VERSION 5.8 ;
BUSBITCHARS "[]" ;
DIVIDERCHAR "/" ;
UNITS
    DATABASE MICRONS 1000 ;
END UNITS

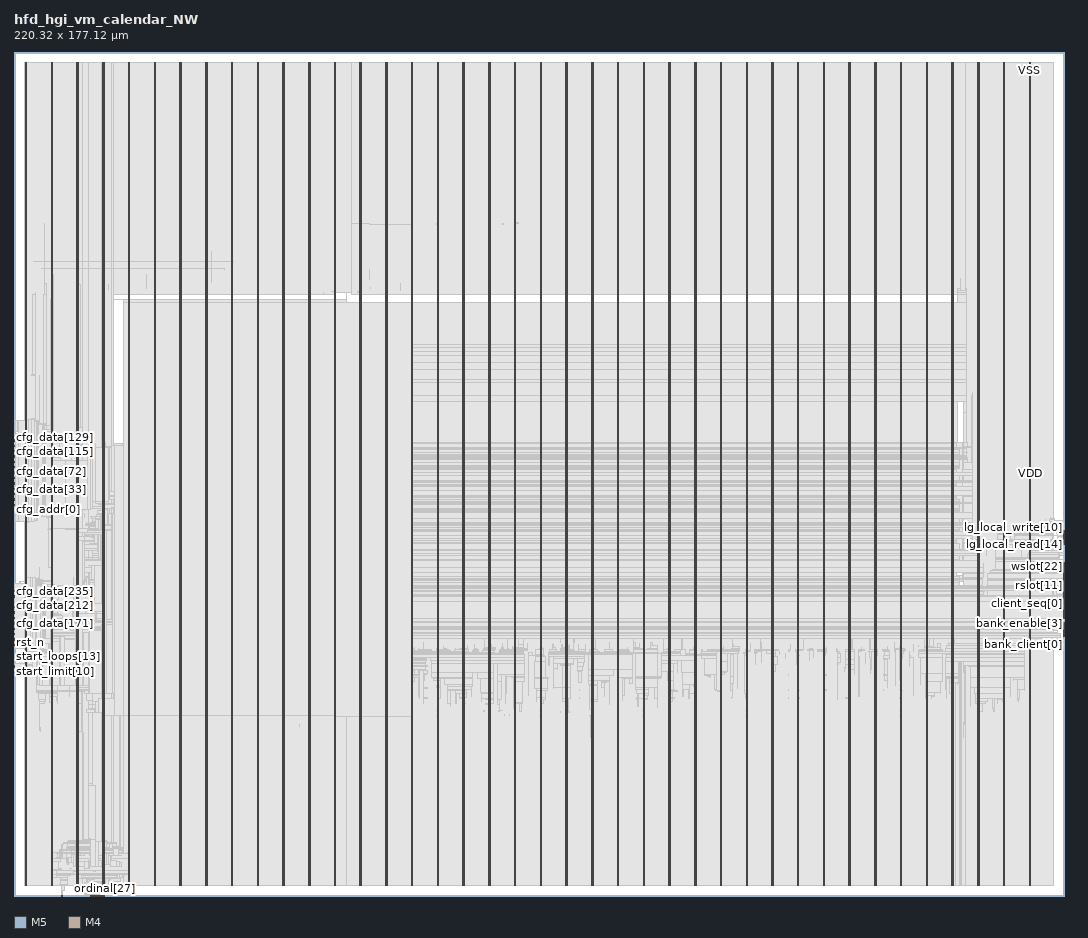
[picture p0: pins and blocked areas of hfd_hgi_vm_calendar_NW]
MACRO hfd_hgi_vm_calendar_NW
  FOREIGN hfd_hgi_vm_calendar_NW 0 0 ;
  CLASS BLOCK ;
  SIZE 220.32 BY 177.12 ;
  PIN active
    DIRECTION OUTPUT ;
    USE SIGNAL ;
    PORT
      LAYER M5 ;
        RECT  16.08 0 16.104 0.084 ;
    END
  END active
  PIN bank_client[0]
    DIRECTION OUTPUT ;
    USE SIGNAL ;
    PORT
      LAYER M4 ;
        RECT  220.236 54.48 220.32 54.504 ;
    END
  END bank_client[0]
  PIN bank_client[10]
    DIRECTION OUTPUT ;
    USE SIGNAL ;
    PORT
      LAYER M4 ;
        RECT  220.236 55.44 220.32 55.464 ;
    END
  END bank_client[10]
  PIN bank_client[11]
    DIRECTION OUTPUT ;
    USE SIGNAL ;
    PORT
      LAYER M4 ;
        RECT  220.236 55.536 220.32 55.56 ;
    END
  END bank_client[11]
  PIN bank_client[12]
    DIRECTION OUTPUT ;
    USE SIGNAL ;
    PORT
      LAYER M4 ;
        RECT  220.236 55.632 220.32 55.656 ;
    END
  END bank_client[12]
  PIN bank_client[13]
    DIRECTION OUTPUT ;
    USE SIGNAL ;
    PORT
      LAYER M4 ;
        RECT  220.236 55.728 220.32 55.752 ;
    END
  END bank_client[13]
  PIN bank_client[14]
    DIRECTION OUTPUT ;
    USE SIGNAL ;
    PORT
      LAYER M4 ;
        RECT  220.236 55.824 220.32 55.848 ;
    END
  END bank_client[14]
  PIN bank_client[15]
    DIRECTION OUTPUT ;
    USE SIGNAL ;
    PORT
      LAYER M4 ;
        RECT  220.236 55.92 220.32 55.944 ;
    END
  END bank_client[15]
  PIN bank_client[16]
    DIRECTION OUTPUT ;
    USE SIGNAL ;
    PORT
      LAYER M4 ;
        RECT  220.236 56.016 220.32 56.04 ;
    END
  END bank_client[16]
  PIN bank_client[17]
    DIRECTION OUTPUT ;
    USE SIGNAL ;
    PORT
      LAYER M4 ;
        RECT  220.236 56.112 220.32 56.136 ;
    END
  END bank_client[17]
  PIN bank_client[18]
    DIRECTION OUTPUT ;
    USE SIGNAL ;
    PORT
      LAYER M4 ;
        RECT  220.236 56.208 220.32 56.232 ;
    END
  END bank_client[18]
  PIN bank_client[19]
    DIRECTION OUTPUT ;
    USE SIGNAL ;
    PORT
      LAYER M4 ;
        RECT  220.236 56.304 220.32 56.328 ;
    END
  END bank_client[19]
  PIN bank_client[1]
    DIRECTION OUTPUT ;
    USE SIGNAL ;
    PORT
      LAYER M4 ;
        RECT  220.236 54.576 220.32 54.6 ;
    END
  END bank_client[1]
  PIN bank_client[20]
    DIRECTION OUTPUT ;
    USE SIGNAL ;
    PORT
      LAYER M4 ;
        RECT  220.236 56.4 220.32 56.424 ;
    END
  END bank_client[20]
  PIN bank_client[21]
    DIRECTION OUTPUT ;
    USE SIGNAL ;
    PORT
      LAYER M4 ;
        RECT  220.236 56.496 220.32 56.52 ;
    END
  END bank_client[21]
  PIN bank_client[22]
    DIRECTION OUTPUT ;
    USE SIGNAL ;
    PORT
      LAYER M4 ;
        RECT  220.236 56.592 220.32 56.616 ;
    END
  END bank_client[22]
  PIN bank_client[23]
    DIRECTION OUTPUT ;
    USE SIGNAL ;
    PORT
      LAYER M4 ;
        RECT  220.236 56.688 220.32 56.712 ;
    END
  END bank_client[23]
  PIN bank_client[2]
    DIRECTION OUTPUT ;
    USE SIGNAL ;
    PORT
      LAYER M4 ;
        RECT  220.236 54.672 220.32 54.696 ;
    END
  END bank_client[2]
  PIN bank_client[3]
    DIRECTION OUTPUT ;
    USE SIGNAL ;
    PORT
      LAYER M4 ;
        RECT  220.236 54.768 220.32 54.792 ;
    END
  END bank_client[3]
  PIN bank_client[4]
    DIRECTION OUTPUT ;
    USE SIGNAL ;
    PORT
      LAYER M4 ;
        RECT  220.236 54.864 220.32 54.888 ;
    END
  END bank_client[4]
  PIN bank_client[5]
    DIRECTION OUTPUT ;
    USE SIGNAL ;
    PORT
      LAYER M4 ;
        RECT  220.236 54.96 220.32 54.984 ;
    END
  END bank_client[5]
  PIN bank_client[6]
    DIRECTION OUTPUT ;
    USE SIGNAL ;
    PORT
      LAYER M4 ;
        RECT  220.236 55.056 220.32 55.08 ;
    END
  END bank_client[6]
  PIN bank_client[7]
    DIRECTION OUTPUT ;
    USE SIGNAL ;
    PORT
      LAYER M4 ;
        RECT  220.236 55.152 220.32 55.176 ;
    END
  END bank_client[7]
  PIN bank_client[8]
    DIRECTION OUTPUT ;
    USE SIGNAL ;
    PORT
      LAYER M4 ;
        RECT  220.236 55.248 220.32 55.272 ;
    END
  END bank_client[8]
  PIN bank_client[9]
    DIRECTION OUTPUT ;
    USE SIGNAL ;
    PORT
      LAYER M4 ;
        RECT  220.236 55.344 220.32 55.368 ;
    END
  END bank_client[9]
  PIN bank_enable[0]
    DIRECTION OUTPUT ;
    USE SIGNAL ;
    PORT
      LAYER M4 ;
        RECT  220.236 56.784 220.32 56.808 ;
    END
  END bank_enable[0]
  PIN bank_enable[1]
    DIRECTION OUTPUT ;
    USE SIGNAL ;
    PORT
      LAYER M4 ;
        RECT  220.236 56.88 220.32 56.904 ;
    END
  END bank_enable[1]
  PIN bank_enable[2]
    DIRECTION OUTPUT ;
    USE SIGNAL ;
    PORT
      LAYER M4 ;
        RECT  220.236 56.976 220.32 57 ;
    END
  END bank_enable[2]
  PIN bank_enable[3]
    DIRECTION OUTPUT ;
    USE SIGNAL ;
    PORT
      LAYER M4 ;
        RECT  220.236 57.072 220.32 57.096 ;
    END
  END bank_enable[3]
  PIN bank_enable[4]
    DIRECTION OUTPUT ;
    USE SIGNAL ;
    PORT
      LAYER M4 ;
        RECT  220.236 57.168 220.32 57.192 ;
    END
  END bank_enable[4]
  PIN bank_enable[5]
    DIRECTION OUTPUT ;
    USE SIGNAL ;
    PORT
      LAYER M4 ;
        RECT  220.236 57.264 220.32 57.288 ;
    END
  END bank_enable[5]
  PIN bank_enable[6]
    DIRECTION OUTPUT ;
    USE SIGNAL ;
    PORT
      LAYER M4 ;
        RECT  220.236 57.36 220.32 57.384 ;
    END
  END bank_enable[6]
  PIN bank_enable[7]
    DIRECTION OUTPUT ;
    USE SIGNAL ;
    PORT
      LAYER M4 ;
        RECT  220.236 57.456 220.32 57.48 ;
    END
  END bank_enable[7]
  PIN calendar_v
    DIRECTION OUTPUT ;
    USE SIGNAL ;
    PORT
      LAYER M5 ;
        RECT  16.176 0 16.2 0.084 ;
    END
  END calendar_v
  PIN cfg_addr[0]
    DIRECTION INPUT ;
    USE SIGNAL ;
    PORT
      LAYER M4 ;
        RECT  0 81.168 0.084 81.192 ;
    END
  END cfg_addr[0]
  PIN cfg_addr[1]
    DIRECTION INPUT ;
    USE SIGNAL ;
    PORT
      LAYER M4 ;
        RECT  0 81.264 0.084 81.288 ;
    END
  END cfg_addr[1]
  PIN cfg_addr[2]
    DIRECTION INPUT ;
    USE SIGNAL ;
    PORT
      LAYER M4 ;
        RECT  0 81.36 0.084 81.384 ;
    END
  END cfg_addr[2]
  PIN cfg_addr[3]
    DIRECTION INPUT ;
    USE SIGNAL ;
    PORT
      LAYER M4 ;
        RECT  0 81.456 0.084 81.48 ;
    END
  END cfg_addr[3]
  PIN cfg_addr[4]
    DIRECTION INPUT ;
    USE SIGNAL ;
    PORT
      LAYER M4 ;
        RECT  0 81.552 0.084 81.576 ;
    END
  END cfg_addr[4]
  PIN cfg_addr[5]
    DIRECTION INPUT ;
    USE SIGNAL ;
    PORT
      LAYER M4 ;
        RECT  0 81.648 0.084 81.672 ;
    END
  END cfg_addr[5]
  PIN cfg_addr[6]
    DIRECTION INPUT ;
    USE SIGNAL ;
    PORT
      LAYER M4 ;
        RECT  0 81.744 0.084 81.768 ;
    END
  END cfg_addr[6]
  PIN cfg_addr[7]
    DIRECTION INPUT ;
    USE SIGNAL ;
    PORT
      LAYER M4 ;
        RECT  0 81.84 0.084 81.864 ;
    END
  END cfg_addr[7]
  PIN cfg_addr[8]
    DIRECTION INPUT ;
    USE SIGNAL ;
    PORT
      LAYER M4 ;
        RECT  0 81.936 0.084 81.96 ;
    END
  END cfg_addr[8]
  PIN cfg_addr[9]
    DIRECTION INPUT ;
    USE SIGNAL ;
    PORT
      LAYER M4 ;
        RECT  0 82.032 0.084 82.056 ;
    END
  END cfg_addr[9]
  PIN cfg_data[0]
    DIRECTION INPUT ;
    USE SIGNAL ;
    PORT
      LAYER M4 ;
        RECT  0 82.128 0.084 82.152 ;
    END
  END cfg_data[0]
  PIN cfg_data[100]
    DIRECTION INPUT ;
    USE SIGNAL ;
    PORT
      LAYER M4 ;
        RECT  0 91.728 0.084 91.752 ;
    END
  END cfg_data[100]
  PIN cfg_data[101]
    DIRECTION INPUT ;
    USE SIGNAL ;
    PORT
      LAYER M4 ;
        RECT  0 91.824 0.084 91.848 ;
    END
  END cfg_data[101]
  PIN cfg_data[102]
    DIRECTION INPUT ;
    USE SIGNAL ;
    PORT
      LAYER M4 ;
        RECT  0 91.92 0.084 91.944 ;
    END
  END cfg_data[102]
  PIN cfg_data[103]
    DIRECTION INPUT ;
    USE SIGNAL ;
    PORT
      LAYER M4 ;
        RECT  0 92.016 0.084 92.04 ;
    END
  END cfg_data[103]
  PIN cfg_data[104]
    DIRECTION INPUT ;
    USE SIGNAL ;
    PORT
      LAYER M4 ;
        RECT  0 92.112 0.084 92.136 ;
    END
  END cfg_data[104]
  PIN cfg_data[105]
    DIRECTION INPUT ;
    USE SIGNAL ;
    PORT
      LAYER M4 ;
        RECT  0 92.208 0.084 92.232 ;
    END
  END cfg_data[105]
  PIN cfg_data[106]
    DIRECTION INPUT ;
    USE SIGNAL ;
    PORT
      LAYER M4 ;
        RECT  0 92.304 0.084 92.328 ;
    END
  END cfg_data[106]
  PIN cfg_data[107]
    DIRECTION INPUT ;
    USE SIGNAL ;
    PORT
      LAYER M4 ;
        RECT  0 92.4 0.084 92.424 ;
    END
  END cfg_data[107]
  PIN cfg_data[108]
    DIRECTION INPUT ;
    USE SIGNAL ;
    PORT
      LAYER M4 ;
        RECT  0 92.496 0.084 92.52 ;
    END
  END cfg_data[108]
  PIN cfg_data[109]
    DIRECTION INPUT ;
    USE SIGNAL ;
    PORT
      LAYER M4 ;
        RECT  0 92.592 0.084 92.616 ;
    END
  END cfg_data[109]
  PIN cfg_data[10]
    DIRECTION INPUT ;
    USE SIGNAL ;
    PORT
      LAYER M4 ;
        RECT  0 83.088 0.084 83.112 ;
    END
  END cfg_data[10]
  PIN cfg_data[110]
    DIRECTION INPUT ;
    USE SIGNAL ;
    PORT
      LAYER M4 ;
        RECT  0 92.688 0.084 92.712 ;
    END
  END cfg_data[110]
  PIN cfg_data[111]
    DIRECTION INPUT ;
    USE SIGNAL ;
    PORT
      LAYER M4 ;
        RECT  0 92.784 0.084 92.808 ;
    END
  END cfg_data[111]
  PIN cfg_data[112]
    DIRECTION INPUT ;
    USE SIGNAL ;
    PORT
      LAYER M4 ;
        RECT  0 92.88 0.084 92.904 ;
    END
  END cfg_data[112]
  PIN cfg_data[113]
    DIRECTION INPUT ;
    USE SIGNAL ;
    PORT
      LAYER M4 ;
        RECT  0 92.976 0.084 93 ;
    END
  END cfg_data[113]
  PIN cfg_data[114]
    DIRECTION INPUT ;
    USE SIGNAL ;
    PORT
      LAYER M4 ;
        RECT  0 93.072 0.084 93.096 ;
    END
  END cfg_data[114]
  PIN cfg_data[115]
    DIRECTION INPUT ;
    USE SIGNAL ;
    PORT
      LAYER M4 ;
        RECT  0 93.168 0.084 93.192 ;
    END
  END cfg_data[115]
  PIN cfg_data[116]
    DIRECTION INPUT ;
    USE SIGNAL ;
    PORT
      LAYER M4 ;
        RECT  0 93.264 0.084 93.288 ;
    END
  END cfg_data[116]
  PIN cfg_data[117]
    DIRECTION INPUT ;
    USE SIGNAL ;
    PORT
      LAYER M4 ;
        RECT  0 93.36 0.084 93.384 ;
    END
  END cfg_data[117]
  PIN cfg_data[118]
    DIRECTION INPUT ;
    USE SIGNAL ;
    PORT
      LAYER M4 ;
        RECT  0 93.456 0.084 93.48 ;
    END
  END cfg_data[118]
  PIN cfg_data[119]
    DIRECTION INPUT ;
    USE SIGNAL ;
    PORT
      LAYER M4 ;
        RECT  0 93.552 0.084 93.576 ;
    END
  END cfg_data[119]
  PIN cfg_data[11]
    DIRECTION INPUT ;
    USE SIGNAL ;
    PORT
      LAYER M4 ;
        RECT  0 83.184 0.084 83.208 ;
    END
  END cfg_data[11]
  PIN cfg_data[120]
    DIRECTION INPUT ;
    USE SIGNAL ;
    PORT
      LAYER M4 ;
        RECT  0 93.648 0.084 93.672 ;
    END
  END cfg_data[120]
  PIN cfg_data[121]
    DIRECTION INPUT ;
    USE SIGNAL ;
    PORT
      LAYER M4 ;
        RECT  0 93.744 0.084 93.768 ;
    END
  END cfg_data[121]
  PIN cfg_data[122]
    DIRECTION INPUT ;
    USE SIGNAL ;
    PORT
      LAYER M4 ;
        RECT  0 93.84 0.084 93.864 ;
    END
  END cfg_data[122]
  PIN cfg_data[123]
    DIRECTION INPUT ;
    USE SIGNAL ;
    PORT
      LAYER M4 ;
        RECT  0 93.936 0.084 93.96 ;
    END
  END cfg_data[123]
  PIN cfg_data[124]
    DIRECTION INPUT ;
    USE SIGNAL ;
    PORT
      LAYER M4 ;
        RECT  0 94.032 0.084 94.056 ;
    END
  END cfg_data[124]
  PIN cfg_data[125]
    DIRECTION INPUT ;
    USE SIGNAL ;
    PORT
      LAYER M4 ;
        RECT  0 94.128 0.084 94.152 ;
    END
  END cfg_data[125]
  PIN cfg_data[126]
    DIRECTION INPUT ;
    USE SIGNAL ;
    PORT
      LAYER M4 ;
        RECT  0 94.224 0.084 94.248 ;
    END
  END cfg_data[126]
  PIN cfg_data[127]
    DIRECTION INPUT ;
    USE SIGNAL ;
    PORT
      LAYER M4 ;
        RECT  0 94.32 0.084 94.344 ;
    END
  END cfg_data[127]
  PIN cfg_data[128]
    DIRECTION INPUT ;
    USE SIGNAL ;
    PORT
      LAYER M4 ;
        RECT  0 94.416 0.084 94.44 ;
    END
  END cfg_data[128]
  PIN cfg_data[129]
    DIRECTION INPUT ;
    USE SIGNAL ;
    PORT
      LAYER M4 ;
        RECT  0 94.512 0.084 94.536 ;
    END
  END cfg_data[129]
  PIN cfg_data[12]
    DIRECTION INPUT ;
    USE SIGNAL ;
    PORT
      LAYER M4 ;
        RECT  0 83.28 0.084 83.304 ;
    END
  END cfg_data[12]
  PIN cfg_data[130]
    DIRECTION INPUT ;
    USE SIGNAL ;
    PORT
      LAYER M4 ;
        RECT  0 94.608 0.084 94.632 ;
    END
  END cfg_data[130]
  PIN cfg_data[131]
    DIRECTION INPUT ;
    USE SIGNAL ;
    PORT
      LAYER M4 ;
        RECT  0 94.704 0.084 94.728 ;
    END
  END cfg_data[131]
  PIN cfg_data[132]
    DIRECTION INPUT ;
    USE SIGNAL ;
    PORT
      LAYER M4 ;
        RECT  0 94.8 0.084 94.824 ;
    END
  END cfg_data[132]
  PIN cfg_data[133]
    DIRECTION INPUT ;
    USE SIGNAL ;
    PORT
      LAYER M4 ;
        RECT  0 94.896 0.084 94.92 ;
    END
  END cfg_data[133]
  PIN cfg_data[134]
    DIRECTION INPUT ;
    USE SIGNAL ;
    PORT
      LAYER M4 ;
        RECT  0 94.992 0.084 95.016 ;
    END
  END cfg_data[134]
  PIN cfg_data[135]
    DIRECTION INPUT ;
    USE SIGNAL ;
    PORT
      LAYER M4 ;
        RECT  0 95.088 0.084 95.112 ;
    END
  END cfg_data[135]
  PIN cfg_data[136]
    DIRECTION INPUT ;
    USE SIGNAL ;
    PORT
      LAYER M4 ;
        RECT  0 95.184 0.084 95.208 ;
    END
  END cfg_data[136]
  PIN cfg_data[137]
    DIRECTION INPUT ;
    USE SIGNAL ;
    PORT
      LAYER M4 ;
        RECT  0 95.28 0.084 95.304 ;
    END
  END cfg_data[137]
  PIN cfg_data[138]
    DIRECTION INPUT ;
    USE SIGNAL ;
    PORT
      LAYER M4 ;
        RECT  0 95.376 0.084 95.4 ;
    END
  END cfg_data[138]
  PIN cfg_data[139]
    DIRECTION INPUT ;
    USE SIGNAL ;
    PORT
      LAYER M4 ;
        RECT  0 95.472 0.084 95.496 ;
    END
  END cfg_data[139]
  PIN cfg_data[13]
    DIRECTION INPUT ;
    USE SIGNAL ;
    PORT
      LAYER M4 ;
        RECT  0 83.376 0.084 83.4 ;
    END
  END cfg_data[13]
  PIN cfg_data[140]
    DIRECTION INPUT ;
    USE SIGNAL ;
    PORT
      LAYER M4 ;
        RECT  0 95.568 0.084 95.592 ;
    END
  END cfg_data[140]
  PIN cfg_data[141]
    DIRECTION INPUT ;
    USE SIGNAL ;
    PORT
      LAYER M4 ;
        RECT  0 95.664 0.084 95.688 ;
    END
  END cfg_data[141]
  PIN cfg_data[142]
    DIRECTION INPUT ;
    USE SIGNAL ;
    PORT
      LAYER M4 ;
        RECT  0 95.76 0.084 95.784 ;
    END
  END cfg_data[142]
  PIN cfg_data[143]
    DIRECTION INPUT ;
    USE SIGNAL ;
    PORT
      LAYER M4 ;
        RECT  0 95.856 0.084 95.88 ;
    END
  END cfg_data[143]
  PIN cfg_data[144]
    DIRECTION INPUT ;
    USE SIGNAL ;
    PORT
      LAYER M4 ;
        RECT  0 95.952 0.084 95.976 ;
    END
  END cfg_data[144]
  PIN cfg_data[145]
    DIRECTION INPUT ;
    USE SIGNAL ;
    PORT
      LAYER M4 ;
        RECT  0 96.048 0.084 96.072 ;
    END
  END cfg_data[145]
  PIN cfg_data[146]
    DIRECTION INPUT ;
    USE SIGNAL ;
    PORT
      LAYER M4 ;
        RECT  0 96.144 0.084 96.168 ;
    END
  END cfg_data[146]
  PIN cfg_data[147]
    DIRECTION INPUT ;
    USE SIGNAL ;
    PORT
      LAYER M4 ;
        RECT  0 96.24 0.084 96.264 ;
    END
  END cfg_data[147]
  PIN cfg_data[148]
    DIRECTION INPUT ;
    USE SIGNAL ;
    PORT
      LAYER M4 ;
        RECT  0 96.336 0.084 96.36 ;
    END
  END cfg_data[148]
  PIN cfg_data[149]
    DIRECTION INPUT ;
    USE SIGNAL ;
    PORT
      LAYER M4 ;
        RECT  0 96.432 0.084 96.456 ;
    END
  END cfg_data[149]
  PIN cfg_data[14]
    DIRECTION INPUT ;
    USE SIGNAL ;
    PORT
      LAYER M4 ;
        RECT  0 83.472 0.084 83.496 ;
    END
  END cfg_data[14]
  PIN cfg_data[150]
    DIRECTION INPUT ;
    USE SIGNAL ;
    PORT
      LAYER M4 ;
        RECT  0 55.056 0.084 55.08 ;
    END
  END cfg_data[150]
  PIN cfg_data[151]
    DIRECTION INPUT ;
    USE SIGNAL ;
    PORT
      LAYER M4 ;
        RECT  0 55.152 0.084 55.176 ;
    END
  END cfg_data[151]
  PIN cfg_data[152]
    DIRECTION INPUT ;
    USE SIGNAL ;
    PORT
      LAYER M4 ;
        RECT  0 55.248 0.084 55.272 ;
    END
  END cfg_data[152]
  PIN cfg_data[153]
    DIRECTION INPUT ;
    USE SIGNAL ;
    PORT
      LAYER M4 ;
        RECT  0 55.344 0.084 55.368 ;
    END
  END cfg_data[153]
  PIN cfg_data[154]
    DIRECTION INPUT ;
    USE SIGNAL ;
    PORT
      LAYER M4 ;
        RECT  0 55.44 0.084 55.464 ;
    END
  END cfg_data[154]
  PIN cfg_data[155]
    DIRECTION INPUT ;
    USE SIGNAL ;
    PORT
      LAYER M4 ;
        RECT  0 55.536 0.084 55.56 ;
    END
  END cfg_data[155]
  PIN cfg_data[156]
    DIRECTION INPUT ;
    USE SIGNAL ;
    PORT
      LAYER M4 ;
        RECT  0 55.632 0.084 55.656 ;
    END
  END cfg_data[156]
  PIN cfg_data[157]
    DIRECTION INPUT ;
    USE SIGNAL ;
    PORT
      LAYER M4 ;
        RECT  0 55.728 0.084 55.752 ;
    END
  END cfg_data[157]
  PIN cfg_data[158]
    DIRECTION INPUT ;
    USE SIGNAL ;
    PORT
      LAYER M4 ;
        RECT  0 55.824 0.084 55.848 ;
    END
  END cfg_data[158]
  PIN cfg_data[159]
    DIRECTION INPUT ;
    USE SIGNAL ;
    PORT
      LAYER M4 ;
        RECT  0 55.92 0.084 55.944 ;
    END
  END cfg_data[159]
  PIN cfg_data[15]
    DIRECTION INPUT ;
    USE SIGNAL ;
    PORT
      LAYER M4 ;
        RECT  0 83.568 0.084 83.592 ;
    END
  END cfg_data[15]
  PIN cfg_data[160]
    DIRECTION INPUT ;
    USE SIGNAL ;
    PORT
      LAYER M4 ;
        RECT  0 56.016 0.084 56.04 ;
    END
  END cfg_data[160]
  PIN cfg_data[161]
    DIRECTION INPUT ;
    USE SIGNAL ;
    PORT
      LAYER M4 ;
        RECT  0 56.112 0.084 56.136 ;
    END
  END cfg_data[161]
  PIN cfg_data[162]
    DIRECTION INPUT ;
    USE SIGNAL ;
    PORT
      LAYER M4 ;
        RECT  0 56.208 0.084 56.232 ;
    END
  END cfg_data[162]
  PIN cfg_data[163]
    DIRECTION INPUT ;
    USE SIGNAL ;
    PORT
      LAYER M4 ;
        RECT  0 56.304 0.084 56.328 ;
    END
  END cfg_data[163]
  PIN cfg_data[164]
    DIRECTION INPUT ;
    USE SIGNAL ;
    PORT
      LAYER M4 ;
        RECT  0 56.4 0.084 56.424 ;
    END
  END cfg_data[164]
  PIN cfg_data[165]
    DIRECTION INPUT ;
    USE SIGNAL ;
    PORT
      LAYER M4 ;
        RECT  0 56.496 0.084 56.52 ;
    END
  END cfg_data[165]
  PIN cfg_data[166]
    DIRECTION INPUT ;
    USE SIGNAL ;
    PORT
      LAYER M4 ;
        RECT  0 56.592 0.084 56.616 ;
    END
  END cfg_data[166]
  PIN cfg_data[167]
    DIRECTION INPUT ;
    USE SIGNAL ;
    PORT
      LAYER M4 ;
        RECT  0 56.688 0.084 56.712 ;
    END
  END cfg_data[167]
  PIN cfg_data[168]
    DIRECTION INPUT ;
    USE SIGNAL ;
    PORT
      LAYER M4 ;
        RECT  0 56.784 0.084 56.808 ;
    END
  END cfg_data[168]
  PIN cfg_data[169]
    DIRECTION INPUT ;
    USE SIGNAL ;
    PORT
      LAYER M4 ;
        RECT  0 56.88 0.084 56.904 ;
    END
  END cfg_data[169]
  PIN cfg_data[16]
    DIRECTION INPUT ;
    USE SIGNAL ;
    PORT
      LAYER M4 ;
        RECT  0 83.664 0.084 83.688 ;
    END
  END cfg_data[16]
  PIN cfg_data[170]
    DIRECTION INPUT ;
    USE SIGNAL ;
    PORT
      LAYER M4 ;
        RECT  0 56.976 0.084 57 ;
    END
  END cfg_data[170]
  PIN cfg_data[171]
    DIRECTION INPUT ;
    USE SIGNAL ;
    PORT
      LAYER M4 ;
        RECT  0 57.072 0.084 57.096 ;
    END
  END cfg_data[171]
  PIN cfg_data[172]
    DIRECTION INPUT ;
    USE SIGNAL ;
    PORT
      LAYER M4 ;
        RECT  0 57.168 0.084 57.192 ;
    END
  END cfg_data[172]
  PIN cfg_data[173]
    DIRECTION INPUT ;
    USE SIGNAL ;
    PORT
      LAYER M4 ;
        RECT  0 57.264 0.084 57.288 ;
    END
  END cfg_data[173]
  PIN cfg_data[174]
    DIRECTION INPUT ;
    USE SIGNAL ;
    PORT
      LAYER M4 ;
        RECT  0 57.36 0.084 57.384 ;
    END
  END cfg_data[174]
  PIN cfg_data[175]
    DIRECTION INPUT ;
    USE SIGNAL ;
    PORT
      LAYER M4 ;
        RECT  0 57.456 0.084 57.48 ;
    END
  END cfg_data[175]
  PIN cfg_data[176]
    DIRECTION INPUT ;
    USE SIGNAL ;
    PORT
      LAYER M4 ;
        RECT  0 57.552 0.084 57.576 ;
    END
  END cfg_data[176]
  PIN cfg_data[177]
    DIRECTION INPUT ;
    USE SIGNAL ;
    PORT
      LAYER M4 ;
        RECT  0 57.648 0.084 57.672 ;
    END
  END cfg_data[177]
  PIN cfg_data[178]
    DIRECTION INPUT ;
    USE SIGNAL ;
    PORT
      LAYER M4 ;
        RECT  0 57.744 0.084 57.768 ;
    END
  END cfg_data[178]
  PIN cfg_data[179]
    DIRECTION INPUT ;
    USE SIGNAL ;
    PORT
      LAYER M4 ;
        RECT  0 57.84 0.084 57.864 ;
    END
  END cfg_data[179]
  PIN cfg_data[17]
    DIRECTION INPUT ;
    USE SIGNAL ;
    PORT
      LAYER M4 ;
        RECT  0 83.76 0.084 83.784 ;
    END
  END cfg_data[17]
  PIN cfg_data[180]
    DIRECTION INPUT ;
    USE SIGNAL ;
    PORT
      LAYER M4 ;
        RECT  0 57.936 0.084 57.96 ;
    END
  END cfg_data[180]
  PIN cfg_data[181]
    DIRECTION INPUT ;
    USE SIGNAL ;
    PORT
      LAYER M4 ;
        RECT  0 58.032 0.084 58.056 ;
    END
  END cfg_data[181]
  PIN cfg_data[182]
    DIRECTION INPUT ;
    USE SIGNAL ;
    PORT
      LAYER M4 ;
        RECT  0 58.128 0.084 58.152 ;
    END
  END cfg_data[182]
  PIN cfg_data[183]
    DIRECTION INPUT ;
    USE SIGNAL ;
    PORT
      LAYER M4 ;
        RECT  0 58.224 0.084 58.248 ;
    END
  END cfg_data[183]
  PIN cfg_data[184]
    DIRECTION INPUT ;
    USE SIGNAL ;
    PORT
      LAYER M4 ;
        RECT  0 58.32 0.084 58.344 ;
    END
  END cfg_data[184]
  PIN cfg_data[185]
    DIRECTION INPUT ;
    USE SIGNAL ;
    PORT
      LAYER M4 ;
        RECT  0 58.416 0.084 58.44 ;
    END
  END cfg_data[185]
  PIN cfg_data[186]
    DIRECTION INPUT ;
    USE SIGNAL ;
    PORT
      LAYER M4 ;
        RECT  0 58.512 0.084 58.536 ;
    END
  END cfg_data[186]
  PIN cfg_data[187]
    DIRECTION INPUT ;
    USE SIGNAL ;
    PORT
      LAYER M4 ;
        RECT  0 58.608 0.084 58.632 ;
    END
  END cfg_data[187]
  PIN cfg_data[188]
    DIRECTION INPUT ;
    USE SIGNAL ;
    PORT
      LAYER M4 ;
        RECT  0 58.704 0.084 58.728 ;
    END
  END cfg_data[188]
  PIN cfg_data[189]
    DIRECTION INPUT ;
    USE SIGNAL ;
    PORT
      LAYER M4 ;
        RECT  0 58.8 0.084 58.824 ;
    END
  END cfg_data[189]
  PIN cfg_data[18]
    DIRECTION INPUT ;
    USE SIGNAL ;
    PORT
      LAYER M4 ;
        RECT  0 83.856 0.084 83.88 ;
    END
  END cfg_data[18]
  PIN cfg_data[190]
    DIRECTION INPUT ;
    USE SIGNAL ;
    PORT
      LAYER M4 ;
        RECT  0 58.896 0.084 58.92 ;
    END
  END cfg_data[190]
  PIN cfg_data[191]
    DIRECTION INPUT ;
    USE SIGNAL ;
    PORT
      LAYER M4 ;
        RECT  0 58.992 0.084 59.016 ;
    END
  END cfg_data[191]
  PIN cfg_data[192]
    DIRECTION INPUT ;
    USE SIGNAL ;
    PORT
      LAYER M4 ;
        RECT  0 59.088 0.084 59.112 ;
    END
  END cfg_data[192]
  PIN cfg_data[193]
    DIRECTION INPUT ;
    USE SIGNAL ;
    PORT
      LAYER M4 ;
        RECT  0 59.184 0.084 59.208 ;
    END
  END cfg_data[193]
  PIN cfg_data[194]
    DIRECTION INPUT ;
    USE SIGNAL ;
    PORT
      LAYER M4 ;
        RECT  0 59.28 0.084 59.304 ;
    END
  END cfg_data[194]
  PIN cfg_data[195]
    DIRECTION INPUT ;
    USE SIGNAL ;
    PORT
      LAYER M4 ;
        RECT  0 59.376 0.084 59.4 ;
    END
  END cfg_data[195]
  PIN cfg_data[196]
    DIRECTION INPUT ;
    USE SIGNAL ;
    PORT
      LAYER M4 ;
        RECT  0 59.472 0.084 59.496 ;
    END
  END cfg_data[196]
  PIN cfg_data[197]
    DIRECTION INPUT ;
    USE SIGNAL ;
    PORT
      LAYER M4 ;
        RECT  0 59.568 0.084 59.592 ;
    END
  END cfg_data[197]
  PIN cfg_data[198]
    DIRECTION INPUT ;
    USE SIGNAL ;
    PORT
      LAYER M4 ;
        RECT  0 59.664 0.084 59.688 ;
    END
  END cfg_data[198]
  PIN cfg_data[199]
    DIRECTION INPUT ;
    USE SIGNAL ;
    PORT
      LAYER M4 ;
        RECT  0 59.76 0.084 59.784 ;
    END
  END cfg_data[199]
  PIN cfg_data[19]
    DIRECTION INPUT ;
    USE SIGNAL ;
    PORT
      LAYER M4 ;
        RECT  0 83.952 0.084 83.976 ;
    END
  END cfg_data[19]
  PIN cfg_data[1]
    DIRECTION INPUT ;
    USE SIGNAL ;
    PORT
      LAYER M4 ;
        RECT  0 82.224 0.084 82.248 ;
    END
  END cfg_data[1]
  PIN cfg_data[200]
    DIRECTION INPUT ;
    USE SIGNAL ;
    PORT
      LAYER M4 ;
        RECT  0 59.856 0.084 59.88 ;
    END
  END cfg_data[200]
  PIN cfg_data[201]
    DIRECTION INPUT ;
    USE SIGNAL ;
    PORT
      LAYER M4 ;
        RECT  0 59.952 0.084 59.976 ;
    END
  END cfg_data[201]
  PIN cfg_data[202]
    DIRECTION INPUT ;
    USE SIGNAL ;
    PORT
      LAYER M4 ;
        RECT  0 60.048 0.084 60.072 ;
    END
  END cfg_data[202]
  PIN cfg_data[203]
    DIRECTION INPUT ;
    USE SIGNAL ;
    PORT
      LAYER M4 ;
        RECT  0 60.144 0.084 60.168 ;
    END
  END cfg_data[203]
  PIN cfg_data[204]
    DIRECTION INPUT ;
    USE SIGNAL ;
    PORT
      LAYER M4 ;
        RECT  0 60.24 0.084 60.264 ;
    END
  END cfg_data[204]
  PIN cfg_data[205]
    DIRECTION INPUT ;
    USE SIGNAL ;
    PORT
      LAYER M4 ;
        RECT  0 60.336 0.084 60.36 ;
    END
  END cfg_data[205]
  PIN cfg_data[206]
    DIRECTION INPUT ;
    USE SIGNAL ;
    PORT
      LAYER M4 ;
        RECT  0 60.432 0.084 60.456 ;
    END
  END cfg_data[206]
  PIN cfg_data[207]
    DIRECTION INPUT ;
    USE SIGNAL ;
    PORT
      LAYER M4 ;
        RECT  0 60.528 0.084 60.552 ;
    END
  END cfg_data[207]
  PIN cfg_data[208]
    DIRECTION INPUT ;
    USE SIGNAL ;
    PORT
      LAYER M4 ;
        RECT  0 60.624 0.084 60.648 ;
    END
  END cfg_data[208]
  PIN cfg_data[209]
    DIRECTION INPUT ;
    USE SIGNAL ;
    PORT
      LAYER M4 ;
        RECT  0 60.72 0.084 60.744 ;
    END
  END cfg_data[209]
  PIN cfg_data[20]
    DIRECTION INPUT ;
    USE SIGNAL ;
    PORT
      LAYER M4 ;
        RECT  0 84.048 0.084 84.072 ;
    END
  END cfg_data[20]
  PIN cfg_data[210]
    DIRECTION INPUT ;
    USE SIGNAL ;
    PORT
      LAYER M4 ;
        RECT  0 60.816 0.084 60.84 ;
    END
  END cfg_data[210]
  PIN cfg_data[211]
    DIRECTION INPUT ;
    USE SIGNAL ;
    PORT
      LAYER M4 ;
        RECT  0 60.912 0.084 60.936 ;
    END
  END cfg_data[211]
  PIN cfg_data[212]
    DIRECTION INPUT ;
    USE SIGNAL ;
    PORT
      LAYER M4 ;
        RECT  0 61.008 0.084 61.032 ;
    END
  END cfg_data[212]
  PIN cfg_data[213]
    DIRECTION INPUT ;
    USE SIGNAL ;
    PORT
      LAYER M4 ;
        RECT  0 61.104 0.084 61.128 ;
    END
  END cfg_data[213]
  PIN cfg_data[214]
    DIRECTION INPUT ;
    USE SIGNAL ;
    PORT
      LAYER M4 ;
        RECT  0 61.968 0.084 61.992 ;
    END
  END cfg_data[214]
  PIN cfg_data[215]
    DIRECTION INPUT ;
    USE SIGNAL ;
    PORT
      LAYER M4 ;
        RECT  0 62.064 0.084 62.088 ;
    END
  END cfg_data[215]
  PIN cfg_data[216]
    DIRECTION INPUT ;
    USE SIGNAL ;
    PORT
      LAYER M4 ;
        RECT  0 62.16 0.084 62.184 ;
    END
  END cfg_data[216]
  PIN cfg_data[217]
    DIRECTION INPUT ;
    USE SIGNAL ;
    PORT
      LAYER M4 ;
        RECT  0 62.256 0.084 62.28 ;
    END
  END cfg_data[217]
  PIN cfg_data[218]
    DIRECTION INPUT ;
    USE SIGNAL ;
    PORT
      LAYER M4 ;
        RECT  0 62.352 0.084 62.376 ;
    END
  END cfg_data[218]
  PIN cfg_data[219]
    DIRECTION INPUT ;
    USE SIGNAL ;
    PORT
      LAYER M4 ;
        RECT  0 62.448 0.084 62.472 ;
    END
  END cfg_data[219]
  PIN cfg_data[21]
    DIRECTION INPUT ;
    USE SIGNAL ;
    PORT
      LAYER M4 ;
        RECT  0 84.144 0.084 84.168 ;
    END
  END cfg_data[21]
  PIN cfg_data[220]
    DIRECTION INPUT ;
    USE SIGNAL ;
    PORT
      LAYER M4 ;
        RECT  0 62.544 0.084 62.568 ;
    END
  END cfg_data[220]
  PIN cfg_data[221]
    DIRECTION INPUT ;
    USE SIGNAL ;
    PORT
      LAYER M4 ;
        RECT  0 62.64 0.084 62.664 ;
    END
  END cfg_data[221]
  PIN cfg_data[222]
    DIRECTION INPUT ;
    USE SIGNAL ;
    PORT
      LAYER M4 ;
        RECT  0 62.736 0.084 62.76 ;
    END
  END cfg_data[222]
  PIN cfg_data[223]
    DIRECTION INPUT ;
    USE SIGNAL ;
    PORT
      LAYER M4 ;
        RECT  0 62.832 0.084 62.856 ;
    END
  END cfg_data[223]
  PIN cfg_data[224]
    DIRECTION INPUT ;
    USE SIGNAL ;
    PORT
      LAYER M4 ;
        RECT  0 62.928 0.084 62.952 ;
    END
  END cfg_data[224]
  PIN cfg_data[225]
    DIRECTION INPUT ;
    USE SIGNAL ;
    PORT
      LAYER M4 ;
        RECT  0 63.024 0.084 63.048 ;
    END
  END cfg_data[225]
  PIN cfg_data[226]
    DIRECTION INPUT ;
    USE SIGNAL ;
    PORT
      LAYER M4 ;
        RECT  0 63.12 0.084 63.144 ;
    END
  END cfg_data[226]
  PIN cfg_data[227]
    DIRECTION INPUT ;
    USE SIGNAL ;
    PORT
      LAYER M4 ;
        RECT  0 63.216 0.084 63.24 ;
    END
  END cfg_data[227]
  PIN cfg_data[228]
    DIRECTION INPUT ;
    USE SIGNAL ;
    PORT
      LAYER M4 ;
        RECT  0 63.312 0.084 63.336 ;
    END
  END cfg_data[228]
  PIN cfg_data[229]
    DIRECTION INPUT ;
    USE SIGNAL ;
    PORT
      LAYER M4 ;
        RECT  0 63.408 0.084 63.432 ;
    END
  END cfg_data[229]
  PIN cfg_data[22]
    DIRECTION INPUT ;
    USE SIGNAL ;
    PORT
      LAYER M4 ;
        RECT  0 84.24 0.084 84.264 ;
    END
  END cfg_data[22]
  PIN cfg_data[230]
    DIRECTION INPUT ;
    USE SIGNAL ;
    PORT
      LAYER M4 ;
        RECT  0 63.504 0.084 63.528 ;
    END
  END cfg_data[230]
  PIN cfg_data[231]
    DIRECTION INPUT ;
    USE SIGNAL ;
    PORT
      LAYER M4 ;
        RECT  0 63.6 0.084 63.624 ;
    END
  END cfg_data[231]
  PIN cfg_data[232]
    DIRECTION INPUT ;
    USE SIGNAL ;
    PORT
      LAYER M4 ;
        RECT  0 63.696 0.084 63.72 ;
    END
  END cfg_data[232]
  PIN cfg_data[233]
    DIRECTION INPUT ;
    USE SIGNAL ;
    PORT
      LAYER M4 ;
        RECT  0 63.792 0.084 63.816 ;
    END
  END cfg_data[233]
  PIN cfg_data[234]
    DIRECTION INPUT ;
    USE SIGNAL ;
    PORT
      LAYER M4 ;
        RECT  0 63.888 0.084 63.912 ;
    END
  END cfg_data[234]
  PIN cfg_data[235]
    DIRECTION INPUT ;
    USE SIGNAL ;
    PORT
      LAYER M4 ;
        RECT  0 63.984 0.084 64.008 ;
    END
  END cfg_data[235]
  PIN cfg_data[236]
    DIRECTION INPUT ;
    USE SIGNAL ;
    PORT
      LAYER M4 ;
        RECT  0 64.08 0.084 64.104 ;
    END
  END cfg_data[236]
  PIN cfg_data[237]
    DIRECTION INPUT ;
    USE SIGNAL ;
    PORT
      LAYER M4 ;
        RECT  0 64.176 0.084 64.2 ;
    END
  END cfg_data[237]
  PIN cfg_data[238]
    DIRECTION INPUT ;
    USE SIGNAL ;
    PORT
      LAYER M4 ;
        RECT  0 64.272 0.084 64.296 ;
    END
  END cfg_data[238]
  PIN cfg_data[239]
    DIRECTION INPUT ;
    USE SIGNAL ;
    PORT
      LAYER M4 ;
        RECT  0 64.368 0.084 64.392 ;
    END
  END cfg_data[239]
  PIN cfg_data[23]
    DIRECTION INPUT ;
    USE SIGNAL ;
    PORT
      LAYER M4 ;
        RECT  0 84.336 0.084 84.36 ;
    END
  END cfg_data[23]
  PIN cfg_data[240]
    DIRECTION INPUT ;
    USE SIGNAL ;
    PORT
      LAYER M4 ;
        RECT  0 64.464 0.084 64.488 ;
    END
  END cfg_data[240]
  PIN cfg_data[241]
    DIRECTION INPUT ;
    USE SIGNAL ;
    PORT
      LAYER M4 ;
        RECT  0 64.56 0.084 64.584 ;
    END
  END cfg_data[241]
  PIN cfg_data[242]
    DIRECTION INPUT ;
    USE SIGNAL ;
    PORT
      LAYER M4 ;
        RECT  0 64.656 0.084 64.68 ;
    END
  END cfg_data[242]
  PIN cfg_data[243]
    DIRECTION INPUT ;
    USE SIGNAL ;
    PORT
      LAYER M4 ;
        RECT  0 64.752 0.084 64.776 ;
    END
  END cfg_data[243]
  PIN cfg_data[244]
    DIRECTION INPUT ;
    USE SIGNAL ;
    PORT
      LAYER M4 ;
        RECT  0 64.848 0.084 64.872 ;
    END
  END cfg_data[244]
  PIN cfg_data[245]
    DIRECTION INPUT ;
    USE SIGNAL ;
    PORT
      LAYER M4 ;
        RECT  0 64.944 0.084 64.968 ;
    END
  END cfg_data[245]
  PIN cfg_data[246]
    DIRECTION INPUT ;
    USE SIGNAL ;
    PORT
      LAYER M4 ;
        RECT  0 51.984 0.084 52.008 ;
    END
  END cfg_data[246]
  PIN cfg_data[247]
    DIRECTION INPUT ;
    USE SIGNAL ;
    PORT
      LAYER M4 ;
        RECT  0 52.08 0.084 52.104 ;
    END
  END cfg_data[247]
  PIN cfg_data[248]
    DIRECTION INPUT ;
    USE SIGNAL ;
    PORT
      LAYER M4 ;
        RECT  0 52.176 0.084 52.2 ;
    END
  END cfg_data[248]
  PIN cfg_data[249]
    DIRECTION INPUT ;
    USE SIGNAL ;
    PORT
      LAYER M4 ;
        RECT  0 52.272 0.084 52.296 ;
    END
  END cfg_data[249]
  PIN cfg_data[24]
    DIRECTION INPUT ;
    USE SIGNAL ;
    PORT
      LAYER M4 ;
        RECT  0 84.432 0.084 84.456 ;
    END
  END cfg_data[24]
  PIN cfg_data[250]
    DIRECTION INPUT ;
    USE SIGNAL ;
    PORT
      LAYER M4 ;
        RECT  0 52.368 0.084 52.392 ;
    END
  END cfg_data[250]
  PIN cfg_data[251]
    DIRECTION INPUT ;
    USE SIGNAL ;
    PORT
      LAYER M4 ;
        RECT  0 52.464 0.084 52.488 ;
    END
  END cfg_data[251]
  PIN cfg_data[252]
    DIRECTION INPUT ;
    USE SIGNAL ;
    PORT
      LAYER M4 ;
        RECT  0 52.56 0.084 52.584 ;
    END
  END cfg_data[252]
  PIN cfg_data[253]
    DIRECTION INPUT ;
    USE SIGNAL ;
    PORT
      LAYER M4 ;
        RECT  0 52.656 0.084 52.68 ;
    END
  END cfg_data[253]
  PIN cfg_data[254]
    DIRECTION INPUT ;
    USE SIGNAL ;
    PORT
      LAYER M4 ;
        RECT  0 52.752 0.084 52.776 ;
    END
  END cfg_data[254]
  PIN cfg_data[255]
    DIRECTION INPUT ;
    USE SIGNAL ;
    PORT
      LAYER M4 ;
        RECT  0 52.848 0.084 52.872 ;
    END
  END cfg_data[255]
  PIN cfg_data[25]
    DIRECTION INPUT ;
    USE SIGNAL ;
    PORT
      LAYER M4 ;
        RECT  0 84.528 0.084 84.552 ;
    END
  END cfg_data[25]
  PIN cfg_data[26]
    DIRECTION INPUT ;
    USE SIGNAL ;
    PORT
      LAYER M4 ;
        RECT  0 84.624 0.084 84.648 ;
    END
  END cfg_data[26]
  PIN cfg_data[27]
    DIRECTION INPUT ;
    USE SIGNAL ;
    PORT
      LAYER M4 ;
        RECT  0 84.72 0.084 84.744 ;
    END
  END cfg_data[27]
  PIN cfg_data[28]
    DIRECTION INPUT ;
    USE SIGNAL ;
    PORT
      LAYER M4 ;
        RECT  0 84.816 0.084 84.84 ;
    END
  END cfg_data[28]
  PIN cfg_data[29]
    DIRECTION INPUT ;
    USE SIGNAL ;
    PORT
      LAYER M4 ;
        RECT  0 84.912 0.084 84.936 ;
    END
  END cfg_data[29]
  PIN cfg_data[2]
    DIRECTION INPUT ;
    USE SIGNAL ;
    PORT
      LAYER M4 ;
        RECT  0 82.32 0.084 82.344 ;
    END
  END cfg_data[2]
  PIN cfg_data[30]
    DIRECTION INPUT ;
    USE SIGNAL ;
    PORT
      LAYER M4 ;
        RECT  0 85.008 0.084 85.032 ;
    END
  END cfg_data[30]
  PIN cfg_data[31]
    DIRECTION INPUT ;
    USE SIGNAL ;
    PORT
      LAYER M4 ;
        RECT  0 85.104 0.084 85.128 ;
    END
  END cfg_data[31]
  PIN cfg_data[32]
    DIRECTION INPUT ;
    USE SIGNAL ;
    PORT
      LAYER M4 ;
        RECT  0 85.2 0.084 85.224 ;
    END
  END cfg_data[32]
  PIN cfg_data[33]
    DIRECTION INPUT ;
    USE SIGNAL ;
    PORT
      LAYER M4 ;
        RECT  0 85.296 0.084 85.32 ;
    END
  END cfg_data[33]
  PIN cfg_data[34]
    DIRECTION INPUT ;
    USE SIGNAL ;
    PORT
      LAYER M4 ;
        RECT  0 85.392 0.084 85.416 ;
    END
  END cfg_data[34]
  PIN cfg_data[35]
    DIRECTION INPUT ;
    USE SIGNAL ;
    PORT
      LAYER M4 ;
        RECT  0 85.488 0.084 85.512 ;
    END
  END cfg_data[35]
  PIN cfg_data[36]
    DIRECTION INPUT ;
    USE SIGNAL ;
    PORT
      LAYER M4 ;
        RECT  0 85.584 0.084 85.608 ;
    END
  END cfg_data[36]
  PIN cfg_data[37]
    DIRECTION INPUT ;
    USE SIGNAL ;
    PORT
      LAYER M4 ;
        RECT  0 85.68 0.084 85.704 ;
    END
  END cfg_data[37]
  PIN cfg_data[38]
    DIRECTION INPUT ;
    USE SIGNAL ;
    PORT
      LAYER M4 ;
        RECT  0 85.776 0.084 85.8 ;
    END
  END cfg_data[38]
  PIN cfg_data[39]
    DIRECTION INPUT ;
    USE SIGNAL ;
    PORT
      LAYER M4 ;
        RECT  0 85.872 0.084 85.896 ;
    END
  END cfg_data[39]
  PIN cfg_data[3]
    DIRECTION INPUT ;
    USE SIGNAL ;
    PORT
      LAYER M4 ;
        RECT  0 82.416 0.084 82.44 ;
    END
  END cfg_data[3]
  PIN cfg_data[40]
    DIRECTION INPUT ;
    USE SIGNAL ;
    PORT
      LAYER M4 ;
        RECT  0 85.968 0.084 85.992 ;
    END
  END cfg_data[40]
  PIN cfg_data[41]
    DIRECTION INPUT ;
    USE SIGNAL ;
    PORT
      LAYER M4 ;
        RECT  0 86.064 0.084 86.088 ;
    END
  END cfg_data[41]
  PIN cfg_data[42]
    DIRECTION INPUT ;
    USE SIGNAL ;
    PORT
      LAYER M4 ;
        RECT  0 86.16 0.084 86.184 ;
    END
  END cfg_data[42]
  PIN cfg_data[43]
    DIRECTION INPUT ;
    USE SIGNAL ;
    PORT
      LAYER M4 ;
        RECT  0 86.256 0.084 86.28 ;
    END
  END cfg_data[43]
  PIN cfg_data[44]
    DIRECTION INPUT ;
    USE SIGNAL ;
    PORT
      LAYER M4 ;
        RECT  0 86.352 0.084 86.376 ;
    END
  END cfg_data[44]
  PIN cfg_data[45]
    DIRECTION INPUT ;
    USE SIGNAL ;
    PORT
      LAYER M4 ;
        RECT  0 86.448 0.084 86.472 ;
    END
  END cfg_data[45]
  PIN cfg_data[46]
    DIRECTION INPUT ;
    USE SIGNAL ;
    PORT
      LAYER M4 ;
        RECT  0 86.544 0.084 86.568 ;
    END
  END cfg_data[46]
  PIN cfg_data[47]
    DIRECTION INPUT ;
    USE SIGNAL ;
    PORT
      LAYER M4 ;
        RECT  0 86.64 0.084 86.664 ;
    END
  END cfg_data[47]
  PIN cfg_data[48]
    DIRECTION INPUT ;
    USE SIGNAL ;
    PORT
      LAYER M4 ;
        RECT  0 86.736 0.084 86.76 ;
    END
  END cfg_data[48]
  PIN cfg_data[49]
    DIRECTION INPUT ;
    USE SIGNAL ;
    PORT
      LAYER M4 ;
        RECT  0 86.832 0.084 86.856 ;
    END
  END cfg_data[49]
  PIN cfg_data[4]
    DIRECTION INPUT ;
    USE SIGNAL ;
    PORT
      LAYER M4 ;
        RECT  0 82.512 0.084 82.536 ;
    END
  END cfg_data[4]
  PIN cfg_data[50]
    DIRECTION INPUT ;
    USE SIGNAL ;
    PORT
      LAYER M4 ;
        RECT  0 86.928 0.084 86.952 ;
    END
  END cfg_data[50]
  PIN cfg_data[51]
    DIRECTION INPUT ;
    USE SIGNAL ;
    PORT
      LAYER M4 ;
        RECT  0 87.024 0.084 87.048 ;
    END
  END cfg_data[51]
  PIN cfg_data[52]
    DIRECTION INPUT ;
    USE SIGNAL ;
    PORT
      LAYER M4 ;
        RECT  0 87.12 0.084 87.144 ;
    END
  END cfg_data[52]
  PIN cfg_data[53]
    DIRECTION INPUT ;
    USE SIGNAL ;
    PORT
      LAYER M4 ;
        RECT  0 87.216 0.084 87.24 ;
    END
  END cfg_data[53]
  PIN cfg_data[54]
    DIRECTION INPUT ;
    USE SIGNAL ;
    PORT
      LAYER M4 ;
        RECT  0 87.312 0.084 87.336 ;
    END
  END cfg_data[54]
  PIN cfg_data[55]
    DIRECTION INPUT ;
    USE SIGNAL ;
    PORT
      LAYER M4 ;
        RECT  0 87.408 0.084 87.432 ;
    END
  END cfg_data[55]
  PIN cfg_data[56]
    DIRECTION INPUT ;
    USE SIGNAL ;
    PORT
      LAYER M4 ;
        RECT  0 87.504 0.084 87.528 ;
    END
  END cfg_data[56]
  PIN cfg_data[57]
    DIRECTION INPUT ;
    USE SIGNAL ;
    PORT
      LAYER M4 ;
        RECT  0 87.6 0.084 87.624 ;
    END
  END cfg_data[57]
  PIN cfg_data[58]
    DIRECTION INPUT ;
    USE SIGNAL ;
    PORT
      LAYER M4 ;
        RECT  0 87.696 0.084 87.72 ;
    END
  END cfg_data[58]
  PIN cfg_data[59]
    DIRECTION INPUT ;
    USE SIGNAL ;
    PORT
      LAYER M4 ;
        RECT  0 87.792 0.084 87.816 ;
    END
  END cfg_data[59]
  PIN cfg_data[5]
    DIRECTION INPUT ;
    USE SIGNAL ;
    PORT
      LAYER M4 ;
        RECT  0 82.608 0.084 82.632 ;
    END
  END cfg_data[5]
  PIN cfg_data[60]
    DIRECTION INPUT ;
    USE SIGNAL ;
    PORT
      LAYER M4 ;
        RECT  0 87.888 0.084 87.912 ;
    END
  END cfg_data[60]
  PIN cfg_data[61]
    DIRECTION INPUT ;
    USE SIGNAL ;
    PORT
      LAYER M4 ;
        RECT  0 87.984 0.084 88.008 ;
    END
  END cfg_data[61]
  PIN cfg_data[62]
    DIRECTION INPUT ;
    USE SIGNAL ;
    PORT
      LAYER M4 ;
        RECT  0 88.08 0.084 88.104 ;
    END
  END cfg_data[62]
  PIN cfg_data[63]
    DIRECTION INPUT ;
    USE SIGNAL ;
    PORT
      LAYER M4 ;
        RECT  0 88.176 0.084 88.2 ;
    END
  END cfg_data[63]
  PIN cfg_data[64]
    DIRECTION INPUT ;
    USE SIGNAL ;
    PORT
      LAYER M4 ;
        RECT  0 88.272 0.084 88.296 ;
    END
  END cfg_data[64]
  PIN cfg_data[65]
    DIRECTION INPUT ;
    USE SIGNAL ;
    PORT
      LAYER M4 ;
        RECT  0 88.368 0.084 88.392 ;
    END
  END cfg_data[65]
  PIN cfg_data[66]
    DIRECTION INPUT ;
    USE SIGNAL ;
    PORT
      LAYER M4 ;
        RECT  0 88.464 0.084 88.488 ;
    END
  END cfg_data[66]
  PIN cfg_data[67]
    DIRECTION INPUT ;
    USE SIGNAL ;
    PORT
      LAYER M4 ;
        RECT  0 88.56 0.084 88.584 ;
    END
  END cfg_data[67]
  PIN cfg_data[68]
    DIRECTION INPUT ;
    USE SIGNAL ;
    PORT
      LAYER M4 ;
        RECT  0 88.656 0.084 88.68 ;
    END
  END cfg_data[68]
  PIN cfg_data[69]
    DIRECTION INPUT ;
    USE SIGNAL ;
    PORT
      LAYER M4 ;
        RECT  0 88.752 0.084 88.776 ;
    END
  END cfg_data[69]
  PIN cfg_data[6]
    DIRECTION INPUT ;
    USE SIGNAL ;
    PORT
      LAYER M4 ;
        RECT  0 82.704 0.084 82.728 ;
    END
  END cfg_data[6]
  PIN cfg_data[70]
    DIRECTION INPUT ;
    USE SIGNAL ;
    PORT
      LAYER M4 ;
        RECT  0 88.848 0.084 88.872 ;
    END
  END cfg_data[70]
  PIN cfg_data[71]
    DIRECTION INPUT ;
    USE SIGNAL ;
    PORT
      LAYER M4 ;
        RECT  0 88.944 0.084 88.968 ;
    END
  END cfg_data[71]
  PIN cfg_data[72]
    DIRECTION INPUT ;
    USE SIGNAL ;
    PORT
      LAYER M4 ;
        RECT  0 89.04 0.084 89.064 ;
    END
  END cfg_data[72]
  PIN cfg_data[73]
    DIRECTION INPUT ;
    USE SIGNAL ;
    PORT
      LAYER M4 ;
        RECT  0 89.136 0.084 89.16 ;
    END
  END cfg_data[73]
  PIN cfg_data[74]
    DIRECTION INPUT ;
    USE SIGNAL ;
    PORT
      LAYER M4 ;
        RECT  0 89.232 0.084 89.256 ;
    END
  END cfg_data[74]
  PIN cfg_data[75]
    DIRECTION INPUT ;
    USE SIGNAL ;
    PORT
      LAYER M4 ;
        RECT  0 89.328 0.084 89.352 ;
    END
  END cfg_data[75]
  PIN cfg_data[76]
    DIRECTION INPUT ;
    USE SIGNAL ;
    PORT
      LAYER M4 ;
        RECT  0 89.424 0.084 89.448 ;
    END
  END cfg_data[76]
  PIN cfg_data[77]
    DIRECTION INPUT ;
    USE SIGNAL ;
    PORT
      LAYER M4 ;
        RECT  0 89.52 0.084 89.544 ;
    END
  END cfg_data[77]
  PIN cfg_data[78]
    DIRECTION INPUT ;
    USE SIGNAL ;
    PORT
      LAYER M4 ;
        RECT  0 89.616 0.084 89.64 ;
    END
  END cfg_data[78]
  PIN cfg_data[79]
    DIRECTION INPUT ;
    USE SIGNAL ;
    PORT
      LAYER M4 ;
        RECT  0 89.712 0.084 89.736 ;
    END
  END cfg_data[79]
  PIN cfg_data[7]
    DIRECTION INPUT ;
    USE SIGNAL ;
    PORT
      LAYER M4 ;
        RECT  0 82.8 0.084 82.824 ;
    END
  END cfg_data[7]
  PIN cfg_data[80]
    DIRECTION INPUT ;
    USE SIGNAL ;
    PORT
      LAYER M4 ;
        RECT  0 89.808 0.084 89.832 ;
    END
  END cfg_data[80]
  PIN cfg_data[81]
    DIRECTION INPUT ;
    USE SIGNAL ;
    PORT
      LAYER M4 ;
        RECT  0 89.904 0.084 89.928 ;
    END
  END cfg_data[81]
  PIN cfg_data[82]
    DIRECTION INPUT ;
    USE SIGNAL ;
    PORT
      LAYER M4 ;
        RECT  0 90 0.084 90.024 ;
    END
  END cfg_data[82]
  PIN cfg_data[83]
    DIRECTION INPUT ;
    USE SIGNAL ;
    PORT
      LAYER M4 ;
        RECT  0 90.096 0.084 90.12 ;
    END
  END cfg_data[83]
  PIN cfg_data[84]
    DIRECTION INPUT ;
    USE SIGNAL ;
    PORT
      LAYER M4 ;
        RECT  0 90.192 0.084 90.216 ;
    END
  END cfg_data[84]
  PIN cfg_data[85]
    DIRECTION INPUT ;
    USE SIGNAL ;
    PORT
      LAYER M4 ;
        RECT  0 90.288 0.084 90.312 ;
    END
  END cfg_data[85]
  PIN cfg_data[86]
    DIRECTION INPUT ;
    USE SIGNAL ;
    PORT
      LAYER M4 ;
        RECT  0 90.384 0.084 90.408 ;
    END
  END cfg_data[86]
  PIN cfg_data[87]
    DIRECTION INPUT ;
    USE SIGNAL ;
    PORT
      LAYER M4 ;
        RECT  0 90.48 0.084 90.504 ;
    END
  END cfg_data[87]
  PIN cfg_data[88]
    DIRECTION INPUT ;
    USE SIGNAL ;
    PORT
      LAYER M4 ;
        RECT  0 90.576 0.084 90.6 ;
    END
  END cfg_data[88]
  PIN cfg_data[89]
    DIRECTION INPUT ;
    USE SIGNAL ;
    PORT
      LAYER M4 ;
        RECT  0 90.672 0.084 90.696 ;
    END
  END cfg_data[89]
  PIN cfg_data[8]
    DIRECTION INPUT ;
    USE SIGNAL ;
    PORT
      LAYER M4 ;
        RECT  0 82.896 0.084 82.92 ;
    END
  END cfg_data[8]
  PIN cfg_data[90]
    DIRECTION INPUT ;
    USE SIGNAL ;
    PORT
      LAYER M4 ;
        RECT  0 90.768 0.084 90.792 ;
    END
  END cfg_data[90]
  PIN cfg_data[91]
    DIRECTION INPUT ;
    USE SIGNAL ;
    PORT
      LAYER M4 ;
        RECT  0 90.864 0.084 90.888 ;
    END
  END cfg_data[91]
  PIN cfg_data[92]
    DIRECTION INPUT ;
    USE SIGNAL ;
    PORT
      LAYER M4 ;
        RECT  0 90.96 0.084 90.984 ;
    END
  END cfg_data[92]
  PIN cfg_data[93]
    DIRECTION INPUT ;
    USE SIGNAL ;
    PORT
      LAYER M4 ;
        RECT  0 91.056 0.084 91.08 ;
    END
  END cfg_data[93]
  PIN cfg_data[94]
    DIRECTION INPUT ;
    USE SIGNAL ;
    PORT
      LAYER M4 ;
        RECT  0 91.152 0.084 91.176 ;
    END
  END cfg_data[94]
  PIN cfg_data[95]
    DIRECTION INPUT ;
    USE SIGNAL ;
    PORT
      LAYER M4 ;
        RECT  0 91.248 0.084 91.272 ;
    END
  END cfg_data[95]
  PIN cfg_data[96]
    DIRECTION INPUT ;
    USE SIGNAL ;
    PORT
      LAYER M4 ;
        RECT  0 91.344 0.084 91.368 ;
    END
  END cfg_data[96]
  PIN cfg_data[97]
    DIRECTION INPUT ;
    USE SIGNAL ;
    PORT
      LAYER M4 ;
        RECT  0 91.44 0.084 91.464 ;
    END
  END cfg_data[97]
  PIN cfg_data[98]
    DIRECTION INPUT ;
    USE SIGNAL ;
    PORT
      LAYER M4 ;
        RECT  0 91.536 0.084 91.56 ;
    END
  END cfg_data[98]
  PIN cfg_data[99]
    DIRECTION INPUT ;
    USE SIGNAL ;
    PORT
      LAYER M4 ;
        RECT  0 91.632 0.084 91.656 ;
    END
  END cfg_data[99]
  PIN cfg_data[9]
    DIRECTION INPUT ;
    USE SIGNAL ;
    PORT
      LAYER M4 ;
        RECT  0 82.992 0.084 83.016 ;
    END
  END cfg_data[9]
  PIN cfg_we
    DIRECTION INPUT ;
    USE SIGNAL ;
    PORT
      LAYER M4 ;
        RECT  0 52.944 0.084 52.968 ;
    END
  END cfg_we
  PIN client_seq[0]
    DIRECTION OUTPUT ;
    USE SIGNAL ;
    PORT
      LAYER M4 ;
        RECT  220.236 61.392 220.32 61.416 ;
    END
  END client_seq[0]
  PIN client_seq[1]
    DIRECTION OUTPUT ;
    USE SIGNAL ;
    PORT
      LAYER M4 ;
        RECT  220.236 61.488 220.32 61.512 ;
    END
  END client_seq[1]
  PIN client_seq[2]
    DIRECTION OUTPUT ;
    USE SIGNAL ;
    PORT
      LAYER M4 ;
        RECT  220.236 61.584 220.32 61.608 ;
    END
  END client_seq[2]
  PIN client_seq[3]
    DIRECTION OUTPUT ;
    USE SIGNAL ;
    PORT
      LAYER M4 ;
        RECT  220.236 61.68 220.32 61.704 ;
    END
  END client_seq[3]
  PIN client_seq[4]
    DIRECTION OUTPUT ;
    USE SIGNAL ;
    PORT
      LAYER M4 ;
        RECT  220.236 61.776 220.32 61.8 ;
    END
  END client_seq[4]
  PIN client_seq[5]
    DIRECTION OUTPUT ;
    USE SIGNAL ;
    PORT
      LAYER M4 ;
        RECT  220.236 61.872 220.32 61.896 ;
    END
  END client_seq[5]
  PIN client_seq[6]
    DIRECTION OUTPUT ;
    USE SIGNAL ;
    PORT
      LAYER M4 ;
        RECT  220.236 61.968 220.32 61.992 ;
    END
  END client_seq[6]
  PIN client_seq[7]
    DIRECTION OUTPUT ;
    USE SIGNAL ;
    PORT
      LAYER M4 ;
        RECT  220.236 62.064 220.32 62.088 ;
    END
  END client_seq[7]
  PIN client_seq[8]
    DIRECTION OUTPUT ;
    USE SIGNAL ;
    PORT
      LAYER M4 ;
        RECT  220.236 62.16 220.32 62.184 ;
    END
  END client_seq[8]
  PIN client_seq[9]
    DIRECTION OUTPUT ;
    USE SIGNAL ;
    PORT
      LAYER M4 ;
        RECT  220.236 62.256 220.32 62.28 ;
    END
  END client_seq[9]
  PIN clk
    DIRECTION INPUT ;
    USE SIGNAL ;
    PORT
      LAYER M4 ;
        RECT  0 53.04 0.084 53.064 ;
    END
  END clk
  PIN done
    DIRECTION OUTPUT ;
    USE SIGNAL ;
    PORT
      LAYER M5 ;
        RECT  16.272 0 16.296 0.084 ;
    END
  END done
  PIN fault
    DIRECTION OUTPUT ;
    USE SIGNAL ;
    PORT
      LAYER M5 ;
        RECT  16.368 0 16.392 0.084 ;
    END
  END fault
  PIN hub_ring_client[0]
    DIRECTION OUTPUT ;
    USE SIGNAL ;
    PORT
      LAYER M4 ;
        RECT  220.236 62.352 220.32 62.376 ;
    END
  END hub_ring_client[0]
  PIN hub_ring_client[1]
    DIRECTION OUTPUT ;
    USE SIGNAL ;
    PORT
      LAYER M4 ;
        RECT  220.236 62.448 220.32 62.472 ;
    END
  END hub_ring_client[1]
  PIN hub_ring_client[2]
    DIRECTION OUTPUT ;
    USE SIGNAL ;
    PORT
      LAYER M4 ;
        RECT  220.236 62.544 220.32 62.568 ;
    END
  END hub_ring_client[2]
  PIN hub_ring_client[3]
    DIRECTION OUTPUT ;
    USE SIGNAL ;
    PORT
      LAYER M4 ;
        RECT  220.236 62.64 220.32 62.664 ;
    END
  END hub_ring_client[3]
  PIN hub_ring_client[4]
    DIRECTION OUTPUT ;
    USE SIGNAL ;
    PORT
      LAYER M4 ;
        RECT  220.236 62.736 220.32 62.76 ;
    END
  END hub_ring_client[4]
  PIN hub_ring_client[5]
    DIRECTION OUTPUT ;
    USE SIGNAL ;
    PORT
      LAYER M4 ;
        RECT  220.236 62.832 220.32 62.856 ;
    END
  END hub_ring_client[5]
  PIN hub_ring_enable[0]
    DIRECTION OUTPUT ;
    USE SIGNAL ;
    PORT
      LAYER M4 ;
        RECT  220.236 62.928 220.32 62.952 ;
    END
  END hub_ring_enable[0]
  PIN hub_ring_enable[1]
    DIRECTION OUTPUT ;
    USE SIGNAL ;
    PORT
      LAYER M4 ;
        RECT  220.236 63.024 220.32 63.048 ;
    END
  END hub_ring_enable[1]
  PIN lg_local_read[0]
    DIRECTION OUTPUT ;
    USE SIGNAL ;
    PORT
      LAYER M4 ;
        RECT  220.236 63.12 220.32 63.144 ;
    END
  END lg_local_read[0]
  PIN lg_local_read[10]
    DIRECTION OUTPUT ;
    USE SIGNAL ;
    PORT
      LAYER M4 ;
        RECT  220.236 64.08 220.32 64.104 ;
    END
  END lg_local_read[10]
  PIN lg_local_read[11]
    DIRECTION OUTPUT ;
    USE SIGNAL ;
    PORT
      LAYER M4 ;
        RECT  220.236 64.176 220.32 64.2 ;
    END
  END lg_local_read[11]
  PIN lg_local_read[12]
    DIRECTION OUTPUT ;
    USE SIGNAL ;
    PORT
      LAYER M4 ;
        RECT  220.236 64.272 220.32 64.296 ;
    END
  END lg_local_read[12]
  PIN lg_local_read[13]
    DIRECTION OUTPUT ;
    USE SIGNAL ;
    PORT
      LAYER M4 ;
        RECT  220.236 64.368 220.32 64.392 ;
    END
  END lg_local_read[13]
  PIN lg_local_read[14]
    DIRECTION OUTPUT ;
    USE SIGNAL ;
    PORT
      LAYER M4 ;
        RECT  220.236 73.68 220.32 73.704 ;
    END
  END lg_local_read[14]
  PIN lg_local_read[15]
    DIRECTION OUTPUT ;
    USE SIGNAL ;
    PORT
      LAYER M4 ;
        RECT  220.236 73.776 220.32 73.8 ;
    END
  END lg_local_read[15]
  PIN lg_local_read[16]
    DIRECTION OUTPUT ;
    USE SIGNAL ;
    PORT
      LAYER M4 ;
        RECT  220.236 73.872 220.32 73.896 ;
    END
  END lg_local_read[16]
  PIN lg_local_read[17]
    DIRECTION OUTPUT ;
    USE SIGNAL ;
    PORT
      LAYER M4 ;
        RECT  220.236 73.968 220.32 73.992 ;
    END
  END lg_local_read[17]
  PIN lg_local_read[18]
    DIRECTION OUTPUT ;
    USE SIGNAL ;
    PORT
      LAYER M4 ;
        RECT  220.236 74.064 220.32 74.088 ;
    END
  END lg_local_read[18]
  PIN lg_local_read[19]
    DIRECTION OUTPUT ;
    USE SIGNAL ;
    PORT
      LAYER M4 ;
        RECT  220.236 74.16 220.32 74.184 ;
    END
  END lg_local_read[19]
  PIN lg_local_read[1]
    DIRECTION OUTPUT ;
    USE SIGNAL ;
    PORT
      LAYER M4 ;
        RECT  220.236 63.216 220.32 63.24 ;
    END
  END lg_local_read[1]
  PIN lg_local_read[20]
    DIRECTION OUTPUT ;
    USE SIGNAL ;
    PORT
      LAYER M4 ;
        RECT  220.236 74.256 220.32 74.28 ;
    END
  END lg_local_read[20]
  PIN lg_local_read[21]
    DIRECTION OUTPUT ;
    USE SIGNAL ;
    PORT
      LAYER M4 ;
        RECT  220.236 74.352 220.32 74.376 ;
    END
  END lg_local_read[21]
  PIN lg_local_read[22]
    DIRECTION OUTPUT ;
    USE SIGNAL ;
    PORT
      LAYER M4 ;
        RECT  220.236 74.448 220.32 74.472 ;
    END
  END lg_local_read[22]
  PIN lg_local_read[23]
    DIRECTION OUTPUT ;
    USE SIGNAL ;
    PORT
      LAYER M4 ;
        RECT  220.236 74.544 220.32 74.568 ;
    END
  END lg_local_read[23]
  PIN lg_local_read[2]
    DIRECTION OUTPUT ;
    USE SIGNAL ;
    PORT
      LAYER M4 ;
        RECT  220.236 63.312 220.32 63.336 ;
    END
  END lg_local_read[2]
  PIN lg_local_read[3]
    DIRECTION OUTPUT ;
    USE SIGNAL ;
    PORT
      LAYER M4 ;
        RECT  220.236 63.408 220.32 63.432 ;
    END
  END lg_local_read[3]
  PIN lg_local_read[4]
    DIRECTION OUTPUT ;
    USE SIGNAL ;
    PORT
      LAYER M4 ;
        RECT  220.236 63.504 220.32 63.528 ;
    END
  END lg_local_read[4]
  PIN lg_local_read[5]
    DIRECTION OUTPUT ;
    USE SIGNAL ;
    PORT
      LAYER M4 ;
        RECT  220.236 63.6 220.32 63.624 ;
    END
  END lg_local_read[5]
  PIN lg_local_read[6]
    DIRECTION OUTPUT ;
    USE SIGNAL ;
    PORT
      LAYER M4 ;
        RECT  220.236 63.696 220.32 63.72 ;
    END
  END lg_local_read[6]
  PIN lg_local_read[7]
    DIRECTION OUTPUT ;
    USE SIGNAL ;
    PORT
      LAYER M4 ;
        RECT  220.236 63.792 220.32 63.816 ;
    END
  END lg_local_read[7]
  PIN lg_local_read[8]
    DIRECTION OUTPUT ;
    USE SIGNAL ;
    PORT
      LAYER M4 ;
        RECT  220.236 63.888 220.32 63.912 ;
    END
  END lg_local_read[8]
  PIN lg_local_read[9]
    DIRECTION OUTPUT ;
    USE SIGNAL ;
    PORT
      LAYER M4 ;
        RECT  220.236 63.984 220.32 64.008 ;
    END
  END lg_local_read[9]
  PIN lg_local_write[0]
    DIRECTION OUTPUT ;
    USE SIGNAL ;
    PORT
      LAYER M4 ;
        RECT  220.236 74.64 220.32 74.664 ;
    END
  END lg_local_write[0]
  PIN lg_local_write[10]
    DIRECTION OUTPUT ;
    USE SIGNAL ;
    PORT
      LAYER M4 ;
        RECT  220.236 75.6 220.32 75.624 ;
    END
  END lg_local_write[10]
  PIN lg_local_write[11]
    DIRECTION OUTPUT ;
    USE SIGNAL ;
    PORT
      LAYER M4 ;
        RECT  220.236 75.696 220.32 75.72 ;
    END
  END lg_local_write[11]
  PIN lg_local_write[12]
    DIRECTION OUTPUT ;
    USE SIGNAL ;
    PORT
      LAYER M4 ;
        RECT  220.236 75.792 220.32 75.816 ;
    END
  END lg_local_write[12]
  PIN lg_local_write[13]
    DIRECTION OUTPUT ;
    USE SIGNAL ;
    PORT
      LAYER M4 ;
        RECT  220.236 75.888 220.32 75.912 ;
    END
  END lg_local_write[13]
  PIN lg_local_write[14]
    DIRECTION OUTPUT ;
    USE SIGNAL ;
    PORT
      LAYER M4 ;
        RECT  220.236 75.984 220.32 76.008 ;
    END
  END lg_local_write[14]
  PIN lg_local_write[15]
    DIRECTION OUTPUT ;
    USE SIGNAL ;
    PORT
      LAYER M4 ;
        RECT  220.236 76.08 220.32 76.104 ;
    END
  END lg_local_write[15]
  PIN lg_local_write[16]
    DIRECTION OUTPUT ;
    USE SIGNAL ;
    PORT
      LAYER M4 ;
        RECT  220.236 76.176 220.32 76.2 ;
    END
  END lg_local_write[16]
  PIN lg_local_write[17]
    DIRECTION OUTPUT ;
    USE SIGNAL ;
    PORT
      LAYER M4 ;
        RECT  220.236 76.272 220.32 76.296 ;
    END
  END lg_local_write[17]
  PIN lg_local_write[18]
    DIRECTION OUTPUT ;
    USE SIGNAL ;
    PORT
      LAYER M4 ;
        RECT  220.236 76.368 220.32 76.392 ;
    END
  END lg_local_write[18]
  PIN lg_local_write[19]
    DIRECTION OUTPUT ;
    USE SIGNAL ;
    PORT
      LAYER M4 ;
        RECT  220.236 76.464 220.32 76.488 ;
    END
  END lg_local_write[19]
  PIN lg_local_write[1]
    DIRECTION OUTPUT ;
    USE SIGNAL ;
    PORT
      LAYER M4 ;
        RECT  220.236 74.736 220.32 74.76 ;
    END
  END lg_local_write[1]
  PIN lg_local_write[20]
    DIRECTION OUTPUT ;
    USE SIGNAL ;
    PORT
      LAYER M4 ;
        RECT  220.236 76.56 220.32 76.584 ;
    END
  END lg_local_write[20]
  PIN lg_local_write[21]
    DIRECTION OUTPUT ;
    USE SIGNAL ;
    PORT
      LAYER M4 ;
        RECT  220.236 76.656 220.32 76.68 ;
    END
  END lg_local_write[21]
  PIN lg_local_write[22]
    DIRECTION OUTPUT ;
    USE SIGNAL ;
    PORT
      LAYER M4 ;
        RECT  220.236 58.32 220.32 58.344 ;
    END
  END lg_local_write[22]
  PIN lg_local_write[23]
    DIRECTION OUTPUT ;
    USE SIGNAL ;
    PORT
      LAYER M4 ;
        RECT  220.236 58.416 220.32 58.44 ;
    END
  END lg_local_write[23]
  PIN lg_local_write[2]
    DIRECTION OUTPUT ;
    USE SIGNAL ;
    PORT
      LAYER M4 ;
        RECT  220.236 74.832 220.32 74.856 ;
    END
  END lg_local_write[2]
  PIN lg_local_write[3]
    DIRECTION OUTPUT ;
    USE SIGNAL ;
    PORT
      LAYER M4 ;
        RECT  220.236 74.928 220.32 74.952 ;
    END
  END lg_local_write[3]
  PIN lg_local_write[4]
    DIRECTION OUTPUT ;
    USE SIGNAL ;
    PORT
      LAYER M4 ;
        RECT  220.236 75.024 220.32 75.048 ;
    END
  END lg_local_write[4]
  PIN lg_local_write[5]
    DIRECTION OUTPUT ;
    USE SIGNAL ;
    PORT
      LAYER M4 ;
        RECT  220.236 75.12 220.32 75.144 ;
    END
  END lg_local_write[5]
  PIN lg_local_write[6]
    DIRECTION OUTPUT ;
    USE SIGNAL ;
    PORT
      LAYER M4 ;
        RECT  220.236 75.216 220.32 75.24 ;
    END
  END lg_local_write[6]
  PIN lg_local_write[7]
    DIRECTION OUTPUT ;
    USE SIGNAL ;
    PORT
      LAYER M4 ;
        RECT  220.236 75.312 220.32 75.336 ;
    END
  END lg_local_write[7]
  PIN lg_local_write[8]
    DIRECTION OUTPUT ;
    USE SIGNAL ;
    PORT
      LAYER M4 ;
        RECT  220.236 75.408 220.32 75.432 ;
    END
  END lg_local_write[8]
  PIN lg_local_write[9]
    DIRECTION OUTPUT ;
    USE SIGNAL ;
    PORT
      LAYER M4 ;
        RECT  220.236 75.504 220.32 75.528 ;
    END
  END lg_local_write[9]
  PIN ordinal[0]
    DIRECTION OUTPUT ;
    USE SIGNAL ;
    PORT
      LAYER M5 ;
        RECT  16.464 0 16.488 0.084 ;
    END
  END ordinal[0]
  PIN ordinal[10]
    DIRECTION OUTPUT ;
    USE SIGNAL ;
    PORT
      LAYER M5 ;
        RECT  17.424 0 17.448 0.084 ;
    END
  END ordinal[10]
  PIN ordinal[11]
    DIRECTION OUTPUT ;
    USE SIGNAL ;
    PORT
      LAYER M5 ;
        RECT  17.52 0 17.544 0.084 ;
    END
  END ordinal[11]
  PIN ordinal[12]
    DIRECTION OUTPUT ;
    USE SIGNAL ;
    PORT
      LAYER M5 ;
        RECT  17.616 0 17.64 0.084 ;
    END
  END ordinal[12]
  PIN ordinal[13]
    DIRECTION OUTPUT ;
    USE SIGNAL ;
    PORT
      LAYER M5 ;
        RECT  17.712 0 17.736 0.084 ;
    END
  END ordinal[13]
  PIN ordinal[14]
    DIRECTION OUTPUT ;
    USE SIGNAL ;
    PORT
      LAYER M5 ;
        RECT  17.808 0 17.832 0.084 ;
    END
  END ordinal[14]
  PIN ordinal[15]
    DIRECTION OUTPUT ;
    USE SIGNAL ;
    PORT
      LAYER M5 ;
        RECT  17.904 0 17.928 0.084 ;
    END
  END ordinal[15]
  PIN ordinal[16]
    DIRECTION OUTPUT ;
    USE SIGNAL ;
    PORT
      LAYER M5 ;
        RECT  18 0 18.024 0.084 ;
    END
  END ordinal[16]
  PIN ordinal[17]
    DIRECTION OUTPUT ;
    USE SIGNAL ;
    PORT
      LAYER M5 ;
        RECT  18.096 0 18.12 0.084 ;
    END
  END ordinal[17]
  PIN ordinal[18]
    DIRECTION OUTPUT ;
    USE SIGNAL ;
    PORT
      LAYER M5 ;
        RECT  18.192 0 18.216 0.084 ;
    END
  END ordinal[18]
  PIN ordinal[19]
    DIRECTION OUTPUT ;
    USE SIGNAL ;
    PORT
      LAYER M5 ;
        RECT  18.288 0 18.312 0.084 ;
    END
  END ordinal[19]
  PIN ordinal[1]
    DIRECTION OUTPUT ;
    USE SIGNAL ;
    PORT
      LAYER M5 ;
        RECT  16.56 0 16.584 0.084 ;
    END
  END ordinal[1]
  PIN ordinal[20]
    DIRECTION OUTPUT ;
    USE SIGNAL ;
    PORT
      LAYER M5 ;
        RECT  18.384 0 18.408 0.084 ;
    END
  END ordinal[20]
  PIN ordinal[21]
    DIRECTION OUTPUT ;
    USE SIGNAL ;
    PORT
      LAYER M5 ;
        RECT  18.48 0 18.504 0.084 ;
    END
  END ordinal[21]
  PIN ordinal[22]
    DIRECTION OUTPUT ;
    USE SIGNAL ;
    PORT
      LAYER M5 ;
        RECT  18.576 0 18.6 0.084 ;
    END
  END ordinal[22]
  PIN ordinal[23]
    DIRECTION OUTPUT ;
    USE SIGNAL ;
    PORT
      LAYER M5 ;
        RECT  18.672 0 18.696 0.084 ;
    END
  END ordinal[23]
  PIN ordinal[24]
    DIRECTION OUTPUT ;
    USE SIGNAL ;
    PORT
      LAYER M5 ;
        RECT  18.768 0 18.792 0.084 ;
    END
  END ordinal[24]
  PIN ordinal[25]
    DIRECTION OUTPUT ;
    USE SIGNAL ;
    PORT
      LAYER M5 ;
        RECT  18.864 0 18.888 0.084 ;
    END
  END ordinal[25]
  PIN ordinal[26]
    DIRECTION OUTPUT ;
    USE SIGNAL ;
    PORT
      LAYER M5 ;
        RECT  18.96 0 18.984 0.084 ;
    END
  END ordinal[26]
  PIN ordinal[27]
    DIRECTION OUTPUT ;
    USE SIGNAL ;
    PORT
      LAYER M5 ;
        RECT  19.056 0 19.08 0.084 ;
    END
  END ordinal[27]
  PIN ordinal[28]
    DIRECTION OUTPUT ;
    USE SIGNAL ;
    PORT
      LAYER M5 ;
        RECT  9.936 0 9.96 0.084 ;
    END
  END ordinal[28]
  PIN ordinal[29]
    DIRECTION OUTPUT ;
    USE SIGNAL ;
    PORT
      LAYER M5 ;
        RECT  10.032 0 10.056 0.084 ;
    END
  END ordinal[29]
  PIN ordinal[2]
    DIRECTION OUTPUT ;
    USE SIGNAL ;
    PORT
      LAYER M5 ;
        RECT  16.656 0 16.68 0.084 ;
    END
  END ordinal[2]
  PIN ordinal[30]
    DIRECTION OUTPUT ;
    USE SIGNAL ;
    PORT
      LAYER M5 ;
        RECT  10.128 0 10.152 0.084 ;
    END
  END ordinal[30]
  PIN ordinal[31]
    DIRECTION OUTPUT ;
    USE SIGNAL ;
    PORT
      LAYER M5 ;
        RECT  10.224 0 10.248 0.084 ;
    END
  END ordinal[31]
  PIN ordinal[3]
    DIRECTION OUTPUT ;
    USE SIGNAL ;
    PORT
      LAYER M5 ;
        RECT  16.752 0 16.776 0.084 ;
    END
  END ordinal[3]
  PIN ordinal[4]
    DIRECTION OUTPUT ;
    USE SIGNAL ;
    PORT
      LAYER M5 ;
        RECT  16.848 0 16.872 0.084 ;
    END
  END ordinal[4]
  PIN ordinal[5]
    DIRECTION OUTPUT ;
    USE SIGNAL ;
    PORT
      LAYER M5 ;
        RECT  16.944 0 16.968 0.084 ;
    END
  END ordinal[5]
  PIN ordinal[6]
    DIRECTION OUTPUT ;
    USE SIGNAL ;
    PORT
      LAYER M5 ;
        RECT  17.04 0 17.064 0.084 ;
    END
  END ordinal[6]
  PIN ordinal[7]
    DIRECTION OUTPUT ;
    USE SIGNAL ;
    PORT
      LAYER M5 ;
        RECT  17.136 0 17.16 0.084 ;
    END
  END ordinal[7]
  PIN ordinal[8]
    DIRECTION OUTPUT ;
    USE SIGNAL ;
    PORT
      LAYER M5 ;
        RECT  17.232 0 17.256 0.084 ;
    END
  END ordinal[8]
  PIN ordinal[9]
    DIRECTION OUTPUT ;
    USE SIGNAL ;
    PORT
      LAYER M5 ;
        RECT  17.328 0 17.352 0.084 ;
    END
  END ordinal[9]
  PIN replay_enable
    DIRECTION OUTPUT ;
    USE SIGNAL ;
    PORT
      LAYER M4 ;
        RECT  220.236 58.512 220.32 58.536 ;
    END
  END replay_enable
  PIN replay_source
    DIRECTION OUTPUT ;
    USE SIGNAL ;
    PORT
      LAYER M4 ;
        RECT  220.236 58.608 220.32 58.632 ;
    END
  END replay_source
  PIN response_enable[0]
    DIRECTION OUTPUT ;
    USE SIGNAL ;
    PORT
      LAYER M4 ;
        RECT  220.236 58.704 220.32 58.728 ;
    END
  END response_enable[0]
  PIN response_enable[1]
    DIRECTION OUTPUT ;
    USE SIGNAL ;
    PORT
      LAYER M4 ;
        RECT  220.236 58.8 220.32 58.824 ;
    END
  END response_enable[1]
  PIN response_enable[2]
    DIRECTION OUTPUT ;
    USE SIGNAL ;
    PORT
      LAYER M4 ;
        RECT  220.236 58.896 220.32 58.92 ;
    END
  END response_enable[2]
  PIN response_enable[3]
    DIRECTION OUTPUT ;
    USE SIGNAL ;
    PORT
      LAYER M4 ;
        RECT  220.236 58.992 220.32 59.016 ;
    END
  END response_enable[3]
  PIN response_enable[4]
    DIRECTION OUTPUT ;
    USE SIGNAL ;
    PORT
      LAYER M4 ;
        RECT  220.236 59.088 220.32 59.112 ;
    END
  END response_enable[4]
  PIN response_seq[0]
    DIRECTION OUTPUT ;
    USE SIGNAL ;
    PORT
      LAYER M4 ;
        RECT  220.236 59.184 220.32 59.208 ;
    END
  END response_seq[0]
  PIN response_seq[1]
    DIRECTION OUTPUT ;
    USE SIGNAL ;
    PORT
      LAYER M4 ;
        RECT  220.236 59.28 220.32 59.304 ;
    END
  END response_seq[1]
  PIN response_seq[2]
    DIRECTION OUTPUT ;
    USE SIGNAL ;
    PORT
      LAYER M4 ;
        RECT  220.236 59.376 220.32 59.4 ;
    END
  END response_seq[2]
  PIN response_seq[3]
    DIRECTION OUTPUT ;
    USE SIGNAL ;
    PORT
      LAYER M4 ;
        RECT  220.236 59.472 220.32 59.496 ;
    END
  END response_seq[3]
  PIN response_seq[4]
    DIRECTION OUTPUT ;
    USE SIGNAL ;
    PORT
      LAYER M4 ;
        RECT  220.236 59.568 220.32 59.592 ;
    END
  END response_seq[4]
  PIN response_seq[5]
    DIRECTION OUTPUT ;
    USE SIGNAL ;
    PORT
      LAYER M4 ;
        RECT  220.236 59.664 220.32 59.688 ;
    END
  END response_seq[5]
  PIN response_seq[6]
    DIRECTION OUTPUT ;
    USE SIGNAL ;
    PORT
      LAYER M4 ;
        RECT  220.236 59.76 220.32 59.784 ;
    END
  END response_seq[6]
  PIN response_seq[7]
    DIRECTION OUTPUT ;
    USE SIGNAL ;
    PORT
      LAYER M4 ;
        RECT  220.236 59.856 220.32 59.88 ;
    END
  END response_seq[7]
  PIN response_seq[8]
    DIRECTION OUTPUT ;
    USE SIGNAL ;
    PORT
      LAYER M4 ;
        RECT  220.236 59.952 220.32 59.976 ;
    END
  END response_seq[8]
  PIN response_seq[9]
    DIRECTION OUTPUT ;
    USE SIGNAL ;
    PORT
      LAYER M4 ;
        RECT  220.236 60.048 220.32 60.072 ;
    END
  END response_seq[9]
  PIN ring_tx_enable[0]
    DIRECTION OUTPUT ;
    USE SIGNAL ;
    PORT
      LAYER M4 ;
        RECT  220.236 60.144 220.32 60.168 ;
    END
  END ring_tx_enable[0]
  PIN ring_tx_enable[1]
    DIRECTION OUTPUT ;
    USE SIGNAL ;
    PORT
      LAYER M4 ;
        RECT  220.236 60.24 220.32 60.264 ;
    END
  END ring_tx_enable[1]
  PIN ring_tx_source[0]
    DIRECTION OUTPUT ;
    USE SIGNAL ;
    PORT
      LAYER M4 ;
        RECT  220.236 60.336 220.32 60.36 ;
    END
  END ring_tx_source[0]
  PIN ring_tx_source[1]
    DIRECTION OUTPUT ;
    USE SIGNAL ;
    PORT
      LAYER M4 ;
        RECT  220.236 60.432 220.32 60.456 ;
    END
  END ring_tx_source[1]
  PIN ring_tx_source[2]
    DIRECTION OUTPUT ;
    USE SIGNAL ;
    PORT
      LAYER M4 ;
        RECT  220.236 60.528 220.32 60.552 ;
    END
  END ring_tx_source[2]
  PIN ring_tx_source[3]
    DIRECTION OUTPUT ;
    USE SIGNAL ;
    PORT
      LAYER M4 ;
        RECT  220.236 60.624 220.32 60.648 ;
    END
  END ring_tx_source[3]
  PIN ring_tx_source[4]
    DIRECTION OUTPUT ;
    USE SIGNAL ;
    PORT
      LAYER M4 ;
        RECT  220.236 60.72 220.32 60.744 ;
    END
  END ring_tx_source[4]
  PIN ring_tx_source[5]
    DIRECTION OUTPUT ;
    USE SIGNAL ;
    PORT
      LAYER M4 ;
        RECT  220.236 60.816 220.32 60.84 ;
    END
  END ring_tx_source[5]
  PIN rslot[0]
    DIRECTION OUTPUT ;
    USE SIGNAL ;
    PORT
      LAYER M4 ;
        RECT  220.236 60.912 220.32 60.936 ;
    END
  END rslot[0]
  PIN rslot[10]
    DIRECTION OUTPUT ;
    USE SIGNAL ;
    PORT
      LAYER M4 ;
        RECT  220.236 64.944 220.32 64.968 ;
    END
  END rslot[10]
  PIN rslot[11]
    DIRECTION OUTPUT ;
    USE SIGNAL ;
    PORT
      LAYER M4 ;
        RECT  220.236 65.04 220.32 65.064 ;
    END
  END rslot[11]
  PIN rslot[12]
    DIRECTION OUTPUT ;
    USE SIGNAL ;
    PORT
      LAYER M4 ;
        RECT  220.236 65.136 220.32 65.16 ;
    END
  END rslot[12]
  PIN rslot[13]
    DIRECTION OUTPUT ;
    USE SIGNAL ;
    PORT
      LAYER M4 ;
        RECT  220.236 65.232 220.32 65.256 ;
    END
  END rslot[13]
  PIN rslot[14]
    DIRECTION OUTPUT ;
    USE SIGNAL ;
    PORT
      LAYER M4 ;
        RECT  220.236 65.328 220.32 65.352 ;
    END
  END rslot[14]
  PIN rslot[15]
    DIRECTION OUTPUT ;
    USE SIGNAL ;
    PORT
      LAYER M4 ;
        RECT  220.236 65.424 220.32 65.448 ;
    END
  END rslot[15]
  PIN rslot[16]
    DIRECTION OUTPUT ;
    USE SIGNAL ;
    PORT
      LAYER M4 ;
        RECT  220.236 65.52 220.32 65.544 ;
    END
  END rslot[16]
  PIN rslot[17]
    DIRECTION OUTPUT ;
    USE SIGNAL ;
    PORT
      LAYER M4 ;
        RECT  220.236 65.616 220.32 65.64 ;
    END
  END rslot[17]
  PIN rslot[18]
    DIRECTION OUTPUT ;
    USE SIGNAL ;
    PORT
      LAYER M4 ;
        RECT  220.236 65.712 220.32 65.736 ;
    END
  END rslot[18]
  PIN rslot[19]
    DIRECTION OUTPUT ;
    USE SIGNAL ;
    PORT
      LAYER M4 ;
        RECT  220.236 65.808 220.32 65.832 ;
    END
  END rslot[19]
  PIN rslot[1]
    DIRECTION OUTPUT ;
    USE SIGNAL ;
    PORT
      LAYER M4 ;
        RECT  220.236 61.008 220.32 61.032 ;
    END
  END rslot[1]
  PIN rslot[20]
    DIRECTION OUTPUT ;
    USE SIGNAL ;
    PORT
      LAYER M4 ;
        RECT  220.236 65.904 220.32 65.928 ;
    END
  END rslot[20]
  PIN rslot[21]
    DIRECTION OUTPUT ;
    USE SIGNAL ;
    PORT
      LAYER M4 ;
        RECT  220.236 66 220.32 66.024 ;
    END
  END rslot[21]
  PIN rslot[22]
    DIRECTION OUTPUT ;
    USE SIGNAL ;
    PORT
      LAYER M4 ;
        RECT  220.236 66.096 220.32 66.12 ;
    END
  END rslot[22]
  PIN rslot[23]
    DIRECTION OUTPUT ;
    USE SIGNAL ;
    PORT
      LAYER M4 ;
        RECT  220.236 66.192 220.32 66.216 ;
    END
  END rslot[23]
  PIN rslot[2]
    DIRECTION OUTPUT ;
    USE SIGNAL ;
    PORT
      LAYER M4 ;
        RECT  220.236 61.104 220.32 61.128 ;
    END
  END rslot[2]
  PIN rslot[3]
    DIRECTION OUTPUT ;
    USE SIGNAL ;
    PORT
      LAYER M4 ;
        RECT  220.236 61.2 220.32 61.224 ;
    END
  END rslot[3]
  PIN rslot[4]
    DIRECTION OUTPUT ;
    USE SIGNAL ;
    PORT
      LAYER M4 ;
        RECT  220.236 61.296 220.32 61.32 ;
    END
  END rslot[4]
  PIN rslot[5]
    DIRECTION OUTPUT ;
    USE SIGNAL ;
    PORT
      LAYER M4 ;
        RECT  220.236 64.464 220.32 64.488 ;
    END
  END rslot[5]
  PIN rslot[6]
    DIRECTION OUTPUT ;
    USE SIGNAL ;
    PORT
      LAYER M4 ;
        RECT  220.236 64.56 220.32 64.584 ;
    END
  END rslot[6]
  PIN rslot[7]
    DIRECTION OUTPUT ;
    USE SIGNAL ;
    PORT
      LAYER M4 ;
        RECT  220.236 64.656 220.32 64.68 ;
    END
  END rslot[7]
  PIN rslot[8]
    DIRECTION OUTPUT ;
    USE SIGNAL ;
    PORT
      LAYER M4 ;
        RECT  220.236 64.752 220.32 64.776 ;
    END
  END rslot[8]
  PIN rslot[9]
    DIRECTION OUTPUT ;
    USE SIGNAL ;
    PORT
      LAYER M4 ;
        RECT  220.236 64.848 220.32 64.872 ;
    END
  END rslot[9]
  PIN rslot_v[0]
    DIRECTION OUTPUT ;
    USE SIGNAL ;
    PORT
      LAYER M4 ;
        RECT  220.236 66.288 220.32 66.312 ;
    END
  END rslot_v[0]
  PIN rslot_v[1]
    DIRECTION OUTPUT ;
    USE SIGNAL ;
    PORT
      LAYER M4 ;
        RECT  220.236 66.384 220.32 66.408 ;
    END
  END rslot_v[1]
  PIN rslot_v[2]
    DIRECTION OUTPUT ;
    USE SIGNAL ;
    PORT
      LAYER M4 ;
        RECT  220.236 66.48 220.32 66.504 ;
    END
  END rslot_v[2]
  PIN rslot_v[3]
    DIRECTION OUTPUT ;
    USE SIGNAL ;
    PORT
      LAYER M4 ;
        RECT  220.236 66.576 220.32 66.6 ;
    END
  END rslot_v[3]
  PIN rslot_v[4]
    DIRECTION OUTPUT ;
    USE SIGNAL ;
    PORT
      LAYER M4 ;
        RECT  220.236 66.672 220.32 66.696 ;
    END
  END rslot_v[4]
  PIN rslot_v[5]
    DIRECTION OUTPUT ;
    USE SIGNAL ;
    PORT
      LAYER M4 ;
        RECT  220.236 66.768 220.32 66.792 ;
    END
  END rslot_v[5]
  PIN rslot_v[6]
    DIRECTION OUTPUT ;
    USE SIGNAL ;
    PORT
      LAYER M4 ;
        RECT  220.236 66.864 220.32 66.888 ;
    END
  END rslot_v[6]
  PIN rslot_v[7]
    DIRECTION OUTPUT ;
    USE SIGNAL ;
    PORT
      LAYER M4 ;
        RECT  220.236 66.96 220.32 66.984 ;
    END
  END rslot_v[7]
  PIN rst_n
    DIRECTION INPUT ;
    USE SIGNAL ;
    PORT
      LAYER M4 ;
        RECT  0 53.136 0.084 53.16 ;
    END
  END rst_n
  PIN start_base[0]
    DIRECTION INPUT ;
    USE SIGNAL ;
    PORT
      LAYER M4 ;
        RECT  0 53.232 0.084 53.256 ;
    END
  END start_base[0]
  PIN start_base[1]
    DIRECTION INPUT ;
    USE SIGNAL ;
    PORT
      LAYER M4 ;
        RECT  0 53.328 0.084 53.352 ;
    END
  END start_base[1]
  PIN start_base[2]
    DIRECTION INPUT ;
    USE SIGNAL ;
    PORT
      LAYER M4 ;
        RECT  0 53.424 0.084 53.448 ;
    END
  END start_base[2]
  PIN start_base[3]
    DIRECTION INPUT ;
    USE SIGNAL ;
    PORT
      LAYER M4 ;
        RECT  0 53.52 0.084 53.544 ;
    END
  END start_base[3]
  PIN start_base[4]
    DIRECTION INPUT ;
    USE SIGNAL ;
    PORT
      LAYER M4 ;
        RECT  0 53.616 0.084 53.64 ;
    END
  END start_base[4]
  PIN start_base[5]
    DIRECTION INPUT ;
    USE SIGNAL ;
    PORT
      LAYER M4 ;
        RECT  0 53.712 0.084 53.736 ;
    END
  END start_base[5]
  PIN start_base[6]
    DIRECTION INPUT ;
    USE SIGNAL ;
    PORT
      LAYER M4 ;
        RECT  0 53.808 0.084 53.832 ;
    END
  END start_base[6]
  PIN start_base[7]
    DIRECTION INPUT ;
    USE SIGNAL ;
    PORT
      LAYER M4 ;
        RECT  0 53.904 0.084 53.928 ;
    END
  END start_base[7]
  PIN start_base[8]
    DIRECTION INPUT ;
    USE SIGNAL ;
    PORT
      LAYER M4 ;
        RECT  0 54 0.084 54.024 ;
    END
  END start_base[8]
  PIN start_base[9]
    DIRECTION INPUT ;
    USE SIGNAL ;
    PORT
      LAYER M4 ;
        RECT  0 54.096 0.084 54.12 ;
    END
  END start_base[9]
  PIN start_limit[0]
    DIRECTION INPUT ;
    USE SIGNAL ;
    PORT
      LAYER M4 ;
        RECT  0 54.192 0.084 54.216 ;
    END
  END start_limit[0]
  PIN start_limit[10]
    DIRECTION INPUT ;
    USE SIGNAL ;
    PORT
      LAYER M4 ;
        RECT  0 47.184 0.084 47.208 ;
    END
  END start_limit[10]
  PIN start_limit[1]
    DIRECTION INPUT ;
    USE SIGNAL ;
    PORT
      LAYER M4 ;
        RECT  0 54.288 0.084 54.312 ;
    END
  END start_limit[1]
  PIN start_limit[2]
    DIRECTION INPUT ;
    USE SIGNAL ;
    PORT
      LAYER M4 ;
        RECT  0 54.384 0.084 54.408 ;
    END
  END start_limit[2]
  PIN start_limit[3]
    DIRECTION INPUT ;
    USE SIGNAL ;
    PORT
      LAYER M4 ;
        RECT  0 54.48 0.084 54.504 ;
    END
  END start_limit[3]
  PIN start_limit[4]
    DIRECTION INPUT ;
    USE SIGNAL ;
    PORT
      LAYER M4 ;
        RECT  0 54.576 0.084 54.6 ;
    END
  END start_limit[4]
  PIN start_limit[5]
    DIRECTION INPUT ;
    USE SIGNAL ;
    PORT
      LAYER M4 ;
        RECT  0 54.672 0.084 54.696 ;
    END
  END start_limit[5]
  PIN start_limit[6]
    DIRECTION INPUT ;
    USE SIGNAL ;
    PORT
      LAYER M4 ;
        RECT  0 54.768 0.084 54.792 ;
    END
  END start_limit[6]
  PIN start_limit[7]
    DIRECTION INPUT ;
    USE SIGNAL ;
    PORT
      LAYER M4 ;
        RECT  0 54.864 0.084 54.888 ;
    END
  END start_limit[7]
  PIN start_limit[8]
    DIRECTION INPUT ;
    USE SIGNAL ;
    PORT
      LAYER M4 ;
        RECT  0 54.96 0.084 54.984 ;
    END
  END start_limit[8]
  PIN start_limit[9]
    DIRECTION INPUT ;
    USE SIGNAL ;
    PORT
      LAYER M4 ;
        RECT  0 47.088 0.084 47.112 ;
    END
  END start_limit[9]
  PIN start_loops[0]
    DIRECTION INPUT ;
    USE SIGNAL ;
    PORT
      LAYER M4 ;
        RECT  0 47.28 0.084 47.304 ;
    END
  END start_loops[0]
  PIN start_loops[10]
    DIRECTION INPUT ;
    USE SIGNAL ;
    PORT
      LAYER M4 ;
        RECT  0 48.24 0.084 48.264 ;
    END
  END start_loops[10]
  PIN start_loops[11]
    DIRECTION INPUT ;
    USE SIGNAL ;
    PORT
      LAYER M4 ;
        RECT  0 48.336 0.084 48.36 ;
    END
  END start_loops[11]
  PIN start_loops[12]
    DIRECTION INPUT ;
    USE SIGNAL ;
    PORT
      LAYER M4 ;
        RECT  0 48.432 0.084 48.456 ;
    END
  END start_loops[12]
  PIN start_loops[13]
    DIRECTION INPUT ;
    USE SIGNAL ;
    PORT
      LAYER M4 ;
        RECT  0 48.528 0.084 48.552 ;
    END
  END start_loops[13]
  PIN start_loops[14]
    DIRECTION INPUT ;
    USE SIGNAL ;
    PORT
      LAYER M4 ;
        RECT  0 48.624 0.084 48.648 ;
    END
  END start_loops[14]
  PIN start_loops[15]
    DIRECTION INPUT ;
    USE SIGNAL ;
    PORT
      LAYER M4 ;
        RECT  0 48.72 0.084 48.744 ;
    END
  END start_loops[15]
  PIN start_loops[1]
    DIRECTION INPUT ;
    USE SIGNAL ;
    PORT
      LAYER M4 ;
        RECT  0 47.376 0.084 47.4 ;
    END
  END start_loops[1]
  PIN start_loops[2]
    DIRECTION INPUT ;
    USE SIGNAL ;
    PORT
      LAYER M4 ;
        RECT  0 47.472 0.084 47.496 ;
    END
  END start_loops[2]
  PIN start_loops[3]
    DIRECTION INPUT ;
    USE SIGNAL ;
    PORT
      LAYER M4 ;
        RECT  0 47.568 0.084 47.592 ;
    END
  END start_loops[3]
  PIN start_loops[4]
    DIRECTION INPUT ;
    USE SIGNAL ;
    PORT
      LAYER M4 ;
        RECT  0 47.664 0.084 47.688 ;
    END
  END start_loops[4]
  PIN start_loops[5]
    DIRECTION INPUT ;
    USE SIGNAL ;
    PORT
      LAYER M4 ;
        RECT  0 47.76 0.084 47.784 ;
    END
  END start_loops[5]
  PIN start_loops[6]
    DIRECTION INPUT ;
    USE SIGNAL ;
    PORT
      LAYER M4 ;
        RECT  0 47.856 0.084 47.88 ;
    END
  END start_loops[6]
  PIN start_loops[7]
    DIRECTION INPUT ;
    USE SIGNAL ;
    PORT
      LAYER M4 ;
        RECT  0 47.952 0.084 47.976 ;
    END
  END start_loops[7]
  PIN start_loops[8]
    DIRECTION INPUT ;
    USE SIGNAL ;
    PORT
      LAYER M4 ;
        RECT  0 48.048 0.084 48.072 ;
    END
  END start_loops[8]
  PIN start_loops[9]
    DIRECTION INPUT ;
    USE SIGNAL ;
    PORT
      LAYER M4 ;
        RECT  0 48.144 0.084 48.168 ;
    END
  END start_loops[9]
  PIN start_v
    DIRECTION INPUT ;
    USE SIGNAL ;
    PORT
      LAYER M4 ;
        RECT  0 48.816 0.084 48.84 ;
    END
  END start_v
  PIN wslot[0]
    DIRECTION OUTPUT ;
    USE SIGNAL ;
    PORT
      LAYER M4 ;
        RECT  220.236 67.056 220.32 67.08 ;
    END
  END wslot[0]
  PIN wslot[10]
    DIRECTION OUTPUT ;
    USE SIGNAL ;
    PORT
      LAYER M4 ;
        RECT  220.236 68.016 220.32 68.04 ;
    END
  END wslot[10]
  PIN wslot[11]
    DIRECTION OUTPUT ;
    USE SIGNAL ;
    PORT
      LAYER M4 ;
        RECT  220.236 68.112 220.32 68.136 ;
    END
  END wslot[11]
  PIN wslot[12]
    DIRECTION OUTPUT ;
    USE SIGNAL ;
    PORT
      LAYER M4 ;
        RECT  220.236 68.208 220.32 68.232 ;
    END
  END wslot[12]
  PIN wslot[13]
    DIRECTION OUTPUT ;
    USE SIGNAL ;
    PORT
      LAYER M4 ;
        RECT  220.236 68.304 220.32 68.328 ;
    END
  END wslot[13]
  PIN wslot[14]
    DIRECTION OUTPUT ;
    USE SIGNAL ;
    PORT
      LAYER M4 ;
        RECT  220.236 68.4 220.32 68.424 ;
    END
  END wslot[14]
  PIN wslot[15]
    DIRECTION OUTPUT ;
    USE SIGNAL ;
    PORT
      LAYER M4 ;
        RECT  220.236 68.496 220.32 68.52 ;
    END
  END wslot[15]
  PIN wslot[16]
    DIRECTION OUTPUT ;
    USE SIGNAL ;
    PORT
      LAYER M4 ;
        RECT  220.236 68.592 220.32 68.616 ;
    END
  END wslot[16]
  PIN wslot[17]
    DIRECTION OUTPUT ;
    USE SIGNAL ;
    PORT
      LAYER M4 ;
        RECT  220.236 68.688 220.32 68.712 ;
    END
  END wslot[17]
  PIN wslot[18]
    DIRECTION OUTPUT ;
    USE SIGNAL ;
    PORT
      LAYER M4 ;
        RECT  220.236 68.784 220.32 68.808 ;
    END
  END wslot[18]
  PIN wslot[19]
    DIRECTION OUTPUT ;
    USE SIGNAL ;
    PORT
      LAYER M4 ;
        RECT  220.236 68.88 220.32 68.904 ;
    END
  END wslot[19]
  PIN wslot[1]
    DIRECTION OUTPUT ;
    USE SIGNAL ;
    PORT
      LAYER M4 ;
        RECT  220.236 67.152 220.32 67.176 ;
    END
  END wslot[1]
  PIN wslot[20]
    DIRECTION OUTPUT ;
    USE SIGNAL ;
    PORT
      LAYER M4 ;
        RECT  220.236 68.976 220.32 69 ;
    END
  END wslot[20]
  PIN wslot[21]
    DIRECTION OUTPUT ;
    USE SIGNAL ;
    PORT
      LAYER M4 ;
        RECT  220.236 69.072 220.32 69.096 ;
    END
  END wslot[21]
  PIN wslot[22]
    DIRECTION OUTPUT ;
    USE SIGNAL ;
    PORT
      LAYER M4 ;
        RECT  220.236 69.168 220.32 69.192 ;
    END
  END wslot[22]
  PIN wslot[23]
    DIRECTION OUTPUT ;
    USE SIGNAL ;
    PORT
      LAYER M4 ;
        RECT  220.236 69.264 220.32 69.288 ;
    END
  END wslot[23]
  PIN wslot[2]
    DIRECTION OUTPUT ;
    USE SIGNAL ;
    PORT
      LAYER M4 ;
        RECT  220.236 67.248 220.32 67.272 ;
    END
  END wslot[2]
  PIN wslot[3]
    DIRECTION OUTPUT ;
    USE SIGNAL ;
    PORT
      LAYER M4 ;
        RECT  220.236 67.344 220.32 67.368 ;
    END
  END wslot[3]
  PIN wslot[4]
    DIRECTION OUTPUT ;
    USE SIGNAL ;
    PORT
      LAYER M4 ;
        RECT  220.236 67.44 220.32 67.464 ;
    END
  END wslot[4]
  PIN wslot[5]
    DIRECTION OUTPUT ;
    USE SIGNAL ;
    PORT
      LAYER M4 ;
        RECT  220.236 67.536 220.32 67.56 ;
    END
  END wslot[5]
  PIN wslot[6]
    DIRECTION OUTPUT ;
    USE SIGNAL ;
    PORT
      LAYER M4 ;
        RECT  220.236 67.632 220.32 67.656 ;
    END
  END wslot[6]
  PIN wslot[7]
    DIRECTION OUTPUT ;
    USE SIGNAL ;
    PORT
      LAYER M4 ;
        RECT  220.236 67.728 220.32 67.752 ;
    END
  END wslot[7]
  PIN wslot[8]
    DIRECTION OUTPUT ;
    USE SIGNAL ;
    PORT
      LAYER M4 ;
        RECT  220.236 67.824 220.32 67.848 ;
    END
  END wslot[8]
  PIN wslot[9]
    DIRECTION OUTPUT ;
    USE SIGNAL ;
    PORT
      LAYER M4 ;
        RECT  220.236 67.92 220.32 67.944 ;
    END
  END wslot[9]
  PIN wslot_v[0]
    DIRECTION OUTPUT ;
    USE SIGNAL ;
    PORT
      LAYER M4 ;
        RECT  220.236 69.36 220.32 69.384 ;
    END
  END wslot_v[0]
  PIN wslot_v[1]
    DIRECTION OUTPUT ;
    USE SIGNAL ;
    PORT
      LAYER M4 ;
        RECT  220.236 69.456 220.32 69.48 ;
    END
  END wslot_v[1]
  PIN wslot_v[2]
    DIRECTION OUTPUT ;
    USE SIGNAL ;
    PORT
      LAYER M4 ;
        RECT  220.236 69.552 220.32 69.576 ;
    END
  END wslot_v[2]
  PIN wslot_v[3]
    DIRECTION OUTPUT ;
    USE SIGNAL ;
    PORT
      LAYER M4 ;
        RECT  220.236 69.648 220.32 69.672 ;
    END
  END wslot_v[3]
  PIN wslot_v[4]
    DIRECTION OUTPUT ;
    USE SIGNAL ;
    PORT
      LAYER M4 ;
        RECT  220.236 69.744 220.32 69.768 ;
    END
  END wslot_v[4]
  PIN wslot_v[5]
    DIRECTION OUTPUT ;
    USE SIGNAL ;
    PORT
      LAYER M4 ;
        RECT  220.236 69.84 220.32 69.864 ;
    END
  END wslot_v[5]
  PIN wslot_v[6]
    DIRECTION OUTPUT ;
    USE SIGNAL ;
    PORT
      LAYER M4 ;
        RECT  220.236 69.936 220.32 69.96 ;
    END
  END wslot_v[6]
  PIN wslot_v[7]
    DIRECTION OUTPUT ;
    USE SIGNAL ;
    PORT
      LAYER M4 ;
        RECT  220.236 70.032 220.32 70.056 ;
    END
  END wslot_v[7]
  PIN VDD
    DIRECTION INOUT ;
    USE POWER ;
    PORT
      LAYER M5 ;
        RECT  213.192 2.151 213.312 174.969 ;
        RECT  207.792 2.151 207.912 174.969 ;
        RECT  202.392 2.151 202.512 174.969 ;
        RECT  196.992 2.151 197.112 174.969 ;
        RECT  191.592 2.151 191.712 174.969 ;
        RECT  186.192 2.151 186.312 174.969 ;
        RECT  180.792 2.151 180.912 174.969 ;
        RECT  175.392 2.151 175.512 174.969 ;
        RECT  169.992 2.151 170.112 174.969 ;
        RECT  164.592 2.151 164.712 174.969 ;
        RECT  159.192 2.151 159.312 174.969 ;
        RECT  153.792 2.151 153.912 174.969 ;
        RECT  148.392 2.151 148.512 174.969 ;
        RECT  142.992 2.151 143.112 174.969 ;
        RECT  137.592 2.151 137.712 174.969 ;
        RECT  132.192 2.151 132.312 174.969 ;
        RECT  126.792 2.151 126.912 174.969 ;
        RECT  121.392 2.151 121.512 174.969 ;
        RECT  115.992 2.151 116.112 174.969 ;
        RECT  110.592 2.151 110.712 174.969 ;
        RECT  105.192 2.151 105.312 174.969 ;
        RECT  99.792 2.151 99.912 174.969 ;
        RECT  94.392 2.151 94.512 174.969 ;
        RECT  88.992 2.151 89.112 174.969 ;
        RECT  83.592 2.151 83.712 174.969 ;
        RECT  78.192 2.151 78.312 174.969 ;
        RECT  72.792 2.151 72.912 174.969 ;
        RECT  67.392 2.151 67.512 174.969 ;
        RECT  61.992 2.151 62.112 174.969 ;
        RECT  56.592 2.151 56.712 174.969 ;
        RECT  51.192 2.151 51.312 174.969 ;
        RECT  45.792 2.151 45.912 174.969 ;
        RECT  40.392 2.151 40.512 174.969 ;
        RECT  34.992 2.151 35.112 174.969 ;
        RECT  29.592 2.151 29.712 174.969 ;
        RECT  24.192 2.151 24.312 174.969 ;
        RECT  18.792 2.151 18.912 174.969 ;
        RECT  13.392 2.151 13.512 174.969 ;
        RECT  7.992 2.151 8.112 174.969 ;
        RECT  2.592 2.151 2.712 174.969 ;
    END
  END VDD
  PIN VSS
    DIRECTION INOUT ;
    USE GROUND ;
    PORT
      LAYER M5 ;
        RECT  213 2.137 213.12 174.983 ;
        RECT  207.6 2.137 207.72 174.983 ;
        RECT  202.2 2.137 202.32 174.983 ;
        RECT  196.8 2.137 196.92 174.983 ;
        RECT  191.4 2.137 191.52 174.983 ;
        RECT  186 2.137 186.12 174.983 ;
        RECT  180.6 2.137 180.72 174.983 ;
        RECT  175.2 2.137 175.32 174.983 ;
        RECT  169.8 2.137 169.92 174.983 ;
        RECT  164.4 2.137 164.52 174.983 ;
        RECT  159 2.137 159.12 174.983 ;
        RECT  153.6 2.137 153.72 174.983 ;
        RECT  148.2 2.137 148.32 174.983 ;
        RECT  142.8 2.137 142.92 174.983 ;
        RECT  137.4 2.137 137.52 174.983 ;
        RECT  132 2.137 132.12 174.983 ;
        RECT  126.6 2.137 126.72 174.983 ;
        RECT  121.2 2.137 121.32 174.983 ;
        RECT  115.8 2.137 115.92 174.983 ;
        RECT  110.4 2.137 110.52 174.983 ;
        RECT  105 2.137 105.12 174.983 ;
        RECT  99.6 2.137 99.72 174.983 ;
        RECT  94.2 2.137 94.32 174.983 ;
        RECT  88.8 2.137 88.92 174.983 ;
        RECT  83.4 2.137 83.52 174.983 ;
        RECT  78 2.137 78.12 174.983 ;
        RECT  72.6 2.137 72.72 174.983 ;
        RECT  67.2 2.137 67.32 174.983 ;
        RECT  61.8 2.137 61.92 174.983 ;
        RECT  56.4 2.137 56.52 174.983 ;
        RECT  51 2.137 51.12 174.983 ;
        RECT  45.6 2.137 45.72 174.983 ;
        RECT  40.2 2.137 40.32 174.983 ;
        RECT  34.8 2.137 34.92 174.983 ;
        RECT  29.4 2.137 29.52 174.983 ;
        RECT  24 2.137 24.12 174.983 ;
        RECT  18.6 2.137 18.72 174.983 ;
        RECT  13.2 2.137 13.32 174.983 ;
        RECT  7.8 2.137 7.92 174.983 ;
        RECT  2.4 2.137 2.52 174.983 ;
    END
  END VSS
  # OT_OBS_CLOSED layer=M5 d_um=1.536 added=160
  OBS
    LAYER RVTN ;
     RECT  2.16 2.16 218.16 2.295 ;
     RECT  2.16 2.565 218.16 2.835 ;
     RECT  2.16 3.105 218.16 3.375 ;
     RECT  2.16 3.645 218.16 3.915 ;
     RECT  2.16 4.185 218.16 4.455 ;
     RECT  2.16 4.725 218.16 4.995 ;
     RECT  2.16 5.265 218.16 5.535 ;
     RECT  2.16 5.805 218.16 6.075 ;
     RECT  2.16 6.345 218.16 6.615 ;
     RECT  2.16 6.885 218.16 7.155 ;
     RECT  2.16 7.425 218.16 7.695 ;
     RECT  2.16 7.965 218.16 8.235 ;
     RECT  2.16 8.505 218.16 8.775 ;
     RECT  2.16 9.045 218.16 9.315 ;
     RECT  2.16 9.585 218.16 9.855 ;
     RECT  2.16 10.125 218.16 10.395 ;
     RECT  2.16 10.665 218.16 10.935 ;
     RECT  2.16 11.205 218.16 11.475 ;
     RECT  2.16 11.745 218.16 12.015 ;
     RECT  2.16 12.285 218.16 12.555 ;
     RECT  2.16 12.825 218.16 13.095 ;
     RECT  2.16 13.365 218.16 13.635 ;
     RECT  2.16 13.905 218.16 14.175 ;
     RECT  2.16 14.445 218.16 14.715 ;
     RECT  2.16 14.985 218.16 15.255 ;
     RECT  2.16 15.525 218.16 15.795 ;
     RECT  2.16 16.065 218.16 16.335 ;
     RECT  2.16 16.605 218.16 16.875 ;
     RECT  2.16 17.145 218.16 17.415 ;
     RECT  2.16 17.685 218.16 17.955 ;
     RECT  2.16 18.225 218.16 18.495 ;
     RECT  2.16 18.765 218.16 19.035 ;
     RECT  2.16 19.305 218.16 19.575 ;
     RECT  2.16 19.845 218.16 20.115 ;
     RECT  2.16 20.385 218.16 20.655 ;
     RECT  2.16 20.925 218.16 21.195 ;
     RECT  2.16 21.465 218.16 21.735 ;
     RECT  2.16 22.005 218.16 22.275 ;
     RECT  2.16 22.545 218.16 22.815 ;
     RECT  2.16 23.085 218.16 23.355 ;
     RECT  2.16 23.625 218.16 23.895 ;
     RECT  2.16 24.165 218.16 24.435 ;
     RECT  2.16 24.705 218.16 24.975 ;
     RECT  2.16 25.245 218.16 25.515 ;
     RECT  2.16 25.785 218.16 26.055 ;
     RECT  2.16 26.325 218.16 26.595 ;
     RECT  2.16 26.865 218.16 27.135 ;
     RECT  2.16 27.405 218.16 27.675 ;
     RECT  2.16 27.945 218.16 28.215 ;
     RECT  2.16 28.485 218.16 28.755 ;
     RECT  2.16 29.025 218.16 29.295 ;
     RECT  2.16 29.565 218.16 29.835 ;
     RECT  2.16 30.105 218.16 30.375 ;
     RECT  2.16 30.645 218.16 30.915 ;
     RECT  2.16 31.185 218.16 31.455 ;
     RECT  2.16 31.725 218.16 31.995 ;
     RECT  2.16 32.265 218.16 32.535 ;
     RECT  2.16 32.805 218.16 33.075 ;
     RECT  2.16 33.345 218.16 33.615 ;
     RECT  2.16 33.885 218.16 34.155 ;
     RECT  2.16 34.425 218.16 34.695 ;
     RECT  2.16 34.965 218.16 35.235 ;
     RECT  2.16 35.505 218.16 35.775 ;
     RECT  2.16 36.045 218.16 36.315 ;
     RECT  2.16 36.585 218.16 36.855 ;
     RECT  2.16 37.125 218.16 37.395 ;
     RECT  2.16 37.665 218.16 37.935 ;
     RECT  2.16 38.205 218.16 38.475 ;
     RECT  2.16 38.745 218.16 39.015 ;
     RECT  2.16 39.285 218.16 39.555 ;
     RECT  2.16 39.825 218.16 40.095 ;
     RECT  2.16 40.365 218.16 40.635 ;
     RECT  2.16 40.905 218.16 41.175 ;
     RECT  2.16 41.445 218.16 41.715 ;
     RECT  2.16 41.985 218.16 42.255 ;
     RECT  2.16 42.525 218.16 42.795 ;
     RECT  2.16 43.065 218.16 43.335 ;
     RECT  2.16 43.605 218.16 43.875 ;
     RECT  2.16 44.145 218.16 44.415 ;
     RECT  2.16 44.685 218.16 44.955 ;
     RECT  2.16 45.225 218.16 45.495 ;
     RECT  2.16 45.765 218.16 46.035 ;
     RECT  2.16 46.305 218.16 46.575 ;
     RECT  2.16 46.845 218.16 47.115 ;
     RECT  2.16 47.385 218.16 47.655 ;
     RECT  2.16 47.925 218.16 48.195 ;
     RECT  2.16 48.465 218.16 48.735 ;
     RECT  2.16 49.005 218.16 49.275 ;
     RECT  2.16 49.545 218.16 49.815 ;
     RECT  2.16 50.085 218.16 50.355 ;
     RECT  2.16 50.625 218.16 50.895 ;
     RECT  2.16 51.165 218.16 51.435 ;
     RECT  2.16 51.705 218.16 51.84 ;
     RECT  2.16 51.84 20.844 51.975 ;
     RECT  199.692 51.84 218.16 51.975 ;
     RECT  2.16 52.245 20.844 52.515 ;
     RECT  199.692 52.245 218.16 52.515 ;
     RECT  2.16 52.785 20.844 53.055 ;
     RECT  199.692 52.785 218.16 53.055 ;
     RECT  2.16 53.325 20.844 53.595 ;
     RECT  199.692 53.325 218.16 53.595 ;
     RECT  2.16 53.865 20.844 54.135 ;
     RECT  199.692 53.865 218.16 54.135 ;
     RECT  2.16 54.405 20.844 54.675 ;
     RECT  199.692 54.405 218.16 54.675 ;
     RECT  2.16 54.945 20.844 55.215 ;
     RECT  199.692 54.945 218.16 55.215 ;
     RECT  2.16 55.485 20.844 55.755 ;
     RECT  199.692 55.485 218.16 55.755 ;
     RECT  2.16 56.025 20.844 56.295 ;
     RECT  199.692 56.025 218.16 56.295 ;
     RECT  2.16 56.565 20.844 56.835 ;
     RECT  199.692 56.565 218.16 56.835 ;
     RECT  2.16 57.105 20.844 57.375 ;
     RECT  199.692 57.105 218.16 57.375 ;
     RECT  2.16 57.645 20.844 57.915 ;
     RECT  199.692 57.645 218.16 57.915 ;
     RECT  2.16 58.185 20.844 58.455 ;
     RECT  199.692 58.185 218.16 58.455 ;
     RECT  2.16 58.725 20.844 58.995 ;
     RECT  199.692 58.725 218.16 58.995 ;
     RECT  2.16 59.265 20.844 59.535 ;
     RECT  199.692 59.265 218.16 59.535 ;
     RECT  2.16 59.805 20.844 60.075 ;
     RECT  199.692 59.805 218.16 60.075 ;
     RECT  2.16 60.345 20.844 60.615 ;
     RECT  199.692 60.345 218.16 60.615 ;
     RECT  2.16 60.885 20.844 61.155 ;
     RECT  199.692 60.885 218.16 61.155 ;
     RECT  2.16 61.425 20.844 61.695 ;
     RECT  199.692 61.425 218.16 61.695 ;
     RECT  2.16 61.965 20.844 62.235 ;
     RECT  199.692 61.965 218.16 62.235 ;
     RECT  2.16 62.505 20.844 62.775 ;
     RECT  199.692 62.505 218.16 62.775 ;
     RECT  2.16 63.045 20.844 63.315 ;
     RECT  199.692 63.045 218.16 63.315 ;
     RECT  2.16 63.585 20.844 63.855 ;
     RECT  199.692 63.585 218.16 63.855 ;
     RECT  2.16 64.125 20.844 64.395 ;
     RECT  199.692 64.125 218.16 64.395 ;
     RECT  2.16 64.665 20.844 64.935 ;
     RECT  199.692 64.665 218.16 64.935 ;
     RECT  2.16 65.205 20.844 65.475 ;
     RECT  199.692 65.205 218.16 65.475 ;
     RECT  2.16 65.745 20.844 66.015 ;
     RECT  199.692 65.745 218.16 66.015 ;
     RECT  2.16 66.285 20.844 66.555 ;
     RECT  199.692 66.285 218.16 66.555 ;
     RECT  2.16 66.825 20.844 67.095 ;
     RECT  199.692 66.825 218.16 67.095 ;
     RECT  2.16 67.365 20.844 67.635 ;
     RECT  199.692 67.365 218.16 67.635 ;
     RECT  2.16 67.905 20.844 68.175 ;
     RECT  199.692 67.905 218.16 68.175 ;
     RECT  2.16 68.445 20.844 68.715 ;
     RECT  199.692 68.445 218.16 68.715 ;
     RECT  2.16 68.985 20.844 69.255 ;
     RECT  199.692 68.985 218.16 69.255 ;
     RECT  2.16 69.525 20.844 69.795 ;
     RECT  199.692 69.525 218.16 69.795 ;
     RECT  2.16 70.065 20.844 70.335 ;
     RECT  199.692 70.065 218.16 70.335 ;
     RECT  2.16 70.605 20.844 70.875 ;
     RECT  199.692 70.605 218.16 70.875 ;
     RECT  2.16 71.145 20.844 71.415 ;
     RECT  199.692 71.145 218.16 71.415 ;
     RECT  2.16 71.685 20.844 71.955 ;
     RECT  199.692 71.685 218.16 71.955 ;
     RECT  2.16 72.225 20.844 72.495 ;
     RECT  199.692 72.225 218.16 72.495 ;
     RECT  2.16 72.765 20.844 73.035 ;
     RECT  199.692 72.765 218.16 73.035 ;
     RECT  2.16 73.305 20.844 73.575 ;
     RECT  199.692 73.305 218.16 73.575 ;
     RECT  2.16 73.845 20.844 74.115 ;
     RECT  199.692 73.845 218.16 74.115 ;
     RECT  2.16 74.385 20.844 74.655 ;
     RECT  199.692 74.385 218.16 74.655 ;
     RECT  2.16 74.925 20.844 75.195 ;
     RECT  199.692 74.925 218.16 75.195 ;
     RECT  2.16 75.465 20.844 75.735 ;
     RECT  199.692 75.465 218.16 75.735 ;
     RECT  2.16 76.005 20.844 76.275 ;
     RECT  199.692 76.005 218.16 76.275 ;
     RECT  2.16 76.545 20.844 76.815 ;
     RECT  199.692 76.545 218.16 76.815 ;
     RECT  2.16 77.085 20.844 77.355 ;
     RECT  199.692 77.085 218.16 77.355 ;
     RECT  2.16 77.625 20.844 77.895 ;
     RECT  199.692 77.625 218.16 77.895 ;
     RECT  2.16 78.165 20.844 78.435 ;
     RECT  199.692 78.165 218.16 78.435 ;
     RECT  2.16 78.705 20.844 78.975 ;
     RECT  199.692 78.705 218.16 78.975 ;
     RECT  2.16 79.245 20.844 79.515 ;
     RECT  199.692 79.245 218.16 79.515 ;
     RECT  2.16 79.785 20.844 80.055 ;
     RECT  199.692 79.785 218.16 80.055 ;
     RECT  2.16 80.325 20.844 80.595 ;
     RECT  199.692 80.325 218.16 80.595 ;
     RECT  2.16 80.865 20.844 81.135 ;
     RECT  199.692 80.865 218.16 81.135 ;
     RECT  2.16 81.405 20.844 81.675 ;
     RECT  199.692 81.405 218.16 81.675 ;
     RECT  2.16 81.945 20.844 82.215 ;
     RECT  199.692 81.945 218.16 82.215 ;
     RECT  2.16 82.485 20.844 82.755 ;
     RECT  199.692 82.485 218.16 82.755 ;
     RECT  2.16 83.025 20.844 83.295 ;
     RECT  199.692 83.025 218.16 83.295 ;
     RECT  2.16 83.565 20.844 83.835 ;
     RECT  199.692 83.565 218.16 83.835 ;
     RECT  2.16 84.105 20.844 84.375 ;
     RECT  199.692 84.105 218.16 84.375 ;
     RECT  2.16 84.645 20.844 84.915 ;
     RECT  199.692 84.645 218.16 84.915 ;
     RECT  2.16 85.185 20.844 85.455 ;
     RECT  199.692 85.185 218.16 85.455 ;
     RECT  2.16 85.725 20.844 85.995 ;
     RECT  199.692 85.725 218.16 85.995 ;
     RECT  2.16 86.265 20.844 86.535 ;
     RECT  199.692 86.265 218.16 86.535 ;
     RECT  2.16 86.805 20.844 87.075 ;
     RECT  199.692 86.805 218.16 87.075 ;
     RECT  2.16 87.345 20.844 87.615 ;
     RECT  199.692 87.345 218.16 87.615 ;
     RECT  2.16 87.885 20.844 88.155 ;
     RECT  199.692 87.885 218.16 88.155 ;
     RECT  2.16 88.425 20.844 88.695 ;
     RECT  199.692 88.425 218.16 88.695 ;
     RECT  2.16 88.965 20.844 89.235 ;
     RECT  199.692 88.965 218.16 89.235 ;
     RECT  2.16 89.505 20.844 89.775 ;
     RECT  199.692 89.505 218.16 89.775 ;
     RECT  2.16 90.045 20.844 90.315 ;
     RECT  199.692 90.045 218.16 90.315 ;
     RECT  2.16 90.585 20.844 90.855 ;
     RECT  199.692 90.585 218.16 90.855 ;
     RECT  2.16 91.125 20.844 91.395 ;
     RECT  199.692 91.125 218.16 91.395 ;
     RECT  2.16 91.665 20.844 91.935 ;
     RECT  199.692 91.665 218.16 91.935 ;
     RECT  2.16 92.205 20.844 92.475 ;
     RECT  199.692 92.205 218.16 92.475 ;
     RECT  2.16 92.745 20.844 93.015 ;
     RECT  199.692 92.745 218.16 93.015 ;
     RECT  2.16 93.285 20.844 93.555 ;
     RECT  199.692 93.285 218.16 93.555 ;
     RECT  2.16 93.825 20.844 94.095 ;
     RECT  199.692 93.825 218.16 94.095 ;
     RECT  2.16 94.365 20.844 94.635 ;
     RECT  199.692 94.365 218.16 94.635 ;
     RECT  2.16 94.905 20.844 95.175 ;
     RECT  199.692 94.905 218.16 95.175 ;
     RECT  2.16 95.445 20.844 95.715 ;
     RECT  199.692 95.445 218.16 95.715 ;
     RECT  2.16 95.985 20.844 96.255 ;
     RECT  199.692 95.985 218.16 96.255 ;
     RECT  2.16 96.525 20.844 96.795 ;
     RECT  199.692 96.525 218.16 96.795 ;
     RECT  2.16 97.065 20.844 97.335 ;
     RECT  199.692 97.065 218.16 97.335 ;
     RECT  2.16 97.605 20.844 97.875 ;
     RECT  199.692 97.605 218.16 97.875 ;
     RECT  2.16 98.145 20.844 98.415 ;
     RECT  199.692 98.145 218.16 98.415 ;
     RECT  2.16 98.685 20.844 98.955 ;
     RECT  199.692 98.685 218.16 98.955 ;
     RECT  2.16 99.225 20.844 99.495 ;
     RECT  199.692 99.225 218.16 99.495 ;
     RECT  2.16 99.765 20.844 100.035 ;
     RECT  199.692 99.765 218.16 100.035 ;
     RECT  2.16 100.305 20.844 100.575 ;
     RECT  199.692 100.305 218.16 100.575 ;
     RECT  2.16 100.845 20.844 101.115 ;
     RECT  199.692 100.845 218.16 101.115 ;
     RECT  2.16 101.385 20.844 101.655 ;
     RECT  199.692 101.385 218.16 101.655 ;
     RECT  2.16 101.925 20.844 102.195 ;
     RECT  199.692 101.925 218.16 102.195 ;
     RECT  2.16 102.465 20.844 102.735 ;
     RECT  199.692 102.465 218.16 102.735 ;
     RECT  2.16 103.005 20.844 103.275 ;
     RECT  199.692 103.005 218.16 103.275 ;
     RECT  2.16 103.545 20.844 103.815 ;
     RECT  199.692 103.545 218.16 103.815 ;
     RECT  2.16 104.085 20.844 104.355 ;
     RECT  199.692 104.085 218.16 104.355 ;
     RECT  2.16 104.625 20.844 104.895 ;
     RECT  199.692 104.625 218.16 104.895 ;
     RECT  2.16 105.165 20.844 105.435 ;
     RECT  199.692 105.165 218.16 105.435 ;
     RECT  2.16 105.705 20.844 105.975 ;
     RECT  199.692 105.705 218.16 105.975 ;
     RECT  2.16 106.245 20.844 106.515 ;
     RECT  199.692 106.245 218.16 106.515 ;
     RECT  2.16 106.785 20.844 107.055 ;
     RECT  199.692 106.785 218.16 107.055 ;
     RECT  2.16 107.325 20.844 107.595 ;
     RECT  199.692 107.325 218.16 107.595 ;
     RECT  2.16 107.865 20.844 108.135 ;
     RECT  199.692 107.865 218.16 108.135 ;
     RECT  2.16 108.405 20.844 108.675 ;
     RECT  199.692 108.405 218.16 108.675 ;
     RECT  2.16 108.945 20.844 109.215 ;
     RECT  199.692 108.945 218.16 109.215 ;
     RECT  2.16 109.485 20.844 109.755 ;
     RECT  199.692 109.485 218.16 109.755 ;
     RECT  2.16 110.025 20.844 110.295 ;
     RECT  199.692 110.025 218.16 110.295 ;
     RECT  2.16 110.565 20.844 110.835 ;
     RECT  199.692 110.565 218.16 110.835 ;
     RECT  2.16 111.105 20.844 111.375 ;
     RECT  199.692 111.105 218.16 111.375 ;
     RECT  2.16 111.645 20.844 111.915 ;
     RECT  199.692 111.645 218.16 111.915 ;
     RECT  2.16 112.185 20.844 112.455 ;
     RECT  199.692 112.185 218.16 112.455 ;
     RECT  2.16 112.725 20.844 112.995 ;
     RECT  199.692 112.725 218.16 112.995 ;
     RECT  2.16 113.265 20.844 113.535 ;
     RECT  199.692 113.265 218.16 113.535 ;
     RECT  2.16 113.805 20.844 114.075 ;
     RECT  199.692 113.805 218.16 114.075 ;
     RECT  2.16 114.345 20.844 114.615 ;
     RECT  199.692 114.345 218.16 114.615 ;
     RECT  2.16 114.885 20.844 115.155 ;
     RECT  199.692 114.885 218.16 115.155 ;
     RECT  2.16 115.425 20.844 115.695 ;
     RECT  199.692 115.425 218.16 115.695 ;
     RECT  2.16 115.965 20.844 116.235 ;
     RECT  199.692 115.965 218.16 116.235 ;
     RECT  2.16 116.505 20.844 116.775 ;
     RECT  199.692 116.505 218.16 116.775 ;
     RECT  2.16 117.045 20.844 117.315 ;
     RECT  199.692 117.045 218.16 117.315 ;
     RECT  2.16 117.585 20.844 117.855 ;
     RECT  199.692 117.585 218.16 117.855 ;
     RECT  2.16 118.125 20.844 118.395 ;
     RECT  199.692 118.125 218.16 118.395 ;
     RECT  2.16 118.665 20.844 118.935 ;
     RECT  199.692 118.665 218.16 118.935 ;
     RECT  2.16 119.205 20.844 119.475 ;
     RECT  199.692 119.205 218.16 119.475 ;
     RECT  2.16 119.745 20.844 120.015 ;
     RECT  199.692 119.745 218.16 120.015 ;
     RECT  2.16 120.285 20.844 120.555 ;
     RECT  199.692 120.285 218.16 120.555 ;
     RECT  2.16 120.825 20.844 121.095 ;
     RECT  199.692 120.825 218.16 121.095 ;
     RECT  2.16 121.365 20.844 121.635 ;
     RECT  199.692 121.365 218.16 121.635 ;
     RECT  2.16 121.905 20.844 122.175 ;
     RECT  199.692 121.905 218.16 122.175 ;
     RECT  2.16 122.445 20.844 122.715 ;
     RECT  199.692 122.445 218.16 122.715 ;
     RECT  2.16 122.985 20.844 123.255 ;
     RECT  199.692 122.985 218.16 123.255 ;
     RECT  2.16 123.525 20.844 123.795 ;
     RECT  199.692 123.525 218.16 123.795 ;
     RECT  2.16 124.065 20.844 124.335 ;
     RECT  199.692 124.065 218.16 124.335 ;
     RECT  2.16 124.605 20.844 124.875 ;
     RECT  199.692 124.605 218.16 124.875 ;
     RECT  2.16 125.145 20.844 125.415 ;
     RECT  199.692 125.145 218.16 125.415 ;
     RECT  2.16 125.685 20.844 125.955 ;
     RECT  199.692 125.685 218.16 125.955 ;
     RECT  2.16 126.225 20.844 126.495 ;
     RECT  199.692 126.225 218.16 126.495 ;
     RECT  2.16 126.765 218.16 127.035 ;
     RECT  2.16 127.305 218.16 127.575 ;
     RECT  2.16 127.845 218.16 128.115 ;
     RECT  2.16 128.385 218.16 128.655 ;
     RECT  2.16 128.925 218.16 129.195 ;
     RECT  2.16 129.465 218.16 129.735 ;
     RECT  2.16 130.005 218.16 130.275 ;
     RECT  2.16 130.545 218.16 130.815 ;
     RECT  2.16 131.085 218.16 131.355 ;
     RECT  2.16 131.625 218.16 131.895 ;
     RECT  2.16 132.165 218.16 132.435 ;
     RECT  2.16 132.705 218.16 132.975 ;
     RECT  2.16 133.245 218.16 133.515 ;
     RECT  2.16 133.785 218.16 134.055 ;
     RECT  2.16 134.325 218.16 134.595 ;
     RECT  2.16 134.865 218.16 135.135 ;
     RECT  2.16 135.405 218.16 135.675 ;
     RECT  2.16 135.945 218.16 136.215 ;
     RECT  2.16 136.485 218.16 136.755 ;
     RECT  2.16 137.025 218.16 137.295 ;
     RECT  2.16 137.565 218.16 137.835 ;
     RECT  2.16 138.105 218.16 138.375 ;
     RECT  2.16 138.645 218.16 138.915 ;
     RECT  2.16 139.185 218.16 139.455 ;
     RECT  2.16 139.725 218.16 139.995 ;
     RECT  2.16 140.265 218.16 140.535 ;
     RECT  2.16 140.805 218.16 141.075 ;
     RECT  2.16 141.345 218.16 141.615 ;
     RECT  2.16 141.885 218.16 142.155 ;
     RECT  2.16 142.425 218.16 142.695 ;
     RECT  2.16 142.965 218.16 143.235 ;
     RECT  2.16 143.505 218.16 143.775 ;
     RECT  2.16 144.045 218.16 144.315 ;
     RECT  2.16 144.585 218.16 144.855 ;
     RECT  2.16 145.125 218.16 145.395 ;
     RECT  2.16 145.665 218.16 145.935 ;
     RECT  2.16 146.205 218.16 146.475 ;
     RECT  2.16 146.745 218.16 147.015 ;
     RECT  2.16 147.285 218.16 147.555 ;
     RECT  2.16 147.825 218.16 148.095 ;
     RECT  2.16 148.365 218.16 148.635 ;
     RECT  2.16 148.905 218.16 149.175 ;
     RECT  2.16 149.445 218.16 149.715 ;
     RECT  2.16 149.985 218.16 150.255 ;
     RECT  2.16 150.525 218.16 150.795 ;
     RECT  2.16 151.065 218.16 151.335 ;
     RECT  2.16 151.605 218.16 151.875 ;
     RECT  2.16 152.145 218.16 152.415 ;
     RECT  2.16 152.685 218.16 152.955 ;
     RECT  2.16 153.225 218.16 153.495 ;
     RECT  2.16 153.765 218.16 154.035 ;
     RECT  2.16 154.305 218.16 154.575 ;
     RECT  2.16 154.845 218.16 155.115 ;
     RECT  2.16 155.385 218.16 155.655 ;
     RECT  2.16 155.925 218.16 156.195 ;
     RECT  2.16 156.465 218.16 156.735 ;
     RECT  2.16 157.005 218.16 157.275 ;
     RECT  2.16 157.545 218.16 157.815 ;
     RECT  2.16 158.085 218.16 158.355 ;
     RECT  2.16 158.625 218.16 158.895 ;
     RECT  2.16 159.165 218.16 159.435 ;
     RECT  2.16 159.705 218.16 159.975 ;
     RECT  2.16 160.245 218.16 160.515 ;
     RECT  2.16 160.785 218.16 161.055 ;
     RECT  2.16 161.325 218.16 161.595 ;
     RECT  2.16 161.865 218.16 162.135 ;
     RECT  2.16 162.405 218.16 162.675 ;
     RECT  2.16 162.945 218.16 163.215 ;
     RECT  2.16 163.485 218.16 163.755 ;
     RECT  2.16 164.025 218.16 164.295 ;
     RECT  2.16 164.565 218.16 164.835 ;
     RECT  2.16 165.105 218.16 165.375 ;
     RECT  2.16 165.645 218.16 165.915 ;
     RECT  2.16 166.185 218.16 166.455 ;
     RECT  2.16 166.725 218.16 166.995 ;
     RECT  2.16 167.265 218.16 167.535 ;
     RECT  2.16 167.805 218.16 168.075 ;
     RECT  2.16 168.345 218.16 168.615 ;
     RECT  2.16 168.885 218.16 169.155 ;
     RECT  2.16 169.425 218.16 169.695 ;
     RECT  2.16 169.965 218.16 170.235 ;
     RECT  2.16 170.505 218.16 170.775 ;
     RECT  2.16 171.045 218.16 171.315 ;
     RECT  2.16 171.585 218.16 171.855 ;
     RECT  2.16 172.125 218.16 172.395 ;
     RECT  2.16 172.665 218.16 172.935 ;
     RECT  2.16 173.205 218.16 173.475 ;
     RECT  2.16 173.745 218.16 174.015 ;
     RECT  2.16 174.285 218.16 174.555 ;
     RECT  2.16 174.825 218.16 174.96 ;
    LAYER RVTP ;
     RECT  2.16 2.295 218.16 2.565 ;
     RECT  2.16 2.835 218.16 3.105 ;
     RECT  2.16 3.375 218.16 3.645 ;
     RECT  2.16 3.915 218.16 4.185 ;
     RECT  2.16 4.455 218.16 4.725 ;
     RECT  2.16 4.995 218.16 5.265 ;
     RECT  2.16 5.535 218.16 5.805 ;
     RECT  2.16 6.075 218.16 6.345 ;
     RECT  2.16 6.615 218.16 6.885 ;
     RECT  2.16 7.155 218.16 7.425 ;
     RECT  2.16 7.695 218.16 7.965 ;
     RECT  2.16 8.235 218.16 8.505 ;
     RECT  2.16 8.775 218.16 9.045 ;
     RECT  2.16 9.315 218.16 9.585 ;
     RECT  2.16 9.855 218.16 10.125 ;
     RECT  2.16 10.395 218.16 10.665 ;
     RECT  2.16 10.935 218.16 11.205 ;
     RECT  2.16 11.475 218.16 11.745 ;
     RECT  2.16 12.015 218.16 12.285 ;
     RECT  2.16 12.555 218.16 12.825 ;
     RECT  2.16 13.095 218.16 13.365 ;
     RECT  2.16 13.635 218.16 13.905 ;
     RECT  2.16 14.175 218.16 14.445 ;
     RECT  2.16 14.715 218.16 14.985 ;
     RECT  2.16 15.255 218.16 15.525 ;
     RECT  2.16 15.795 218.16 16.065 ;
     RECT  2.16 16.335 218.16 16.605 ;
     RECT  2.16 16.875 218.16 17.145 ;
     RECT  2.16 17.415 218.16 17.685 ;
     RECT  2.16 17.955 218.16 18.225 ;
     RECT  2.16 18.495 218.16 18.765 ;
     RECT  2.16 19.035 218.16 19.305 ;
     RECT  2.16 19.575 218.16 19.845 ;
     RECT  2.16 20.115 218.16 20.385 ;
     RECT  2.16 20.655 218.16 20.925 ;
     RECT  2.16 21.195 218.16 21.465 ;
     RECT  2.16 21.735 218.16 22.005 ;
     RECT  2.16 22.275 218.16 22.545 ;
     RECT  2.16 22.815 218.16 23.085 ;
     RECT  2.16 23.355 218.16 23.625 ;
     RECT  2.16 23.895 218.16 24.165 ;
     RECT  2.16 24.435 218.16 24.705 ;
     RECT  2.16 24.975 218.16 25.245 ;
     RECT  2.16 25.515 218.16 25.785 ;
     RECT  2.16 26.055 218.16 26.325 ;
     RECT  2.16 26.595 218.16 26.865 ;
     RECT  2.16 27.135 218.16 27.405 ;
     RECT  2.16 27.675 218.16 27.945 ;
     RECT  2.16 28.215 218.16 28.485 ;
     RECT  2.16 28.755 218.16 29.025 ;
     RECT  2.16 29.295 218.16 29.565 ;
     RECT  2.16 29.835 218.16 30.105 ;
     RECT  2.16 30.375 218.16 30.645 ;
     RECT  2.16 30.915 218.16 31.185 ;
     RECT  2.16 31.455 218.16 31.725 ;
     RECT  2.16 31.995 218.16 32.265 ;
     RECT  2.16 32.535 218.16 32.805 ;
     RECT  2.16 33.075 218.16 33.345 ;
     RECT  2.16 33.615 218.16 33.885 ;
     RECT  2.16 34.155 218.16 34.425 ;
     RECT  2.16 34.695 218.16 34.965 ;
     RECT  2.16 35.235 218.16 35.505 ;
     RECT  2.16 35.775 218.16 36.045 ;
     RECT  2.16 36.315 218.16 36.585 ;
     RECT  2.16 36.855 218.16 37.125 ;
     RECT  2.16 37.395 218.16 37.665 ;
     RECT  2.16 37.935 218.16 38.205 ;
     RECT  2.16 38.475 218.16 38.745 ;
     RECT  2.16 39.015 218.16 39.285 ;
     RECT  2.16 39.555 218.16 39.825 ;
     RECT  2.16 40.095 218.16 40.365 ;
     RECT  2.16 40.635 218.16 40.905 ;
     RECT  2.16 41.175 218.16 41.445 ;
     RECT  2.16 41.715 218.16 41.985 ;
     RECT  2.16 42.255 218.16 42.525 ;
     RECT  2.16 42.795 218.16 43.065 ;
     RECT  2.16 43.335 218.16 43.605 ;
     RECT  2.16 43.875 218.16 44.145 ;
     RECT  2.16 44.415 218.16 44.685 ;
     RECT  2.16 44.955 218.16 45.225 ;
     RECT  2.16 45.495 218.16 45.765 ;
     RECT  2.16 46.035 218.16 46.305 ;
     RECT  2.16 46.575 218.16 46.845 ;
     RECT  2.16 47.115 218.16 47.385 ;
     RECT  2.16 47.655 218.16 47.925 ;
     RECT  2.16 48.195 218.16 48.465 ;
     RECT  2.16 48.735 218.16 49.005 ;
     RECT  2.16 49.275 218.16 49.545 ;
     RECT  2.16 49.815 218.16 50.085 ;
     RECT  2.16 50.355 218.16 50.625 ;
     RECT  2.16 50.895 218.16 51.165 ;
     RECT  2.16 51.435 218.16 51.705 ;
     RECT  2.16 51.975 20.844 52.245 ;
     RECT  199.692 51.975 218.16 52.245 ;
     RECT  2.16 52.515 20.844 52.785 ;
     RECT  199.692 52.515 218.16 52.785 ;
     RECT  2.16 53.055 20.844 53.325 ;
     RECT  199.692 53.055 218.16 53.325 ;
     RECT  2.16 53.595 20.844 53.865 ;
     RECT  199.692 53.595 218.16 53.865 ;
     RECT  2.16 54.135 20.844 54.405 ;
     RECT  199.692 54.135 218.16 54.405 ;
     RECT  2.16 54.675 20.844 54.945 ;
     RECT  199.692 54.675 218.16 54.945 ;
     RECT  2.16 55.215 20.844 55.485 ;
     RECT  199.692 55.215 218.16 55.485 ;
     RECT  2.16 55.755 20.844 56.025 ;
     RECT  199.692 55.755 218.16 56.025 ;
     RECT  2.16 56.295 20.844 56.565 ;
     RECT  199.692 56.295 218.16 56.565 ;
     RECT  2.16 56.835 20.844 57.105 ;
     RECT  199.692 56.835 218.16 57.105 ;
     RECT  2.16 57.375 20.844 57.645 ;
     RECT  199.692 57.375 218.16 57.645 ;
     RECT  2.16 57.915 20.844 58.185 ;
     RECT  199.692 57.915 218.16 58.185 ;
     RECT  2.16 58.455 20.844 58.725 ;
     RECT  199.692 58.455 218.16 58.725 ;
     RECT  2.16 58.995 20.844 59.265 ;
     RECT  199.692 58.995 218.16 59.265 ;
     RECT  2.16 59.535 20.844 59.805 ;
     RECT  199.692 59.535 218.16 59.805 ;
     RECT  2.16 60.075 20.844 60.345 ;
     RECT  199.692 60.075 218.16 60.345 ;
     RECT  2.16 60.615 20.844 60.885 ;
     RECT  199.692 60.615 218.16 60.885 ;
     RECT  2.16 61.155 20.844 61.425 ;
     RECT  199.692 61.155 218.16 61.425 ;
     RECT  2.16 61.695 20.844 61.965 ;
     RECT  199.692 61.695 218.16 61.965 ;
     RECT  2.16 62.235 20.844 62.505 ;
     RECT  199.692 62.235 218.16 62.505 ;
     RECT  2.16 62.775 20.844 63.045 ;
     RECT  199.692 62.775 218.16 63.045 ;
     RECT  2.16 63.315 20.844 63.585 ;
     RECT  199.692 63.315 218.16 63.585 ;
     RECT  2.16 63.855 20.844 64.125 ;
     RECT  199.692 63.855 218.16 64.125 ;
     RECT  2.16 64.395 20.844 64.665 ;
     RECT  199.692 64.395 218.16 64.665 ;
     RECT  2.16 64.935 20.844 65.205 ;
     RECT  199.692 64.935 218.16 65.205 ;
     RECT  2.16 65.475 20.844 65.745 ;
     RECT  199.692 65.475 218.16 65.745 ;
     RECT  2.16 66.015 20.844 66.285 ;
     RECT  199.692 66.015 218.16 66.285 ;
     RECT  2.16 66.555 20.844 66.825 ;
     RECT  199.692 66.555 218.16 66.825 ;
     RECT  2.16 67.095 20.844 67.365 ;
     RECT  199.692 67.095 218.16 67.365 ;
     RECT  2.16 67.635 20.844 67.905 ;
     RECT  199.692 67.635 218.16 67.905 ;
     RECT  2.16 68.175 20.844 68.445 ;
     RECT  199.692 68.175 218.16 68.445 ;
     RECT  2.16 68.715 20.844 68.985 ;
     RECT  199.692 68.715 218.16 68.985 ;
     RECT  2.16 69.255 20.844 69.525 ;
     RECT  199.692 69.255 218.16 69.525 ;
     RECT  2.16 69.795 20.844 70.065 ;
     RECT  199.692 69.795 218.16 70.065 ;
     RECT  2.16 70.335 20.844 70.605 ;
     RECT  199.692 70.335 218.16 70.605 ;
     RECT  2.16 70.875 20.844 71.145 ;
     RECT  199.692 70.875 218.16 71.145 ;
     RECT  2.16 71.415 20.844 71.685 ;
     RECT  199.692 71.415 218.16 71.685 ;
     RECT  2.16 71.955 20.844 72.225 ;
     RECT  199.692 71.955 218.16 72.225 ;
     RECT  2.16 72.495 20.844 72.765 ;
     RECT  199.692 72.495 218.16 72.765 ;
     RECT  2.16 73.035 20.844 73.305 ;
     RECT  199.692 73.035 218.16 73.305 ;
     RECT  2.16 73.575 20.844 73.845 ;
     RECT  199.692 73.575 218.16 73.845 ;
     RECT  2.16 74.115 20.844 74.385 ;
     RECT  199.692 74.115 218.16 74.385 ;
     RECT  2.16 74.655 20.844 74.925 ;
     RECT  199.692 74.655 218.16 74.925 ;
     RECT  2.16 75.195 20.844 75.465 ;
     RECT  199.692 75.195 218.16 75.465 ;
     RECT  2.16 75.735 20.844 76.005 ;
     RECT  199.692 75.735 218.16 76.005 ;
     RECT  2.16 76.275 20.844 76.545 ;
     RECT  199.692 76.275 218.16 76.545 ;
     RECT  2.16 76.815 20.844 77.085 ;
     RECT  199.692 76.815 218.16 77.085 ;
     RECT  2.16 77.355 20.844 77.625 ;
     RECT  199.692 77.355 218.16 77.625 ;
     RECT  2.16 77.895 20.844 78.165 ;
     RECT  199.692 77.895 218.16 78.165 ;
     RECT  2.16 78.435 20.844 78.705 ;
     RECT  199.692 78.435 218.16 78.705 ;
     RECT  2.16 78.975 20.844 79.245 ;
     RECT  199.692 78.975 218.16 79.245 ;
     RECT  2.16 79.515 20.844 79.785 ;
     RECT  199.692 79.515 218.16 79.785 ;
     RECT  2.16 80.055 20.844 80.325 ;
     RECT  199.692 80.055 218.16 80.325 ;
     RECT  2.16 80.595 20.844 80.865 ;
     RECT  199.692 80.595 218.16 80.865 ;
     RECT  2.16 81.135 20.844 81.405 ;
     RECT  199.692 81.135 218.16 81.405 ;
     RECT  2.16 81.675 20.844 81.945 ;
     RECT  199.692 81.675 218.16 81.945 ;
     RECT  2.16 82.215 20.844 82.485 ;
     RECT  199.692 82.215 218.16 82.485 ;
     RECT  2.16 82.755 20.844 83.025 ;
     RECT  199.692 82.755 218.16 83.025 ;
     RECT  2.16 83.295 20.844 83.565 ;
     RECT  199.692 83.295 218.16 83.565 ;
     RECT  2.16 83.835 20.844 84.105 ;
     RECT  199.692 83.835 218.16 84.105 ;
     RECT  2.16 84.375 20.844 84.645 ;
     RECT  199.692 84.375 218.16 84.645 ;
     RECT  2.16 84.915 20.844 85.185 ;
     RECT  199.692 84.915 218.16 85.185 ;
     RECT  2.16 85.455 20.844 85.725 ;
     RECT  199.692 85.455 218.16 85.725 ;
     RECT  2.16 85.995 20.844 86.265 ;
     RECT  199.692 85.995 218.16 86.265 ;
     RECT  2.16 86.535 20.844 86.805 ;
     RECT  199.692 86.535 218.16 86.805 ;
     RECT  2.16 87.075 20.844 87.345 ;
     RECT  199.692 87.075 218.16 87.345 ;
     RECT  2.16 87.615 20.844 87.885 ;
     RECT  199.692 87.615 218.16 87.885 ;
     RECT  2.16 88.155 20.844 88.425 ;
     RECT  199.692 88.155 218.16 88.425 ;
     RECT  2.16 88.695 20.844 88.965 ;
     RECT  199.692 88.695 218.16 88.965 ;
     RECT  2.16 89.235 20.844 89.505 ;
     RECT  199.692 89.235 218.16 89.505 ;
     RECT  2.16 89.775 20.844 90.045 ;
     RECT  199.692 89.775 218.16 90.045 ;
     RECT  2.16 90.315 20.844 90.585 ;
     RECT  199.692 90.315 218.16 90.585 ;
     RECT  2.16 90.855 20.844 91.125 ;
     RECT  199.692 90.855 218.16 91.125 ;
     RECT  2.16 91.395 20.844 91.665 ;
     RECT  199.692 91.395 218.16 91.665 ;
     RECT  2.16 91.935 20.844 92.205 ;
     RECT  199.692 91.935 218.16 92.205 ;
     RECT  2.16 92.475 20.844 92.745 ;
     RECT  199.692 92.475 218.16 92.745 ;
     RECT  2.16 93.015 20.844 93.285 ;
     RECT  199.692 93.015 218.16 93.285 ;
     RECT  2.16 93.555 20.844 93.825 ;
     RECT  199.692 93.555 218.16 93.825 ;
     RECT  2.16 94.095 20.844 94.365 ;
     RECT  199.692 94.095 218.16 94.365 ;
     RECT  2.16 94.635 20.844 94.905 ;
     RECT  199.692 94.635 218.16 94.905 ;
     RECT  2.16 95.175 20.844 95.445 ;
     RECT  199.692 95.175 218.16 95.445 ;
     RECT  2.16 95.715 20.844 95.985 ;
     RECT  199.692 95.715 218.16 95.985 ;
     RECT  2.16 96.255 20.844 96.525 ;
     RECT  199.692 96.255 218.16 96.525 ;
     RECT  2.16 96.795 20.844 97.065 ;
     RECT  199.692 96.795 218.16 97.065 ;
     RECT  2.16 97.335 20.844 97.605 ;
     RECT  199.692 97.335 218.16 97.605 ;
     RECT  2.16 97.875 20.844 98.145 ;
     RECT  199.692 97.875 218.16 98.145 ;
     RECT  2.16 98.415 20.844 98.685 ;
     RECT  199.692 98.415 218.16 98.685 ;
     RECT  2.16 98.955 20.844 99.225 ;
     RECT  199.692 98.955 218.16 99.225 ;
     RECT  2.16 99.495 20.844 99.765 ;
     RECT  199.692 99.495 218.16 99.765 ;
     RECT  2.16 100.035 20.844 100.305 ;
     RECT  199.692 100.035 218.16 100.305 ;
     RECT  2.16 100.575 20.844 100.845 ;
     RECT  199.692 100.575 218.16 100.845 ;
     RECT  2.16 101.115 20.844 101.385 ;
     RECT  199.692 101.115 218.16 101.385 ;
     RECT  2.16 101.655 20.844 101.925 ;
     RECT  199.692 101.655 218.16 101.925 ;
     RECT  2.16 102.195 20.844 102.465 ;
     RECT  199.692 102.195 218.16 102.465 ;
     RECT  2.16 102.735 20.844 103.005 ;
     RECT  199.692 102.735 218.16 103.005 ;
     RECT  2.16 103.275 20.844 103.545 ;
     RECT  199.692 103.275 218.16 103.545 ;
     RECT  2.16 103.815 20.844 104.085 ;
     RECT  199.692 103.815 218.16 104.085 ;
     RECT  2.16 104.355 20.844 104.625 ;
     RECT  199.692 104.355 218.16 104.625 ;
     RECT  2.16 104.895 20.844 105.165 ;
     RECT  199.692 104.895 218.16 105.165 ;
     RECT  2.16 105.435 20.844 105.705 ;
     RECT  199.692 105.435 218.16 105.705 ;
     RECT  2.16 105.975 20.844 106.245 ;
     RECT  199.692 105.975 218.16 106.245 ;
     RECT  2.16 106.515 20.844 106.785 ;
     RECT  199.692 106.515 218.16 106.785 ;
     RECT  2.16 107.055 20.844 107.325 ;
     RECT  199.692 107.055 218.16 107.325 ;
     RECT  2.16 107.595 20.844 107.865 ;
     RECT  199.692 107.595 218.16 107.865 ;
     RECT  2.16 108.135 20.844 108.405 ;
     RECT  199.692 108.135 218.16 108.405 ;
     RECT  2.16 108.675 20.844 108.945 ;
     RECT  199.692 108.675 218.16 108.945 ;
     RECT  2.16 109.215 20.844 109.485 ;
     RECT  199.692 109.215 218.16 109.485 ;
     RECT  2.16 109.755 20.844 110.025 ;
     RECT  199.692 109.755 218.16 110.025 ;
     RECT  2.16 110.295 20.844 110.565 ;
     RECT  199.692 110.295 218.16 110.565 ;
     RECT  2.16 110.835 20.844 111.105 ;
     RECT  199.692 110.835 218.16 111.105 ;
     RECT  2.16 111.375 20.844 111.645 ;
     RECT  199.692 111.375 218.16 111.645 ;
     RECT  2.16 111.915 20.844 112.185 ;
     RECT  199.692 111.915 218.16 112.185 ;
     RECT  2.16 112.455 20.844 112.725 ;
     RECT  199.692 112.455 218.16 112.725 ;
     RECT  2.16 112.995 20.844 113.265 ;
     RECT  199.692 112.995 218.16 113.265 ;
     RECT  2.16 113.535 20.844 113.805 ;
     RECT  199.692 113.535 218.16 113.805 ;
     RECT  2.16 114.075 20.844 114.345 ;
     RECT  199.692 114.075 218.16 114.345 ;
     RECT  2.16 114.615 20.844 114.885 ;
     RECT  199.692 114.615 218.16 114.885 ;
     RECT  2.16 115.155 20.844 115.425 ;
     RECT  199.692 115.155 218.16 115.425 ;
     RECT  2.16 115.695 20.844 115.965 ;
     RECT  199.692 115.695 218.16 115.965 ;
     RECT  2.16 116.235 20.844 116.505 ;
     RECT  199.692 116.235 218.16 116.505 ;
     RECT  2.16 116.775 20.844 117.045 ;
     RECT  199.692 116.775 218.16 117.045 ;
     RECT  2.16 117.315 20.844 117.585 ;
     RECT  199.692 117.315 218.16 117.585 ;
     RECT  2.16 117.855 20.844 118.125 ;
     RECT  199.692 117.855 218.16 118.125 ;
     RECT  2.16 118.395 20.844 118.665 ;
     RECT  199.692 118.395 218.16 118.665 ;
     RECT  2.16 118.935 20.844 119.205 ;
     RECT  199.692 118.935 218.16 119.205 ;
     RECT  2.16 119.475 20.844 119.745 ;
     RECT  199.692 119.475 218.16 119.745 ;
     RECT  2.16 120.015 20.844 120.285 ;
     RECT  199.692 120.015 218.16 120.285 ;
     RECT  2.16 120.555 20.844 120.825 ;
     RECT  199.692 120.555 218.16 120.825 ;
     RECT  2.16 121.095 20.844 121.365 ;
     RECT  199.692 121.095 218.16 121.365 ;
     RECT  2.16 121.635 20.844 121.905 ;
     RECT  199.692 121.635 218.16 121.905 ;
     RECT  2.16 122.175 20.844 122.445 ;
     RECT  199.692 122.175 218.16 122.445 ;
     RECT  2.16 122.715 20.844 122.985 ;
     RECT  199.692 122.715 218.16 122.985 ;
     RECT  2.16 123.255 20.844 123.525 ;
     RECT  199.692 123.255 218.16 123.525 ;
     RECT  2.16 123.795 20.844 124.065 ;
     RECT  199.692 123.795 218.16 124.065 ;
     RECT  2.16 124.335 20.844 124.605 ;
     RECT  199.692 124.335 218.16 124.605 ;
     RECT  2.16 124.875 20.844 125.145 ;
     RECT  199.692 124.875 218.16 125.145 ;
     RECT  2.16 125.415 20.844 125.685 ;
     RECT  199.692 125.415 218.16 125.685 ;
     RECT  2.16 125.955 20.844 126.225 ;
     RECT  199.692 125.955 218.16 126.225 ;
     RECT  2.16 126.495 20.844 126.63 ;
     RECT  199.692 126.495 218.16 126.63 ;
     RECT  2.16 126.63 218.16 126.765 ;
     RECT  2.16 127.035 218.16 127.305 ;
     RECT  2.16 127.575 218.16 127.845 ;
     RECT  2.16 128.115 218.16 128.385 ;
     RECT  2.16 128.655 218.16 128.925 ;
     RECT  2.16 129.195 218.16 129.465 ;
     RECT  2.16 129.735 218.16 130.005 ;
     RECT  2.16 130.275 218.16 130.545 ;
     RECT  2.16 130.815 218.16 131.085 ;
     RECT  2.16 131.355 218.16 131.625 ;
     RECT  2.16 131.895 218.16 132.165 ;
     RECT  2.16 132.435 218.16 132.705 ;
     RECT  2.16 132.975 218.16 133.245 ;
     RECT  2.16 133.515 218.16 133.785 ;
     RECT  2.16 134.055 218.16 134.325 ;
     RECT  2.16 134.595 218.16 134.865 ;
     RECT  2.16 135.135 218.16 135.405 ;
     RECT  2.16 135.675 218.16 135.945 ;
     RECT  2.16 136.215 218.16 136.485 ;
     RECT  2.16 136.755 218.16 137.025 ;
     RECT  2.16 137.295 218.16 137.565 ;
     RECT  2.16 137.835 218.16 138.105 ;
     RECT  2.16 138.375 218.16 138.645 ;
     RECT  2.16 138.915 218.16 139.185 ;
     RECT  2.16 139.455 218.16 139.725 ;
     RECT  2.16 139.995 218.16 140.265 ;
     RECT  2.16 140.535 218.16 140.805 ;
     RECT  2.16 141.075 218.16 141.345 ;
     RECT  2.16 141.615 218.16 141.885 ;
     RECT  2.16 142.155 218.16 142.425 ;
     RECT  2.16 142.695 218.16 142.965 ;
     RECT  2.16 143.235 218.16 143.505 ;
     RECT  2.16 143.775 218.16 144.045 ;
     RECT  2.16 144.315 218.16 144.585 ;
     RECT  2.16 144.855 218.16 145.125 ;
     RECT  2.16 145.395 218.16 145.665 ;
     RECT  2.16 145.935 218.16 146.205 ;
     RECT  2.16 146.475 218.16 146.745 ;
     RECT  2.16 147.015 218.16 147.285 ;
     RECT  2.16 147.555 218.16 147.825 ;
     RECT  2.16 148.095 218.16 148.365 ;
     RECT  2.16 148.635 218.16 148.905 ;
     RECT  2.16 149.175 218.16 149.445 ;
     RECT  2.16 149.715 218.16 149.985 ;
     RECT  2.16 150.255 218.16 150.525 ;
     RECT  2.16 150.795 218.16 151.065 ;
     RECT  2.16 151.335 218.16 151.605 ;
     RECT  2.16 151.875 218.16 152.145 ;
     RECT  2.16 152.415 218.16 152.685 ;
     RECT  2.16 152.955 218.16 153.225 ;
     RECT  2.16 153.495 218.16 153.765 ;
     RECT  2.16 154.035 218.16 154.305 ;
     RECT  2.16 154.575 218.16 154.845 ;
     RECT  2.16 155.115 218.16 155.385 ;
     RECT  2.16 155.655 218.16 155.925 ;
     RECT  2.16 156.195 218.16 156.465 ;
     RECT  2.16 156.735 218.16 157.005 ;
     RECT  2.16 157.275 218.16 157.545 ;
     RECT  2.16 157.815 218.16 158.085 ;
     RECT  2.16 158.355 218.16 158.625 ;
     RECT  2.16 158.895 218.16 159.165 ;
     RECT  2.16 159.435 218.16 159.705 ;
     RECT  2.16 159.975 218.16 160.245 ;
     RECT  2.16 160.515 218.16 160.785 ;
     RECT  2.16 161.055 218.16 161.325 ;
     RECT  2.16 161.595 218.16 161.865 ;
     RECT  2.16 162.135 218.16 162.405 ;
     RECT  2.16 162.675 218.16 162.945 ;
     RECT  2.16 163.215 218.16 163.485 ;
     RECT  2.16 163.755 218.16 164.025 ;
     RECT  2.16 164.295 218.16 164.565 ;
     RECT  2.16 164.835 218.16 165.105 ;
     RECT  2.16 165.375 218.16 165.645 ;
     RECT  2.16 165.915 218.16 166.185 ;
     RECT  2.16 166.455 218.16 166.725 ;
     RECT  2.16 166.995 218.16 167.265 ;
     RECT  2.16 167.535 218.16 167.805 ;
     RECT  2.16 168.075 218.16 168.345 ;
     RECT  2.16 168.615 218.16 168.885 ;
     RECT  2.16 169.155 218.16 169.425 ;
     RECT  2.16 169.695 218.16 169.965 ;
     RECT  2.16 170.235 218.16 170.505 ;
     RECT  2.16 170.775 218.16 171.045 ;
     RECT  2.16 171.315 218.16 171.585 ;
     RECT  2.16 171.855 218.16 172.125 ;
     RECT  2.16 172.395 218.16 172.665 ;
     RECT  2.16 172.935 218.16 173.205 ;
     RECT  2.16 173.475 218.16 173.745 ;
     RECT  2.16 174.015 218.16 174.285 ;
     RECT  2.16 174.555 218.16 174.825 ;
    LAYER M1 ;
     RECT  2.16 2.151 218.16 51.849 ;
     RECT  22.896 54 197.64 124.488 ;
     RECT  2.16 51.849 20.844 126.621 ;
     RECT  199.692 51.849 218.16 126.621 ;
     RECT  2.16 126.621 218.16 174.969 ;
    LAYER M2 ;
     RECT  0.103 47.052 0.139 48.69 ;
     RECT  0.103 52.02 0.139 52.74 ;
     RECT  0.103 53.532 0.139 54.36 ;
     RECT  0.103 58.122 0.139 58.14 ;
     RECT  0.103 59.004 0.139 59.022 ;
     RECT  0.103 59.778 0.139 60.102 ;
     RECT  0.103 62.172 0.139 64.08 ;
     RECT  0.103 94.41 0.139 94.428 ;
     RECT  0.103 95.49 0.139 95.976 ;
     RECT  0.103 83.772 0.175 83.79 ;
     RECT  0.103 85.194 0.175 85.212 ;
     RECT  0.175 85.194 0.203 85.518 ;
     RECT  0.203 85.5 0.211 85.518 ;
     RECT  0.103 88.2 0.211 89.064 ;
     RECT  0.211 91.332 0.319 91.35 ;
     RECT  0.211 85.5 0.347 86.256 ;
     RECT  0.139 94.41 0.347 95.976 ;
     RECT  0.139 51.948 0.535 54.36 ;
     RECT  0.139 57.996 0.535 60.102 ;
     RECT  0.175 83.772 0.535 84.168 ;
     RECT  0.319 90.594 0.535 91.35 ;
     RECT  0.103 92.214 0.535 92.232 ;
     RECT  0.139 97.002 0.823 97.02 ;
     RECT  0.139 47.052 1.147 48.762 ;
     RECT  0.103 56.88 1.147 57.168 ;
     RECT  0.535 57.924 1.147 60.102 ;
     RECT  0.175 87.084 1.147 87.102 ;
     RECT  0.535 90.324 1.175 91.35 ;
     RECT  0.139 62.172 1.183 64.386 ;
     RECT  1.147 65.952 1.291 65.97 ;
     RECT  0.535 92.214 1.291 92.772 ;
     RECT  0.535 83.772 1.723 84.708 ;
     RECT  1.147 86.472 1.723 87.102 ;
     RECT  1.147 47.052 2.16 49.5 ;
     RECT  0.535 51.948 2.16 54.432 ;
     RECT  0.103 55.224 2.16 55.242 ;
     RECT  1.147 56.07 2.16 56.088 ;
     RECT  1.147 56.88 2.16 60.57 ;
     RECT  1.183 61.632 2.16 64.386 ;
     RECT  1.291 65.952 2.16 66.042 ;
     RECT  1.147 80.946 2.16 80.964 ;
     RECT  0.103 82.53 2.16 82.548 ;
     RECT  1.723 83.772 2.16 87.102 ;
     RECT  0.211 88.2 2.16 89.298 ;
     RECT  1.175 90.324 2.16 91.224 ;
     RECT  1.291 92.214 2.16 93.312 ;
     RECT  0.347 94.41 2.16 95.508 ;
     RECT  0.823 96.804 2.16 97.02 ;
     RECT  1.147 98.352 2.16 98.37 ;
     RECT  2.16 2.151 14.395 174.969 ;
     RECT  14.395 2.034 15.719 174.969 ;
     RECT  15.719 2.151 18.283 174.969 ;
     RECT  18.283 2.034 20.515 174.969 ;
     RECT  20.515 1.998 20.844 174.969 ;
     RECT  20.844 57.114 20.867 59.184 ;
     RECT  20.867 57.114 21.011 58.284 ;
     RECT  20.844 60.012 21.011 91.584 ;
     RECT  21.011 57.114 21.047 58.104 ;
     RECT  21.011 60.012 21.083 70.974 ;
     RECT  21.083 60.012 21.119 70.668 ;
     RECT  21.011 72.036 21.119 91.584 ;
     RECT  21.119 60.012 21.155 63.684 ;
     RECT  21.119 72.576 21.155 72.864 ;
     RECT  21.047 57.186 21.263 58.104 ;
     RECT  20.867 59.076 21.299 59.184 ;
     RECT  20.844 55.836 21.335 55.944 ;
     RECT  21.263 57.456 21.335 58.104 ;
     RECT  21.155 60.012 21.371 60.984 ;
     RECT  21.335 57.546 21.443 58.104 ;
     RECT  21.119 64.566 21.587 65.844 ;
     RECT  21.119 73.746 21.659 91.584 ;
     RECT  21.119 66.636 21.767 68.274 ;
     RECT  21.119 69.192 21.947 70.668 ;
     RECT  21.155 61.866 21.983 63.684 ;
     RECT  21.335 55.836 22.019 55.854 ;
     RECT  20.844 1.998 22.055 55.044 ;
     RECT  21.299 59.076 22.055 59.094 ;
     RECT  21.443 57.546 22.091 58.014 ;
     RECT  22.055 2.106 22.271 55.044 ;
     RECT  21.767 66.636 22.279 67.59 ;
     RECT  22.091 57.996 22.459 58.014 ;
     RECT  22.271 2.151 22.896 55.044 ;
     RECT  22.459 57.996 22.896 58.716 ;
     RECT  21.371 60.012 22.896 60.408 ;
     RECT  21.983 62.406 22.896 63.684 ;
     RECT  21.587 64.566 22.896 65.808 ;
     RECT  22.279 66.564 22.896 67.59 ;
     RECT  21.947 69.192 22.896 70.128 ;
     RECT  21.155 72.846 22.896 72.864 ;
     RECT  21.659 73.746 22.896 91.044 ;
     RECT  20.844 92.376 22.896 94.896 ;
     RECT  20.844 125.118 22.896 125.136 ;
     RECT  20.844 126.234 67.343 174.969 ;
     RECT  22.896 2.151 69.719 125.136 ;
     RECT  67.343 126.54 70.807 174.969 ;
     RECT  69.719 2.151 197.64 124.488 ;
     RECT  197.64 2.151 198.427 53.892 ;
     RECT  197.64 54.846 198.427 54.864 ;
     RECT  198.427 54.801 198.499 54.864 ;
     RECT  198.427 2.151 198.535 53.928 ;
     RECT  198.499 54.72 198.535 54.864 ;
     RECT  198.499 58.5 198.607 58.518 ;
     RECT  197.64 56.421 198.643 57.636 ;
     RECT  198.607 58.428 198.643 58.518 ;
     RECT  198.535 2.151 198.671 54.864 ;
     RECT  198.643 56.421 198.671 58.518 ;
     RECT  198.671 2.151 198.851 54.738 ;
     RECT  197.64 66.096 198.931 67.194 ;
     RECT  197.64 67.986 198.931 95.094 ;
     RECT  197.64 111.276 199.219 111.294 ;
     RECT  199.219 110.574 199.399 111.294 ;
     RECT  198.671 57.996 199.507 58.518 ;
     RECT  199.507 57.996 199.543 58.644 ;
     RECT  198.851 2.151 199.692 54.666 ;
     RECT  199.003 55.656 199.692 55.674 ;
     RECT  198.671 56.421 199.692 56.934 ;
     RECT  199.543 57.996 199.692 58.716 ;
     RECT  198.931 66.096 199.692 95.094 ;
     RECT  199.363 101.466 199.692 101.484 ;
     RECT  198.607 103.716 199.692 103.734 ;
     RECT  199.327 105.786 199.692 105.804 ;
     RECT  198.643 108.486 199.692 108.504 ;
     RECT  199.399 110.574 199.692 112.014 ;
     RECT  199.183 113.436 199.692 113.454 ;
     RECT  198.679 115.596 199.692 115.614 ;
     RECT  199.651 118.476 199.692 118.494 ;
     RECT  70.807 126.234 199.692 174.969 ;
     RECT  199.692 2.151 218.16 174.969 ;
     RECT  218.16 77.256 218.255 79.164 ;
     RECT  218.16 55.728 218.867 74.646 ;
     RECT  218.16 52.146 218.903 54.702 ;
     RECT  218.867 55.728 218.903 66.546 ;
     RECT  218.867 67.41 218.975 74.529 ;
     RECT  218.975 67.41 219.011 73.53 ;
     RECT  218.975 74.322 219.047 74.529 ;
     RECT  219.011 67.41 219.155 73.026 ;
     RECT  219.155 67.41 219.227 72.954 ;
     RECT  219.227 67.41 219.371 72.054 ;
     RECT  219.371 69.57 219.407 72.054 ;
     RECT  218.903 54.684 219.443 54.702 ;
     RECT  219.371 67.41 219.443 68.814 ;
     RECT  218.255 77.256 219.443 78.894 ;
     RECT  218.903 52.146 219.479 53.244 ;
     RECT  218.903 57.078 219.479 66.546 ;
     RECT  219.227 72.936 219.479 72.954 ;
     RECT  219.479 52.146 219.515 52.344 ;
     RECT  219.479 58.086 219.515 58.284 ;
     RECT  219.047 74.358 219.515 74.529 ;
     RECT  219.515 52.146 219.551 52.164 ;
     RECT  219.515 74.358 219.551 74.376 ;
     RECT  219.479 53.226 219.587 53.244 ;
     RECT  219.479 59.31 220.063 66.546 ;
     RECT  219.407 69.57 220.091 70.668 ;
     RECT  220.091 69.606 220.127 70.668 ;
     RECT  219.443 78.516 220.127 78.894 ;
     RECT  220.063 59.31 220.163 66.654 ;
     RECT  219.443 67.41 220.163 67.428 ;
     RECT  219.443 68.22 220.163 68.814 ;
     RECT  220.127 69.768 220.163 70.668 ;
     RECT  219.407 71.496 220.163 72.054 ;
     RECT  219.443 77.256 220.163 77.724 ;
     RECT  219.479 57.078 220.199 57.096 ;
     RECT  219.515 58.266 220.199 58.284 ;
     RECT  220.163 59.31 220.199 59.994 ;
     RECT  220.163 60.966 220.199 61.614 ;
     RECT  220.163 62.406 220.199 63.684 ;
     RECT  220.163 64.476 220.199 66.546 ;
     RECT  220.163 68.22 220.199 68.436 ;
     RECT  220.163 69.768 220.199 70.056 ;
     RECT  220.127 78.876 220.199 78.894 ;
     RECT  220.199 59.31 220.235 59.328 ;
     RECT  220.199 61.596 220.235 61.614 ;
     RECT  220.199 62.946 220.235 63.684 ;
     RECT  220.199 64.944 220.235 64.962 ;
     RECT  220.199 66.33 220.235 66.348 ;
     RECT  220.199 70.038 220.235 70.056 ;
     RECT  220.135 74.322 220.235 74.34 ;
     RECT  218.16 75.636 220.235 75.654 ;
     RECT  220.163 77.706 220.235 77.724 ;
     RECT  220.163 72.036 220.307 72.054 ;
    LAYER M3 ;
     RECT  15.948 0.091 15.966 0.139 ;
     RECT  10.08 0.091 10.098 0.523 ;
     RECT  15.768 0.139 15.966 0.523 ;
     RECT  16.704 0.475 16.722 0.523 ;
     RECT  17.676 0.091 17.91 0.523 ;
     RECT  9.936 0.523 10.098 0.571 ;
     RECT  14.868 0.235 14.886 0.619 ;
     RECT  15.768 0.523 17.91 0.619 ;
     RECT  9.936 0.571 10.206 1.147 ;
     RECT  14.868 0.619 17.91 1.147 ;
     RECT  14.868 1.147 18.162 1.195 ;
     RECT  14.868 1.195 18.414 1.723 ;
     RECT  20.52 1.771 20.538 1.819 ;
     RECT  20.16 1.819 20.538 1.963 ;
     RECT  14.868 1.723 19.134 2.029 ;
     RECT  20.16 1.963 20.79 2.029 ;
     RECT  20.088 2.029 20.79 2.065 ;
     RECT  22.032 1.993 22.05 2.101 ;
     RECT  22.032 2.101 22.266 2.191 ;
     RECT  21.888 2.191 22.266 2.219 ;
     RECT  20.088 2.065 21.078 2.227 ;
     RECT  21.888 2.219 22.194 2.227 ;
     RECT  20.088 2.227 22.194 2.251 ;
     RECT  14.4 2.029 19.134 2.255 ;
     RECT  9.936 1.147 10.494 2.263 ;
     RECT  14.832 2.255 19.134 2.263 ;
     RECT  19.872 2.251 22.194 2.263 ;
     RECT  9.936 2.263 10.89 2.371 ;
     RECT  2.415 2.143 2.505 2.413 ;
     RECT  7.815 2.143 7.905 2.413 ;
     RECT  13.215 2.143 13.305 2.413 ;
     RECT  24.015 2.143 24.105 2.413 ;
     RECT  29.415 2.143 29.505 2.413 ;
     RECT  34.815 2.143 34.905 2.413 ;
     RECT  40.215 2.143 40.305 2.413 ;
     RECT  45.615 2.143 45.705 2.413 ;
     RECT  51.015 2.143 51.105 2.413 ;
     RECT  56.415 2.143 56.505 2.413 ;
     RECT  61.815 2.143 61.905 2.413 ;
     RECT  67.215 2.143 67.305 2.413 ;
     RECT  72.615 2.143 72.705 2.413 ;
     RECT  78.015 2.143 78.105 2.413 ;
     RECT  83.415 2.143 83.505 2.413 ;
     RECT  88.815 2.143 88.905 2.413 ;
     RECT  94.215 2.143 94.305 2.413 ;
     RECT  99.615 2.143 99.705 2.413 ;
     RECT  105.015 2.143 105.105 2.413 ;
     RECT  110.415 2.143 110.505 2.413 ;
     RECT  115.815 2.143 115.905 2.413 ;
     RECT  121.215 2.143 121.305 2.413 ;
     RECT  126.615 2.143 126.705 2.413 ;
     RECT  132.015 2.143 132.105 2.413 ;
     RECT  137.415 2.143 137.505 2.413 ;
     RECT  142.815 2.143 142.905 2.413 ;
     RECT  148.215 2.143 148.305 2.413 ;
     RECT  153.615 2.143 153.705 2.413 ;
     RECT  159.015 2.143 159.105 2.413 ;
     RECT  164.415 2.143 164.505 2.413 ;
     RECT  169.815 2.143 169.905 2.413 ;
     RECT  175.215 2.143 175.305 2.413 ;
     RECT  180.615 2.143 180.705 2.413 ;
     RECT  186.015 2.143 186.105 2.413 ;
     RECT  191.415 2.143 191.505 2.413 ;
     RECT  196.815 2.143 196.905 2.413 ;
     RECT  202.215 2.143 202.305 2.413 ;
     RECT  207.615 2.143 207.705 2.413 ;
     RECT  213.015 2.143 213.105 2.413 ;
     RECT  9.576 2.371 11.214 2.489 ;
     RECT  14.832 2.263 22.194 2.831 ;
     RECT  15.3 2.831 22.194 3.145 ;
     RECT  9.72 2.489 11.214 3.181 ;
     RECT  9.72 3.181 11.25 3.379 ;
     RECT  13.215 2.413 13.497 3.577 ;
     RECT  15.3 3.145 22.374 3.577 ;
     RECT  13.215 3.577 14.094 3.613 ;
     RECT  15.012 3.577 22.374 3.613 ;
     RECT  13.215 3.613 22.374 3.749 ;
     RECT  9.72 3.379 11.322 3.811 ;
     RECT  14.22 3.749 22.374 3.847 ;
     RECT  9 3.811 11.322 3.931 ;
     RECT  14.22 3.847 22.518 3.979 ;
     RECT  8.82 3.931 11.322 3.983 ;
     RECT  8.892 3.983 11.322 4.225 ;
     RECT  8.892 4.225 11.502 4.261 ;
     RECT  14.22 3.979 22.77 4.261 ;
     RECT  8.892 4.261 11.898 4.495 ;
     RECT  13.215 3.749 13.497 4.495 ;
     RECT  8.892 4.495 13.497 4.531 ;
     RECT  14.22 4.261 23.202 4.531 ;
     RECT  8.892 4.531 23.202 4.541 ;
     RECT  9 4.541 23.202 4.555 ;
     RECT  9 4.555 23.274 4.801 ;
     RECT  24.015 2.413 24.297 4.801 ;
     RECT  7.815 2.413 8.097 5.305 ;
     RECT  9 4.801 24.297 5.305 ;
     RECT  7.815 5.305 24.297 7.889 ;
     RECT  8.892 7.889 24.297 7.961 ;
     RECT  8.892 7.961 9.45 8.033 ;
     RECT  9.036 8.033 9.45 8.815 ;
     RECT  10.404 7.961 24.297 8.815 ;
     RECT  8.892 8.815 24.297 8.843 ;
     RECT  23.868 8.843 24.297 9.041 ;
     RECT  8.892 8.843 22.77 9.101 ;
     RECT  9.54 9.101 22.77 9.625 ;
     RECT  9.54 9.625 23.058 9.677 ;
     RECT  10.044 9.677 23.058 9.779 ;
     RECT  10.044 9.779 10.062 9.965 ;
     RECT  10.944 9.779 22.986 10.049 ;
     RECT  10.98 10.049 22.662 10.121 ;
     RECT  11.196 10.121 22.662 10.193 ;
     RECT  11.196 10.193 22.014 10.355 ;
     RECT  11.196 10.355 21.87 10.427 ;
     RECT  10.404 10.843 10.422 11.011 ;
     RECT  11.196 10.427 21.438 11.011 ;
     RECT  10.404 11.011 21.438 11.129 ;
     RECT  10.404 11.129 10.422 11.165 ;
     RECT  11.196 11.129 20.79 11.171 ;
     RECT  11.196 11.171 17.154 11.201 ;
     RECT  18.072 11.171 20.79 11.201 ;
     RECT  18.072 11.201 19.566 11.224 ;
     RECT  20.52 11.201 20.79 11.273 ;
     RECT  20.52 11.273 20.538 11.309 ;
     RECT  11.196 11.201 17.046 11.399 ;
     RECT  11.196 11.399 11.934 11.435 ;
     RECT  18.324 11.224 19.566 11.435 ;
     RECT  11.34 11.435 11.934 11.552 ;
     RECT  18.324 11.435 19.314 11.669 ;
     RECT  18.324 11.669 18.897 11.705 ;
     RECT  11.34 11.552 11.358 11.741 ;
     RECT  12.816 11.399 17.046 11.741 ;
     RECT  13.176 11.741 13.518 11.777 ;
     RECT  14.58 11.741 17.046 11.777 ;
     RECT  15.588 11.777 17.046 23.279 ;
     RECT  15.588 23.279 16.47 23.549 ;
     RECT  121.215 2.413 121.497 33.277 ;
     RECT  14.58 11.777 14.598 34.349 ;
     RECT  13.176 11.777 13.497 34.501 ;
     RECT  5.616 34.591 5.634 34.735 ;
     RECT  5.364 34.735 5.634 35.429 ;
     RECT  199.188 33.241 199.206 35.941 ;
     RECT  59.832 35.581 59.85 36.005 ;
     RECT  199.188 35.941 199.386 36.509 ;
     RECT  67.215 2.413 67.497 37.675 ;
     RECT  78.015 2.413 78.297 37.723 ;
     RECT  88.815 2.413 89.097 37.723 ;
     RECT  99.615 2.413 99.897 37.723 ;
     RECT  110.415 2.413 110.697 37.723 ;
     RECT  132.015 2.413 132.297 37.723 ;
     RECT  142.815 2.413 143.097 37.723 ;
     RECT  153.615 2.413 153.897 37.723 ;
     RECT  164.415 2.413 164.697 37.723 ;
     RECT  175.215 2.413 175.497 37.723 ;
     RECT  186.015 2.413 186.297 37.723 ;
     RECT  196.815 2.413 197.097 37.723 ;
     RECT  77.904 37.723 78.297 37.769 ;
     RECT  88.704 37.723 89.097 37.769 ;
     RECT  99.504 37.723 99.897 37.769 ;
     RECT  110.304 37.723 110.697 37.769 ;
     RECT  131.904 37.723 132.297 37.769 ;
     RECT  142.704 37.723 143.097 37.769 ;
     RECT  153.504 37.723 153.897 37.769 ;
     RECT  164.304 37.723 164.697 37.769 ;
     RECT  175.104 37.723 175.497 37.769 ;
     RECT  185.904 37.723 186.297 37.769 ;
     RECT  196.704 37.723 197.097 37.769 ;
     RECT  120.924 33.277 121.497 37.867 ;
     RECT  120.672 37.867 121.497 37.904 ;
     RECT  101.376 37.903 101.394 37.949 ;
     RECT  102.492 37.831 102.51 37.949 ;
     RECT  103.968 37.963 103.986 38.003 ;
     RECT  102.852 37.963 102.87 38.039 ;
     RECT  78.015 37.769 78.297 38.101 ;
     RECT  76.536 38.101 76.554 38.141 ;
     RECT  78.015 38.101 78.39 38.141 ;
     RECT  115.815 2.413 116.097 38.491 ;
     RECT  15.66 23.549 16.47 38.641 ;
     RECT  106.452 38.641 106.47 38.677 ;
     RECT  205.56 38.641 205.578 38.677 ;
     RECT  202.215 2.413 202.497 38.713 ;
     RECT  114.696 38.539 114.714 38.717 ;
     RECT  115.815 38.491 116.514 38.717 ;
     RECT  31.392 38.713 31.41 38.765 ;
     RECT  32.508 38.641 32.526 38.765 ;
     RECT  101.952 38.713 101.97 38.779 ;
     RECT  78.015 38.141 78.297 38.911 ;
     RECT  88.815 37.769 89.097 38.911 ;
     RECT  101.7 38.779 101.97 38.911 ;
     RECT  110.415 37.769 110.697 38.911 ;
     RECT  121.215 37.904 121.497 38.911 ;
     RECT  132.015 37.769 132.297 38.911 ;
     RECT  142.815 37.769 143.097 38.911 ;
     RECT  153.615 37.769 153.897 38.911 ;
     RECT  164.415 37.769 164.697 38.911 ;
     RECT  175.215 37.769 175.497 38.911 ;
     RECT  186.015 37.769 186.297 38.911 ;
     RECT  196.815 37.769 197.097 38.911 ;
     RECT  101.7 38.911 102.582 38.939 ;
     RECT  77.904 38.911 78.297 38.957 ;
     RECT  88.704 38.911 89.097 38.957 ;
     RECT  98.604 38.779 98.622 38.957 ;
     RECT  101.952 38.939 102.582 38.957 ;
     RECT  110.304 38.911 110.697 38.957 ;
     RECT  131.904 38.911 132.297 38.957 ;
     RECT  142.704 38.911 143.097 38.957 ;
     RECT  153.504 38.911 153.897 38.957 ;
     RECT  164.304 38.911 164.697 38.957 ;
     RECT  175.104 38.911 175.497 38.957 ;
     RECT  185.904 38.911 186.297 38.957 ;
     RECT  196.704 38.911 197.097 38.957 ;
     RECT  115.815 38.717 116.406 39.019 ;
     RECT  121.104 38.911 121.497 39.067 ;
     RECT  15.66 38.641 17.082 39.091 ;
     RECT  25.848 39.181 25.866 39.245 ;
     RECT  73.8 39.181 73.818 39.245 ;
     RECT  74.916 39.208 74.934 39.245 ;
     RECT  27.036 39.181 27.054 39.253 ;
     RECT  67.215 37.675 67.626 39.253 ;
     RECT  105.015 2.413 105.297 39.289 ;
     RECT  205.56 38.677 205.686 39.289 ;
     RECT  26.964 39.253 27.054 39.293 ;
     RECT  66.744 39.253 67.662 39.293 ;
     RECT  15.66 39.091 17.154 39.341 ;
     RECT  27.036 39.293 27.054 39.341 ;
     RECT  28.152 39.289 28.17 39.341 ;
     RECT  34.815 2.413 35.097 39.547 ;
     RECT  34.815 39.547 35.406 39.595 ;
     RECT  40.215 2.413 40.497 39.595 ;
     RECT  34.2 39.595 35.406 39.749 ;
     RECT  39.6 39.595 40.497 39.749 ;
     RECT  38.484 39.721 38.502 39.773 ;
     RECT  76.068 39.721 76.086 39.773 ;
     RECT  77.184 39.739 77.202 39.785 ;
     RECT  31.608 39.784 31.626 39.821 ;
     RECT  32.472 39.721 32.49 39.821 ;
     RECT  24.015 9.041 24.297 39.829 ;
     RECT  34.815 39.749 35.406 39.835 ;
     RECT  36.468 39.721 36.486 39.869 ;
     RECT  34.815 39.835 35.622 39.893 ;
     RECT  101.952 38.957 101.97 40.123 ;
     RECT  99.615 37.769 99.897 40.261 ;
     RECT  94.215 2.413 94.497 40.297 ;
     RECT  98.892 40.261 100.026 40.301 ;
     RECT  104.868 39.289 105.297 40.315 ;
     RECT  106.128 38.677 106.47 40.315 ;
     RECT  5.364 35.429 5.382 40.333 ;
     RECT  6.336 40.297 6.354 40.333 ;
     RECT  110.415 38.957 110.697 40.333 ;
     RECT  91.548 39.865 91.566 40.369 ;
     RECT  104.868 40.315 106.47 40.369 ;
     RECT  202.215 38.713 203.166 40.369 ;
     RECT  94.215 40.297 94.662 40.397 ;
     RECT  99.504 40.301 100.026 40.405 ;
     RECT  86.004 40.333 86.022 40.411 ;
     RECT  13.176 34.501 14.202 40.441 ;
     RECT  202.215 40.369 203.778 40.441 ;
     RECT  7.815 7.889 8.097 40.675 ;
     RECT  18.615 11.705 18.897 40.699 ;
     RECT  104.868 40.369 106.794 40.699 ;
     RECT  5.364 40.333 6.354 40.711 ;
     RECT  201.816 40.441 203.778 40.711 ;
     RECT  120.708 39.067 121.497 40.801 ;
     RECT  122.364 40.711 122.382 40.801 ;
     RECT  207.615 2.413 207.897 40.801 ;
     RECT  115.632 39.019 116.406 40.837 ;
     RECT  18.615 40.699 18.99 40.877 ;
     RECT  75.456 40.837 75.474 40.877 ;
     RECT  76.572 40.801 76.59 40.877 ;
     RECT  40.215 39.749 40.497 40.909 ;
     RECT  137.415 2.413 137.697 40.909 ;
     RECT  9.036 40.405 9.054 40.945 ;
     RECT  210.852 40.837 210.87 40.945 ;
     RECT  15.66 39.341 16.47 40.981 ;
     RECT  61.815 2.413 62.097 40.981 ;
     RECT  175.215 38.957 175.497 40.981 ;
     RECT  5.364 40.711 6.606 41.179 ;
     RECT  101.376 40.123 101.97 41.179 ;
     RECT  130.932 39.829 130.95 41.179 ;
     RECT  132.015 38.957 132.297 41.179 ;
     RECT  99.504 40.405 100.602 41.215 ;
     RECT  110.415 40.333 111.042 41.251 ;
     RECT  120.708 40.801 122.382 41.251 ;
     RECT  206.424 40.405 206.442 41.251 ;
     RECT  207.396 40.801 207.897 41.251 ;
     RECT  25.236 41.251 25.254 41.341 ;
     RECT  115.092 40.837 116.406 41.341 ;
     RECT  130.572 41.179 130.95 41.341 ;
     RECT  132.015 41.179 132.894 41.341 ;
     RECT  137.415 40.909 138.222 41.341 ;
     RECT  142.815 38.957 143.097 41.341 ;
     RECT  153.615 38.957 153.897 41.341 ;
     RECT  164.415 38.957 164.697 41.341 ;
     RECT  175.176 40.981 175.497 41.341 ;
     RECT  88.815 38.957 89.097 41.377 ;
     RECT  191.415 2.413 191.697 41.377 ;
     RECT  130.572 41.341 132.894 41.405 ;
     RECT  24.015 39.829 24.354 41.413 ;
     RECT  25.236 41.341 25.578 41.413 ;
     RECT  205.344 39.289 205.686 41.413 ;
     RECT  85.932 40.411 86.022 41.419 ;
     RECT  98.028 40.711 98.046 41.419 ;
     RECT  99.036 41.215 100.602 41.419 ;
     RECT  130.572 41.405 130.95 41.419 ;
     RECT  78.015 38.957 78.297 41.449 ;
     RECT  94.215 40.397 94.497 41.467 ;
     RECT  204.912 41.413 205.686 41.467 ;
     RECT  206.424 41.251 207.897 41.467 ;
     RECT  131.724 41.405 132.894 41.477 ;
     RECT  210.564 40.945 210.87 41.485 ;
     RECT  142.815 41.341 143.154 41.512 ;
     RECT  153.615 41.341 153.954 41.512 ;
     RECT  164.415 41.341 164.754 41.512 ;
     RECT  186.015 38.957 186.297 41.512 ;
     RECT  24.015 41.413 25.578 41.521 ;
     RECT  135.036 39.499 135.054 41.521 ;
     RECT  185.904 41.512 186.297 41.521 ;
     RECT  201.816 40.711 204.174 41.521 ;
     RECT  204.912 41.467 207.897 41.521 ;
     RECT  74.664 41.419 74.682 41.549 ;
     RECT  85.932 41.419 86.67 41.549 ;
     RECT  118.584 41.419 118.602 41.549 ;
     RECT  130.536 41.419 130.95 41.549 ;
     RECT  137.415 41.341 138.546 41.549 ;
     RECT  142.704 41.512 143.154 41.549 ;
     RECT  150.552 41.341 150.57 41.549 ;
     RECT  153.504 41.512 153.954 41.549 ;
     RECT  162.504 41.341 162.522 41.549 ;
     RECT  164.304 41.512 164.754 41.549 ;
     RECT  174.492 41.341 175.554 41.549 ;
     RECT  185.832 41.521 186.297 41.639 ;
     RECT  72.615 2.413 72.897 41.683 ;
     RECT  109.62 40.873 109.638 41.683 ;
     RECT  110.415 41.251 111.438 41.683 ;
     RECT  93.564 41.467 94.497 41.755 ;
     RECT  153.504 41.549 153.897 41.755 ;
     RECT  85.104 41.449 85.122 41.791 ;
     RECT  7.452 40.675 8.097 41.881 ;
     RECT  8.856 40.945 9.054 41.881 ;
     RECT  140.472 41.791 140.49 41.917 ;
     RECT  192.492 41.449 192.51 41.953 ;
     RECT  191.232 41.377 191.697 41.989 ;
     RECT  192.492 41.953 193.194 41.989 ;
     RECT  92.736 40.363 92.754 42.025 ;
     RECT  196.815 38.957 197.097 42.025 ;
     RECT  21.348 41.917 21.366 42.061 ;
     RECT  127.62 40.939 127.638 42.151 ;
     RECT  132.015 41.477 132.894 42.151 ;
     RECT  137.415 41.549 138.222 42.421 ;
     RECT  77.724 41.449 78.297 42.457 ;
     RECT  130.932 41.549 130.95 42.457 ;
     RECT  132.015 42.151 133.038 42.457 ;
     RECT  141.624 41.485 141.642 42.457 ;
     RECT  142.815 41.549 143.097 42.457 ;
     RECT  153.432 41.755 153.897 42.457 ;
     RECT  201.816 41.521 207.897 42.457 ;
     RECT  137.304 42.421 138.222 42.461 ;
     RECT  103.176 40.315 103.194 42.475 ;
     RECT  141.624 42.457 143.097 42.509 ;
     RECT  130.932 42.457 133.038 42.523 ;
     RECT  92.556 42.025 92.754 42.529 ;
     RECT  93.564 41.755 95.022 42.529 ;
     RECT  98.028 41.419 100.602 42.529 ;
     RECT  5.076 41.179 6.606 42.565 ;
     RECT  7.452 41.881 9.054 42.565 ;
     RECT  196.704 42.025 197.097 42.571 ;
     RECT  5.076 42.565 9.054 42.601 ;
     RECT  95.904 41.881 95.922 42.601 ;
     RECT  98.028 42.529 100.638 42.691 ;
     RECT  191.232 41.989 193.194 42.727 ;
     RECT  194.472 42.529 194.49 42.727 ;
     RECT  70.704 37.915 70.722 42.763 ;
     RECT  70.704 42.763 70.794 42.791 ;
     RECT  23.796 41.521 25.578 42.961 ;
     RECT  137.415 42.461 138.222 42.961 ;
     RECT  148.215 2.413 148.497 42.961 ;
     RECT  137.415 42.961 138.51 42.997 ;
     RECT  19.8 42.961 19.818 43.033 ;
     RECT  142.815 42.509 143.097 43.033 ;
     RECT  150.84 41.719 150.858 43.033 ;
     RECT  153.252 42.457 153.897 43.033 ;
     RECT  164.415 41.549 164.697 43.033 ;
     RECT  169.815 2.413 170.097 43.033 ;
     RECT  175.176 41.549 175.497 43.033 ;
     RECT  186.015 41.639 186.297 43.033 ;
     RECT  23.796 42.961 25.614 43.037 ;
     RECT  137.415 42.997 139.194 43.037 ;
     RECT  18.615 40.877 18.897 43.069 ;
     RECT  72.576 41.683 72.897 43.069 ;
     RECT  147.6 42.961 148.497 43.069 ;
     RECT  150.48 43.033 150.858 43.069 ;
     RECT  19.8 43.033 20.502 43.085 ;
     RECT  162.468 43.033 162.486 43.105 ;
     RECT  169.815 43.033 170.442 43.105 ;
     RECT  182.412 43.033 182.43 43.105 ;
     RECT  142.815 43.033 143.154 43.133 ;
     RECT  147.168 43.069 148.497 43.133 ;
     RECT  153.252 43.033 153.954 43.133 ;
     RECT  162.468 43.105 162.558 43.133 ;
     RECT  164.415 43.033 164.754 43.133 ;
     RECT  175.176 43.033 175.554 43.133 ;
     RECT  182.412 43.105 182.502 43.133 ;
     RECT  186.015 43.033 186.354 43.133 ;
     RECT  91.008 40.369 91.566 43.141 ;
     RECT  92.556 42.529 95.022 43.141 ;
     RECT  109.62 41.683 111.438 43.141 ;
     RECT  91.008 43.141 95.022 43.231 ;
     RECT  95.904 42.601 96.03 43.231 ;
     RECT  118.584 43.069 118.602 43.231 ;
     RECT  142.815 43.133 143.097 43.231 ;
     RECT  164.415 43.133 164.697 43.231 ;
     RECT  175.176 43.133 175.497 43.231 ;
     RECT  186.015 43.133 186.297 43.231 ;
     RECT  195.624 41.515 195.642 43.231 ;
     RECT  137.415 43.037 138.618 43.259 ;
     RECT  162.54 43.133 162.558 43.259 ;
     RECT  169.815 43.105 170.514 43.259 ;
     RECT  182.484 43.133 182.502 43.259 ;
     RECT  130.536 42.523 133.038 43.267 ;
     RECT  141.624 42.509 141.642 43.267 ;
     RECT  142.704 43.231 143.097 43.277 ;
     RECT  164.304 43.231 164.697 43.277 ;
     RECT  175.104 43.231 175.497 43.277 ;
     RECT  185.904 43.231 186.297 43.277 ;
     RECT  64.224 38.155 64.242 43.291 ;
     RECT  65.34 41.419 65.358 43.291 ;
     RECT  13.104 40.441 14.202 43.303 ;
     RECT  140.184 41.917 140.49 43.303 ;
     RECT  141.624 43.267 141.786 43.303 ;
     RECT  147.168 43.133 147.438 43.303 ;
     RECT  210.564 41.485 211.05 43.303 ;
     RECT  211.968 43.141 211.986 43.303 ;
     RECT  118.584 43.231 118.674 43.331 ;
     RECT  13.104 43.303 14.238 43.375 ;
     RECT  15.192 40.981 16.47 43.375 ;
     RECT  109.62 43.141 111.978 43.501 ;
     RECT  23.004 43.267 23.022 43.579 ;
     RECT  55.224 42.715 55.242 43.579 ;
     RECT  61.632 40.981 62.097 43.579 ;
     RECT  85.932 41.549 86.022 43.579 ;
     RECT  18.036 43.069 18.897 43.609 ;
     RECT  67.215 39.293 67.626 43.609 ;
     RECT  13.104 43.375 16.47 43.645 ;
     RECT  70.776 42.791 70.794 43.645 ;
     RECT  82.044 43.105 82.062 43.645 ;
     RECT  113.184 43.627 113.202 43.645 ;
     RECT  200.7 39.865 200.718 43.645 ;
     RECT  201.456 42.457 207.897 43.645 ;
     RECT  22.824 43.579 23.022 43.709 ;
     RECT  30.78 43.579 30.798 43.709 ;
     RECT  42.768 43.579 42.786 43.709 ;
     RECT  54.72 43.579 55.242 43.709 ;
     RECT  61.632 43.579 62.73 43.709 ;
     RECT  74.664 43.579 74.682 43.709 ;
     RECT  85.932 43.579 86.67 43.709 ;
     RECT  34.815 39.893 35.097 43.765 ;
     RECT  45.615 2.413 45.897 43.771 ;
     RECT  56.415 2.413 56.697 43.771 ;
     RECT  67.215 43.609 68.31 43.771 ;
     RECT  88.815 41.377 89.514 43.771 ;
     RECT  113.184 43.645 113.886 43.771 ;
     RECT  115.092 41.341 116.73 43.771 ;
     RECT  200.7 43.645 207.897 43.771 ;
     RECT  81.792 43.645 82.062 43.807 ;
     RECT  113.184 43.771 116.73 43.835 ;
     RECT  21.348 42.061 21.438 43.843 ;
     RECT  123.948 41.899 123.966 43.843 ;
     RECT  130.428 43.267 133.038 43.843 ;
     RECT  134.316 41.521 135.054 43.843 ;
     RECT  200.7 43.771 208.206 43.843 ;
     RECT  209.052 41.917 209.07 43.843 ;
     RECT  113.184 43.835 113.49 43.853 ;
     RECT  114.372 43.835 116.73 43.853 ;
     RECT  91.008 43.231 96.03 43.867 ;
     RECT  142.815 43.277 143.097 44.059 ;
     RECT  80.676 40.675 80.694 44.107 ;
     RECT  81.54 43.807 82.062 44.107 ;
     RECT  23.004 43.709 23.022 44.149 ;
     RECT  23.796 43.037 25.578 44.149 ;
     RECT  21.24 43.843 21.438 44.155 ;
     RECT  80.676 44.107 82.062 44.155 ;
     RECT  70.776 43.645 71.154 44.185 ;
     RECT  120.708 41.251 122.454 44.185 ;
     RECT  186.015 43.277 186.297 44.185 ;
     RECT  34.704 43.765 35.097 44.237 ;
     RECT  45.504 43.771 45.897 44.237 ;
     RECT  56.304 43.771 56.697 44.237 ;
     RECT  67.104 43.771 68.31 44.237 ;
     RECT  88.704 43.771 89.514 44.237 ;
     RECT  185.904 44.185 186.297 44.237 ;
     RECT  4.752 42.601 9.054 44.311 ;
     RECT  10.116 44.221 10.674 44.311 ;
     RECT  13.104 43.645 16.974 44.311 ;
     RECT  17.748 43.609 18.897 44.311 ;
     RECT  120.708 44.185 122.49 44.311 ;
     RECT  4.752 44.311 10.674 44.339 ;
     RECT  120.528 44.311 122.49 44.339 ;
     RECT  20.412 43.085 20.43 44.383 ;
     RECT  91.008 43.867 96.21 44.383 ;
     RECT  44.352 44.347 44.37 44.384 ;
     RECT  61.632 43.709 62.097 44.419 ;
     RECT  20.268 44.383 20.43 44.429 ;
     RECT  140.184 43.303 141.786 44.443 ;
     RECT  142.632 44.059 143.097 44.443 ;
     RECT  13.104 44.311 19.17 44.477 ;
     RECT  21.24 44.155 21.69 44.491 ;
     RECT  23.004 44.149 25.578 44.491 ;
     RECT  150.372 43.069 150.858 44.617 ;
     RECT  198 44.419 198.018 44.617 ;
     RECT  21.24 44.491 25.578 44.669 ;
     RECT  129.24 44.653 129.258 44.689 ;
     RECT  196.38 42.571 197.097 44.725 ;
     RECT  198 44.617 198.126 44.725 ;
     RECT  123.372 43.843 123.966 44.731 ;
     RECT  70.776 44.185 71.694 44.753 ;
     RECT  45.615 44.237 45.897 44.851 ;
     RECT  43.236 44.311 43.254 44.875 ;
     RECT  45.615 44.851 46.278 44.887 ;
     RECT  119.016 44.761 119.034 44.887 ;
     RECT  21.24 44.669 22.23 44.915 ;
     RECT  42.768 44.875 43.254 44.923 ;
     RECT  104.832 40.699 106.794 44.923 ;
     RECT  108 41.995 108.018 44.923 ;
     RECT  44.676 44.887 44.694 44.957 ;
     RECT  123.372 44.731 124.29 44.959 ;
     RECT  125.028 40.123 125.046 44.959 ;
     RECT  42.768 44.923 43.866 44.96 ;
     RECT  101.376 41.179 102.222 44.971 ;
     RECT  42.768 44.96 42.822 44.987 ;
     RECT  45.615 44.887 46.818 44.987 ;
     RECT  11.664 41.953 11.682 44.995 ;
     RECT  69.444 43.291 69.462 44.995 ;
     RECT  191.232 42.727 194.49 44.995 ;
     RECT  22.212 44.915 22.23 45.005 ;
     RECT  42.768 44.987 42.786 45.005 ;
     RECT  38.772 44.923 38.79 45.023 ;
     RECT  43.848 44.96 43.866 45.023 ;
     RECT  83.415 2.413 83.697 45.031 ;
     RECT  4.752 44.339 10.314 45.121 ;
     RECT  186.015 44.237 186.297 45.157 ;
     RECT  120.528 44.339 122.454 45.163 ;
     RECT  123.372 44.959 125.046 45.163 ;
     RECT  4.752 45.121 10.53 45.193 ;
     RECT  11.412 44.995 11.754 45.193 ;
     RECT  183.24 43.807 183.258 45.193 ;
     RECT  88.815 44.237 89.514 45.211 ;
     RECT  4.752 45.193 10.602 45.229 ;
     RECT  11.412 45.193 11.97 45.229 ;
     RECT  137.415 43.259 138.366 45.229 ;
     RECT  4.752 45.229 11.97 45.301 ;
     RECT  85.932 43.709 86.022 45.301 ;
     RECT  45.615 44.987 46.278 45.341 ;
     RECT  4.752 45.301 12.294 45.391 ;
     RECT  13.104 44.477 16.974 45.391 ;
     RECT  45.615 45.341 45.897 45.391 ;
     RECT  56.415 44.237 56.697 45.391 ;
     RECT  67.215 44.237 68.31 45.391 ;
     RECT  209.808 45.229 209.826 45.391 ;
     RECT  210.564 43.303 211.986 45.391 ;
     RECT  33.084 45.391 33.102 45.437 ;
     RECT  23.004 44.669 25.578 45.499 ;
     RECT  17.748 44.477 18.897 45.535 ;
     RECT  69.444 44.995 69.894 45.571 ;
     RECT  70.776 44.753 71.154 45.571 ;
     RECT  195.552 43.231 195.642 45.571 ;
     RECT  196.38 44.725 198.126 45.571 ;
     RECT  130.428 43.843 135.054 45.595 ;
     RECT  97.848 42.691 100.638 45.661 ;
     RECT  109.116 43.501 111.978 45.661 ;
     RECT  88.092 45.211 89.514 45.697 ;
     RECT  90.324 44.383 96.21 45.697 ;
     RECT  127.62 42.151 128.142 45.697 ;
     RECT  127.62 45.697 128.394 45.733 ;
     RECT  129.24 44.689 129.69 45.733 ;
     RECT  61.488 44.419 62.097 45.739 ;
     RECT  74.196 45.193 74.214 45.739 ;
     RECT  126.615 2.413 126.897 45.787 ;
     RECT  127.62 45.733 129.69 45.787 ;
     RECT  34.815 44.237 35.097 45.832 ;
     RECT  109.116 45.661 112.05 45.833 ;
     RECT  104.832 44.923 107.082 45.835 ;
     RECT  26.64 44.923 26.658 45.841 ;
     RECT  130.428 45.595 135.558 45.841 ;
     RECT  200.7 43.843 209.07 45.841 ;
     RECT  209.808 45.391 211.986 45.841 ;
     RECT  109.116 45.833 111.942 45.869 ;
     RECT  72.54 43.069 72.897 45.883 ;
     RECT  83.415 45.031 84.006 45.883 ;
     RECT  40.215 40.909 40.698 45.931 ;
     RECT  41.472 45.841 41.49 45.931 ;
     RECT  83.232 45.883 84.006 45.931 ;
     RECT  84.96 41.791 85.122 45.931 ;
     RECT  88.092 45.697 96.21 45.931 ;
     RECT  164.415 43.277 164.697 45.931 ;
     RECT  175.176 43.277 175.497 45.931 ;
     RECT  185.904 45.157 186.297 45.931 ;
     RECT  195.552 45.571 198.126 45.931 ;
     RECT  4.752 45.391 16.974 45.959 ;
     RECT  150.372 44.617 150.966 45.959 ;
     RECT  17.748 45.535 19.53 45.967 ;
     RECT  26.64 45.841 26.802 45.967 ;
     RECT  29.415 2.413 29.697 45.967 ;
     RECT  38.772 45.841 38.79 45.967 ;
     RECT  39.924 45.931 41.49 45.968 ;
     RECT  185.868 45.931 186.297 45.968 ;
     RECT  4.752 45.959 16.002 45.995 ;
     RECT  103.176 42.475 103.302 46.003 ;
     RECT  104.364 45.835 107.082 46.003 ;
     RECT  146.196 45.805 146.214 46.027 ;
     RECT  4.752 45.995 11.97 46.031 ;
     RECT  130.428 45.841 135.954 46.031 ;
     RECT  69.444 45.571 71.154 46.039 ;
     RECT  195.552 45.931 198.378 46.061 ;
     RECT  12.744 45.995 16.002 46.103 ;
     RECT  40.104 45.968 41.49 46.103 ;
     RECT  29.124 45.967 29.697 46.109 ;
     RECT  69.228 46.039 71.154 46.111 ;
     RECT  72.504 45.883 72.897 46.111 ;
     RECT  34.704 45.832 35.097 46.237 ;
     RECT  45.504 45.391 45.897 46.237 ;
     RECT  55.224 43.709 55.242 46.237 ;
     RECT  56.304 45.391 56.697 46.237 ;
     RECT  72.252 46.111 72.897 46.237 ;
     RECT  83.232 45.931 85.122 46.237 ;
     RECT  145.548 46.027 146.214 46.267 ;
     RECT  182.664 45.193 183.258 46.267 ;
     RECT  125.82 46.201 125.838 46.301 ;
     RECT  21.24 44.915 21.438 46.309 ;
     RECT  22.356 45.499 25.578 46.309 ;
     RECT  30.78 46.237 30.798 46.309 ;
     RECT  42.768 46.237 42.786 46.309 ;
     RECT  61.488 45.739 62.73 46.309 ;
     RECT  74.196 45.739 74.682 46.309 ;
     RECT  80.1 44.155 82.062 46.309 ;
     RECT  82.8 46.237 85.122 46.309 ;
     RECT  120.528 45.163 125.046 46.309 ;
     RECT  169.815 43.259 170.097 46.309 ;
     RECT  54.72 46.237 55.242 46.337 ;
     RECT  67.104 45.391 68.31 46.345 ;
     RECT  69.228 46.111 71.478 46.345 ;
     RECT  180.615 2.413 180.897 46.345 ;
     RECT  148.215 43.133 148.497 46.381 ;
     RECT  80.1 46.309 85.122 46.397 ;
     RECT  182.412 46.267 183.258 46.397 ;
     RECT  54.792 46.337 55.242 46.409 ;
     RECT  162.468 46.309 162.486 46.409 ;
     RECT  164.304 45.931 164.697 46.409 ;
     RECT  169.815 46.309 170.442 46.409 ;
     RECT  175.104 45.931 175.497 46.409 ;
     RECT  51.015 2.413 51.297 46.459 ;
     RECT  85.932 45.301 86.166 46.459 ;
     RECT  20.412 44.429 20.43 46.471 ;
     RECT  21.24 46.309 25.578 46.471 ;
     RECT  29.304 46.109 29.697 46.507 ;
     RECT  34.704 46.237 35.154 46.507 ;
     RECT  45.504 46.237 45.954 46.507 ;
     RECT  50.904 46.459 51.297 46.507 ;
     RECT  56.304 46.237 56.754 46.507 ;
     RECT  72.252 46.237 72.954 46.507 ;
     RECT  85.932 46.459 86.49 46.507 ;
     RECT  101.376 44.971 102.294 46.507 ;
     RECT  103.176 46.003 107.082 46.507 ;
     RECT  144.9 46.267 146.214 46.507 ;
     RECT  146.952 43.303 147.438 46.507 ;
     RECT  29.304 46.507 29.898 46.535 ;
     RECT  34.704 46.507 35.298 46.535 ;
     RECT  40.104 46.103 40.806 46.535 ;
     RECT  45.504 46.507 46.098 46.535 ;
     RECT  50.904 46.507 51.498 46.535 ;
     RECT  56.304 46.507 56.898 46.535 ;
     RECT  67.104 46.345 71.478 46.555 ;
     RECT  26.64 45.967 26.874 46.603 ;
     RECT  30.78 46.309 30.87 46.603 ;
     RECT  38.772 45.967 38.862 46.603 ;
     RECT  42.768 46.309 42.858 46.603 ;
     RECT  59.256 42.571 59.274 46.603 ;
     RECT  74.196 46.309 74.754 46.603 ;
     RECT  85.932 46.507 86.598 46.603 ;
     RECT  2.415 2.413 2.697 46.615 ;
     RECT  4.752 46.031 11.682 46.615 ;
     RECT  29.415 46.535 29.898 46.637 ;
     RECT  34.815 46.535 35.298 46.637 ;
     RECT  51.015 46.535 51.498 46.637 ;
     RECT  56.415 46.535 56.898 46.637 ;
     RECT  72.252 46.507 73.098 46.637 ;
     RECT  2.268 46.615 2.697 46.651 ;
     RECT  190.224 44.383 190.242 46.651 ;
     RECT  191.232 44.995 194.778 46.651 ;
     RECT  26.64 46.603 26.91 46.733 ;
     RECT  30.78 46.603 30.906 46.733 ;
     RECT  38.772 46.603 38.898 46.733 ;
     RECT  42.768 46.603 42.894 46.733 ;
     RECT  46.872 46.603 46.89 46.733 ;
     RECT  61.488 46.309 62.802 46.733 ;
     RECT  74.196 46.603 74.79 46.733 ;
     RECT  4.176 46.615 11.682 46.741 ;
     RECT  195.552 46.061 198.126 46.741 ;
     RECT  140.184 44.443 143.097 46.795 ;
     RECT  199.368 36.509 199.386 46.843 ;
     RECT  2.268 46.651 2.862 46.849 ;
     RECT  3.816 46.741 11.682 46.849 ;
     RECT  2.268 46.849 11.97 46.885 ;
     RECT  148.215 46.381 149.022 46.885 ;
     RECT  87.588 45.931 96.21 46.891 ;
     RECT  97.272 45.661 100.638 46.891 ;
     RECT  135.936 46.031 135.954 47.011 ;
     RECT  137.052 45.229 138.366 47.011 ;
     RECT  41.76 47.035 41.778 47.075 ;
     RECT  0.108 47.047 0.126 47.119 ;
     RECT  2.232 46.885 11.97 47.119 ;
     RECT  12.744 46.103 15.93 47.119 ;
     RECT  20.412 46.471 25.578 47.119 ;
     RECT  26.64 46.733 26.802 47.119 ;
     RECT  118.44 44.887 119.034 47.119 ;
     RECT  148.215 46.885 149.454 47.131 ;
     RECT  159.015 2.413 159.297 47.131 ;
     RECT  45.612 46.535 46.098 47.155 ;
     RECT  54.828 46.409 55.242 47.155 ;
     RECT  58.824 46.603 59.274 47.155 ;
     RECT  76.32 42.601 76.338 47.155 ;
     RECT  177.3 41.881 177.318 47.155 ;
     RECT  29.415 46.637 29.862 47.309 ;
     RECT  30.78 46.733 30.798 47.309 ;
     RECT  34.815 46.637 35.262 47.309 ;
     RECT  38.772 46.733 38.79 47.309 ;
     RECT  42.768 46.733 42.786 47.309 ;
     RECT  45.612 47.155 46.818 47.309 ;
     RECT  51.015 46.637 51.462 47.309 ;
     RECT  54.72 47.155 55.242 47.309 ;
     RECT  58.716 47.155 59.274 47.309 ;
     RECT  80.1 46.397 84.078 47.309 ;
     RECT  85.932 46.603 86.778 47.309 ;
     RECT  29.415 47.309 29.79 47.315 ;
     RECT  34.815 47.309 35.19 47.315 ;
     RECT  45.612 47.309 45.99 47.315 ;
     RECT  51.015 47.309 51.39 47.315 ;
     RECT  84.96 46.397 85.122 47.317 ;
     RECT  85.932 47.309 86.274 47.317 ;
     RECT  118.188 47.119 119.034 47.323 ;
     RECT  118.188 47.323 119.07 47.419 ;
     RECT  34.815 47.315 35.097 47.551 ;
     RECT  45.612 47.315 45.897 47.551 ;
     RECT  56.415 46.637 56.862 47.551 ;
     RECT  164.415 46.409 164.697 47.551 ;
     RECT  175.176 46.409 175.497 47.551 ;
     RECT  185.904 45.968 186.297 47.551 ;
     RECT  66.528 46.555 71.478 47.587 ;
     RECT  120.528 46.309 125.766 47.587 ;
     RECT  126.615 45.787 129.69 47.587 ;
     RECT  164.304 47.551 164.697 47.597 ;
     RECT  175.104 47.551 175.497 47.597 ;
     RECT  185.868 47.551 186.297 47.597 ;
     RECT  83.415 47.309 84.078 47.623 ;
     RECT  84.96 47.317 86.274 47.623 ;
     RECT  175.176 47.597 175.497 47.623 ;
     RECT  176.328 46.579 176.346 47.623 ;
     RECT  179.748 46.603 179.766 47.623 ;
     RECT  43.164 47.587 43.182 47.645 ;
     RECT  113.184 43.853 113.202 47.659 ;
     RECT  113.976 47.563 113.994 47.659 ;
     RECT  2.232 47.119 15.93 47.693 ;
     RECT  46.728 47.309 46.746 47.693 ;
     RECT  20.412 47.119 26.802 47.695 ;
     RECT  2.34 47.693 15.93 47.731 ;
     RECT  44.28 47.551 44.298 47.821 ;
     RECT  45.504 47.551 45.897 47.821 ;
     RECT  174.312 47.083 174.33 47.821 ;
     RECT  174.312 47.821 174.402 47.849 ;
     RECT  44.208 47.821 44.298 47.885 ;
     RECT  55.224 47.309 55.242 47.899 ;
     RECT  56.304 47.551 56.862 47.899 ;
     RECT  74.196 46.733 74.214 47.899 ;
     RECT  55.224 47.899 56.862 47.929 ;
     RECT  55.224 47.929 57.042 47.957 ;
     RECT  55.98 47.957 57.042 48.029 ;
     RECT  45.324 47.821 45.897 48.043 ;
     RECT  83.415 47.623 86.274 48.091 ;
     RECT  44.676 48.043 45.897 48.119 ;
     RECT  29.415 47.315 29.697 48.139 ;
     RECT  34.704 47.551 35.097 48.139 ;
     RECT  38.88 48.043 38.898 48.139 ;
     RECT  200.7 45.841 211.986 48.163 ;
     RECT  118.188 47.419 119.322 48.199 ;
     RECT  17.748 45.967 19.566 48.235 ;
     RECT  51.015 47.315 51.297 48.235 ;
     RECT  0.108 47.119 0.558 48.269 ;
     RECT  83.415 48.091 86.85 48.269 ;
     RECT  2.34 47.731 16.074 48.271 ;
     RECT  38.772 48.139 38.898 48.283 ;
     RECT  45 48.119 45.897 48.283 ;
     RECT  55.224 47.957 55.242 48.283 ;
     RECT  58.464 47.461 58.482 48.283 ;
     RECT  59.256 47.309 59.274 48.283 ;
     RECT  115.092 43.853 116.73 48.283 ;
     RECT  29.415 48.139 29.898 48.413 ;
     RECT  30.96 48.283 30.978 48.413 ;
     RECT  38.772 48.283 38.97 48.413 ;
     RECT  42.768 48.043 43.002 48.413 ;
     RECT  51.015 48.235 51.714 48.427 ;
     RECT  72.252 46.637 72.99 48.433 ;
     RECT  83.415 48.269 86.274 48.433 ;
     RECT  199.188 46.843 199.386 48.433 ;
     RECT  200.34 48.163 211.986 48.433 ;
     RECT  34.704 48.139 35.406 48.461 ;
     RECT  45 48.283 45.99 48.461 ;
     RECT  61.488 46.733 62.73 48.469 ;
     RECT  40.215 46.535 40.806 48.475 ;
     RECT  46.764 48.139 46.854 48.475 ;
     RECT  114.768 48.283 116.73 48.475 ;
     RECT  174.384 47.849 174.402 48.523 ;
     RECT  175.176 47.623 176.346 48.523 ;
     RECT  185.904 47.597 186.297 48.523 ;
     RECT  2.34 48.271 16.218 48.541 ;
     RECT  16.956 45.959 16.974 48.541 ;
     RECT  80.1 47.309 82.206 48.541 ;
     RECT  172.764 41.215 172.782 48.541 ;
     RECT  61.488 48.469 62.766 48.569 ;
     RECT  174.384 48.523 176.346 48.569 ;
     RECT  185.868 48.523 186.297 48.569 ;
     RECT  40.215 48.475 40.914 48.571 ;
     RECT  46.764 48.475 47.034 48.605 ;
     RECT  2.34 48.541 16.974 48.619 ;
     RECT  40.215 48.571 41.202 48.619 ;
     RECT  51.015 48.427 51.786 48.619 ;
     RECT  34.704 48.461 35.298 48.659 ;
     RECT  40.104 48.619 41.202 48.659 ;
     RECT  50.904 48.619 51.786 48.659 ;
     RECT  49.392 47.857 49.41 48.667 ;
     RECT  79.848 48.541 82.206 48.667 ;
     RECT  159.015 47.131 159.858 48.667 ;
     RECT  164.415 47.597 164.697 48.667 ;
     RECT  0.108 48.269 0.162 48.695 ;
     RECT  38.772 48.413 38.79 48.701 ;
     RECT  40.212 48.659 41.202 48.701 ;
     RECT  74.196 47.899 74.682 48.701 ;
     RECT  135.936 47.011 138.366 48.715 ;
     RECT  139.176 46.921 139.194 48.715 ;
     RECT  49.032 48.667 49.41 48.731 ;
     RECT  0.144 48.695 0.162 48.767 ;
     RECT  61.488 48.569 62.19 48.775 ;
     RECT  30.816 48.667 30.834 48.811 ;
     RECT  74.196 48.701 74.214 48.811 ;
     RECT  87.588 46.891 100.638 48.811 ;
     RECT  101.376 46.507 107.082 48.811 ;
     RECT  113.184 47.659 113.994 48.811 ;
     RECT  114.768 48.475 117.414 48.811 ;
     RECT  79.848 48.667 82.494 48.859 ;
     RECT  83.376 48.433 86.274 48.859 ;
     RECT  172.764 48.541 173.07 48.901 ;
     RECT  40.212 48.701 40.914 48.929 ;
     RECT  46.764 48.605 46.926 48.929 ;
     RECT  64.224 43.291 65.358 48.937 ;
     RECT  118.188 48.199 119.43 48.973 ;
     RECT  30.78 48.811 30.834 48.989 ;
     RECT  34.815 48.659 35.298 48.989 ;
     RECT  42.768 48.413 42.786 48.989 ;
     RECT  79.848 48.859 86.274 48.989 ;
     RECT  54.72 48.283 55.242 49 ;
     RECT  56.304 48.029 57.042 49 ;
     RECT  29.415 48.413 29.79 49.003 ;
     RECT  49.032 48.731 49.338 49.003 ;
     RECT  61.308 48.775 62.19 49.009 ;
     RECT  37.152 49.003 37.17 49.051 ;
     RECT  28.98 49.003 29.79 49.073 ;
     RECT  29.052 49.073 29.79 49.199 ;
     RECT  54.72 49 57.042 49.199 ;
     RECT  51.015 48.659 51.786 49.207 ;
     RECT  195.516 46.741 198.126 49.207 ;
     RECT  199.188 48.433 211.986 49.207 ;
     RECT  37.044 49.051 37.17 49.229 ;
     RECT  45.036 48.461 45.99 49.229 ;
     RECT  48.888 49.003 49.338 49.229 ;
     RECT  2.304 48.619 16.974 49.235 ;
     RECT  109.116 45.869 111.438 49.271 ;
     RECT  148.215 47.131 149.67 49.279 ;
     RECT  17.748 48.235 19.602 49.315 ;
     RECT  20.412 47.695 27.054 49.315 ;
     RECT  87.588 48.811 107.082 49.339 ;
     RECT  83.376 48.989 86.274 49.387 ;
     RECT  2.376 49.235 16.974 49.441 ;
     RECT  17.748 49.315 27.054 49.441 ;
     RECT  2.376 49.441 27.054 49.469 ;
     RECT  51.015 49.207 51.966 49.477 ;
     RECT  135.936 48.715 139.194 49.477 ;
     RECT  140.04 46.795 143.097 49.477 ;
     RECT  1.152 48.427 1.17 49.505 ;
     RECT  3.528 49.469 27.054 49.505 ;
     RECT  83.376 49.387 86.49 49.513 ;
     RECT  2.376 49.469 2.697 49.541 ;
     RECT  64.224 48.937 65.754 49.549 ;
     RECT  66.528 47.587 71.514 49.549 ;
     RECT  72.252 48.433 73.098 49.549 ;
     RECT  73.908 48.811 74.214 49.549 ;
     RECT  77.724 42.457 78.93 49.576 ;
     RECT  64.224 49.549 71.514 49.579 ;
     RECT  34.815 48.989 35.19 49.585 ;
     RECT  40.212 48.929 40.806 49.585 ;
     RECT  50.184 49.279 50.202 49.585 ;
     RECT  51.015 49.477 52.146 49.585 ;
     RECT  30.816 48.989 30.834 49.711 ;
     RECT  40.104 49.585 40.806 49.711 ;
     RECT  83.376 49.513 86.634 49.711 ;
     RECT  112.248 48.379 112.266 49.711 ;
     RECT  174.384 48.569 174.402 49.711 ;
     RECT  175.176 48.569 176.346 49.711 ;
     RECT  182.664 46.397 183.258 49.723 ;
     RECT  29.088 49.199 29.79 49.757 ;
     RECT  39.924 49.711 40.806 49.757 ;
     RECT  83.304 49.711 86.634 49.757 ;
     RECT  144.9 46.507 147.438 49.783 ;
     RECT  60.984 49.009 62.19 49.811 ;
     RECT  185.904 48.569 186.297 49.813 ;
     RECT  42.804 49.711 42.822 49.819 ;
     RECT  182.52 49.723 183.258 49.819 ;
     RECT  185.904 49.813 186.318 49.819 ;
     RECT  63.9 49.579 71.514 49.855 ;
     RECT  182.412 49.819 183.258 49.855 ;
     RECT  107.964 44.923 108.018 49.867 ;
     RECT  113.184 48.811 117.414 49.891 ;
     RECT  118.188 48.973 119.718 49.891 ;
     RECT  61.092 49.811 62.19 49.901 ;
     RECT  63.864 49.855 71.514 49.901 ;
     RECT  187.848 48.235 187.866 49.981 ;
     RECT  188.712 42.025 188.73 49.981 ;
     RECT  187.848 49.981 188.73 50.009 ;
     RECT  195.516 49.207 211.986 50.009 ;
     RECT  54.792 49.199 57.042 50.017 ;
     RECT  190.224 46.651 194.778 50.017 ;
     RECT  44.424 49.351 44.442 50.053 ;
     RECT  172.764 48.901 173.322 50.053 ;
     RECT  179.748 47.623 179.838 50.089 ;
     RECT  83.376 49.757 86.634 50.125 ;
     RECT  87.444 49.339 107.082 50.125 ;
     RECT  4.212 49.505 27.054 50.153 ;
     RECT  4.248 50.153 27.054 50.155 ;
     RECT  29.304 49.757 29.79 50.161 ;
     RECT  30.78 49.711 30.834 50.161 ;
     RECT  112.248 49.711 112.302 50.161 ;
     RECT  113.184 49.891 119.718 50.161 ;
     RECT  77.544 49.576 78.93 50.189 ;
     RECT  159.015 48.667 160.182 50.189 ;
     RECT  54.792 50.017 57.222 50.203 ;
     RECT  40.104 49.757 40.806 50.251 ;
     RECT  185.904 49.819 186.462 50.251 ;
     RECT  50.184 49.585 52.146 50.279 ;
     RECT  163.08 50.161 163.098 50.279 ;
     RECT  177.156 47.155 177.318 50.279 ;
     RECT  185.868 50.251 186.462 50.288 ;
     RECT  29.304 50.161 30.834 50.315 ;
     RECT  109.476 49.271 111.438 50.315 ;
     RECT  44.424 50.053 44.694 50.323 ;
     RECT  45.504 49.229 45.99 50.323 ;
     RECT  49.032 49.229 49.338 50.323 ;
     RECT  29.376 50.315 30.834 50.347 ;
     RECT  34.704 49.585 35.19 50.347 ;
     RECT  37.044 49.229 37.062 50.347 ;
     RECT  77.724 50.189 78.93 50.351 ;
     RECT  29.376 50.347 31.05 50.359 ;
     RECT  61.488 49.901 62.19 50.359 ;
     RECT  63.9 49.901 71.514 50.359 ;
     RECT  72.252 49.549 74.214 50.359 ;
     RECT  107.964 49.867 108.054 50.359 ;
     RECT  135.936 49.477 143.097 50.359 ;
     RECT  29.376 50.359 31.086 50.381 ;
     RECT  40.104 50.251 40.914 50.381 ;
     RECT  34.704 50.347 35.55 50.387 ;
     RECT  135.936 50.359 143.478 50.423 ;
     RECT  77.724 50.351 78.678 50.429 ;
     RECT  42.192 49.819 42.822 50.431 ;
     RECT  140.976 50.423 143.478 50.431 ;
     RECT  144.36 49.783 147.438 50.431 ;
     RECT  107.964 50.359 108.306 50.443 ;
     RECT  109.476 50.315 111.258 50.443 ;
     RECT  187.848 50.009 188.118 50.459 ;
     RECT  30.78 50.381 31.086 50.477 ;
     RECT  37.044 50.347 37.17 50.491 ;
     RECT  42.192 50.431 43.074 50.491 ;
     RECT  153.252 43.133 153.897 50.491 ;
     RECT  164.196 48.667 164.697 50.491 ;
     RECT  169.815 46.409 170.097 50.491 ;
     RECT  180.576 46.345 180.897 50.491 ;
     RECT  44.424 50.323 45.99 50.521 ;
     RECT  46.764 48.929 46.782 50.521 ;
     RECT  54.72 50.203 57.222 50.525 ;
     RECT  182.412 49.855 183.618 50.525 ;
     RECT  180.576 50.491 180.99 50.539 ;
     RECT  107.964 50.443 111.258 50.549 ;
     RECT  153.252 50.491 153.99 50.549 ;
     RECT  164.196 50.491 164.79 50.549 ;
     RECT  37.044 50.491 37.278 50.585 ;
     RECT  83.376 50.125 107.082 50.585 ;
     RECT  109.476 50.549 111.078 50.585 ;
     RECT  50.184 50.279 50.274 50.593 ;
     RECT  37.08 50.585 37.278 50.621 ;
     RECT  140.976 50.431 147.438 50.621 ;
     RECT  42.192 50.491 43.11 50.657 ;
     RECT  34.704 50.387 35.442 50.665 ;
     RECT  30.78 50.477 31.05 50.669 ;
     RECT  34.2 50.665 35.442 50.669 ;
     RECT  37.08 50.621 37.206 50.669 ;
     RECT  48.456 50.323 49.338 50.701 ;
     RECT  50.148 50.593 50.274 50.701 ;
     RECT  112.248 50.161 119.718 50.701 ;
     RECT  120.528 47.587 129.69 50.701 ;
     RECT  150.444 45.959 150.966 50.701 ;
     RECT  48.456 50.701 50.274 50.731 ;
     RECT  83.376 50.585 106.866 50.731 ;
     RECT  195.588 50.009 211.986 50.731 ;
     RECT  48.348 50.731 50.274 50.779 ;
     RECT  150.444 50.701 151.074 50.791 ;
     RECT  151.848 43.609 151.866 50.791 ;
     RECT  155.52 48.505 155.538 50.791 ;
     RECT  4.248 50.155 27.486 50.827 ;
     RECT  130.428 46.031 135.054 50.827 ;
     RECT  135.936 50.423 139.914 50.827 ;
     RECT  150.444 50.791 151.866 50.827 ;
     RECT  44.424 50.521 46.782 50.863 ;
     RECT  60.228 47.083 60.246 50.863 ;
     RECT  79.848 48.989 82.494 50.863 ;
     RECT  83.232 50.731 106.866 50.863 ;
     RECT  150.444 50.827 151.938 50.863 ;
     RECT  189.828 50.017 194.778 50.863 ;
     RECT  195.552 50.731 211.986 50.863 ;
     RECT  148.176 49.279 149.67 50.899 ;
     RECT  150.444 50.863 152.01 50.899 ;
     RECT  159.015 50.189 159.858 50.899 ;
     RECT  185.904 50.288 186.462 50.899 ;
     RECT  144.144 50.621 147.438 50.909 ;
     RECT  40.104 50.381 40.806 50.923 ;
     RECT  42.192 50.657 42.966 50.923 ;
     RECT  153.252 50.549 153.897 50.923 ;
     RECT  158.508 50.899 159.858 50.923 ;
     RECT  79.848 50.863 106.866 50.927 ;
     RECT  140.976 50.621 143.097 50.927 ;
     RECT  172.728 50.053 173.322 50.927 ;
     RECT  130.428 50.827 139.914 50.963 ;
     RECT  161.892 49.891 161.91 50.963 ;
     RECT  44.424 50.863 47.502 50.971 ;
     RECT  48.276 50.779 50.274 50.971 ;
     RECT  112.248 50.701 129.69 50.971 ;
     RECT  130.428 50.963 135.162 50.971 ;
     RECT  155.52 50.791 155.862 50.971 ;
     RECT  112.248 50.971 135.162 50.999 ;
     RECT  135.936 50.963 139.914 50.999 ;
     RECT  61.488 50.359 62.73 51.019 ;
     RECT  155.376 50.971 155.862 51.067 ;
     RECT  4.248 50.827 27.522 51.089 ;
     RECT  76.32 47.155 76.482 51.089 ;
     RECT  112.464 50.999 135.162 51.089 ;
     RECT  178.668 48.811 178.686 51.089 ;
     RECT  129.96 51.089 135.162 51.101 ;
     RECT  76.32 51.089 76.41 51.125 ;
     RECT  79.848 50.927 100.926 51.125 ;
     RECT  101.664 50.927 106.866 51.125 ;
     RECT  107.964 50.549 108.738 51.125 ;
     RECT  112.464 51.089 123.21 51.125 ;
     RECT  153.108 50.923 153.897 51.125 ;
     RECT  108.612 51.125 108.738 51.149 ;
     RECT  112.464 51.125 122.814 51.161 ;
     RECT  169.815 50.491 170.19 51.169 ;
     RECT  96.192 51.125 100.926 51.197 ;
     RECT  101.736 51.125 106.866 51.197 ;
     RECT  169.815 51.169 170.478 51.205 ;
     RECT  2.415 49.541 2.697 51.211 ;
     RECT  27.036 51.089 27.522 51.233 ;
     RECT  76.392 51.125 76.41 51.233 ;
     RECT  112.464 51.161 119.97 51.233 ;
     RECT  120.708 51.161 122.814 51.233 ;
     RECT  2.415 51.211 3.51 51.241 ;
     RECT  4.248 51.089 26.298 51.241 ;
     RECT  29.376 50.381 30.006 51.241 ;
     RECT  44.424 50.971 50.274 51.241 ;
     RECT  51.015 50.279 52.146 51.241 ;
     RECT  177.156 50.279 177.174 51.241 ;
     RECT  189.828 50.863 211.986 51.269 ;
     RECT  29.304 51.241 30.006 51.307 ;
     RECT  30.78 50.669 30.978 51.307 ;
     RECT  58.464 48.283 59.274 51.307 ;
     RECT  60.228 50.863 60.426 51.307 ;
     RECT  61.488 51.019 62.802 51.307 ;
     RECT  63.9 50.359 74.214 51.307 ;
     RECT  101.916 51.197 106.866 51.307 ;
     RECT  144.252 50.909 147.438 51.307 ;
     RECT  148.176 50.899 152.01 51.307 ;
     RECT  155.376 51.067 156.042 51.307 ;
     RECT  164.196 50.549 164.697 51.307 ;
     RECT  167.004 49.315 167.022 51.307 ;
     RECT  169.308 51.205 170.478 51.307 ;
     RECT  28.44 51.241 28.458 51.331 ;
     RECT  38.772 49.891 38.79 51.331 ;
     RECT  44.424 51.241 52.146 51.331 ;
     RECT  77.724 50.429 78.642 51.331 ;
     RECT  153.54 51.125 153.897 51.331 ;
     RECT  155.376 51.307 156.078 51.331 ;
     RECT  156.888 49.081 156.906 51.331 ;
     RECT  168.768 51.307 170.478 51.331 ;
     RECT  172.728 50.927 173.286 51.331 ;
     RECT  182.664 50.525 183.618 51.331 ;
     RECT  184.932 44.185 184.95 51.331 ;
     RECT  185.904 50.899 186.606 51.331 ;
     RECT  77.436 51.331 78.642 51.355 ;
     RECT  177.156 51.241 177.246 51.355 ;
     RECT  179.46 50.089 179.838 51.355 ;
     RECT  180.576 50.539 181.242 51.355 ;
     RECT  2.376 51.241 26.298 51.359 ;
     RECT  60.228 51.307 62.802 51.359 ;
     RECT  75.168 50.089 75.186 51.359 ;
     RECT  79.848 51.125 95.454 51.359 ;
     RECT  96.192 51.197 97.434 51.359 ;
     RECT  123.948 51.089 129.15 51.359 ;
     RECT  160.596 50.701 160.614 51.359 ;
     RECT  172.512 51.331 173.286 51.359 ;
     RECT  174.384 49.711 176.346 51.359 ;
     RECT  177.156 51.355 177.858 51.359 ;
     RECT  179.388 51.355 181.242 51.359 ;
     RECT  187.848 50.459 187.866 51.359 ;
     RECT  27.072 51.233 27.522 51.367 ;
     RECT  28.368 51.331 28.458 51.367 ;
     RECT  63.756 51.307 74.214 51.367 ;
     RECT  101.916 51.307 106.974 51.367 ;
     RECT  144.252 51.307 152.01 51.367 ;
     RECT  168.696 51.331 170.478 51.367 ;
     RECT  185.904 51.331 186.642 51.367 ;
     RECT  63.648 51.367 74.214 51.389 ;
     RECT  43.704 51.331 52.146 51.395 ;
     RECT  65.016 51.389 74.214 51.395 ;
     RECT  79.848 51.359 87.858 51.395 ;
     RECT  88.704 51.359 95.454 51.395 ;
     RECT  112.464 51.233 117.522 51.395 ;
     RECT  123.948 51.359 125.766 51.395 ;
     RECT  136.332 50.999 139.914 51.395 ;
     RECT  144.252 51.367 152.19 51.395 ;
     RECT  179.388 51.359 181.17 51.395 ;
     RECT  182.592 51.331 183.618 51.397 ;
     RECT  29.304 51.307 30.978 51.403 ;
     RECT  31.716 51.367 31.734 51.403 ;
     RECT  34.2 50.669 35.097 51.403 ;
     RECT  37.08 50.669 37.098 51.403 ;
     RECT  39.924 50.923 40.806 51.403 ;
     RECT  41.688 50.923 42.966 51.403 ;
     RECT  50.076 51.395 52.146 51.403 ;
     RECT  53.028 51.331 53.118 51.403 ;
     RECT  54.72 50.525 55.314 51.403 ;
     RECT  56.196 50.525 57.222 51.403 ;
     RECT  58.392 51.307 59.274 51.403 ;
     RECT  77.436 51.355 78.786 51.403 ;
     RECT  140.976 50.927 140.994 51.403 ;
     RECT  153.54 51.331 154.494 51.403 ;
     RECT  185.904 51.367 186.75 51.403 ;
     RECT  189.828 51.269 194.778 51.403 ;
     RECT  38.772 51.331 39.042 51.431 ;
     RECT  126.54 51.359 129.15 51.431 ;
     RECT  80.28 51.395 87.606 51.437 ;
     RECT  96.264 51.359 97.434 51.437 ;
     RECT  29.304 51.403 31.734 51.439 ;
     RECT  33.192 51.331 33.21 51.439 ;
     RECT  77.436 51.403 79.038 51.439 ;
     RECT  155.376 51.331 156.906 51.439 ;
     RECT  157.86 50.923 159.858 51.439 ;
     RECT  166.932 51.307 167.022 51.439 ;
     RECT  167.796 50.107 167.814 51.439 ;
     RECT  153.54 51.403 154.566 51.451 ;
     RECT  164.016 51.307 164.697 51.451 ;
     RECT  166.536 51.439 167.814 51.451 ;
     RECT  65.016 51.395 69.606 51.467 ;
     RECT  88.704 51.395 91.494 51.467 ;
     RECT  2.376 51.359 26.082 51.475 ;
     RECT  37.044 51.403 37.098 51.475 ;
     RECT  39.924 51.403 42.966 51.475 ;
     RECT  43.704 51.395 49.338 51.475 ;
     RECT  50.076 51.403 53.118 51.475 ;
     RECT  101.916 51.367 107.01 51.475 ;
     RECT  114.588 51.395 117.522 51.476 ;
     RECT  2.304 51.475 26.082 51.503 ;
     RECT  58.32 51.403 59.382 51.503 ;
     RECT  83.268 51.437 87.606 51.503 ;
     RECT  98.28 51.197 100.926 51.503 ;
     RECT  182.412 51.397 183.618 51.503 ;
     RECT  189.792 51.403 194.778 51.503 ;
     RECT  155.376 51.439 159.858 51.511 ;
     RECT  168.696 51.367 170.55 51.511 ;
     RECT  177.3 51.359 177.858 51.511 ;
     RECT  184.752 51.331 184.95 51.511 ;
     RECT  77.184 51.439 79.038 51.533 ;
     RECT  29.304 51.439 31.806 51.539 ;
     RECT  162.468 51.259 162.702 51.539 ;
     RECT  70.524 51.395 74.214 51.547 ;
     RECT  141.768 50.927 143.097 51.547 ;
     RECT  58.392 51.503 59.382 51.581 ;
     RECT  114.588 51.476 117.486 51.581 ;
     RECT  153.54 51.451 154.602 51.581 ;
     RECT  153.54 51.581 154.494 51.587 ;
     RECT  27.072 51.367 28.458 51.592 ;
     RECT  164.016 51.451 164.898 51.595 ;
     RECT  185.832 51.403 186.894 51.595 ;
     RECT  37.044 51.475 37.134 51.601 ;
     RECT  145.548 51.395 152.19 51.601 ;
     RECT  182.412 51.503 183.438 51.601 ;
     RECT  32.724 51.439 33.21 51.629 ;
     RECT  38.988 51.431 39.042 51.629 ;
     RECT  39.924 51.475 49.338 51.629 ;
     RECT  58.392 51.581 59.274 51.629 ;
     RECT  63.648 51.389 64.242 51.629 ;
     RECT  65.016 51.467 67.986 51.629 ;
     RECT  68.868 51.467 69.606 51.629 ;
     RECT  77.796 51.533 79.038 51.629 ;
     RECT  84.924 51.503 87.606 51.629 ;
     RECT  96.336 51.437 97.434 51.629 ;
     RECT  101.916 51.475 107.802 51.629 ;
     RECT  109.476 50.585 111.042 51.629 ;
     RECT  112.464 51.395 113.814 51.629 ;
     RECT  120.708 51.233 122.382 51.629 ;
     RECT  138.528 51.395 139.914 51.629 ;
     RECT  140.796 51.403 140.994 51.629 ;
     RECT  141.768 51.547 143.19 51.629 ;
     RECT  144.252 51.395 144.378 51.629 ;
     RECT  153.54 51.587 153.705 51.629 ;
     RECT  155.376 51.511 160.506 51.629 ;
     RECT  166.464 51.451 167.814 51.629 ;
     RECT  168.624 51.511 170.55 51.629 ;
     RECT  174.42 51.359 176.346 51.629 ;
     RECT  179.568 51.395 181.17 51.629 ;
     RECT  189.9 51.503 194.778 51.629 ;
     RECT  54.72 51.403 57.222 51.637 ;
     RECT  184.68 51.511 184.95 51.643 ;
     RECT  27.072 51.592 28.566 51.665 ;
     RECT  39.924 51.629 48.834 51.665 ;
     RECT  60.3 51.359 62.802 51.665 ;
     RECT  80.28 51.437 82.53 51.665 ;
     RECT  84.924 51.629 87.462 51.665 ;
     RECT  96.408 51.629 97.434 51.665 ;
     RECT  102.24 51.629 107.766 51.665 ;
     RECT  109.476 51.629 109.566 51.665 ;
     RECT  112.464 51.629 113.706 51.665 ;
     RECT  120.708 51.629 122.094 51.665 ;
     RECT  123.948 51.395 125.55 51.665 ;
     RECT  126.54 51.431 128.97 51.665 ;
     RECT  138.6 51.629 138.942 51.665 ;
     RECT  139.896 51.629 139.914 51.665 ;
     RECT  141.804 51.629 143.19 51.665 ;
     RECT  145.548 51.601 152.262 51.665 ;
     RECT  155.376 51.629 155.61 51.665 ;
     RECT  39.06 51.637 39.078 51.677 ;
     RECT  50.076 51.475 53.622 51.677 ;
     RECT  54.72 51.637 57.402 51.677 ;
     RECT  126.54 51.665 127.062 51.677 ;
     RECT  136.332 51.395 137.79 51.677 ;
     RECT  138.6 51.665 138.69 51.677 ;
     RECT  142.56 51.665 143.19 51.677 ;
     RECT  182.232 51.601 183.438 51.677 ;
     RECT  30.78 51.539 31.806 51.691 ;
     RECT  28.224 51.665 28.242 51.701 ;
     RECT  65.196 51.629 67.842 51.701 ;
     RECT  70.524 51.547 74.43 51.701 ;
     RECT  80.352 51.665 81.162 51.701 ;
     RECT  82.044 51.665 82.53 51.701 ;
     RECT  88.704 51.467 91.242 51.701 ;
     RECT  96.66 51.665 97.434 51.701 ;
     RECT  104.616 51.665 107.766 51.701 ;
     RECT  109.548 51.665 109.566 51.701 ;
     RECT  156.6 51.629 160.506 51.701 ;
     RECT  172.512 51.359 172.746 51.701 ;
     RECT  177.3 51.511 178.506 51.701 ;
     RECT  185.832 51.595 187.11 51.701 ;
     RECT  29.304 51.539 30.042 51.709 ;
     RECT  63.648 51.629 63.918 51.709 ;
     RECT  140.796 51.629 140.814 51.709 ;
     RECT  77.904 51.629 79.038 51.725 ;
     RECT  138.636 51.677 138.69 51.725 ;
     RECT  140.148 51.709 140.814 51.725 ;
     RECT  145.98 51.665 147.294 51.725 ;
     RECT  158.472 51.701 160.506 51.725 ;
     RECT  164.016 51.595 165.546 51.725 ;
     RECT  37.044 51.601 37.206 51.737 ;
     RECT  44.244 51.665 48.834 51.737 ;
     RECT  60.48 51.665 62.226 51.737 ;
     RECT  63.036 51.709 63.918 51.737 ;
     RECT  65.196 51.701 65.286 51.737 ;
     RECT  92.412 51.395 95.454 51.737 ;
     RECT  96.66 51.701 97.362 51.737 ;
     RECT  124.92 51.665 125.55 51.737 ;
     RECT  126.54 51.677 126.954 51.737 ;
     RECT  128.808 51.665 128.97 51.737 ;
     RECT  138.636 51.725 138.654 51.737 ;
     RECT  141.804 51.665 141.822 51.737 ;
     RECT  148.212 51.665 152.262 51.737 ;
     RECT  164.415 51.725 165.546 51.737 ;
     RECT  168.624 51.629 168.642 51.737 ;
     RECT  177.84 51.701 178.506 51.737 ;
     RECT  179.568 51.629 180.99 51.737 ;
     RECT  182.484 51.677 183.438 51.737 ;
     RECT  189.9 51.629 194.526 51.737 ;
     RECT  39.924 51.665 43.038 51.739 ;
     RECT  52.128 51.677 53.622 51.745 ;
     RECT  54.72 51.677 56.718 51.745 ;
     RECT  98.604 51.503 100.926 51.745 ;
     RECT  184.68 51.643 185.094 51.745 ;
     RECT  185.832 51.701 187.038 51.745 ;
     RECT  30.78 51.691 32.238 51.773 ;
     RECT  34.2 51.403 35.226 51.773 ;
     RECT  37.044 51.737 37.17 51.773 ;
     RECT  44.244 51.737 46.746 51.773 ;
     RECT  58.716 51.629 59.058 51.773 ;
     RECT  60.66 51.737 62.226 51.773 ;
     RECT  65.268 51.737 65.286 51.773 ;
     RECT  70.704 51.701 74.43 51.773 ;
     RECT  81 51.701 81.162 51.773 ;
     RECT  82.044 51.701 82.386 51.773 ;
     RECT  84.924 51.665 85.23 51.773 ;
     RECT  90.072 51.701 91.242 51.773 ;
     RECT  92.52 51.737 95.454 51.773 ;
     RECT  102.24 51.665 103.806 51.773 ;
     RECT  112.896 51.665 113.706 51.773 ;
     RECT  118.44 51.233 119.97 51.773 ;
     RECT  120.78 51.665 122.094 51.773 ;
     RECT  126.54 51.737 126.81 51.773 ;
     RECT  129.96 51.101 135.09 51.773 ;
     RECT  136.332 51.677 137.505 51.773 ;
     RECT  142.56 51.677 142.905 51.773 ;
     RECT  146.16 51.725 147.294 51.773 ;
     RECT  148.215 51.737 152.262 51.773 ;
     RECT  158.472 51.725 159.39 51.773 ;
     RECT  160.308 51.725 160.506 51.773 ;
     RECT  162.504 51.539 162.702 51.773 ;
     RECT  164.415 51.737 164.898 51.773 ;
     RECT  166.464 51.629 167.67 51.773 ;
     RECT  169.815 51.629 170.55 51.773 ;
     RECT  174.42 51.629 175.986 51.773 ;
     RECT  182.484 51.737 183.366 51.773 ;
     RECT  92.52 51.773 95.238 51.779 ;
     RECT  33.156 51.629 33.21 51.781 ;
     RECT  34.2 51.773 35.118 51.781 ;
     RECT  35.964 51.673 35.982 51.781 ;
     RECT  35.928 51.781 35.982 51.782 ;
     RECT  50.076 51.677 51.354 51.782 ;
     RECT  156.6 51.701 157.338 51.782 ;
     RECT  27.072 51.665 27.09 51.809 ;
     RECT  30.78 51.773 31.914 51.809 ;
     RECT  39.384 51.739 43.038 51.809 ;
     RECT  50.076 51.782 51.318 51.809 ;
     RECT  52.128 51.745 56.718 51.809 ;
     RECT  61.704 51.773 62.226 51.809 ;
     RECT  63.036 51.737 63.198 51.809 ;
     RECT  70.704 51.773 74.358 51.809 ;
     RECT  90.072 51.773 90.846 51.809 ;
     RECT  119.628 51.773 119.97 51.809 ;
     RECT  120.852 51.773 122.094 51.809 ;
     RECT  126.54 51.773 126.774 51.809 ;
     RECT  150.48 51.773 152.262 51.809 ;
     RECT  158.472 51.773 159.105 51.809 ;
     RECT  160.308 51.773 160.326 51.809 ;
     RECT  174.42 51.773 175.842 51.809 ;
     RECT  179.604 51.737 180.705 51.809 ;
     RECT  182.808 51.773 183.366 51.809 ;
     RECT  184.68 51.745 187.038 51.809 ;
     RECT  190.944 51.737 194.526 51.809 ;
     RECT  61.704 51.809 62.01 51.821 ;
     RECT  77.904 51.725 78.93 51.821 ;
     RECT  82.044 51.773 82.242 51.821 ;
     RECT  90.072 51.809 90.81 51.821 ;
     RECT  92.628 51.779 95.238 51.821 ;
     RECT  114.588 51.581 117.414 51.821 ;
     RECT  120.852 51.809 121.986 51.821 ;
     RECT  147.276 51.773 147.294 51.821 ;
     RECT  148.215 51.773 149.634 51.821 ;
     RECT  156.6 51.782 157.302 51.821 ;
     RECT  180.504 51.809 180.705 51.821 ;
     RECT  33.156 51.781 35.118 51.857 ;
     RECT  39.492 51.809 43.038 51.857 ;
     RECT  51.015 51.809 51.318 51.857 ;
     RECT  61.815 51.821 61.905 51.857 ;
     RECT  93.492 51.821 95.238 51.857 ;
     RECT  121.215 51.821 121.986 51.857 ;
     RECT  126.615 51.809 126.705 51.857 ;
     RECT  137.088 51.773 137.505 51.857 ;
     RECT  142.632 51.773 142.905 51.857 ;
     RECT  148.215 51.821 148.914 51.857 ;
     RECT  153.615 51.629 153.705 51.857 ;
     RECT  159.015 51.809 159.105 51.857 ;
     RECT  164.415 51.773 164.505 51.857 ;
     RECT  169.815 51.773 170.514 51.857 ;
     RECT  180.615 51.821 180.705 51.857 ;
     RECT  184.68 51.809 186.822 51.857 ;
     RECT  30.78 51.809 31.014 51.869 ;
     RECT  39.492 51.857 39.51 51.869 ;
     RECT  40.356 51.857 43.038 51.869 ;
     RECT  44.244 51.773 45.954 51.869 ;
     RECT  47.7 51.737 48.834 51.869 ;
     RECT  52.992 51.809 56.718 51.869 ;
     RECT  60.66 51.773 60.75 51.869 ;
     RECT  77.904 51.821 78.858 51.869 ;
     RECT  81.036 51.773 81.162 51.869 ;
     RECT  94.464 51.857 95.238 51.869 ;
     RECT  96.66 51.737 97.146 51.869 ;
     RECT  110.304 51.629 111.042 51.869 ;
     RECT  114.66 51.821 116.658 51.869 ;
     RECT  119.844 51.809 119.97 51.869 ;
     RECT  129.96 51.773 132.21 51.869 ;
     RECT  137.088 51.857 137.106 51.869 ;
     RECT  150.48 51.809 152.19 51.869 ;
     RECT  55.476 51.869 56.718 51.872 ;
     RECT  88.704 51.701 89.118 51.872 ;
     RECT  29.016 51.709 30.042 51.899 ;
     RECT  51.156 51.857 51.318 51.899 ;
     RECT  167.004 51.773 167.598 51.899 ;
     RECT  184.68 51.857 185.85 51.899 ;
     RECT  55.476 51.872 56.682 51.917 ;
     RECT  66.132 51.701 67.842 51.917 ;
     RECT  77.904 51.869 78.282 51.917 ;
     RECT  88.704 51.872 89.082 51.917 ;
     RECT  175.104 51.809 175.842 51.917 ;
     RECT  184.68 51.899 184.878 51.917 ;
     RECT  29.304 51.899 29.682 51.935 ;
     RECT  44.316 51.869 45.954 51.935 ;
     RECT  58.716 51.773 58.842 51.935 ;
     RECT  70.704 51.809 73.062 51.935 ;
     RECT  172.512 51.701 172.53 51.935 ;
     RECT  45.828 51.935 45.954 51.965 ;
     RECT  68.94 51.629 69.606 51.965 ;
     RECT  70.848 51.935 73.062 51.965 ;
     RECT  74.016 51.809 74.358 51.965 ;
     RECT  81.144 51.869 81.162 51.965 ;
     RECT  40.356 51.869 42.786 51.971 ;
     RECT  47.7 51.869 48.438 51.971 ;
     RECT  52.992 51.869 54.738 51.971 ;
     RECT  56.664 51.917 56.682 51.971 ;
     RECT  67.464 51.917 67.842 51.971 ;
     RECT  71.496 51.965 73.062 51.971 ;
     RECT  78.264 51.917 78.282 51.971 ;
     RECT  83.268 51.503 84.042 51.971 ;
     RECT  84.924 51.773 84.942 51.971 ;
     RECT  89.064 51.917 89.082 51.971 ;
     RECT  90.072 51.821 90.666 51.971 ;
     RECT  92.628 51.821 92.646 51.971 ;
     RECT  93.492 51.857 93.51 51.971 ;
     RECT  169.992 51.857 170.514 51.971 ;
     RECT  175.464 51.917 175.842 51.971 ;
     RECT  186.804 51.857 186.822 51.971 ;
     RECT  195.516 51.269 211.986 51.971 ;
     RECT  0.144 51.943 0.162 51.979 ;
     RECT  44.316 51.935 44.874 52.007 ;
     RECT  45.828 51.965 45.846 52.007 ;
     RECT  66.132 51.917 66.402 52.007 ;
     RECT  98.604 51.745 100.998 52.007 ;
     RECT  103.536 51.773 103.806 52.007 ;
     RECT  132.984 51.773 135.09 52.007 ;
     RECT  30.78 51.869 30.798 52.013 ;
     RECT  34.992 51.857 35.118 52.013 ;
     RECT  48.42 51.971 48.438 52.013 ;
     RECT  102.24 51.773 102.726 52.013 ;
     RECT  104.616 51.701 107.694 52.013 ;
     RECT  167.004 51.899 167.022 52.013 ;
     RECT  169.992 51.971 170.442 52.013 ;
     RECT  71.496 51.971 72.99 52.043 ;
     RECT  74.016 51.965 74.034 52.043 ;
     RECT  82.224 51.821 82.242 52.043 ;
     RECT  83.988 51.971 84.006 52.043 ;
     RECT  104.616 52.013 106.902 52.043 ;
     RECT  110.628 51.869 110.79 52.043 ;
     RECT  114.876 51.869 116.658 52.043 ;
     RECT  129.96 51.869 131.31 52.043 ;
     RECT  132.192 51.869 132.21 52.043 ;
     RECT  170.424 52.013 170.442 52.043 ;
     RECT  175.536 51.971 175.842 52.043 ;
     RECT  33.156 51.857 34.218 52.061 ;
     RECT  52.992 51.971 54.09 52.061 ;
     RECT  67.536 51.971 67.842 52.061 ;
     RECT  98.748 52.007 100.998 52.061 ;
     RECT  40.356 51.971 42.21 52.079 ;
     RECT  63.036 51.809 63.126 52.079 ;
     RECT  67.536 52.061 67.554 52.079 ;
     RECT  98.748 52.061 100.278 52.079 ;
     RECT  190.944 51.809 194.418 52.079 ;
     RECT  33.156 52.061 33.462 52.109 ;
     RECT  35.1 52.013 35.118 52.109 ;
     RECT  69.516 51.965 69.606 52.109 ;
     RECT  102.24 52.013 102.618 52.109 ;
     RECT  190.944 52.079 192.906 52.124 ;
     RECT  128.808 51.737 128.826 52.157 ;
     RECT  177.84 51.737 177.858 52.157 ;
     RECT  112.896 51.773 113.562 52.169 ;
     RECT  0.108 51.979 0.162 52.171 ;
     RECT  112.896 52.169 113.166 52.205 ;
     RECT  102.24 52.109 102.438 52.241 ;
     RECT  142.632 51.857 142.65 52.241 ;
     RECT  216.756 52.177 216.774 52.249 ;
     RECT  148.896 51.857 148.914 52.253 ;
     RECT  90.072 51.971 90.09 52.277 ;
     RECT  150.768 51.869 152.19 52.277 ;
     RECT  69.516 52.109 69.534 52.301 ;
     RECT  0.108 52.171 0.558 52.313 ;
     RECT  55.476 51.917 55.89 52.313 ;
     RECT  150.768 52.277 151.506 52.313 ;
     RECT  190.98 52.124 192.906 52.313 ;
     RECT  216.756 52.249 216.81 52.321 ;
     RECT  218.268 52.285 218.286 52.321 ;
     RECT  219.528 52.141 219.546 52.321 ;
     RECT  53.604 52.061 54.09 52.349 ;
     RECT  95.148 51.869 95.238 52.349 ;
     RECT  185.832 51.899 185.85 52.349 ;
     RECT  44.352 52.007 44.874 52.394 ;
     RECT  183.348 51.809 183.366 52.394 ;
     RECT  104.616 52.043 104.634 52.397 ;
     RECT  44.856 52.394 44.874 52.439 ;
     RECT  50.076 51.809 50.094 52.475 ;
     RECT  116.28 52.043 116.658 52.475 ;
     RECT  133.452 52.007 135.09 52.511 ;
     RECT  71.496 52.043 72.234 52.547 ;
     RECT  40.356 52.079 41.562 52.583 ;
     RECT  189.828 52.285 189.846 52.583 ;
     RECT  95.148 52.349 95.166 52.589 ;
     RECT  195.696 51.971 211.986 52.589 ;
     RECT  215.568 52.321 215.586 52.591 ;
     RECT  60.66 51.869 60.678 52.603 ;
     RECT  35.928 51.782 35.946 52.619 ;
     RECT  133.452 52.511 134.442 52.619 ;
     RECT  216.756 52.321 218.286 52.681 ;
     RECT  114.876 52.043 115.002 52.685 ;
     RECT  52.128 51.809 52.146 52.709 ;
     RECT  116.64 52.475 116.658 52.709 ;
     RECT  2.304 51.503 25.542 52.733 ;
     RECT  54.072 52.349 54.09 52.733 ;
     RECT  112.896 52.205 113.13 52.745 ;
     RECT  114.876 52.685 114.894 52.745 ;
     RECT  96.66 51.869 96.678 52.781 ;
     RECT  118.44 51.773 118.458 52.781 ;
     RECT  215.568 52.591 215.658 52.789 ;
     RECT  216.576 52.681 218.286 52.789 ;
     RECT  105.876 52.043 106.902 52.817 ;
     RECT  119.952 51.869 119.97 52.817 ;
     RECT  2.304 52.733 23.886 52.825 ;
     RECT  214.992 52.789 215.658 52.825 ;
     RECT  216.468 52.789 218.322 52.825 ;
     RECT  150.768 52.313 151.038 52.829 ;
     RECT  188.676 51.331 188.694 52.829 ;
     RECT  99.756 52.079 100.278 52.853 ;
     RECT  162.828 51.781 162.846 52.853 ;
     RECT  66.384 52.007 66.402 52.877 ;
     RECT  71.784 52.547 72.234 52.877 ;
     RECT  193.824 52.079 194.418 52.889 ;
     RECT  131.292 52.043 131.31 52.925 ;
     RECT  24.912 52.733 25.542 52.934 ;
     RECT  194.4 52.889 194.418 52.934 ;
     RECT  196.092 52.589 211.986 52.951 ;
     RECT  102.42 52.241 102.438 52.973 ;
     RECT  24.948 52.934 25.542 52.979 ;
     RECT  214.992 52.825 218.322 52.987 ;
     RECT  219.492 52.321 219.546 52.987 ;
     RECT  33.444 52.109 33.462 53.015 ;
     RECT  196.092 52.951 212.022 53.015 ;
     RECT  107.676 52.013 107.694 53.021 ;
     RECT  113.112 52.745 113.13 53.051 ;
     RECT  154.476 51.587 154.494 53.069 ;
     RECT  71.784 52.877 71.802 53.087 ;
     RECT  156.672 51.821 156.762 53.087 ;
     RECT  121.932 51.857 121.986 53.117 ;
     RECT  75.24 52.747 75.258 53.123 ;
     RECT  124.92 51.737 124.938 53.123 ;
     RECT  133.452 52.619 133.974 53.123 ;
     RECT  85.968 51.665 85.986 53.159 ;
     RECT  133.956 53.123 133.974 53.159 ;
     RECT  184.68 51.917 184.698 53.159 ;
     RECT  60.444 52.603 60.678 53.204 ;
     RECT  99.756 52.853 99.774 53.204 ;
     RECT  196.092 53.015 196.11 53.213 ;
     RECT  219.456 52.987 219.546 53.221 ;
     RECT  129.96 52.043 130.374 53.261 ;
     RECT  117.396 51.821 117.414 53.275 ;
     RECT  0.108 52.313 0.162 53.401 ;
     RECT  214.38 52.987 218.322 53.941 ;
     RECT  219.456 53.221 219.582 53.941 ;
     RECT  2.232 52.825 23.886 54 ;
     RECT  24.984 52.979 25.542 54 ;
     RECT  31.896 51.809 31.914 54 ;
     RECT  34.2 52.061 34.218 54 ;
     RECT  40.356 52.583 40.986 54 ;
     RECT  46.728 51.773 46.746 54 ;
     RECT  51.3 51.899 51.318 54 ;
     RECT  55.476 52.313 55.494 54 ;
     RECT  60.66 53.204 60.678 54 ;
     RECT  63.108 52.079 63.126 54 ;
     RECT  98.748 52.079 98.766 54 ;
     RECT  103.536 52.007 103.554 54 ;
     RECT  105.876 52.817 105.894 54 ;
     RECT  106.884 52.817 106.902 54 ;
     RECT  114.588 53.179 114.606 54 ;
     RECT  117.396 53.275 117.522 54 ;
     RECT  121.932 53.117 121.95 54 ;
     RECT  129.96 53.261 129.978 54 ;
     RECT  136.332 51.773 136.35 54 ;
     RECT  140.148 51.725 140.166 54 ;
     RECT  150.768 52.829 150.786 54 ;
     RECT  156.672 53.087 156.69 54 ;
     RECT  165.708 51.781 165.726 54 ;
     RECT  175.824 52.043 175.842 54 ;
     RECT  179.604 51.809 179.622 54 ;
     RECT  190.98 52.313 192.114 54 ;
     RECT  192.888 52.313 192.906 54 ;
     RECT  197.244 53.015 212.022 54 ;
     RECT  2.232 54 212.022 54.031 ;
     RECT  214.38 53.941 219.582 54.031 ;
     RECT  213.015 2.413 213.297 54.067 ;
     RECT  213.015 54.067 213.354 54.103 ;
     RECT  214.308 54.031 219.582 54.103 ;
     RECT  213.015 54.103 219.582 54.139 ;
     RECT  212.94 54.139 219.582 54.337 ;
     RECT  0.108 53.401 0.558 54.509 ;
     RECT  2.232 54.031 212.058 54.607 ;
     RECT  212.904 54.337 219.582 54.607 ;
     RECT  2.232 54.607 219.582 55.085 ;
     RECT  2.232 55.085 219.438 55.181 ;
     RECT  0.108 54.509 0.126 55.247 ;
     RECT  2.232 55.181 218.898 55.373 ;
     RECT  0.216 55.339 0.342 55.469 ;
     RECT  0.216 55.469 0.306 55.709 ;
     RECT  0.216 55.709 0.234 55.805 ;
     RECT  2.232 55.373 218.142 55.949 ;
     RECT  11.52 55.949 218.142 55.997 ;
     RECT  2.232 55.949 10.602 56.059 ;
     RECT  1.152 54.955 1.17 56.093 ;
     RECT  2.196 56.059 10.602 56.099 ;
     RECT  11.664 55.997 218.142 56.107 ;
     RECT  218.88 55.373 218.898 56.107 ;
     RECT  2.268 56.099 10.602 56.141 ;
     RECT  11.664 56.107 218.898 56.219 ;
     RECT  0.144 56.011 0.162 56.285 ;
     RECT  11.988 56.219 218.898 56.327 ;
     RECT  12.06 56.327 218.898 56.489 ;
     RECT  12.204 56.489 218.898 56.525 ;
     RECT  220.212 56.875 220.23 56.971 ;
     RECT  2.304 56.141 10.602 57.037 ;
     RECT  2.304 57.037 10.854 57.137 ;
     RECT  12.24 56.525 218.898 57.389 ;
     RECT  220.176 56.971 220.23 57.451 ;
     RECT  12.24 57.389 218.574 57.569 ;
     RECT  1.152 56.971 1.17 57.605 ;
     RECT  0.108 56.779 0.126 57.643 ;
     RECT  0.108 57.643 0.558 57.947 ;
     RECT  0.108 57.947 0.342 58.061 ;
     RECT  13.215 57.569 218.574 58.171 ;
     RECT  219.42 57.451 220.23 58.171 ;
     RECT  2.304 57.137 10.602 58.253 ;
     RECT  2.304 58.253 10.278 58.829 ;
     RECT  2.304 58.829 9.954 59.099 ;
     RECT  2.304 59.099 9.378 59.189 ;
     RECT  0.108 58.061 0.198 59.225 ;
     RECT  0.108 59.225 0.126 60.107 ;
     RECT  12.24 57.569 12.474 60.269 ;
     RECT  2.304 59.189 9.054 60.427 ;
     RECT  1.152 59.755 1.17 60.523 ;
     RECT  1.152 60.523 1.206 60.575 ;
     RECT  2.268 60.427 9.054 60.845 ;
     RECT  1.188 60.575 1.206 61.655 ;
     RECT  13.215 58.171 220.23 61.709 ;
     RECT  218.88 61.709 220.23 61.799 ;
     RECT  2.304 60.845 9.054 62.041 ;
     RECT  2.268 62.041 9.054 62.093 ;
     RECT  2.304 62.093 9.054 62.203 ;
     RECT  10.908 62.167 10.926 62.267 ;
     RECT  2.304 62.203 9.198 62.311 ;
     RECT  13.215 61.709 217.89 62.779 ;
     RECT  218.88 61.799 218.898 62.779 ;
     RECT  13.215 62.779 218.898 63.005 ;
     RECT  204.336 63.005 218.898 63.013 ;
     RECT  220.032 61.799 220.23 63.013 ;
     RECT  2.304 62.311 9.27 63.121 ;
     RECT  204.336 63.013 220.23 63.149 ;
     RECT  12.456 60.269 12.474 63.211 ;
     RECT  13.215 63.005 203.526 63.211 ;
     RECT  218.844 63.149 220.23 63.245 ;
     RECT  2.304 63.121 9.306 63.283 ;
     RECT  10.836 63.391 10.854 63.509 ;
     RECT  2.304 63.283 9.342 63.689 ;
     RECT  12.456 63.211 203.526 63.895 ;
     RECT  218.844 63.245 219.402 63.979 ;
     RECT  220.14 63.245 220.23 63.979 ;
     RECT  0.108 62.155 0.126 64.075 ;
     RECT  0.108 64.075 0.162 64.085 ;
     RECT  12.456 63.895 203.562 64.165 ;
     RECT  204.336 63.149 217.854 64.165 ;
     RECT  0.144 64.085 0.162 64.391 ;
     RECT  12.456 64.165 217.854 64.561 ;
     RECT  12.348 64.561 217.854 64.637 ;
     RECT  12.456 64.637 217.854 64.769 ;
     RECT  2.304 63.689 9.054 64.843 ;
     RECT  2.268 64.843 9.054 64.859 ;
     RECT  12.456 64.769 13.497 64.859 ;
     RECT  2.268 64.859 8.478 64.895 ;
     RECT  14.472 64.769 217.854 64.895 ;
     RECT  1.152 64.555 1.17 64.939 ;
     RECT  218.844 63.979 220.23 64.967 ;
     RECT  14.472 64.895 203.274 64.973 ;
     RECT  204.048 64.895 217.854 65.035 ;
     RECT  218.844 64.967 220.194 65.035 ;
     RECT  14.544 64.973 203.274 65.069 ;
     RECT  204.048 65.035 220.194 65.129 ;
     RECT  9.252 65.101 9.27 65.165 ;
     RECT  22.212 65.069 203.274 65.165 ;
     RECT  2.268 64.895 6.354 65.237 ;
     RECT  2.268 65.237 6.318 65.273 ;
     RECT  7.092 64.895 8.478 65.309 ;
     RECT  7.815 65.309 8.478 65.399 ;
     RECT  2.304 65.273 6.318 65.507 ;
     RECT  2.412 65.507 6.066 65.705 ;
     RECT  14.544 65.069 21.438 65.821 ;
     RECT  22.212 65.165 198.414 65.821 ;
     RECT  1.152 64.939 1.314 65.975 ;
     RECT  1.296 65.975 1.314 66.047 ;
     RECT  204.336 65.129 220.194 66.187 ;
     RECT  14.544 65.821 198.414 66.209 ;
     RECT  14.724 66.209 198.414 66.325 ;
     RECT  199.188 65.165 203.274 66.325 ;
     RECT  2.415 65.705 6.066 66.353 ;
     RECT  204.336 66.187 220.23 66.353 ;
     RECT  2.415 66.353 5.634 66.479 ;
     RECT  204.336 66.353 220.194 66.551 ;
     RECT  2.415 66.479 5.382 66.587 ;
     RECT  14.724 66.325 203.274 66.605 ;
     RECT  2.415 66.587 4.23 66.623 ;
     RECT  3.6 66.623 4.23 66.749 ;
     RECT  5.112 66.587 5.382 66.749 ;
     RECT  3.6 66.749 4.05 66.785 ;
     RECT  3.6 66.785 3.978 66.797 ;
     RECT  3.96 66.797 3.978 66.857 ;
     RECT  199.188 66.605 203.274 66.901 ;
     RECT  12.456 64.859 12.474 66.929 ;
     RECT  14.724 66.605 198.378 67.127 ;
     RECT  199.188 66.901 203.454 67.675 ;
     RECT  204.336 66.551 220.158 67.739 ;
     RECT  199.188 67.675 203.49 67.801 ;
     RECT  204.588 67.739 220.158 67.819 ;
     RECT  198.936 67.801 203.562 67.901 ;
     RECT  204.588 67.819 220.194 67.901 ;
     RECT  14.724 67.127 197.766 67.981 ;
     RECT  198.936 67.901 203.49 67.981 ;
     RECT  204.912 67.901 220.194 68.203 ;
     RECT  204.912 68.203 220.23 68.369 ;
     RECT  205.38 68.369 220.23 68.549 ;
     RECT  14.724 67.981 203.49 68.909 ;
     RECT  7.815 65.399 8.097 68.989 ;
     RECT  5.364 66.749 5.382 69.017 ;
     RECT  203.472 68.909 203.49 69.719 ;
     RECT  205.92 68.549 220.23 70.123 ;
     RECT  14.724 68.909 202.626 70.439 ;
     RECT  14.724 70.439 198.45 70.673 ;
     RECT  205.92 70.123 220.302 70.673 ;
     RECT  205.92 70.673 219.402 70.799 ;
     RECT  205.92 70.799 219.222 71.105 ;
     RECT  16.452 70.673 198.45 71.383 ;
     RECT  199.188 70.439 202.626 71.383 ;
     RECT  220.14 70.673 220.302 71.519 ;
     RECT  212.58 71.105 219.222 71.717 ;
     RECT  16.452 71.383 202.626 71.789 ;
     RECT  204.12 71.491 204.138 72.031 ;
     RECT  220.284 71.519 220.302 72.059 ;
     RECT  212.832 71.717 219.222 72.149 ;
     RECT  213.015 72.149 219.222 72.419 ;
     RECT  21.924 71.789 202.626 72.461 ;
     RECT  213.015 72.419 218.034 72.491 ;
     RECT  14.724 70.673 15.714 72.571 ;
     RECT  16.452 71.789 21.114 72.571 ;
     RECT  22.5 72.461 202.626 72.599 ;
     RECT  22.5 72.599 202.497 72.689 ;
     RECT  214.416 72.491 218.034 72.689 ;
     RECT  204.084 72.031 204.138 72.797 ;
     RECT  205.92 71.105 211.338 72.841 ;
     RECT  14.724 72.571 21.15 72.869 ;
     RECT  205.92 72.841 211.95 72.931 ;
     RECT  213.015 72.491 213.297 72.931 ;
     RECT  218.88 72.419 219.222 72.931 ;
     RECT  205.92 72.931 213.297 72.959 ;
     RECT  18.288 72.869 21.15 72.995 ;
     RECT  206.1 72.959 213.297 72.995 ;
     RECT  204.084 72.797 204.102 73.067 ;
     RECT  18.324 72.995 21.15 73.133 ;
     RECT  210.276 72.995 213.297 73.381 ;
     RECT  214.848 72.689 218.034 73.381 ;
     RECT  218.88 72.931 219.474 73.381 ;
     RECT  210.276 73.381 213.678 73.471 ;
     RECT  18.324 73.133 21.114 73.499 ;
     RECT  14.724 72.869 17.514 73.723 ;
     RECT  18.324 73.499 20.214 73.723 ;
     RECT  206.1 72.995 209.538 73.777 ;
     RECT  210.276 73.471 214.038 73.777 ;
     RECT  214.848 73.381 219.474 73.777 ;
     RECT  206.1 73.777 219.474 73.805 ;
     RECT  22.5 72.689 198.45 73.877 ;
     RECT  199.188 72.689 202.497 73.913 ;
     RECT  199.188 73.913 201.222 74.047 ;
     RECT  22.5 73.877 197.766 74.119 ;
     RECT  21.096 73.499 21.114 74.189 ;
     RECT  198.936 74.047 201.222 74.189 ;
     RECT  206.352 73.805 219.474 74.299 ;
     RECT  206.352 74.299 220.158 74.317 ;
     RECT  14.724 73.723 20.214 74.443 ;
     RECT  14.724 74.443 20.574 74.461 ;
     RECT  206.352 74.317 220.23 74.534 ;
     RECT  14.544 74.461 20.574 74.579 ;
     RECT  14.544 74.579 20.43 74.587 ;
     RECT  14.4 74.587 20.43 74.621 ;
     RECT  22.248 74.119 197.766 74.635 ;
     RECT  201.96 73.913 202.497 74.759 ;
     RECT  206.352 74.534 217.926 74.759 ;
     RECT  206.352 74.759 209.214 74.849 ;
     RECT  21.672 74.635 197.766 75.046 ;
     RECT  199.188 74.189 201.222 75.046 ;
     RECT  218.844 74.534 220.23 75.053 ;
     RECT  218.952 75.053 220.23 75.341 ;
     RECT  14.4 74.621 19.458 75.352 ;
     RECT  14.364 75.352 19.458 75.389 ;
     RECT  14.832 75.389 19.458 75.532 ;
     RECT  20.412 74.621 20.43 75.541 ;
     RECT  209.988 74.759 217.926 75.541 ;
     RECT  14.832 75.532 19.494 75.631 ;
     RECT  20.304 75.541 20.43 75.631 ;
     RECT  21.672 75.046 201.222 75.703 ;
     RECT  14.832 75.631 20.43 75.775 ;
     RECT  206.352 74.849 209.034 75.901 ;
     RECT  209.952 75.541 217.926 75.901 ;
     RECT  14.832 75.775 20.718 75.929 ;
     RECT  218.952 75.341 219.438 75.979 ;
     RECT  206.352 75.901 217.926 76.109 ;
     RECT  220.212 75.341 220.23 76.171 ;
     RECT  206.676 76.109 217.926 76.253 ;
     RECT  207 76.253 217.926 76.258 ;
     RECT  218.844 75.979 219.438 76.267 ;
     RECT  220.176 76.171 220.23 76.267 ;
     RECT  209.736 76.258 217.926 76.343 ;
     RECT  14.832 75.929 20.646 76.363 ;
     RECT  211.392 76.343 217.926 76.363 ;
     RECT  218.844 76.267 220.23 76.363 ;
     RECT  207 76.258 208.998 76.379 ;
     RECT  21.636 75.703 201.222 76.397 ;
     RECT  209.736 76.343 210.402 76.469 ;
     RECT  211.392 76.363 220.23 76.469 ;
     RECT  208.98 76.379 208.998 76.541 ;
     RECT  207 76.379 208.062 76.613 ;
     RECT  207 76.613 207.897 76.649 ;
     RECT  14.4 76.363 20.646 76.739 ;
     RECT  14.4 76.739 14.418 76.775 ;
     RECT  15.48 76.739 20.646 76.775 ;
     RECT  15.552 76.775 20.646 76.783 ;
     RECT  21.636 76.397 198.45 76.783 ;
     RECT  211.392 76.469 212.058 76.811 ;
     RECT  209.844 76.469 210.402 76.883 ;
     RECT  213.015 76.469 220.23 76.919 ;
     RECT  15.552 76.783 198.45 76.973 ;
     RECT  211.428 76.811 212.058 77.009 ;
     RECT  209.844 76.883 209.862 77.045 ;
     RECT  213.015 76.919 214.002 77.069 ;
     RECT  10.8 76.987 10.818 77.117 ;
     RECT  212.04 77.009 212.058 77.153 ;
     RECT  21.672 76.973 198.45 77.287 ;
     RECT  199.188 76.397 201.222 77.287 ;
     RECT  214.74 76.919 220.23 77.315 ;
     RECT  214.812 77.315 220.23 77.585 ;
     RECT  15.552 76.973 20.718 77.701 ;
     RECT  214.992 77.585 220.23 77.729 ;
     RECT  21.672 77.287 201.222 77.803 ;
     RECT  14.904 77.701 20.718 77.819 ;
     RECT  214.992 77.729 220.194 77.819 ;
     RECT  21.636 77.803 201.222 77.855 ;
     RECT  213.015 77.069 213.786 77.855 ;
     RECT  15.048 77.819 20.718 77.927 ;
     RECT  215.28 77.819 220.194 77.999 ;
     RECT  21.744 77.855 201.222 78.089 ;
     RECT  215.28 77.999 218.826 78.089 ;
     RECT  15.12 77.927 20.718 78.125 ;
     RECT  21.744 78.089 21.762 78.125 ;
     RECT  15.12 78.125 15.138 78.359 ;
     RECT  15.984 78.125 20.718 78.359 ;
     RECT  215.964 78.089 218.826 78.359 ;
     RECT  16.164 78.359 20.718 78.395 ;
     RECT  22.5 78.089 201.222 78.395 ;
     RECT  216.108 78.359 218.25 78.395 ;
     RECT  16.56 78.395 20.718 78.467 ;
     RECT  2.415 66.623 2.697 78.469 ;
     RECT  2.415 78.469 3.006 78.475 ;
     RECT  2.415 78.475 3.114 78.511 ;
     RECT  220.104 77.999 220.194 78.539 ;
     RECT  2.415 78.511 3.402 78.619 ;
     RECT  216.432 78.395 218.25 78.665 ;
     RECT  16.56 78.467 20.214 78.701 ;
     RECT  4.716 78.715 4.734 78.763 ;
     RECT  216.432 78.665 216.45 78.899 ;
     RECT  217.368 78.665 218.25 78.899 ;
     RECT  220.176 78.539 220.194 78.899 ;
     RECT  2.415 78.619 3.654 78.907 ;
     RECT  4.716 78.763 4.95 78.907 ;
     RECT  2.415 78.907 4.95 79.015 ;
     RECT  17.136 78.701 20.214 79.169 ;
     RECT  217.44 78.899 218.25 79.169 ;
     RECT  217.44 79.169 217.566 79.205 ;
     RECT  22.5 78.395 198.45 79.213 ;
     RECT  199.188 78.395 201.222 79.213 ;
     RECT  21.096 78.955 21.114 79.339 ;
     RECT  2.304 79.015 4.95 79.411 ;
     RECT  7.308 68.989 8.097 79.411 ;
     RECT  217.476 79.205 217.566 79.439 ;
     RECT  217.476 79.439 217.494 79.475 ;
     RECT  16.344 79.195 16.362 79.555 ;
     RECT  17.136 79.169 19.782 79.555 ;
     RECT  2.304 79.411 5.346 79.591 ;
     RECT  2.304 79.591 6.066 79.675 ;
     RECT  2.268 79.675 6.066 79.681 ;
     RECT  6.84 79.411 8.097 79.681 ;
     RECT  20.52 79.339 21.114 79.708 ;
     RECT  16.02 79.555 19.782 79.709 ;
     RECT  20.52 79.708 21.15 79.915 ;
     RECT  17.316 79.709 19.782 80.015 ;
     RECT  17.532 80.015 19.782 80.107 ;
     RECT  20.52 79.915 21.654 80.107 ;
     RECT  17.532 80.107 21.654 80.237 ;
     RECT  14.832 79.321 14.85 80.249 ;
     RECT  22.5 79.213 201.222 80.525 ;
     RECT  21.132 80.237 21.654 80.779 ;
     RECT  22.5 80.525 198.45 80.779 ;
     RECT  17.532 80.237 20.106 80.789 ;
     RECT  21.132 80.779 198.45 80.897 ;
     RECT  13.215 64.859 13.497 80.905 ;
     RECT  2.268 79.681 8.097 80.941 ;
     RECT  1.152 80.923 1.17 80.969 ;
     RECT  10.764 80.671 10.782 81.059 ;
     RECT  14.796 80.941 14.814 81.059 ;
     RECT  12.564 80.905 13.497 81.131 ;
     RECT  21.132 80.897 198.378 81.163 ;
     RECT  2.268 80.941 8.478 81.301 ;
     RECT  10.8 81.103 10.818 81.329 ;
     RECT  15.948 81.163 15.966 81.329 ;
     RECT  18.252 80.789 20.106 81.337 ;
     RECT  21.096 81.163 198.378 81.337 ;
     RECT  9.432 81.175 9.45 81.437 ;
     RECT  2.196 81.301 8.478 81.599 ;
     RECT  15.984 81.481 16.002 81.751 ;
     RECT  13.215 81.131 13.497 81.877 ;
     RECT  15.984 81.751 16.542 81.917 ;
     RECT  14.832 81.877 14.85 82.111 ;
     RECT  15.984 81.917 16.002 82.111 ;
     RECT  18.252 81.337 198.378 82.183 ;
     RECT  18.18 82.183 198.378 82.219 ;
     RECT  17.676 82.219 198.378 82.255 ;
     RECT  17.316 82.255 198.378 82.283 ;
     RECT  17.316 82.283 19.926 82.291 ;
     RECT  14.832 82.111 16.002 82.319 ;
     RECT  21.024 82.283 198.378 82.381 ;
     RECT  199.188 80.525 201.222 82.381 ;
     RECT  21.024 82.381 201.222 82.481 ;
     RECT  2.196 81.599 8.298 82.489 ;
     RECT  0.432 81.883 0.45 82.493 ;
     RECT  21.024 82.481 198.45 82.517 ;
     RECT  2.196 82.489 8.694 82.561 ;
     RECT  2.196 82.561 8.838 82.589 ;
     RECT  17.1 82.291 19.926 82.679 ;
     RECT  13.104 81.877 13.497 82.688 ;
     RECT  17.1 82.679 19.782 82.733 ;
     RECT  18.504 82.733 19.782 82.751 ;
     RECT  14.832 82.319 14.886 82.787 ;
     RECT  14.832 82.787 14.85 82.829 ;
     RECT  8.82 82.589 8.838 82.831 ;
     RECT  17.1 82.733 17.694 82.859 ;
     RECT  21.024 82.517 198.378 82.859 ;
     RECT  2.196 82.589 8.097 82.949 ;
     RECT  10.8 82.831 10.818 82.949 ;
     RECT  8.82 82.831 8.874 83.057 ;
     RECT  21.096 82.859 198.378 83.219 ;
     RECT  18.504 82.751 19.746 83.291 ;
     RECT  2.268 82.949 8.097 83.335 ;
     RECT  21.096 83.219 197.802 83.641 ;
     RECT  0.108 82.525 0.198 83.707 ;
     RECT  20.592 83.641 197.802 83.755 ;
     RECT  199.188 82.481 201.222 83.767 ;
     RECT  20.52 83.755 197.802 83.839 ;
     RECT  17.1 82.859 17.55 83.851 ;
     RECT  18.504 83.291 19.638 83.851 ;
     RECT  14.256 83.767 14.274 83.899 ;
     RECT  14.256 83.899 14.85 83.903 ;
     RECT  17.1 83.851 19.638 83.939 ;
     RECT  20.484 83.839 197.802 84.001 ;
     RECT  198.936 83.767 201.222 84.001 ;
     RECT  9.396 83.875 9.414 84.029 ;
     RECT  17.172 83.939 19.638 84.029 ;
     RECT  2.268 83.335 8.442 84.037 ;
     RECT  17.172 84.029 17.694 84.065 ;
     RECT  2.268 84.037 8.478 84.073 ;
     RECT  14.832 83.903 14.85 84.077 ;
     RECT  20.484 84.001 201.222 84.109 ;
     RECT  18.615 84.029 19.638 84.139 ;
     RECT  20.448 84.109 201.222 84.139 ;
     RECT  1.764 84.073 8.478 84.145 ;
     RECT  9.432 84.109 9.45 84.209 ;
     RECT  12.06 84.181 12.078 84.299 ;
     RECT  1.764 84.145 8.658 84.371 ;
     RECT  0.108 83.707 0.414 84.461 ;
     RECT  15.984 82.319 16.002 84.479 ;
     RECT  0.144 84.461 0.414 84.685 ;
     RECT  17.676 84.065 17.694 84.749 ;
     RECT  0.144 84.685 0.558 85.003 ;
     RECT  1.764 84.371 8.478 85.003 ;
     RECT  0.144 85.003 8.478 85.099 ;
     RECT  18.615 84.139 201.222 85.099 ;
     RECT  18 85.099 201.222 85.109 ;
     RECT  0.144 85.099 9.126 85.145 ;
     RECT  14.868 84.847 14.886 85.147 ;
     RECT  10.8 84.991 10.818 85.153 ;
     RECT  0.144 85.145 8.622 85.189 ;
     RECT  10.8 85.153 10.854 85.189 ;
     RECT  0.108 85.189 8.622 85.229 ;
     RECT  13.215 82.688 13.497 85.243 ;
     RECT  14.832 85.147 14.958 85.261 ;
     RECT  14.436 85.261 14.958 85.277 ;
     RECT  10.728 85.189 10.854 85.289 ;
     RECT  13.104 85.243 13.497 85.289 ;
     RECT  0.144 85.229 8.622 85.373 ;
     RECT  18 85.109 21.078 85.379 ;
     RECT  14.436 85.277 14.85 85.415 ;
     RECT  0.18 85.373 8.622 85.469 ;
     RECT  0.18 85.469 8.478 85.523 ;
     RECT  18.216 85.379 21.078 85.649 ;
     RECT  17.1 85.627 17.118 85.757 ;
     RECT  18.216 85.649 20.178 85.757 ;
     RECT  10.8 85.289 10.818 85.793 ;
     RECT  0.216 85.523 8.478 85.829 ;
     RECT  20.988 85.649 21.078 85.829 ;
     RECT  22.14 85.109 201.222 85.829 ;
     RECT  0.216 85.829 8.334 85.919 ;
     RECT  13.14 85.289 13.497 85.919 ;
     RECT  21.024 85.829 21.078 85.997 ;
     RECT  14.832 85.415 14.85 86.059 ;
     RECT  22.14 85.829 197.766 86.059 ;
     RECT  0.216 85.919 8.298 86.189 ;
     RECT  2.304 86.189 8.298 86.225 ;
     RECT  14.832 86.059 14.994 86.237 ;
     RECT  0.216 86.189 1.17 86.251 ;
     RECT  22.104 86.059 197.766 86.251 ;
     RECT  10.836 86.035 10.854 86.269 ;
     RECT  14.832 86.237 14.958 86.297 ;
     RECT  9.396 86.269 9.414 86.341 ;
     RECT  0.144 86.251 1.17 86.347 ;
     RECT  18.216 85.757 19.926 86.369 ;
     RECT  13.215 85.919 13.497 86.431 ;
     RECT  9.072 86.341 9.414 86.459 ;
     RECT  10.836 86.269 10.962 86.459 ;
     RECT  0.108 86.347 1.17 86.495 ;
     RECT  10.836 86.459 10.89 86.531 ;
     RECT  0.108 86.495 0.558 86.573 ;
     RECT  9.072 86.459 9.342 86.573 ;
     RECT  21.636 86.251 197.766 86.701 ;
     RECT  198.936 85.829 201.222 86.701 ;
     RECT  13.215 86.431 13.518 86.728 ;
     RECT  14.832 86.297 14.85 86.728 ;
     RECT  18.615 86.369 19.926 86.731 ;
     RECT  13.215 86.728 14.85 86.765 ;
     RECT  2.34 86.225 8.298 86.881 ;
     RECT  9.072 86.573 9.126 86.881 ;
     RECT  21.636 86.701 201.222 86.923 ;
     RECT  0.108 86.573 0.414 86.957 ;
     RECT  2.34 86.881 9.126 86.999 ;
     RECT  21.6 86.923 201.222 87.019 ;
     RECT  9.072 86.999 9.126 87.071 ;
     RECT  21.564 87.019 201.222 87.245 ;
     RECT  2.34 86.999 8.298 87.259 ;
     RECT  10.872 86.531 10.89 87.277 ;
     RECT  14.22 86.765 14.85 87.349 ;
     RECT  9.108 87.071 9.126 87.421 ;
     RECT  10.836 87.277 10.926 87.421 ;
     RECT  17.1 86.809 17.118 87.421 ;
     RECT  14.22 87.349 14.994 87.449 ;
     RECT  10.8 87.421 10.926 87.539 ;
     RECT  18.615 86.731 20.538 87.583 ;
     RECT  18.54 87.583 20.538 87.629 ;
     RECT  14.22 87.449 14.922 87.683 ;
     RECT  10.8 87.539 10.854 87.719 ;
     RECT  18.612 87.629 20.538 87.719 ;
     RECT  0.108 86.957 0.198 87.739 ;
     RECT  2.304 87.259 8.298 87.835 ;
     RECT  9.108 87.421 9.162 87.835 ;
     RECT  14.22 87.683 14.85 87.881 ;
     RECT  20.484 87.719 20.538 87.889 ;
     RECT  16.524 87.421 17.19 87.989 ;
     RECT  20.484 87.889 20.61 88.079 ;
     RECT  2.304 87.835 9.162 88.123 ;
     RECT  21.564 87.245 198.45 88.171 ;
     RECT  2.268 88.123 9.162 88.231 ;
     RECT  14.832 87.881 14.85 88.253 ;
     RECT  21.024 88.171 198.45 88.321 ;
     RECT  199.188 87.245 201.222 88.321 ;
     RECT  2.268 88.231 9.27 88.349 ;
     RECT  0.108 87.739 0.414 88.397 ;
     RECT  1.152 87.691 1.17 88.457 ;
     RECT  17.676 88.321 17.694 88.459 ;
     RECT  18.612 87.719 19.746 88.459 ;
     RECT  10.836 87.719 10.854 88.501 ;
     RECT  17.676 88.459 19.746 88.529 ;
     RECT  13.215 86.765 13.497 88.591 ;
     RECT  16.524 87.989 16.83 88.591 ;
     RECT  16.128 88.591 16.83 88.619 ;
     RECT  17.748 88.529 19.746 88.619 ;
     RECT  13.104 88.591 13.497 88.637 ;
     RECT  16.128 88.619 16.722 88.637 ;
     RECT  16.128 88.637 16.542 88.685 ;
     RECT  17.748 88.619 19.206 88.691 ;
     RECT  18.504 88.691 19.206 88.799 ;
     RECT  2.268 88.349 8.802 88.877 ;
     RECT  21.024 88.321 201.222 88.889 ;
     RECT  9.612 88.891 9.63 88.931 ;
     RECT  10.764 88.501 10.854 89.041 ;
     RECT  0.108 88.397 0.306 89.069 ;
     RECT  0.216 89.069 0.306 89.131 ;
     RECT  10.764 89.041 10.89 89.159 ;
     RECT  0.216 89.131 0.342 89.261 ;
     RECT  0.216 89.261 0.234 89.303 ;
     RECT  2.304 88.877 8.802 89.311 ;
     RECT  19.944 89.041 19.962 89.419 ;
     RECT  21.024 88.889 197.766 89.419 ;
     RECT  19.944 89.419 197.766 89.465 ;
     RECT  198.936 88.889 201.222 89.549 ;
     RECT  13.215 88.637 13.497 89.563 ;
     RECT  2.304 89.311 9.234 89.609 ;
     RECT  13.104 89.563 13.497 89.609 ;
     RECT  17.676 89.563 17.694 89.671 ;
     RECT  18.615 88.799 19.206 89.671 ;
     RECT  20.016 89.465 197.766 89.743 ;
     RECT  9.576 89.707 9.594 89.744 ;
     RECT  17.676 89.671 19.206 89.851 ;
     RECT  20.016 89.743 198.45 89.879 ;
     RECT  10.656 89.275 10.674 89.947 ;
     RECT  16.524 88.685 16.542 89.969 ;
     RECT  17.568 89.851 19.206 89.969 ;
     RECT  18.252 89.969 19.206 90.029 ;
     RECT  10.584 89.947 10.674 90.043 ;
     RECT  10.584 90.043 10.71 90.049 ;
     RECT  10.512 90.049 10.71 90.085 ;
     RECT  14.832 89.815 14.85 90.091 ;
     RECT  20.016 89.879 198.378 90.113 ;
     RECT  2.304 89.609 8.802 90.121 ;
     RECT  10.152 90.085 10.71 90.125 ;
     RECT  20.016 90.113 20.502 90.149 ;
     RECT  2.268 90.121 8.802 90.221 ;
     RECT  10.152 90.125 10.17 90.239 ;
     RECT  18.615 90.029 19.206 90.247 ;
     RECT  20.016 90.149 20.07 90.247 ;
     RECT  14.832 90.091 14.922 90.283 ;
     RECT  14.76 90.283 14.922 90.32 ;
     RECT  21.6 90.113 198.378 90.347 ;
     RECT  2.304 90.221 8.802 90.355 ;
     RECT  10.944 90.283 10.962 90.413 ;
     RECT  0.54 90.187 0.558 90.427 ;
     RECT  2.304 90.355 9.162 90.481 ;
     RECT  16.488 90.391 16.506 90.509 ;
     RECT  13.215 89.609 13.497 90.553 ;
     RECT  2.304 90.481 9.234 90.557 ;
     RECT  0.468 90.427 0.558 90.571 ;
     RECT  18.615 90.247 20.07 90.605 ;
     RECT  18.615 90.605 19.962 90.617 ;
     RECT  0.108 90.571 0.558 90.923 ;
     RECT  0.108 90.923 0.378 90.989 ;
     RECT  22.212 90.347 198.378 91.049 ;
     RECT  199.188 89.549 201.222 91.049 ;
     RECT  22.896 91.049 198.378 91.057 ;
     RECT  21.06 91.051 21.078 91.147 ;
     RECT  14.832 90.32 14.922 91.157 ;
     RECT  9.216 90.557 9.234 91.201 ;
     RECT  17.64 90.811 17.658 91.229 ;
     RECT  2.304 90.557 8.478 91.291 ;
     RECT  9.216 91.201 9.378 91.291 ;
     RECT  13.104 90.553 13.497 91.328 ;
     RECT  1.152 91.201 1.17 91.355 ;
     RECT  18.615 90.617 19.71 91.355 ;
     RECT  10.8 91.291 10.818 91.421 ;
     RECT  2.304 91.291 9.378 91.471 ;
     RECT  2.304 91.471 9.666 91.483 ;
     RECT  18.615 91.355 19.206 91.579 ;
     RECT  18.576 91.579 19.206 91.627 ;
     RECT  22.896 91.057 198.45 91.633 ;
     RECT  199.188 91.049 200.106 91.633 ;
     RECT  0.108 90.989 0.342 91.661 ;
     RECT  12.06 89.977 12.078 91.697 ;
     RECT  21.06 91.147 21.654 91.819 ;
     RECT  22.896 91.633 200.106 91.819 ;
     RECT  21.06 91.819 200.106 91.903 ;
     RECT  1.692 91.483 9.666 92.011 ;
     RECT  21.06 91.903 200.142 92.039 ;
     RECT  1.692 92.011 9.738 92.203 ;
     RECT  19.944 91.831 19.962 92.203 ;
     RECT  21.06 92.039 199.962 92.203 ;
     RECT  0.108 91.661 0.126 92.237 ;
     RECT  18.216 91.627 19.206 92.299 ;
     RECT  19.944 92.203 199.962 92.299 ;
     RECT  18.216 92.299 199.962 92.354 ;
     RECT  10.908 91.867 10.926 92.407 ;
     RECT  1.296 92.203 9.738 92.507 ;
     RECT  15.372 91.435 15.39 92.507 ;
     RECT  18.216 92.354 198.45 92.515 ;
     RECT  2.268 92.507 9.738 92.551 ;
     RECT  2.268 92.551 10.098 92.669 ;
     RECT  17.892 92.515 198.45 92.669 ;
     RECT  10.836 92.407 10.926 92.677 ;
     RECT  2.268 92.669 9.666 92.849 ;
     RECT  0.54 92.491 0.558 92.971 ;
     RECT  1.296 92.507 1.314 92.971 ;
     RECT  2.268 92.849 8.478 92.975 ;
     RECT  2.268 92.975 8.406 93.011 ;
     RECT  199.188 92.354 199.962 93.019 ;
     RECT  15.552 92.947 15.858 93.047 ;
     RECT  15.552 93.047 15.714 93.119 ;
     RECT  18.216 92.669 198.45 93.119 ;
     RECT  199.188 93.019 200.106 93.119 ;
     RECT  15.552 93.119 15.642 93.209 ;
     RECT  14.472 93.091 14.49 93.217 ;
     RECT  14.472 93.217 14.634 93.253 ;
     RECT  12.276 93.091 12.294 93.281 ;
     RECT  0.54 92.971 1.314 93.307 ;
     RECT  0.144 93.307 1.314 93.317 ;
     RECT  15.552 93.209 15.57 93.317 ;
     RECT  2.304 93.011 8.406 93.341 ;
     RECT  17.1 93.253 17.118 93.353 ;
     RECT  10.836 92.677 11.43 93.361 ;
     RECT  14.472 93.253 14.814 93.361 ;
     RECT  14.436 93.361 14.814 93.389 ;
     RECT  9.216 92.849 9.666 93.479 ;
     RECT  10.836 93.361 11.718 93.631 ;
     RECT  10.8 93.631 11.718 93.749 ;
     RECT  21.636 93.119 198.45 93.785 ;
     RECT  10.836 93.749 11.718 93.893 ;
     RECT  9.216 93.479 9.306 93.901 ;
     RECT  13.215 91.328 13.497 93.901 ;
     RECT  22.212 93.785 198.45 93.928 ;
     RECT  199.188 93.119 199.926 93.928 ;
     RECT  18.216 93.119 20.61 93.929 ;
     RECT  22.212 93.928 199.926 94.019 ;
     RECT  18.615 93.929 20.61 94.055 ;
     RECT  22.212 94.019 197.766 94.061 ;
     RECT  2.304 93.341 8.37 94.063 ;
     RECT  9.144 93.901 9.306 94.063 ;
     RECT  10.836 93.893 11.43 94.127 ;
     RECT  199.188 94.019 199.926 94.135 ;
     RECT  200.88 91.049 201.222 94.135 ;
     RECT  17.064 94.027 17.082 94.171 ;
     RECT  22.212 94.061 197.73 94.199 ;
     RECT  13.032 93.901 13.497 94.261 ;
     RECT  14.436 93.389 14.454 94.261 ;
     RECT  0.144 93.317 0.846 94.315 ;
     RECT  199.188 94.135 201.222 94.325 ;
     RECT  18.615 94.055 20.502 94.397 ;
     RECT  0.108 94.315 0.846 94.433 ;
     RECT  13.032 94.261 14.454 94.433 ;
     RECT  2.304 94.063 9.306 94.441 ;
     RECT  2.304 94.441 9.342 94.459 ;
     RECT  17.064 94.171 17.118 94.469 ;
     RECT  2.304 94.459 9.45 94.559 ;
     RECT  202.176 74.759 202.497 94.559 ;
     RECT  10.836 94.127 10.854 94.631 ;
     RECT  13.215 94.433 14.454 94.739 ;
     RECT  10.764 94.711 10.782 94.873 ;
     RECT  22.752 94.199 197.73 94.901 ;
     RECT  10.008 94.873 10.782 94.973 ;
     RECT  2.304 94.559 8.91 95.009 ;
     RECT  17.064 94.469 17.082 95.009 ;
     RECT  22.896 94.901 197.73 95.071 ;
     RECT  10.008 94.973 10.242 95.099 ;
     RECT  20.448 94.397 20.502 95.099 ;
     RECT  199.188 94.325 200.034 95.099 ;
     RECT  10.08 95.099 10.242 95.165 ;
     RECT  0.144 94.433 0.846 95.17 ;
     RECT  18.615 94.397 19.206 95.243 ;
     RECT  14.436 94.739 14.454 95.251 ;
     RECT  10.224 95.165 10.242 95.279 ;
     RECT  20.484 95.099 20.502 95.279 ;
     RECT  2.304 95.009 8.298 95.369 ;
     RECT  14.436 95.251 14.994 95.369 ;
     RECT  13.215 94.739 13.497 95.881 ;
     RECT  14.256 95.521 14.274 95.881 ;
     RECT  0.108 95.17 0.846 95.947 ;
     RECT  0.108 95.947 1.17 95.981 ;
     RECT  2.304 95.369 8.154 96.485 ;
     RECT  0.144 95.981 1.17 96.827 ;
     RECT  2.34 96.485 8.154 96.871 ;
     RECT  0.144 96.827 0.162 97.025 ;
     RECT  2.34 96.871 8.226 97.483 ;
     RECT  2.304 97.483 8.226 97.565 ;
     RECT  2.34 97.565 8.226 97.799 ;
     RECT  13.215 95.881 14.274 98.339 ;
     RECT  1.152 96.827 1.17 98.375 ;
     RECT  2.34 97.799 6.75 98.635 ;
     RECT  2.34 98.635 6.822 98.725 ;
     RECT  2.304 98.725 6.822 98.879 ;
     RECT  2.304 98.879 6.75 99.149 ;
     RECT  2.304 99.149 5.418 99.455 ;
     RECT  2.376 99.455 5.418 99.599 ;
     RECT  2.415 99.599 5.418 99.725 ;
     RECT  2.415 99.725 4.446 99.995 ;
     RECT  2.415 99.995 2.97 100.067 ;
     RECT  3.744 99.995 4.446 100.103 ;
     RECT  199.188 95.099 199.854 101.461 ;
     RECT  22.896 95.071 198.054 103.711 ;
     RECT  199.188 101.461 199.926 103.711 ;
     RECT  22.896 103.711 199.926 103.739 ;
     RECT  22.896 103.739 199.854 105.061 ;
     RECT  200.88 94.325 201.222 105.089 ;
     RECT  22.896 105.061 199.89 105.101 ;
     RECT  201.204 105.089 201.222 105.629 ;
     RECT  22.896 105.101 199.854 107.755 ;
     RECT  22.896 107.755 199.89 108.283 ;
     RECT  22.896 108.283 199.926 108.329 ;
     RECT  4.428 100.103 4.446 109.291 ;
     RECT  5.4 99.725 5.418 109.319 ;
     RECT  3.744 109.291 4.446 109.445 ;
     RECT  22.896 108.329 199.89 110.569 ;
     RECT  22.896 110.569 199.926 111.839 ;
     RECT  22.896 111.839 199.89 113.431 ;
     RECT  22.896 113.431 199.926 114.269 ;
     RECT  22.896 114.269 199.89 115.159 ;
     RECT  22.896 115.159 199.962 115.619 ;
     RECT  22.896 115.619 199.854 124.488 ;
     RECT  7.632 97.799 8.226 125.141 ;
     RECT  6.156 99.149 6.75 126.257 ;
     RECT  198.036 124.488 199.854 126.257 ;
     RECT  3.888 109.445 4.446 126.293 ;
     RECT  70.812 126.229 70.83 126.535 ;
     RECT  4.428 126.293 4.446 126.563 ;
     RECT  72 126.535 72.018 126.571 ;
     RECT  198.036 126.257 199.818 126.599 ;
     RECT  67.32 126.229 67.338 126.613 ;
     RECT  64.98 126.265 64.998 126.689 ;
     RECT  69.696 124.488 69.714 126.689 ;
     RECT  70.812 126.535 70.902 126.689 ;
     RECT  72 126.571 72.054 126.689 ;
     RECT  72.036 126.689 72.054 126.697 ;
     RECT  72.807 126.613 72.897 126.697 ;
     RECT  72.036 126.697 72.897 126.761 ;
     RECT  67.32 126.613 67.497 126.805 ;
     RECT  72.108 126.761 72.897 126.833 ;
     RECT  66.708 126.805 67.497 126.869 ;
     RECT  24.207 126.613 24.297 126.883 ;
     RECT  29.607 126.613 29.697 126.883 ;
     RECT  35.007 126.613 35.097 126.883 ;
     RECT  40.407 126.613 40.497 126.883 ;
     RECT  45.807 126.613 45.897 126.883 ;
     RECT  51.207 126.613 51.297 126.883 ;
     RECT  56.607 126.613 56.697 126.883 ;
     RECT  62.007 126.613 62.097 126.883 ;
     RECT  78.207 126.613 78.297 126.883 ;
     RECT  83.607 126.613 83.697 126.883 ;
     RECT  89.007 126.613 89.097 126.883 ;
     RECT  94.407 126.613 94.497 126.883 ;
     RECT  99.807 126.613 99.897 126.883 ;
     RECT  105.207 126.613 105.297 126.883 ;
     RECT  110.607 126.613 110.697 126.883 ;
     RECT  116.007 126.613 116.097 126.883 ;
     RECT  121.407 126.613 121.497 126.883 ;
     RECT  126.807 126.613 126.897 126.883 ;
     RECT  132.207 126.613 132.297 126.883 ;
     RECT  137.607 126.613 137.697 126.883 ;
     RECT  143.007 126.613 143.097 126.883 ;
     RECT  148.407 126.613 148.497 126.883 ;
     RECT  153.807 126.613 153.897 126.883 ;
     RECT  159.207 126.613 159.297 126.883 ;
     RECT  164.607 126.613 164.697 126.883 ;
     RECT  170.007 126.613 170.097 126.883 ;
     RECT  175.407 126.613 175.497 126.883 ;
     RECT  180.807 126.613 180.897 126.883 ;
     RECT  186.207 126.613 186.297 126.883 ;
     RECT  191.607 126.613 191.697 126.883 ;
     RECT  197.007 126.613 197.097 126.883 ;
     RECT  198.072 126.599 199.818 126.959 ;
     RECT  198.072 126.959 198.702 127.409 ;
     RECT  76.968 127.381 76.986 127.499 ;
     RECT  199.656 126.959 199.818 127.499 ;
     RECT  74.736 127.507 74.754 127.679 ;
     RECT  19.836 127.201 19.854 128.309 ;
     RECT  13.215 98.339 13.95 128.345 ;
     RECT  81.072 127.075 81.09 128.579 ;
     RECT  6.336 126.257 6.75 128.615 ;
     RECT  198.648 127.409 198.702 128.849 ;
     RECT  199.656 127.499 199.674 129.119 ;
     RECT  198.684 128.849 198.702 129.659 ;
     RECT  78.015 126.883 78.297 129.811 ;
     RECT  27.756 127.507 27.774 130.469 ;
     RECT  7.815 125.141 8.226 130.505 ;
     RECT  74.556 129.271 74.574 131.549 ;
     RECT  44.244 131.557 44.262 131.597 ;
     RECT  78.015 129.811 78.354 133.169 ;
     RECT  45.615 126.883 45.897 133.195 ;
     RECT  45.615 133.195 45.99 133.241 ;
     RECT  41.364 128.821 41.382 135.329 ;
     RECT  7.815 130.505 8.154 135.365 ;
     RECT  78.015 133.169 78.297 140.971 ;
     RECT  88.815 126.883 89.097 140.971 ;
     RECT  99.615 126.883 99.897 140.971 ;
     RECT  77.904 140.971 78.297 141.008 ;
     RECT  88.704 140.971 89.097 141.008 ;
     RECT  99.504 140.971 99.897 141.008 ;
     RECT  6.336 128.615 6.354 141.035 ;
     RECT  105.015 126.883 105.297 141.067 ;
     RECT  74.628 140.971 74.646 141.101 ;
     RECT  102.6 140.971 102.618 141.101 ;
     RECT  71.064 141.067 71.082 141.179 ;
     RECT  105.015 141.067 105.822 141.269 ;
     RECT  106.92 141.241 106.938 141.293 ;
     RECT  2.415 100.067 2.697 174.707 ;
     RECT  7.815 135.365 8.097 174.707 ;
     RECT  13.215 128.345 13.497 174.707 ;
     RECT  18.615 95.243 18.897 174.707 ;
     RECT  24.015 126.883 24.297 174.707 ;
     RECT  29.415 126.883 29.697 174.707 ;
     RECT  34.815 126.883 35.097 174.707 ;
     RECT  40.215 126.883 40.497 174.707 ;
     RECT  45.615 133.241 45.897 174.707 ;
     RECT  51.015 126.883 51.297 174.707 ;
     RECT  56.415 126.883 56.697 174.707 ;
     RECT  61.815 126.883 62.097 174.707 ;
     RECT  67.215 126.869 67.497 174.707 ;
     RECT  72.615 126.833 72.897 174.707 ;
     RECT  78.015 141.008 78.297 174.707 ;
     RECT  83.415 126.883 83.697 174.707 ;
     RECT  88.815 141.008 89.097 174.707 ;
     RECT  94.215 126.883 94.497 174.707 ;
     RECT  99.615 141.008 99.897 174.707 ;
     RECT  105.015 141.269 105.297 174.707 ;
     RECT  110.415 126.883 110.697 174.707 ;
     RECT  115.815 126.883 116.097 174.707 ;
     RECT  121.215 126.883 121.497 174.707 ;
     RECT  126.615 126.883 126.897 174.707 ;
     RECT  132.015 126.883 132.297 174.707 ;
     RECT  137.415 126.883 137.697 174.707 ;
     RECT  142.815 126.883 143.097 174.707 ;
     RECT  148.215 126.883 148.497 174.707 ;
     RECT  153.615 126.883 153.897 174.707 ;
     RECT  159.015 126.883 159.297 174.707 ;
     RECT  164.415 126.883 164.697 174.707 ;
     RECT  169.815 126.883 170.097 174.707 ;
     RECT  175.215 126.883 175.497 174.707 ;
     RECT  180.615 126.883 180.897 174.707 ;
     RECT  186.015 126.883 186.297 174.707 ;
     RECT  191.415 126.883 191.697 174.707 ;
     RECT  196.815 126.883 197.097 174.707 ;
     RECT  202.215 94.559 202.497 174.707 ;
     RECT  207.615 76.649 207.897 174.707 ;
     RECT  213.015 77.855 213.297 174.707 ;
     RECT  2.415 174.707 2.505 174.977 ;
     RECT  7.815 174.707 7.905 174.977 ;
     RECT  13.215 174.707 13.305 174.977 ;
     RECT  18.615 174.707 18.705 174.977 ;
     RECT  24.015 174.707 24.105 174.977 ;
     RECT  29.415 174.707 29.505 174.977 ;
     RECT  34.815 174.707 34.905 174.977 ;
     RECT  40.215 174.707 40.305 174.977 ;
     RECT  45.615 174.707 45.705 174.977 ;
     RECT  51.015 174.707 51.105 174.977 ;
     RECT  56.415 174.707 56.505 174.977 ;
     RECT  61.815 174.707 61.905 174.977 ;
     RECT  67.215 174.707 67.305 174.977 ;
     RECT  72.615 174.707 72.705 174.977 ;
     RECT  78.015 174.707 78.105 174.977 ;
     RECT  83.415 174.707 83.505 174.977 ;
     RECT  88.815 174.707 88.905 174.977 ;
     RECT  94.215 174.707 94.305 174.977 ;
     RECT  99.615 174.707 99.705 174.977 ;
     RECT  105.015 174.707 105.105 174.977 ;
     RECT  110.415 174.707 110.505 174.977 ;
     RECT  115.815 174.707 115.905 174.977 ;
     RECT  121.215 174.707 121.305 174.977 ;
     RECT  126.615 174.707 126.705 174.977 ;
     RECT  132.015 174.707 132.105 174.977 ;
     RECT  137.415 174.707 137.505 174.977 ;
     RECT  142.815 174.707 142.905 174.977 ;
     RECT  148.215 174.707 148.305 174.977 ;
     RECT  153.615 174.707 153.705 174.977 ;
     RECT  159.015 174.707 159.105 174.977 ;
     RECT  164.415 174.707 164.505 174.977 ;
     RECT  169.815 174.707 169.905 174.977 ;
     RECT  175.215 174.707 175.305 174.977 ;
     RECT  180.615 174.707 180.705 174.977 ;
     RECT  186.015 174.707 186.105 174.977 ;
     RECT  191.415 174.707 191.505 174.977 ;
     RECT  196.815 174.707 196.905 174.977 ;
     RECT  202.215 174.707 202.305 174.977 ;
     RECT  207.615 174.707 207.705 174.977 ;
     RECT  213.015 174.707 213.105 174.977 ;
    LAYER M4 ;
     RECT  0.06 51.984 0.133 64.968 ;
     RECT  0.06 81.168 0.133 96.456 ;
     RECT  0.133 51.984 0.181 65.592 ;
     RECT  0.181 79.2 0.229 79.224 ;
     RECT  0.133 80.352 0.229 96.456 ;
     RECT  0.133 99.744 0.229 99.768 ;
     RECT  0.229 79.2 0.277 96.456 ;
     RECT  0.181 98.064 0.277 98.088 ;
     RECT  0.277 97.536 0.325 98.088 ;
     RECT  0.229 99.168 0.325 99.768 ;
     RECT  0.277 78.72 0.373 96.456 ;
     RECT  0.325 97.536 0.805 99.768 ;
     RECT  0.373 78.48 0.853 96.456 ;
     RECT  0.805 97.488 0.853 99.768 ;
     RECT  0.181 51.84 2.293 65.592 ;
     RECT  0.06 47.088 2.408 48.84 ;
     RECT  2.293 51.456 2.408 65.64 ;
     RECT  0.853 78.48 2.408 99.768 ;
     RECT  2.408 2.148 2.512 174.972 ;
     RECT  2.512 2.418 2.704 174.702 ;
     RECT  2.704 47.088 2.881 49.8 ;
     RECT  2.704 78.48 3.017 99.96 ;
     RECT  2.704 51.216 3.521 66.792 ;
     RECT  3.017 78.528 3.683 99.96 ;
     RECT  3.521 51.264 3.961 66.792 ;
     RECT  3.961 51.264 3.971 66.744 ;
     RECT  2.881 47.088 3.985 48.408 ;
     RECT  2.881 49.776 3.985 49.8 ;
     RECT  3.683 78.624 4.259 99.96 ;
     RECT  4.259 78.72 4.307 99.96 ;
     RECT  3.971 51.312 4.547 66.744 ;
     RECT  3.985 47.088 4.645 49.8 ;
     RECT  4.645 46.224 4.693 49.8 ;
     RECT  4.307 78.72 4.745 99.48 ;
     RECT  4.547 51.312 4.817 66.168 ;
     RECT  4.745 78.768 4.817 99.48 ;
     RECT  4.741 44.88 4.837 44.904 ;
     RECT  4.837 44.352 4.849 44.904 ;
     RECT  4.693 46.224 4.849 50.184 ;
     RECT  4.817 78.768 4.961 99.336 ;
     RECT  4.961 79.632 5.033 99.336 ;
     RECT  5.033 79.632 5.058 99.24 ;
     RECT  5.058 79.632 5.141 99.192 ;
     RECT  4.849 44.352 5.413 50.184 ;
     RECT  4.817 51.312 5.459 65.112 ;
     RECT  5.459 51.552 5.501 65.112 ;
     RECT  4.817 66.096 5.645 66.168 ;
     RECT  5.501 51.648 5.897 65.112 ;
     RECT  5.413 44.16 5.929 50.184 ;
     RECT  5.141 79.632 6.083 98.904 ;
     RECT  4.933 43.008 6.181 43.032 ;
     RECT  5.897 51.648 6.257 65.016 ;
     RECT  6.083 80.16 6.275 98.904 ;
     RECT  6.257 54 6.301 65.016 ;
     RECT  6.275 80.16 6.365 98.664 ;
     RECT  6.301 54 6.581 64.728 ;
     RECT  6.581 64.176 6.653 64.728 ;
     RECT  6.365 80.16 6.653 97.608 ;
     RECT  6.653 80.16 6.707 97.56 ;
     RECT  6.257 51.648 7.297 53.016 ;
     RECT  7.093 76.944 7.381 76.968 ;
     RECT  5.929 44.16 7.429 50.328 ;
     RECT  7.297 51.36 7.429 53.016 ;
     RECT  7.429 44.16 7.693 53.016 ;
     RECT  6.581 54 7.693 63.192 ;
     RECT  6.181 43.008 7.808 43.08 ;
     RECT  7.693 44.16 7.808 63.192 ;
     RECT  6.653 64.608 7.808 64.728 ;
     RECT  5.645 66.096 7.808 66.12 ;
     RECT  7.381 76.944 7.808 77.112 ;
     RECT  6.707 80.256 7.808 97.56 ;
     RECT  6.365 98.64 7.808 98.664 ;
     RECT  5.797 131.568 7.808 131.592 ;
     RECT  4.021 133.2 7.808 133.224 ;
     RECT  7.808 2.148 7.912 174.972 ;
     RECT  7.912 2.418 8.104 174.702 ;
     RECT  8.104 59.52 8.291 61.656 ;
     RECT  8.104 55.968 8.381 57.864 ;
     RECT  8.104 63.072 8.381 63.24 ;
     RECT  8.104 3.936 8.849 4.536 ;
     RECT  8.849 4.512 8.956 4.536 ;
     RECT  8.104 64.32 9.241 64.728 ;
     RECT  8.104 5.664 9.425 7.224 ;
     RECT  8.104 92.4 9.461 95.16 ;
     RECT  8.104 9.072 9.529 9.096 ;
     RECT  8.104 44.16 9.565 53.352 ;
     RECT  8.104 54.432 9.565 54.744 ;
     RECT  9.565 44.16 9.641 54.744 ;
     RECT  9.461 92.4 9.683 94.104 ;
     RECT  9.641 44.16 9.713 54.504 ;
     RECT  9.425 7.2 9.733 7.224 ;
     RECT  9.529 8.88 9.733 9.672 ;
     RECT  9.733 7.2 9.779 9.672 ;
     RECT  9.884 0.528 10.021 0.552 ;
     RECT  9.779 7.824 10.028 9.672 ;
     RECT  9.425 5.664 10.037 5.688 ;
     RECT  10.028 7.824 10.069 9.96 ;
     RECT  10.069 7.824 10.073 10.872 ;
     RECT  10.021 0.096 10.109 0.552 ;
     RECT  9.461 95.136 10.109 95.16 ;
     RECT  10.073 9.936 10.115 10.872 ;
     RECT  10.117 0.576 10.213 0.6 ;
     RECT  10.213 0.576 10.217 1.176 ;
     RECT  10.115 10.848 10.433 10.872 ;
     RECT  10.217 1.152 10.505 1.176 ;
     RECT  9.713 44.16 10.649 54.456 ;
     RECT  8.104 77.088 10.789 77.112 ;
     RECT  10.789 76.992 10.829 77.112 ;
     RECT  8.104 81.168 10.829 91.416 ;
     RECT  9.683 92.4 10.901 93.912 ;
     RECT  10.073 7.824 11.045 8.904 ;
     RECT  11.045 7.824 11.077 7.992 ;
     RECT  11.077 7.008 11.257 7.992 ;
     RECT  11.257 6.576 11.513 7.992 ;
     RECT  8.381 55.968 11.869 57.336 ;
     RECT  11.869 55.776 11.905 57.336 ;
     RECT  11.689 9.072 11.985 9.096 ;
     RECT  11.689 5.712 12.017 5.736 ;
     RECT  11.985 9.072 12.035 9.912 ;
     RECT  11.513 7.008 12.121 7.992 ;
     RECT  11.905 55.68 12.409 57.336 ;
     RECT  12.121 7.008 12.504 8.712 ;
     RECT  11.005 4.56 12.517 4.584 ;
     RECT  10.649 44.16 12.805 53.88 ;
     RECT  12.409 55.2 12.805 57.336 ;
     RECT  12.035 9.888 12.956 9.912 ;
     RECT  11.905 11.52 12.956 11.544 ;
     RECT  12.504 6.144 12.997 8.712 ;
     RECT  12.956 9.888 12.997 11.544 ;
     RECT  12.517 4.56 13.208 5.112 ;
     RECT  12.997 6.144 13.208 11.544 ;
     RECT  8.104 43.008 13.208 43.08 ;
     RECT  12.805 44.16 13.208 57.336 ;
     RECT  8.291 60 13.208 61.656 ;
     RECT  8.381 63.216 13.208 63.24 ;
     RECT  9.241 64.32 13.208 65.16 ;
     RECT  10.829 76.992 13.208 77.016 ;
     RECT  10.829 81.168 13.208 91.32 ;
     RECT  10.901 92.4 13.208 93.816 ;
     RECT  8.104 131.568 13.208 131.592 ;
     RECT  8.104 133.2 13.208 133.224 ;
     RECT  13.208 2.148 13.312 174.972 ;
     RECT  13.312 2.418 13.504 174.702 ;
     RECT  13.504 8.544 13.601 9.576 ;
     RECT  13.504 10.704 13.619 11.736 ;
     RECT  13.601 8.544 13.637 9.384 ;
     RECT  13.619 11.52 13.925 11.736 ;
     RECT  13.637 8.544 13.961 9 ;
     RECT  13.504 44.16 14.465 57.336 ;
     RECT  14.465 44.16 14.609 55.32 ;
     RECT  13.961 8.544 14.709 8.904 ;
     RECT  13.504 43.008 14.725 43.08 ;
     RECT  13.504 64.176 14.725 65.16 ;
     RECT  13.504 6.24 14.741 7.32 ;
     RECT  14.465 56.4 14.789 57.336 ;
     RECT  14.757 70.944 14.821 70.968 ;
     RECT  14.741 5.664 14.825 7.32 ;
     RECT  14.713 10.08 14.825 10.104 ;
     RECT  13.504 74.64 14.861 75.384 ;
     RECT  14.821 70.944 14.88 71.112 ;
     RECT  13.504 59.328 15.041 63.096 ;
     RECT  14.725 64.176 15.157 65.928 ;
     RECT  15.157 39.072 15.253 39.096 ;
     RECT  14.789 56.544 15.253 57.336 ;
     RECT  15.253 39.024 15.301 39.096 ;
     RECT  15.157 64.176 15.301 66.84 ;
     RECT  14.857 0.24 15.361 0.264 ;
     RECT  13.504 81.168 15.361 91.32 ;
     RECT  13.504 92.4 15.361 93.912 ;
     RECT  13.504 76.368 15.509 77.016 ;
     RECT  15.301 64.176 15.548 66.888 ;
     RECT  15.205 67.872 15.548 67.896 ;
     RECT  14.825 5.712 15.577 7.32 ;
     RECT  14.609 44.16 15.577 55.272 ;
     RECT  14.725 42.528 15.685 43.08 ;
     RECT  15.577 44.16 15.685 55.32 ;
     RECT  15.361 0.24 15.721 0.648 ;
     RECT  15.649 1.68 15.721 1.704 ;
     RECT  15.721 0.24 15.757 1.704 ;
     RECT  15.325 3.12 15.793 3.432 ;
     RECT  14.709 8.832 15.793 8.904 ;
     RECT  13.925 11.712 15.793 11.736 ;
     RECT  15.509 76.992 15.793 77.016 ;
     RECT  15.793 76.992 15.869 77.496 ;
     RECT  15.253 56.544 15.875 58.152 ;
     RECT  15.793 11.712 15.877 11.832 ;
     RECT  15.757 0.144 15.937 1.704 ;
     RECT  15.001 10.128 15.937 10.152 ;
     RECT  15.685 42.528 15.937 55.32 ;
     RECT  15.577 5.712 15.941 7.416 ;
     RECT  15.548 64.176 15.941 67.896 ;
     RECT  15.877 11.712 15.964 12.072 ;
     RECT  15.793 2.88 15.977 3.432 ;
     RECT  15.361 81.168 15.977 93.912 ;
     RECT  15.941 6.24 16.009 7.416 ;
     RECT  15.793 8.448 16.009 8.904 ;
     RECT  16.009 6.24 16.021 8.904 ;
     RECT  15.937 10.128 16.021 10.488 ;
     RECT  15.937 0.096 16.115 1.704 ;
     RECT  16.021 6.24 16.117 10.488 ;
     RECT  15.964 11.712 16.117 11.832 ;
     RECT  15.793 75.408 16.22 75.816 ;
     RECT  16.115 0.144 16.225 1.704 ;
     RECT  15.041 59.328 16.259 60.024 ;
     RECT  15.941 66.336 16.261 67.896 ;
     RECT  15.685 69.312 16.261 69.336 ;
     RECT  16.225 0.144 16.307 2.28 ;
     RECT  15.041 61.632 16.357 63.096 ;
     RECT  15.941 64.176 16.357 65.208 ;
     RECT  16.22 75.168 16.369 75.816 ;
     RECT  15.637 40.128 16.453 40.152 ;
     RECT  16.357 61.632 16.453 65.208 ;
     RECT  15.977 81.312 16.481 93.912 ;
     RECT  16.307 0.192 16.499 2.28 ;
     RECT  16.333 79.2 16.501 79.224 ;
     RECT  15.073 72.528 16.589 72.552 ;
     RECT  16.369 75.12 16.621 75.816 ;
     RECT  16.499 0.192 16.691 1.224 ;
     RECT  15.301 38.544 16.796 39.096 ;
     RECT  15.875 57.072 16.835 58.152 ;
     RECT  15.977 3.408 16.841 3.432 ;
     RECT  15.793 73.872 16.873 73.896 ;
     RECT  16.621 74.928 16.873 75.816 ;
     RECT  16.453 61.344 16.933 65.208 ;
     RECT  16.261 66.336 16.933 69.336 ;
     RECT  16.796 38.544 17.029 39.144 ;
     RECT  16.453 40.128 17.029 40.872 ;
     RECT  15.869 77.088 17.053 77.496 ;
     RECT  16.501 78.672 17.053 79.224 ;
     RECT  16.481 82.704 17.053 93.912 ;
     RECT  16.835 57.888 17.077 58.152 ;
     RECT  16.259 59.328 17.077 59.736 ;
     RECT  16.117 6.24 17.089 11.832 ;
     RECT  17.089 6.144 17.123 11.832 ;
     RECT  16.765 5.088 17.129 5.112 ;
     RECT  17.053 77.088 17.165 79.224 ;
     RECT  16.499 2.256 17.171 2.28 ;
     RECT  17.077 57.888 17.237 59.736 ;
     RECT  16.837 72.816 17.485 72.84 ;
     RECT  16.873 73.872 17.485 75.816 ;
     RECT  17.485 72.816 17.557 75.816 ;
     RECT  16.691 0.24 17.569 1.224 ;
     RECT  17.165 77.088 17.629 78.936 ;
     RECT  17.123 6.144 17.633 11.448 ;
     RECT  14.88 71.088 17.665 71.112 ;
     RECT  17.557 72.384 17.665 75.816 ;
     RECT  17.029 38.544 17.797 40.872 ;
     RECT  17.665 0.096 17.965 0.12 ;
     RECT  17.665 70.848 18.061 75.816 ;
     RECT  17.569 1.152 18.085 1.224 ;
     RECT  17.629 76.944 18.169 78.936 ;
     RECT  17.665 80.064 18.169 80.088 ;
     RECT  18.085 1.152 18.173 1.752 ;
     RECT  18.173 1.2 18.181 1.752 ;
     RECT  17.981 2.88 18.181 2.904 ;
     RECT  18.169 76.944 18.313 80.088 ;
     RECT  16.933 61.344 18.325 69.336 ;
     RECT  18.061 70.32 18.325 75.816 ;
     RECT  17.633 6.144 18.385 7.416 ;
     RECT  15.937 42.528 18.421 55.8 ;
     RECT  18.181 1.2 18.425 2.904 ;
     RECT  18.425 1.728 18.608 2.904 ;
     RECT  18.385 6.048 18.608 7.416 ;
     RECT  17.633 8.544 18.608 11.448 ;
     RECT  17.797 38.544 18.608 41.496 ;
     RECT  18.421 42.48 18.608 55.8 ;
     RECT  18.277 56.784 18.608 56.904 ;
     RECT  17.237 57.888 18.608 58.2 ;
     RECT  17.237 59.328 18.608 59.736 ;
     RECT  18.325 61.344 18.608 75.816 ;
     RECT  18.313 76.8 18.608 80.088 ;
     RECT  16.481 81.312 18.608 81.624 ;
     RECT  17.053 82.704 18.608 94.056 ;
     RECT  13.504 131.568 18.608 131.592 ;
     RECT  13.504 133.2 18.608 133.224 ;
     RECT  18.608 1.728 18.712 174.972 ;
     RECT  18.712 1.728 18.904 174.702 ;
     RECT  18.904 82.752 18.965 94.056 ;
     RECT  18.904 5.568 19.043 9 ;
     RECT  19.043 6.432 19.091 9 ;
     RECT  18.904 1.728 19.145 3.576 ;
     RECT  18.904 10.176 19.325 11.448 ;
     RECT  19.091 6.576 19.361 9 ;
     RECT  18.904 42.48 19.427 76.68 ;
     RECT  18.904 77.952 19.685 81.048 ;
     RECT  19.361 6.576 19.757 8.856 ;
     RECT  18.965 82.8 19.757 94.056 ;
     RECT  19.145 1.776 19.897 3.576 ;
     RECT  19.685 77.952 19.933 80.232 ;
     RECT  19.897 1.776 19.937 3.96 ;
     RECT  19.757 83.184 19.973 94.056 ;
     RECT  19.325 10.176 20.005 10.968 ;
     RECT  19.957 5.376 20.045 5.4 ;
     RECT  19.937 3.552 20.189 3.96 ;
     RECT  19.937 1.776 20.225 2.568 ;
     RECT  19.757 6.576 20.245 8.568 ;
     RECT  20.189 3.696 20.261 3.96 ;
     RECT  20.245 6.24 20.291 8.568 ;
     RECT  19.973 84.96 20.437 94.056 ;
     RECT  19.427 58.032 20.509 76.68 ;
     RECT  19.933 77.904 20.509 80.232 ;
     RECT  20.291 7.44 20.513 8.568 ;
     RECT  20.225 1.776 20.549 2.376 ;
     RECT  19.427 42.48 20.689 57.048 ;
     RECT  20.509 58.032 20.689 80.232 ;
     RECT  20.005 10.032 20.729 10.968 ;
     RECT  20.549 1.968 20.801 1.992 ;
     RECT  20.513 8.544 20.941 8.568 ;
     RECT  20.729 10.032 20.941 10.056 ;
     RECT  18.904 37.872 21.013 41.496 ;
     RECT  20.689 42.48 21.013 80.232 ;
     RECT  20.473 81.456 21.013 81.48 ;
     RECT  19.973 83.184 21.013 83.88 ;
     RECT  20.437 84.96 21.013 94.536 ;
     RECT  21.013 37.872 21.085 80.232 ;
     RECT  21.013 81.456 21.085 82.152 ;
     RECT  21.013 83.184 21.085 94.536 ;
     RECT  20.513 7.44 21.377 7.512 ;
     RECT  20.261 3.696 21.409 3.72 ;
     RECT  21.377 7.44 21.485 7.464 ;
     RECT  20.291 6.24 21.589 6.264 ;
     RECT  21.409 3.696 21.809 4.68 ;
     RECT  20.941 8.544 21.953 10.056 ;
     RECT  21.953 9.696 22.097 10.056 ;
     RECT  22.097 9.696 22.115 9.72 ;
     RECT  21.809 3.696 22.133 4.584 ;
     RECT  21.589 6.24 22.205 7.224 ;
     RECT  22.205 6.24 22.457 6.936 ;
     RECT  22.457 6.912 22.601 6.936 ;
     RECT  21.953 8.544 22.637 8.568 ;
     RECT  22.133 3.984 22.781 4.584 ;
     RECT  21.085 37.872 22.968 94.536 ;
     RECT  22.781 4.56 24.008 4.584 ;
     RECT  22.968 37.872 24.008 124.488 ;
     RECT  18.904 131.568 24.008 131.592 ;
     RECT  18.904 133.2 24.008 133.224 ;
     RECT  24.008 2.148 24.112 124.488 ;
     RECT  24.008 126.888 24.112 174.972 ;
     RECT  24.112 126.888 24.2 174.702 ;
     RECT  24.112 2.418 24.304 124.488 ;
     RECT  24.2 126.618 24.304 174.702 ;
     RECT  24.304 37.872 29.408 124.488 ;
     RECT  24.304 131.568 29.408 131.592 ;
     RECT  24.304 133.2 29.408 133.224 ;
     RECT  29.408 2.148 29.512 124.488 ;
     RECT  29.408 126.888 29.512 174.972 ;
     RECT  29.512 126.888 29.6 174.702 ;
     RECT  29.512 2.418 29.704 124.488 ;
     RECT  29.6 126.618 29.704 174.702 ;
     RECT  29.704 37.872 34.808 124.488 ;
     RECT  29.704 131.568 34.808 131.592 ;
     RECT  29.704 133.2 34.808 133.224 ;
     RECT  34.808 2.148 34.912 124.488 ;
     RECT  34.808 126.888 34.912 174.972 ;
     RECT  34.912 126.888 35 174.702 ;
     RECT  34.912 2.418 35.104 124.488 ;
     RECT  35 126.618 35.104 174.702 ;
     RECT  35.104 37.872 40.208 124.488 ;
     RECT  35.104 131.568 40.208 131.592 ;
     RECT  35.104 133.2 40.208 133.224 ;
     RECT  40.208 2.148 40.312 124.488 ;
     RECT  40.208 126.888 40.312 174.972 ;
     RECT  40.312 126.888 40.4 174.702 ;
     RECT  40.312 2.418 40.504 124.488 ;
     RECT  40.4 126.618 40.504 174.702 ;
     RECT  40.504 131.568 44.273 131.592 ;
     RECT  40.504 37.872 45.608 124.488 ;
     RECT  40.504 133.2 45.608 133.224 ;
     RECT  45.608 2.148 45.712 124.488 ;
     RECT  45.608 126.888 45.712 174.972 ;
     RECT  45.712 126.888 45.8 174.702 ;
     RECT  45.712 2.418 45.904 124.488 ;
     RECT  45.8 126.618 45.904 174.702 ;
     RECT  45.904 133.2 46.001 133.224 ;
     RECT  45.904 37.872 51.008 124.488 ;
     RECT  51.008 2.148 51.112 124.488 ;
     RECT  51.008 126.888 51.112 174.972 ;
     RECT  51.112 126.888 51.2 174.702 ;
     RECT  51.112 2.418 51.304 124.488 ;
     RECT  51.2 126.618 51.304 174.702 ;
     RECT  51.304 37.872 56.408 124.488 ;
     RECT  56.408 2.148 56.512 124.488 ;
     RECT  56.408 126.888 56.512 174.972 ;
     RECT  56.512 126.888 56.6 174.702 ;
     RECT  56.512 2.418 56.704 124.488 ;
     RECT  56.6 126.618 56.704 174.702 ;
     RECT  56.704 37.872 61.808 124.488 ;
     RECT  61.808 2.148 61.912 124.488 ;
     RECT  61.808 126.888 61.912 174.972 ;
     RECT  61.912 126.888 62 174.702 ;
     RECT  61.912 2.418 62.104 124.488 ;
     RECT  62 126.618 62.104 174.702 ;
     RECT  62.104 37.872 67.208 124.488 ;
     RECT  67.208 2.148 67.312 124.488 ;
     RECT  67.208 126.888 67.312 174.972 ;
     RECT  67.312 126.888 67.4 174.702 ;
     RECT  67.312 2.418 67.504 124.488 ;
     RECT  67.4 126.618 67.504 174.702 ;
     RECT  67.504 37.68 72.608 124.488 ;
     RECT  71.053 141.072 72.608 141.096 ;
     RECT  72.608 2.148 72.712 124.488 ;
     RECT  72.608 126.888 72.712 174.972 ;
     RECT  72.712 126.888 72.8 174.702 ;
     RECT  72.712 2.418 72.904 124.488 ;
     RECT  72.8 126.618 72.904 174.702 ;
     RECT  72.904 141.072 74.617 141.096 ;
     RECT  74.617 140.976 74.657 141.096 ;
     RECT  72.904 37.68 78.008 124.488 ;
     RECT  74.657 140.976 78.008 141 ;
     RECT  78.008 2.148 78.112 124.488 ;
     RECT  78.008 126.888 78.112 174.972 ;
     RECT  78.112 126.888 78.2 174.702 ;
     RECT  78.112 2.418 78.304 124.488 ;
     RECT  78.2 126.618 78.304 174.702 ;
     RECT  78.304 37.68 83.408 124.488 ;
     RECT  78.304 140.976 83.408 141 ;
     RECT  83.408 2.148 83.512 124.488 ;
     RECT  83.408 126.888 83.512 174.972 ;
     RECT  83.512 126.888 83.6 174.702 ;
     RECT  83.512 2.418 83.704 124.488 ;
     RECT  83.6 126.618 83.704 174.702 ;
     RECT  83.704 37.68 88.808 124.488 ;
     RECT  83.704 140.976 88.808 141 ;
     RECT  88.808 2.148 88.912 124.488 ;
     RECT  88.808 126.888 88.912 174.972 ;
     RECT  88.912 126.888 89 174.702 ;
     RECT  88.912 2.418 89.104 124.488 ;
     RECT  89 126.618 89.104 174.702 ;
     RECT  89.104 37.68 94.208 124.488 ;
     RECT  89.104 140.976 94.208 141 ;
     RECT  94.208 2.148 94.312 124.488 ;
     RECT  94.208 126.888 94.312 174.972 ;
     RECT  94.312 126.888 94.4 174.702 ;
     RECT  94.312 2.418 94.504 124.488 ;
     RECT  94.4 126.618 94.504 174.702 ;
     RECT  94.504 37.68 99.608 124.488 ;
     RECT  94.504 140.976 99.608 141 ;
     RECT  99.608 2.148 99.712 124.488 ;
     RECT  99.608 126.888 99.712 174.972 ;
     RECT  99.712 126.888 99.8 174.702 ;
     RECT  99.712 2.418 99.904 124.488 ;
     RECT  99.8 126.618 99.904 174.702 ;
     RECT  99.904 140.976 102.589 141 ;
     RECT  102.589 140.976 102.629 141.096 ;
     RECT  99.904 37.68 105.008 124.488 ;
     RECT  102.629 141.072 105.008 141.096 ;
     RECT  105.008 2.148 105.112 124.488 ;
     RECT  105.008 126.888 105.112 174.972 ;
     RECT  105.112 126.888 105.2 174.702 ;
     RECT  105.112 2.418 105.304 124.488 ;
     RECT  105.2 126.618 105.304 174.702 ;
     RECT  105.304 141.072 105.833 141.096 ;
     RECT  105.304 37.68 110.408 124.488 ;
     RECT  106.909 141.264 110.408 141.288 ;
     RECT  110.408 2.148 110.512 124.488 ;
     RECT  110.408 126.888 110.512 174.972 ;
     RECT  110.512 126.888 110.6 174.702 ;
     RECT  110.512 2.418 110.704 124.488 ;
     RECT  110.6 126.618 110.704 174.702 ;
     RECT  110.704 37.68 115.808 124.488 ;
     RECT  110.704 141.264 115.808 141.288 ;
     RECT  115.808 2.148 115.912 124.488 ;
     RECT  115.808 126.888 115.912 174.972 ;
     RECT  115.912 126.888 116 174.702 ;
     RECT  115.912 2.418 116.104 124.488 ;
     RECT  116 126.618 116.104 174.702 ;
     RECT  116.104 37.68 121.208 124.488 ;
     RECT  116.104 141.264 121.208 141.288 ;
     RECT  121.208 2.148 121.312 124.488 ;
     RECT  121.208 126.888 121.312 174.972 ;
     RECT  121.312 126.888 121.4 174.702 ;
     RECT  121.312 2.418 121.504 124.488 ;
     RECT  121.4 126.618 121.504 174.702 ;
     RECT  121.504 37.68 126.608 124.488 ;
     RECT  121.504 141.264 126.608 141.288 ;
     RECT  126.608 2.148 126.712 124.488 ;
     RECT  126.608 126.888 126.712 174.972 ;
     RECT  126.712 126.888 126.8 174.702 ;
     RECT  126.712 2.418 126.904 124.488 ;
     RECT  126.8 126.618 126.904 174.702 ;
     RECT  126.904 37.68 132.008 124.488 ;
     RECT  126.904 141.264 132.008 141.288 ;
     RECT  132.008 2.148 132.112 124.488 ;
     RECT  132.008 126.888 132.112 174.972 ;
     RECT  132.112 126.888 132.2 174.702 ;
     RECT  132.112 2.418 132.304 124.488 ;
     RECT  132.2 126.618 132.304 174.702 ;
     RECT  132.304 37.68 137.408 124.488 ;
     RECT  132.304 141.264 137.408 141.288 ;
     RECT  137.408 2.148 137.512 124.488 ;
     RECT  137.408 126.888 137.512 174.972 ;
     RECT  137.512 126.888 137.6 174.702 ;
     RECT  137.512 2.418 137.704 124.488 ;
     RECT  137.6 126.618 137.704 174.702 ;
     RECT  137.704 37.68 142.808 124.488 ;
     RECT  137.704 141.264 142.808 141.288 ;
     RECT  142.808 2.148 142.912 124.488 ;
     RECT  142.808 126.888 142.912 174.972 ;
     RECT  142.912 126.888 143 174.702 ;
     RECT  142.912 2.418 143.104 124.488 ;
     RECT  143 126.618 143.104 174.702 ;
     RECT  143.104 37.68 148.208 124.488 ;
     RECT  143.104 141.264 148.208 141.288 ;
     RECT  148.208 2.148 148.312 124.488 ;
     RECT  148.208 126.888 148.312 174.972 ;
     RECT  148.312 126.888 148.4 174.702 ;
     RECT  148.312 2.418 148.504 124.488 ;
     RECT  148.4 126.618 148.504 174.702 ;
     RECT  148.504 37.68 153.608 124.488 ;
     RECT  148.504 141.264 153.608 141.288 ;
     RECT  153.608 2.148 153.712 124.488 ;
     RECT  153.608 126.888 153.712 174.972 ;
     RECT  153.712 126.888 153.8 174.702 ;
     RECT  153.712 2.418 153.904 124.488 ;
     RECT  153.8 126.618 153.904 174.702 ;
     RECT  153.904 37.68 159.008 124.488 ;
     RECT  153.904 141.264 159.008 141.288 ;
     RECT  159.008 2.148 159.112 124.488 ;
     RECT  159.008 126.888 159.112 174.972 ;
     RECT  159.112 126.888 159.2 174.702 ;
     RECT  159.112 2.418 159.304 124.488 ;
     RECT  159.2 126.618 159.304 174.702 ;
     RECT  159.304 37.68 164.408 124.488 ;
     RECT  159.304 141.264 164.408 141.288 ;
     RECT  164.408 2.148 164.512 124.488 ;
     RECT  164.408 126.888 164.512 174.972 ;
     RECT  164.512 126.888 164.6 174.702 ;
     RECT  164.512 2.418 164.704 124.488 ;
     RECT  164.6 126.618 164.704 174.702 ;
     RECT  164.704 37.68 169.808 124.488 ;
     RECT  164.704 141.264 169.808 141.288 ;
     RECT  169.808 2.148 169.912 124.488 ;
     RECT  169.808 126.888 169.912 174.972 ;
     RECT  169.912 126.888 170 174.702 ;
     RECT  169.912 2.418 170.104 124.488 ;
     RECT  170 126.618 170.104 174.702 ;
     RECT  170.104 37.68 175.208 124.488 ;
     RECT  170.104 141.264 175.208 141.288 ;
     RECT  175.208 2.148 175.312 124.488 ;
     RECT  175.208 126.888 175.312 174.972 ;
     RECT  175.312 126.888 175.4 174.702 ;
     RECT  175.312 2.418 175.504 124.488 ;
     RECT  175.4 126.618 175.504 174.702 ;
     RECT  175.504 37.68 180.608 124.488 ;
     RECT  175.504 141.264 180.608 141.288 ;
     RECT  180.608 2.148 180.712 124.488 ;
     RECT  180.608 126.888 180.712 174.972 ;
     RECT  180.712 126.888 180.8 174.702 ;
     RECT  180.712 2.418 180.904 124.488 ;
     RECT  180.8 126.618 180.904 174.702 ;
     RECT  180.904 37.68 186.008 124.488 ;
     RECT  180.904 141.264 186.008 141.288 ;
     RECT  186.008 2.148 186.112 124.488 ;
     RECT  186.008 126.888 186.112 174.972 ;
     RECT  186.112 126.888 186.2 174.702 ;
     RECT  186.112 2.418 186.304 124.488 ;
     RECT  186.2 126.618 186.304 174.702 ;
     RECT  186.304 37.68 191.408 124.488 ;
     RECT  186.304 141.264 191.408 141.288 ;
     RECT  191.408 2.148 191.512 124.488 ;
     RECT  191.408 126.888 191.512 174.972 ;
     RECT  191.512 126.888 191.6 174.702 ;
     RECT  191.512 2.418 191.704 124.488 ;
     RECT  191.6 126.618 191.704 174.702 ;
     RECT  191.704 37.68 196.808 124.488 ;
     RECT  191.704 141.264 196.808 141.288 ;
     RECT  196.808 2.148 196.912 124.488 ;
     RECT  196.808 126.888 196.912 174.972 ;
     RECT  196.912 126.888 197 174.702 ;
     RECT  196.912 2.418 197.104 124.488 ;
     RECT  197 126.618 197.104 174.702 ;
     RECT  197.104 37.68 197.568 124.488 ;
     RECT  197.568 37.68 197.741 94.44 ;
     RECT  197.104 141.264 197.747 141.288 ;
     RECT  197.741 37.68 197.777 71.016 ;
     RECT  197.741 72.048 197.777 94.248 ;
     RECT  197.777 88.272 197.813 90.792 ;
     RECT  197.777 72.336 198.965 74.76 ;
     RECT  197.777 76.368 198.965 87.24 ;
     RECT  198.965 78.192 199.001 86.664 ;
     RECT  197.813 88.368 199.289 90.792 ;
     RECT  197.777 37.68 199.427 69.096 ;
     RECT  199.001 78.672 199.433 85.128 ;
     RECT  198.965 72.336 199.469 73.704 ;
     RECT  199.289 89.04 199.469 90.792 ;
     RECT  199.469 72.336 199.505 73.608 ;
     RECT  198.965 74.736 199.505 74.76 ;
     RECT  198.965 76.944 199.505 76.968 ;
     RECT  199.433 78.768 199.505 85.128 ;
     RECT  199.001 86.64 199.505 86.664 ;
     RECT  199.469 89.04 199.505 90.696 ;
     RECT  197.777 92.88 199.505 94.248 ;
     RECT  199.505 92.88 199.541 92.904 ;
     RECT  199.285 107.76 199.813 107.784 ;
     RECT  199.177 36.48 199.859 36.504 ;
     RECT  199.427 40.128 199.901 69.096 ;
     RECT  199.505 72.336 199.901 72.936 ;
     RECT  197.568 105.072 199.901 105.096 ;
     RECT  199.813 107.76 199.901 108.312 ;
     RECT  199.901 108.288 199.937 108.312 ;
     RECT  199.505 94.224 199.973 94.248 ;
     RECT  199.897 111.744 199.981 111.768 ;
     RECT  199.901 40.128 200.081 68.904 ;
     RECT  199.901 72.336 200.081 72.744 ;
     RECT  200.005 94.656 200.089 94.68 ;
     RECT  200.081 40.128 200.117 67.08 ;
     RECT  200.117 40.128 200.147 66.216 ;
     RECT  199.505 85.104 200.189 85.128 ;
     RECT  199.427 37.68 200.195 38.952 ;
     RECT  200.147 54.864 200.195 66.216 ;
     RECT  200.195 37.68 200.243 38.184 ;
     RECT  200.147 40.128 200.291 53.88 ;
     RECT  200.081 68.112 200.333 68.904 ;
     RECT  200.243 37.68 200.435 38.136 ;
     RECT  200.195 62.064 200.435 66.216 ;
     RECT  200.435 37.728 200.483 38.136 ;
     RECT  200.195 54.864 200.483 60.936 ;
     RECT  200.081 72.72 201.541 72.744 ;
     RECT  201.541 72.72 201.733 73.32 ;
     RECT  200.333 68.4 201.74 68.904 ;
     RECT  201.109 67.248 201.769 67.272 ;
     RECT  201.74 68.4 201.769 69.72 ;
     RECT  201.733 72.048 201.781 73.32 ;
     RECT  201.781 71.472 201.973 73.8 ;
     RECT  200.483 37.728 202.208 37.944 ;
     RECT  200.291 40.128 202.208 40.296 ;
     RECT  200.291 41.472 202.208 53.88 ;
     RECT  200.483 54.864 202.208 60.6 ;
     RECT  200.435 62.16 202.208 66.216 ;
     RECT  201.769 67.248 202.208 69.72 ;
     RECT  201.973 71.28 202.208 73.8 ;
     RECT  202.208 2.148 202.312 174.972 ;
     RECT  202.312 2.418 202.504 174.702 ;
     RECT  202.504 65.664 202.643 65.688 ;
     RECT  202.504 52.752 202.691 57.672 ;
     RECT  202.504 67.68 202.691 68.424 ;
     RECT  202.504 59.856 202.787 61.416 ;
     RECT  202.787 60.576 202.817 61.416 ;
     RECT  202.691 52.752 202.883 53.304 ;
     RECT  202.691 67.68 202.883 67.896 ;
     RECT  202.504 40.128 202.979 40.152 ;
     RECT  202.691 54.72 202.979 57.672 ;
     RECT  202.504 41.472 203.027 51.72 ;
     RECT  203.027 44.976 203.171 51.72 ;
     RECT  202.504 58.704 203.257 58.728 ;
     RECT  203.027 41.472 203.267 43.944 ;
     RECT  202.504 62.4 203.507 63.24 ;
     RECT  202.817 61.104 203.533 61.416 ;
     RECT  203.171 45.216 203.795 51.72 ;
     RECT  203.267 41.472 203.939 43.896 ;
     RECT  203.795 45.216 203.969 46.92 ;
     RECT  203.533 61.104 203.989 61.704 ;
     RECT  203.795 48.192 204.035 51.72 ;
     RECT  203.989 60.432 204.077 61.704 ;
     RECT  203.969 46.896 204.149 46.92 ;
     RECT  203.939 43.248 204.227 43.896 ;
     RECT  204.035 48.384 204.293 51.72 ;
     RECT  203.969 45.216 204.323 45.576 ;
     RECT  204.077 61.008 204.337 61.704 ;
     RECT  204.227 43.872 204.371 43.896 ;
     RECT  202.979 54.72 204.373 55.464 ;
     RECT  204.293 48.384 204.419 51.432 ;
     RECT  204.337 61.104 204.473 61.704 ;
     RECT  204.419 48.384 204.725 48.408 ;
     RECT  202.883 52.752 205.373 52.824 ;
     RECT  203.797 59.136 205.513 59.16 ;
     RECT  204.323 45.216 205.523 45.24 ;
     RECT  205.513 59.088 205.765 59.16 ;
     RECT  205.765 58.992 205.805 59.16 ;
     RECT  205.045 64.944 205.837 64.968 ;
     RECT  202.883 67.872 205.909 67.896 ;
     RECT  205.909 67.872 205.949 68.424 ;
     RECT  203.939 41.472 206.129 42.072 ;
     RECT  202.979 56.496 206.341 57.672 ;
     RECT  205.805 58.992 206.341 59.112 ;
     RECT  202.504 72.72 206.381 74.376 ;
     RECT  204.373 54.048 206.449 55.464 ;
     RECT  205.837 64.56 206.489 64.968 ;
     RECT  206.381 73.344 206.489 74.376 ;
     RECT  206.489 73.344 206.561 73.8 ;
     RECT  206.449 53.904 206.629 55.464 ;
     RECT  206.341 56.496 206.629 59.112 ;
     RECT  205.949 68.4 206.665 68.424 ;
     RECT  206.629 53.904 206.917 59.112 ;
     RECT  204.473 61.104 206.917 61.416 ;
     RECT  203.507 62.976 206.917 63.24 ;
     RECT  206.489 64.56 206.917 64.872 ;
     RECT  206.917 62.976 207.133 64.872 ;
     RECT  206.917 60.576 207.457 61.416 ;
     RECT  207.133 62.544 207.457 64.872 ;
     RECT  207.277 66.096 207.493 66.12 ;
     RECT  206.809 67.152 207.493 67.176 ;
     RECT  206.665 68.4 207.493 68.952 ;
     RECT  206.129 42.048 207.608 42.072 ;
     RECT  204.419 49.488 207.608 51.432 ;
     RECT  205.373 52.8 207.608 52.824 ;
     RECT  206.917 53.904 207.608 59.496 ;
     RECT  207.457 60.576 207.608 64.872 ;
     RECT  207.493 66.096 207.608 68.952 ;
     RECT  207.277 69.984 207.608 70.008 ;
     RECT  206.561 73.536 207.608 73.8 ;
     RECT  206.665 76.224 207.608 76.248 ;
     RECT  207.608 2.148 207.712 174.972 ;
     RECT  207.712 2.418 207.904 174.702 ;
     RECT  207.904 53.904 208.355 63.096 ;
     RECT  207.904 50.736 208.469 51.432 ;
     RECT  208.469 50.832 208.505 51.432 ;
     RECT  208.355 53.904 208.829 62.568 ;
     RECT  207.904 64.176 208.933 65.544 ;
     RECT  207.904 66.72 208.933 67.176 ;
     RECT  207.904 73.776 208.94 74.664 ;
     RECT  208.94 73.776 208.941 74.76 ;
     RECT  208.829 53.904 208.973 61.752 ;
     RECT  208.941 73.776 209.027 75.24 ;
     RECT  207.904 76.224 209.045 76.248 ;
     RECT  207.904 69.984 209.069 70.008 ;
     RECT  209.069 69.552 209.084 70.008 ;
     RECT  209.084 69.552 209.221 70.44 ;
     RECT  209.221 69.504 209.267 70.728 ;
     RECT  209.267 70.704 209.305 70.728 ;
     RECT  208.933 64.176 209.473 67.176 ;
     RECT  208.973 53.904 209.513 57.672 ;
     RECT  209.473 64.176 209.689 67.272 ;
     RECT  207.904 49.488 209.693 49.512 ;
     RECT  209.513 54.768 209.795 57.672 ;
     RECT  209.689 63.504 209.797 67.272 ;
     RECT  209.795 56.976 209.941 57.672 ;
     RECT  208.973 58.8 209.941 61.752 ;
     RECT  209.795 54.768 209.981 55.464 ;
     RECT  209.981 55.056 210.017 55.464 ;
     RECT  209.027 75.216 210.017 75.24 ;
     RECT  209.267 69.504 210.053 69.528 ;
     RECT  209.797 63.072 210.085 67.272 ;
     RECT  209.125 76.368 210.125 76.392 ;
     RECT  209.941 56.976 210.193 61.752 ;
     RECT  210.193 56.976 210.265 61.896 ;
     RECT  210.085 63.072 210.265 67.32 ;
     RECT  209.027 73.776 210.265 73.8 ;
     RECT  210.265 56.976 210.373 67.32 ;
     RECT  208.969 68.352 210.373 68.376 ;
     RECT  210.265 73.68 210.521 73.8 ;
     RECT  210.373 56.976 210.593 68.376 ;
     RECT  210.593 58.32 210.707 68.376 ;
     RECT  210.707 61.008 211.021 68.376 ;
     RECT  210.707 58.704 211.061 59.784 ;
     RECT  210.841 70.272 211.273 70.296 ;
     RECT  210.017 55.152 211.309 55.176 ;
     RECT  210.049 74.832 211.313 74.856 ;
     RECT  210.521 73.728 211.345 73.8 ;
     RECT  208.505 51.168 211.349 51.432 ;
     RECT  211.309 55.104 211.381 55.176 ;
     RECT  211.021 61.008 211.381 68.76 ;
     RECT  211.273 70.032 211.381 70.296 ;
     RECT  211.349 51.408 211.529 51.432 ;
     RECT  210.593 56.976 211.561 57.336 ;
     RECT  211.381 55.104 211.597 55.272 ;
     RECT  211.561 56.448 211.597 57.336 ;
     RECT  211.381 61.008 211.601 70.296 ;
     RECT  211.597 55.104 211.637 57.336 ;
     RECT  211.061 58.704 211.673 59.352 ;
     RECT  211.637 55.104 211.853 56.472 ;
     RECT  211.601 61.008 211.853 64.68 ;
     RECT  211.853 61.056 211.925 64.68 ;
     RECT  211.853 55.248 211.961 56.472 ;
     RECT  211.345 73.728 212.005 74.568 ;
     RECT  211.601 66.096 212.605 70.296 ;
     RECT  211.673 58.8 212.641 59.352 ;
     RECT  211.885 76.368 212.684 76.392 ;
     RECT  212.684 76.032 212.725 76.392 ;
     RECT  212.641 58.8 212.785 60.024 ;
     RECT  212.005 73.488 212.849 74.568 ;
     RECT  212.725 76.032 212.849 77.064 ;
     RECT  212.785 58.8 212.857 60.072 ;
     RECT  211.925 61.056 212.857 64.44 ;
     RECT  212.929 54.144 213.008 54.168 ;
     RECT  211.961 55.248 213.008 55.272 ;
     RECT  211.961 56.448 213.008 56.472 ;
     RECT  212.965 57.648 213.008 57.672 ;
     RECT  212.857 58.8 213.008 64.44 ;
     RECT  212.605 65.952 213.008 70.296 ;
     RECT  212.849 73.488 213.008 77.064 ;
     RECT  213.008 2.148 213.112 174.972 ;
     RECT  213.112 2.418 213.304 174.702 ;
     RECT  213.304 74.112 213.581 74.136 ;
     RECT  213.304 54.144 214.013 54.168 ;
     RECT  213.304 76.224 214.013 77.064 ;
     RECT  213.304 66.528 214.049 72.024 ;
     RECT  213.304 55.584 214.297 56.04 ;
     RECT  213.304 57.072 214.297 65.496 ;
     RECT  214.297 55.584 214.409 65.496 ;
     RECT  214.049 66.768 214.409 72.024 ;
     RECT  214.409 55.632 215.125 65.496 ;
     RECT  215.125 55.632 215.129 65.64 ;
     RECT  215.129 55.68 215.305 65.64 ;
     RECT  214.409 66.768 215.305 71.928 ;
     RECT  215.053 73.008 215.305 73.032 ;
     RECT  215.305 55.68 215.413 71.928 ;
     RECT  215.305 73.008 215.413 73.512 ;
     RECT  215.341 74.832 215.489 74.856 ;
     RECT  214.013 76.224 215.561 76.248 ;
     RECT  215.413 55.68 215.705 73.512 ;
     RECT  215.341 54.576 215.917 54.6 ;
     RECT  215.917 54.336 215.953 54.6 ;
     RECT  215.953 53.856 216.101 54.6 ;
     RECT  216.101 54.336 216.169 54.6 ;
     RECT  215.705 55.68 216.169 73.032 ;
     RECT  216.169 54.336 216.389 73.032 ;
     RECT  216.389 54.672 216.533 73.032 ;
     RECT  216.533 55.92 216.569 73.032 ;
     RECT  216.533 54.672 216.605 54.696 ;
     RECT  216.569 73.008 216.925 73.032 ;
     RECT  216.853 75.504 217.177 75.528 ;
     RECT  216.925 73.008 217.484 73.704 ;
     RECT  217.177 74.928 217.484 75.528 ;
     RECT  217.484 73.008 217.573 75.528 ;
     RECT  216.569 55.92 217.649 71.928 ;
     RECT  217.645 54.672 217.681 54.696 ;
     RECT  217.649 55.92 217.681 69.912 ;
     RECT  217.573 73.008 217.685 75.624 ;
     RECT  217.685 73.68 217.789 75.624 ;
     RECT  217.649 71.52 218.009 71.928 ;
     RECT  217.789 73.68 218.221 76.104 ;
     RECT  218.221 73.68 218.257 76.392 ;
     RECT  217.681 54.672 218.617 69.912 ;
     RECT  218.257 73.68 218.797 76.488 ;
     RECT  218.617 54.672 219.121 69.96 ;
     RECT  218.009 71.904 219.155 71.928 ;
     RECT  219.121 54.672 219.445 70.056 ;
     RECT  219.445 54.48 220.069 70.056 ;
     RECT  220.069 54.48 220.284 70.152 ;
     RECT  218.797 73.68 220.284 76.68 ;
     RECT  220.284 70.128 220.313 70.152 ;
    LAYER M5 ;
     RECT  16.08 0.016 19.08 0.131 ;
     RECT  9.936 0.016 10.248 0.563 ;
     RECT  10.128 0.563 10.248 0.611 ;
     RECT  10.224 0.611 10.248 1.187 ;
     RECT  16.176 0.131 19.08 1.715 ;
     RECT  17.136 1.715 19.08 2.003 ;
     RECT  2.4 2.137 2.52 2.151 ;
     RECT  7.8 2.137 7.92 2.151 ;
     RECT  13.2 2.137 13.32 2.151 ;
     RECT  24 2.137 24.12 2.151 ;
     RECT  29.4 2.137 29.52 2.151 ;
     RECT  34.8 2.137 34.92 2.151 ;
     RECT  40.2 2.137 40.32 2.151 ;
     RECT  45.6 2.137 45.72 2.151 ;
     RECT  51 2.137 51.12 2.151 ;
     RECT  56.4 2.137 56.52 2.151 ;
     RECT  61.8 2.137 61.92 2.151 ;
     RECT  67.2 2.137 67.32 2.151 ;
     RECT  72.6 2.137 72.72 2.151 ;
     RECT  78 2.137 78.12 2.151 ;
     RECT  83.4 2.137 83.52 2.151 ;
     RECT  88.8 2.137 88.92 2.151 ;
     RECT  94.2 2.137 94.32 2.151 ;
     RECT  99.6 2.137 99.72 2.151 ;
     RECT  105 2.137 105.12 2.151 ;
     RECT  110.4 2.137 110.52 2.151 ;
     RECT  115.8 2.137 115.92 2.151 ;
     RECT  121.2 2.137 121.32 2.151 ;
     RECT  126.6 2.137 126.72 2.151 ;
     RECT  132 2.137 132.12 2.151 ;
     RECT  137.4 2.137 137.52 2.151 ;
     RECT  142.8 2.137 142.92 2.151 ;
     RECT  148.2 2.137 148.32 2.151 ;
     RECT  153.6 2.137 153.72 2.151 ;
     RECT  159 2.137 159.12 2.151 ;
     RECT  164.4 2.137 164.52 2.151 ;
     RECT  169.8 2.137 169.92 2.151 ;
     RECT  175.2 2.137 175.32 2.151 ;
     RECT  180.6 2.137 180.72 2.151 ;
     RECT  186 2.137 186.12 2.151 ;
     RECT  191.4 2.137 191.52 2.151 ;
     RECT  196.8 2.137 196.92 2.151 ;
     RECT  202.2 2.137 202.32 2.151 ;
     RECT  207.6 2.137 207.72 2.151 ;
     RECT  213 2.137 213.12 2.151 ;
     RECT  17.136 2.003 18.912 2.291 ;
     RECT  18 2.291 18.912 2.915 ;
     RECT  7.8 2.151 8.112 3.925 ;
     RECT  7.8 3.925 8.568 4.501 ;
     RECT  13.2 2.151 13.512 4.549 ;
     RECT  12.528 4.549 13.512 5.075 ;
     RECT  18.6 2.915 18.912 5.557 ;
     RECT  19.968 5.365 19.992 5.557 ;
     RECT  7.8 4.501 8.904 5.699 ;
     RECT  12.624 5.075 13.512 6.133 ;
     RECT  17.52 6.133 17.544 6.229 ;
     RECT  18.6 5.557 19.992 6.229 ;
     RECT  14.784 5.653 14.808 6.275 ;
     RECT  16.608 6.229 20.28 6.899 ;
     RECT  7.8 5.699 8.568 7.187 ;
     RECT  16.608 6.899 19.992 7.381 ;
     RECT  16.416 7.381 19.992 7.523 ;
     RECT  11.424 7.381 11.448 8.003 ;
     RECT  12.576 6.133 13.512 8.723 ;
     RECT  16.416 7.523 19.08 8.821 ;
     RECT  14.64 8.533 14.664 8.867 ;
     RECT  9.744 7.189 9.768 8.915 ;
     RECT  16.032 8.821 19.08 9.155 ;
     RECT  16.032 9.155 17.256 9.539 ;
     RECT  22.08 8.533 22.104 9.731 ;
     RECT  16.512 9.539 17.256 9.779 ;
     RECT  12 9.061 12.024 9.923 ;
     RECT  18.432 9.155 19.08 10.021 ;
     RECT  16.944 9.779 17.256 10.355 ;
     RECT  16.992 10.355 17.256 10.403 ;
     RECT  16.992 10.403 17.208 10.451 ;
     RECT  13.008 8.723 13.512 10.693 ;
     RECT  10.08 9.925 10.104 10.883 ;
     RECT  18.432 10.021 20.04 10.883 ;
     RECT  18.432 10.883 19.608 10.931 ;
     RECT  17.088 10.451 17.208 11.459 ;
     RECT  18.432 10.931 19.08 11.459 ;
     RECT  13.008 10.693 13.608 11.555 ;
     RECT  15.888 11.701 15.912 12.083 ;
     RECT  199.824 36.469 199.848 37.669 ;
     RECT  199.824 37.669 200.424 37.717 ;
     RECT  202.2 2.151 202.512 37.717 ;
     RECT  18.6 11.459 18.912 37.861 ;
     RECT  78 2.151 78.312 37.909 ;
     RECT  199.824 37.717 202.512 37.957 ;
     RECT  45.6 2.151 45.912 38.101 ;
     RECT  132 2.151 132.312 38.677 ;
     RECT  114.576 38.485 114.6 38.723 ;
     RECT  15.312 38.533 15.336 38.725 ;
     RECT  17.088 11.459 17.112 38.725 ;
     RECT  142.8 2.151 143.112 38.725 ;
     RECT  15.312 38.725 17.112 39.013 ;
     RECT  15.264 39.013 17.112 39.061 ;
     RECT  199.728 37.957 202.512 39.205 ;
     RECT  67.2 2.151 67.512 39.253 ;
     RECT  137.4 2.151 137.712 39.253 ;
     RECT  15.168 39.061 17.112 39.301 ;
     RECT  18.6 37.861 19.56 39.301 ;
     RECT  20.736 38.725 20.76 39.301 ;
     RECT  115.8 2.151 116.112 39.301 ;
     RECT  132 38.677 132.504 39.541 ;
     RECT  24 2.151 24.312 39.589 ;
     RECT  142.8 38.725 143.352 39.589 ;
     RECT  60.576 39.205 60.6 39.733 ;
     RECT  61.8 2.151 62.112 39.733 ;
     RECT  199.392 39.205 202.512 39.733 ;
     RECT  21.936 39.493 21.96 39.781 ;
     RECT  23.184 39.589 24.312 39.781 ;
     RECT  142.8 39.589 143.64 39.829 ;
     RECT  198.768 39.733 202.512 40.117 ;
     RECT  83.4 2.151 83.712 40.261 ;
     RECT  198.768 40.117 202.968 40.309 ;
     RECT  51 2.151 51.312 40.837 ;
     RECT  21.936 39.781 24.312 40.885 ;
     RECT  18.6 39.301 20.76 40.933 ;
     RECT  15.168 39.301 17.16 41.461 ;
     RECT  18.144 40.933 20.76 41.461 ;
     RECT  15.168 41.461 20.76 41.893 ;
     RECT  21.84 40.885 24.312 41.893 ;
     RECT  198.144 40.309 202.968 41.989 ;
     RECT  121.2 2.151 121.512 42.421 ;
     RECT  198.144 41.989 203.544 42.421 ;
     RECT  15.168 41.893 24.312 42.517 ;
     RECT  198.144 42.421 203.928 42.709 ;
     RECT  94.2 2.151 94.512 42.997 ;
     RECT  132 39.541 132.552 42.997 ;
     RECT  88.8 2.151 89.112 43.045 ;
     RECT  130.896 41.509 130.92 43.045 ;
     RECT  131.904 42.997 132.552 43.045 ;
     RECT  198.096 42.709 203.928 43.237 ;
     RECT  130.896 43.045 132.552 43.525 ;
     RECT  83.4 40.261 84.456 43.813 ;
     RECT  198.096 43.237 204.216 43.861 ;
     RECT  130.896 43.525 132.696 44.053 ;
     RECT  196.8 2.151 197.112 44.053 ;
     RECT  198.096 43.861 204.36 44.053 ;
     RECT  4.944 42.997 4.968 44.149 ;
     RECT  6.192 43.045 6.216 44.149 ;
     RECT  135.648 43.093 135.672 44.197 ;
     RECT  137.4 39.253 138.216 44.197 ;
     RECT  4.944 44.149 6.216 44.341 ;
     RECT  7.8 7.187 8.112 44.437 ;
     RECT  4.848 44.341 6.216 44.869 ;
     RECT  94.2 42.997 95.448 44.965 ;
     RECT  45.6 38.101 46.104 45.301 ;
     RECT  72.6 2.151 72.912 45.445 ;
     RECT  7.8 44.437 8.616 45.493 ;
     RECT  135.648 44.197 138.216 45.493 ;
     RECT  4.752 44.869 6.216 45.541 ;
     RECT  135.648 45.493 138.456 45.635 ;
     RECT  121.2 42.421 121.704 45.733 ;
     RECT  82.032 43.861 82.056 45.781 ;
     RECT  83.28 43.813 84.456 45.781 ;
     RECT  121.104 45.733 121.704 45.875 ;
     RECT  4.752 45.541 6.36 46.213 ;
     RECT  88.8 43.045 89.784 46.213 ;
     RECT  130.896 44.053 133.416 46.309 ;
     RECT  45.6 45.301 46.296 46.453 ;
     RECT  7.68 45.493 8.616 46.501 ;
     RECT  86.64 46.453 86.664 46.501 ;
     RECT  45.6 46.453 46.776 46.643 ;
     RECT  54.72 46.453 54.744 46.643 ;
     RECT  58.704 46.453 58.728 46.643 ;
     RECT  13.008 11.555 13.512 46.645 ;
     RECT  14.736 42.517 24.312 46.645 ;
     RECT  10.944 45.253 10.968 46.835 ;
     RECT  66.864 39.253 67.512 46.837 ;
     RECT  7.536 46.501 8.616 47.075 ;
     RECT  4.656 46.213 6.36 47.269 ;
     RECT  7.536 47.075 8.28 47.269 ;
     RECT  66.864 46.837 67.848 47.795 ;
     RECT  118.56 47.653 118.584 47.795 ;
     RECT  121.2 45.875 121.704 47.845 ;
     RECT  88.8 46.213 90.648 47.891 ;
     RECT  13.008 46.645 24.312 47.987 ;
     RECT  40.2 2.151 40.512 47.989 ;
     RECT  0.144 47.701 0.168 48.083 ;
     RECT  121.104 47.845 121.704 48.085 ;
     RECT  86.448 46.501 86.664 48.133 ;
     RECT  114.576 47.893 114.6 48.133 ;
     RECT  45.6 46.643 46.392 48.179 ;
     RECT  114.576 48.133 114.696 48.179 ;
     RECT  86.448 48.133 86.76 48.275 ;
     RECT  30.864 48.133 30.888 48.419 ;
     RECT  38.784 48.037 38.808 48.419 ;
     RECT  42.864 48.133 42.888 48.419 ;
     RECT  114.672 48.179 114.696 48.419 ;
     RECT  13.008 47.987 13.656 48.421 ;
     RECT  26.784 48.133 26.808 48.467 ;
     RECT  40.2 47.989 41.016 48.469 ;
     RECT  86.448 48.275 86.472 48.469 ;
     RECT  14.736 47.987 24.312 48.517 ;
     RECT  45.6 48.179 46.2 48.563 ;
     RECT  40.2 48.469 41.112 48.611 ;
     RECT  34.8 2.151 35.112 48.613 ;
     RECT  4.656 47.269 8.28 48.661 ;
     RECT  78 37.909 78.648 48.661 ;
     RECT  14.736 48.517 24.408 48.901 ;
     RECT  29.4 2.151 29.712 48.901 ;
     RECT  2.4 2.151 2.712 48.949 ;
     RECT  12.528 48.421 13.656 48.995 ;
     RECT  88.8 47.891 89.784 48.997 ;
     RECT  115.8 39.301 116.568 48.997 ;
     RECT  121.104 48.085 121.8 48.997 ;
     RECT  196.8 44.053 204.36 49.045 ;
     RECT  34.8 48.613 35.352 49.091 ;
     RECT  78 48.661 78.696 49.091 ;
     RECT  82.032 45.781 84.456 49.093 ;
     RECT  85.488 48.469 86.472 49.093 ;
     RECT  82.032 49.093 86.472 49.139 ;
     RECT  88.704 48.997 89.784 49.139 ;
     RECT  115.8 48.997 116.904 49.187 ;
     RECT  120.816 48.997 121.8 49.187 ;
     RECT  40.2 48.611 41.016 49.235 ;
     RECT  130.896 46.309 134.232 49.237 ;
     RECT  82.032 49.139 85.512 49.283 ;
     RECT  120.96 49.187 121.8 49.283 ;
     RECT  60.576 39.733 62.112 49.285 ;
     RECT  130.56 49.237 134.232 49.571 ;
     RECT  130.896 49.571 134.232 49.667 ;
     RECT  14.736 48.901 24.504 49.765 ;
     RECT  45.6 48.563 46.104 49.765 ;
     RECT  101.52 46.837 101.544 49.765 ;
     RECT  2.4 48.949 2.856 49.811 ;
     RECT  80.928 49.381 80.952 49.909 ;
     RECT  99.6 2.151 99.912 49.909 ;
     RECT  101.52 49.765 101.784 49.955 ;
     RECT  4.656 48.661 8.856 49.957 ;
     RECT  48.96 49.525 48.984 50.053 ;
     RECT  4.656 49.957 9.144 50.099 ;
     RECT  44.976 49.765 46.104 50.149 ;
     RECT  14.736 49.765 24.552 50.197 ;
     RECT  80.928 49.909 81 50.197 ;
     RECT  108.288 49.717 108.312 50.197 ;
     RECT  108.288 50.197 108.936 50.243 ;
     RECT  29.4 48.901 29.976 50.245 ;
     RECT  88.8 49.139 89.784 50.293 ;
     RECT  164.4 2.151 164.712 50.293 ;
     RECT  64.992 49.045 65.016 50.339 ;
     RECT  108.72 50.243 108.936 50.339 ;
     RECT  40.2 49.235 40.728 50.341 ;
     RECT  44.976 50.149 46.248 50.341 ;
     RECT  56.4 2.151 56.712 50.341 ;
     RECT  59.232 49.813 59.256 50.341 ;
     RECT  66.864 47.795 67.512 50.341 ;
     RECT  14.736 50.197 25.272 50.387 ;
     RECT  80.688 50.197 81 50.389 ;
     RECT  131.328 49.667 134.232 50.389 ;
     RECT  121.104 49.283 121.8 50.435 ;
     RECT  58.704 50.341 59.256 50.627 ;
     RECT  40.2 50.341 40.824 50.675 ;
     RECT  56.4 50.341 57 50.675 ;
     RECT  48.432 50.053 48.984 50.677 ;
     RECT  50.88 40.837 51.312 50.677 ;
     RECT  142.8 39.829 143.928 50.677 ;
     RECT  29.4 50.245 30.792 50.771 ;
     RECT  44.976 50.341 46.296 50.771 ;
     RECT  82.032 49.283 84.456 50.771 ;
     RECT  85.488 49.283 85.512 50.771 ;
     RECT  94.2 44.965 95.928 50.771 ;
     RECT  97.776 45.541 97.8 50.771 ;
     RECT  101.52 49.955 101.544 50.771 ;
     RECT  108.72 50.339 108.84 50.771 ;
     RECT  122.832 47.557 122.856 50.771 ;
     RECT  124.176 42.469 124.2 50.771 ;
     RECT  94.2 50.771 95.448 50.819 ;
     RECT  72.6 45.445 73.224 50.867 ;
     RECT  88.8 50.293 90.648 50.867 ;
     RECT  94.2 50.819 94.872 50.867 ;
     RECT  115.8 49.187 116.856 50.917 ;
     RECT  48.432 50.677 49.128 50.963 ;
     RECT  121.2 50.435 121.8 50.963 ;
     RECT  71.568 44.293 71.592 50.965 ;
     RECT  72.6 50.867 72.912 50.965 ;
     RECT  99.6 49.909 100.344 50.965 ;
     RECT  14.736 50.387 25.128 51.011 ;
     RECT  60.576 49.285 62.232 51.013 ;
     RECT  63.744 37.957 63.768 51.013 ;
     RECT  78 49.091 78.648 51.013 ;
     RECT  131.328 50.389 134.328 51.013 ;
     RECT  131.328 51.013 134.568 51.107 ;
     RECT  136.464 45.635 138.456 51.109 ;
     RECT  196.8 49.045 204.408 51.109 ;
     RECT  121.2 50.963 121.608 51.155 ;
     RECT  134.304 51.107 134.568 51.203 ;
     RECT  2.4 49.811 2.712 51.253 ;
     RECT  4.656 50.099 8.952 51.253 ;
     RECT  108.72 50.771 108.744 51.299 ;
     RECT  42.768 49.813 42.792 51.301 ;
     RECT  71.568 50.965 72.912 51.301 ;
     RECT  80.448 50.389 81 51.301 ;
     RECT  136.464 51.109 138.552 51.301 ;
     RECT  146.256 44.917 146.28 51.301 ;
     RECT  153.6 2.151 153.912 51.301 ;
     RECT  29.4 50.771 30.696 51.347 ;
     RECT  45.6 50.771 46.296 51.347 ;
     RECT  60.576 51.013 63.768 51.347 ;
     RECT  131.328 51.107 132.6 51.347 ;
     RECT  134.304 51.203 134.328 51.347 ;
     RECT  136.464 51.301 138.6 51.347 ;
     RECT  142.8 50.677 144.216 51.347 ;
     RECT  148.2 2.151 148.512 51.349 ;
     RECT  26.16 50.677 26.184 51.395 ;
     RECT  50.88 50.677 51.72 51.395 ;
     RECT  70.704 51.301 72.912 51.395 ;
     RECT  66.864 50.341 67.608 51.397 ;
     RECT  78 51.013 78.696 51.397 ;
     RECT  105 2.151 105.312 51.397 ;
     RECT  146.112 51.301 146.28 51.397 ;
     RECT  59.232 50.627 59.256 51.443 ;
     RECT  70.704 51.395 71.592 51.443 ;
     RECT  80.352 51.301 81 51.443 ;
     RECT  83.184 50.771 84.456 51.443 ;
     RECT  92.352 48.997 92.376 51.443 ;
     RECT  146.112 51.397 146.52 51.443 ;
     RECT  2.4 51.253 8.952 51.445 ;
     RECT  13.2 48.995 13.656 51.445 ;
     RECT  78 51.397 78.744 51.445 ;
     RECT  99.6 50.965 100.44 51.445 ;
     RECT  70.704 51.443 70.728 51.491 ;
     RECT  98.736 51.445 100.44 51.491 ;
     RECT  137.4 51.347 138.6 51.491 ;
     RECT  148.2 51.349 148.728 51.491 ;
     RECT  153.6 51.301 154.488 51.491 ;
     RECT  12.288 51.445 13.656 51.541 ;
     RECT  42.768 51.301 42.84 51.637 ;
     RECT  66.72 51.397 67.608 51.637 ;
     RECT  56.4 50.675 56.808 51.683 ;
     RECT  88.8 50.867 89.544 51.683 ;
     RECT  144.192 51.347 144.216 51.683 ;
     RECT  11.808 51.541 13.656 51.731 ;
     RECT  48.912 50.963 49.128 51.731 ;
     RECT  60.576 51.347 62.808 51.731 ;
     RECT  83.184 51.443 83.928 51.731 ;
     RECT  82.032 50.771 82.056 51.733 ;
     RECT  83.184 51.731 83.712 51.733 ;
     RECT  24 51.011 25.128 51.779 ;
     RECT  42.624 51.637 42.888 51.779 ;
     RECT  54.72 51.397 54.744 51.779 ;
     RECT  98.736 51.491 99.912 51.779 ;
     RECT  132 51.347 132.6 51.779 ;
     RECT  169.8 2.151 170.112 51.781 ;
     RECT  40.2 50.675 40.776 51.827 ;
     RECT  42.72 51.779 42.888 51.827 ;
     RECT  49.008 51.731 49.128 51.827 ;
     RECT  90.624 50.867 90.648 51.827 ;
     RECT  146.496 51.443 146.52 51.827 ;
     RECT  78 51.445 79.224 51.829 ;
     RECT  115.8 50.917 117 51.829 ;
     RECT  11.808 51.731 11.832 51.875 ;
     RECT  92.688 51.733 92.712 51.875 ;
     RECT  102.624 51.445 102.648 51.875 ;
     RECT  150.48 51.349 150.504 51.875 ;
     RECT  106.656 51.637 106.68 51.923 ;
     RECT  40.2 51.827 40.68 51.971 ;
     RECT  42.72 51.827 42.744 51.971 ;
     RECT  77.904 51.829 79.224 51.971 ;
     RECT  80.976 51.443 81 51.971 ;
     RECT  82.032 51.733 83.712 51.971 ;
     RECT  169.8 51.781 170.472 51.971 ;
     RECT  24 51.779 24.552 52.019 ;
     RECT  29.4 51.347 29.928 52.019 ;
     RECT  49.104 51.827 49.128 52.019 ;
     RECT  115.68 51.829 117 52.019 ;
     RECT  14.736 51.011 22.776 52.069 ;
     RECT  24 52.019 24.312 52.069 ;
     RECT  66.72 51.637 67.848 52.115 ;
     RECT  82.032 51.971 82.392 52.115 ;
     RECT  94.2 50.867 94.68 52.115 ;
     RECT  2.304 51.445 8.952 52.117 ;
     RECT  45.6 51.347 46.248 52.211 ;
     RECT  51 51.395 51.72 52.211 ;
     RECT  0.192 51.829 0.216 52.261 ;
     RECT  2.304 52.117 9.048 52.307 ;
     RECT  82.032 52.115 82.056 52.403 ;
     RECT  13.2 51.731 13.656 52.405 ;
     RECT  14.736 52.069 24.312 52.405 ;
     RECT  44.448 51.829 44.472 52.451 ;
     RECT  52.464 52.261 52.488 52.547 ;
     RECT  75.264 52.405 75.288 52.547 ;
     RECT  105 51.397 105.48 52.547 ;
     RECT  0.192 52.261 0.312 52.549 ;
     RECT  129.984 51.397 130.008 52.549 ;
     RECT  114.576 51.397 114.6 52.595 ;
     RECT  196.656 51.109 204.408 52.597 ;
     RECT  60.576 51.731 60.6 52.643 ;
     RECT  129.984 52.549 130.536 52.643 ;
     RECT  0.192 52.549 0.504 52.693 ;
     RECT  0.144 52.693 0.504 52.837 ;
     RECT  0.144 52.837 0.6 53.075 ;
     RECT  10.608 51.445 10.632 53.171 ;
     RECT  40.2 51.971 40.632 53.171 ;
     RECT  67.2 52.115 67.848 53.171 ;
     RECT  115.8 52.019 117 53.173 ;
     RECT  78 51.971 79.224 53.219 ;
     RECT  130.512 52.643 130.536 53.267 ;
     RECT  58.848 51.733 58.872 53.315 ;
     RECT  61.8 51.731 62.808 53.315 ;
     RECT  115.8 53.173 117.624 53.315 ;
     RECT  51 52.211 51.48 53.363 ;
     RECT  74.064 51.013 74.088 53.411 ;
     RECT  13.2 52.405 24.312 53.603 ;
     RECT  196.08 52.597 204.408 53.603 ;
     RECT  13.2 53.603 13.656 53.651 ;
     RECT  14.736 53.603 24.312 53.651 ;
     RECT  0.144 53.075 0.504 53.747 ;
     RECT  196.656 53.603 204.408 53.843 ;
     RECT  164.4 50.293 165.576 53.891 ;
     RECT  196.8 53.843 204.408 54.083 ;
     RECT  13.2 53.651 13.512 54.085 ;
     RECT  14.736 53.651 22.824 54.131 ;
     RECT  205.488 45.205 205.512 54.133 ;
     RECT  205.488 54.133 205.656 54.179 ;
     RECT  0.192 53.747 0.504 54.419 ;
     RECT  205.632 54.179 205.656 54.563 ;
     RECT  207.6 2.151 207.912 54.757 ;
     RECT  206.688 54.757 207.912 54.947 ;
     RECT  209.904 54.757 209.928 54.995 ;
     RECT  14.736 54.131 22.776 55.093 ;
     RECT  0.192 54.419 0.408 55.141 ;
     RECT  14.736 55.093 22.824 55.283 ;
     RECT  2.304 52.307 8.328 55.379 ;
     RECT  0.144 55.141 0.408 55.619 ;
     RECT  13.104 54.085 13.512 55.715 ;
     RECT  209.184 55.141 209.208 55.955 ;
     RECT  0.192 55.619 0.408 56.005 ;
     RECT  0.192 56.005 0.456 56.195 ;
     RECT  2.4 55.379 8.328 56.195 ;
     RECT  209.76 56.341 209.784 56.965 ;
     RECT  2.4 56.195 8.28 57.155 ;
     RECT  0.24 56.195 0.408 57.157 ;
     RECT  209.76 56.965 210.696 57.299 ;
     RECT  2.4 57.155 3.912 57.541 ;
     RECT  213 2.151 213.312 57.541 ;
     RECT  214.656 57.013 214.68 57.541 ;
     RECT  196.8 54.083 204.36 57.635 ;
     RECT  14.736 55.283 22.728 57.779 ;
     RECT  0.192 57.157 0.408 58.163 ;
     RECT  213 57.541 214.68 58.453 ;
     RECT  0.192 58.163 0.36 58.501 ;
     RECT  213 58.453 215.064 58.643 ;
     RECT  210.672 57.299 210.696 58.645 ;
     RECT  214.32 58.643 214.824 58.835 ;
     RECT  207.6 54.947 207.912 58.981 ;
     RECT  2.304 57.541 3.912 59.173 ;
     RECT  217.728 58.885 217.752 59.365 ;
     RECT  4.992 57.155 8.28 59.555 ;
     RECT  0.144 58.501 0.36 59.603 ;
     RECT  214.32 58.835 214.728 59.603 ;
     RECT  217.488 59.365 217.752 59.603 ;
     RECT  2.304 59.173 3.96 59.605 ;
     RECT  4.992 59.555 8.112 59.605 ;
     RECT  0.192 59.603 0.36 59.653 ;
     RECT  214.704 59.603 214.728 59.747 ;
     RECT  210.144 58.645 210.696 59.795 ;
     RECT  217.728 59.603 217.752 59.891 ;
     RECT  0.192 59.653 0.408 60.325 ;
     RECT  206.928 58.981 207.912 60.469 ;
     RECT  210.672 59.795 210.696 60.515 ;
     RECT  196.8 57.635 204.312 61.043 ;
     RECT  206.928 60.469 208.344 61.139 ;
     RECT  0.192 60.325 0.552 61.429 ;
     RECT  196.8 61.043 204.216 61.619 ;
     RECT  0.144 61.429 0.552 61.715 ;
     RECT  14.736 57.779 22.68 62.051 ;
     RECT  2.304 59.605 8.112 62.195 ;
     RECT  2.304 62.195 6.264 62.771 ;
     RECT  211.392 62.293 211.416 63.107 ;
     RECT  196.8 61.619 203.784 63.155 ;
     RECT  0.144 61.715 0.36 63.251 ;
     RECT  210.288 62.677 210.312 63.347 ;
     RECT  0.144 63.251 0.264 63.731 ;
     RECT  198.384 63.155 203.784 63.731 ;
     RECT  2.304 62.771 5.688 63.781 ;
     RECT  207.6 61.139 208.344 63.781 ;
     RECT  14.784 62.051 22.68 63.925 ;
     RECT  198.48 63.731 203.784 64.019 ;
     RECT  14.784 63.925 22.824 64.115 ;
     RECT  198.72 64.019 203.784 64.403 ;
     RECT  206.928 63.781 208.344 64.595 ;
     RECT  2.304 63.781 6.264 64.597 ;
     RECT  7.392 62.195 8.112 64.597 ;
     RECT  14.784 64.115 22.68 64.933 ;
     RECT  0.144 63.731 0.216 65.027 ;
     RECT  2.304 64.597 8.112 65.027 ;
     RECT  198.96 64.403 203.784 65.363 ;
     RECT  0.144 65.027 0.168 65.603 ;
     RECT  2.304 65.027 5.4 65.651 ;
     RECT  14.736 64.933 22.68 65.939 ;
     RECT  207.6 64.595 208.344 66.085 ;
     RECT  6.864 65.027 8.112 66.131 ;
     RECT  2.4 65.651 5.4 66.179 ;
     RECT  2.4 66.179 4.536 66.755 ;
     RECT  2.4 66.755 3.912 66.803 ;
     RECT  14.784 65.939 22.68 66.995 ;
     RECT  207.504 66.085 208.344 67.141 ;
     RECT  213 58.643 213.312 67.141 ;
     RECT  207.504 67.141 209.16 67.187 ;
     RECT  14.784 66.995 22.632 67.283 ;
     RECT  199.296 65.363 203.784 67.283 ;
     RECT  21.792 67.283 22.632 67.475 ;
     RECT  207.504 67.187 207.912 67.859 ;
     RECT  212.256 67.141 213.312 67.859 ;
     RECT  209.136 67.187 209.16 68.341 ;
     RECT  201.36 67.283 203.784 68.435 ;
     RECT  14.784 67.283 20.76 68.483 ;
     RECT  14.784 68.483 15.72 69.347 ;
     RECT  220.128 69.205 220.152 69.395 ;
     RECT  219.12 68.389 219.144 69.445 ;
     RECT  209.088 68.341 209.16 69.493 ;
     RECT  209.088 69.493 209.256 69.587 ;
     RECT  21.792 67.475 22.584 70.067 ;
     RECT  16.848 68.483 20.76 70.163 ;
     RECT  214.32 69.925 214.344 70.163 ;
     RECT  219.12 69.445 220.104 70.163 ;
     RECT  213 67.859 213.312 70.261 ;
     RECT  209.136 69.587 209.256 70.739 ;
     RECT  14.784 69.347 14.808 70.979 ;
     RECT  20.736 70.163 20.76 71.843 ;
     RECT  22.56 70.067 22.584 71.891 ;
     RECT  219.12 70.163 219.144 71.939 ;
     RECT  16.848 70.163 19.752 72.419 ;
     RECT  18 72.419 19.752 72.707 ;
     RECT  199.296 67.283 200.328 72.755 ;
     RECT  16.848 72.419 16.872 72.851 ;
     RECT  201.552 68.435 203.784 73.331 ;
     RECT  201.792 73.331 203.784 73.571 ;
     RECT  212.016 70.261 213.312 73.763 ;
     RECT  201.792 73.571 203.256 73.811 ;
     RECT  202.2 73.811 203.256 74.387 ;
     RECT  217.536 74.341 217.56 74.531 ;
     RECT  209.136 70.739 209.16 74.725 ;
     RECT  208.992 74.725 209.16 75.251 ;
     RECT  16.272 75.157 16.296 75.827 ;
     RECT  212.88 73.763 213.312 76.021 ;
     RECT  209.136 75.251 209.16 76.403 ;
     RECT  7.104 66.131 8.112 76.979 ;
     RECT  212.736 76.021 213.312 77.075 ;
     RECT  18 72.707 19.56 78.035 ;
     RECT  18.096 78.035 19.56 78.131 ;
     RECT  2.4 66.803 2.712 78.517 ;
     RECT  0.384 78.469 0.408 78.613 ;
     RECT  2.4 78.517 3.672 78.613 ;
     RECT  18.096 78.131 19.368 78.707 ;
     RECT  0.384 78.613 0.936 78.709 ;
     RECT  2.4 78.613 4.248 78.949 ;
     RECT  2.304 78.949 4.248 79.141 ;
     RECT  0.288 78.709 0.936 79.189 ;
     RECT  16.512 78.661 16.536 79.235 ;
     RECT  18.6 78.707 19.368 79.475 ;
     RECT  2.304 79.141 4.632 79.621 ;
     RECT  0.192 79.189 0.936 80.149 ;
     RECT  6.048 79.621 6.072 80.149 ;
     RECT  7.392 76.979 8.112 80.149 ;
     RECT  2.304 79.621 5.016 80.293 ;
     RECT  6.048 80.149 8.112 80.293 ;
     RECT  0.192 80.149 1.08 80.341 ;
     RECT  2.304 80.293 8.112 81.109 ;
     RECT  2.256 81.109 8.112 82.597 ;
     RECT  0.144 80.341 1.08 82.691 ;
     RECT  2.256 82.597 8.856 83.507 ;
     RECT  0.144 82.691 1.032 84.275 ;
     RECT  0.144 84.275 0.696 84.515 ;
     RECT  0.192 84.515 0.696 84.947 ;
     RECT  22.8 85.477 22.824 85.763 ;
     RECT  0.192 84.947 0.6 85.861 ;
     RECT  0.144 85.861 0.6 86.099 ;
     RECT  2.256 83.507 8.232 86.147 ;
     RECT  2.304 86.147 8.232 86.243 ;
     RECT  2.304 86.243 8.112 88.309 ;
     RECT  2.304 88.309 8.232 88.741 ;
     RECT  2.304 88.741 9.096 88.885 ;
     RECT  2.304 88.885 9.672 88.979 ;
     RECT  0.144 86.099 0.552 89.219 ;
     RECT  7.392 88.979 9.672 89.459 ;
     RECT  7.392 89.459 9.096 89.555 ;
     RECT  0.144 89.219 0.504 90.277 ;
     RECT  10.848 90.085 10.872 90.323 ;
     RECT  2.304 88.979 6.264 90.325 ;
     RECT  7.392 89.555 8.112 90.325 ;
     RECT  2.304 90.325 8.112 90.659 ;
     RECT  0.144 90.277 1.128 91.427 ;
     RECT  21.072 91.237 21.096 91.427 ;
     RECT  2.304 90.659 4.536 91.621 ;
     RECT  5.568 90.659 8.112 91.621 ;
     RECT  2.304 91.621 8.112 93.011 ;
     RECT  2.4 93.011 8.112 93.397 ;
     RECT  9.648 92.917 9.672 93.397 ;
     RECT  2.4 93.397 9.672 94.021 ;
     RECT  2.304 94.021 9.672 94.115 ;
     RECT  0.144 91.427 0.84 94.453 ;
     RECT  2.304 94.115 9.096 94.691 ;
     RECT  199.296 72.755 200.04 94.691 ;
     RECT  0.144 94.453 0.888 95.365 ;
     RECT  0.144 95.365 1.128 97.619 ;
     RECT  2.304 94.691 8.112 97.667 ;
     RECT  2.4 97.667 8.112 98.675 ;
     RECT  0.144 97.619 0.552 98.819 ;
     RECT  0.144 98.819 0.504 98.915 ;
     RECT  2.4 98.675 6.264 98.915 ;
     RECT  0.144 98.915 0.264 99.203 ;
     RECT  2.4 98.915 5.832 99.251 ;
     RECT  2.4 99.251 4.776 99.347 ;
     RECT  2.4 99.347 4.488 99.395 ;
     RECT  0.144 99.203 0.168 99.779 ;
     RECT  2.4 99.395 4.296 99.827 ;
     RECT  3.744 99.827 4.296 99.875 ;
     RECT  4.032 99.875 4.296 99.971 ;
     RECT  196.8 63.155 197.112 105.061 ;
     RECT  199.296 94.691 199.944 107.795 ;
     RECT  199.824 107.795 199.944 108.323 ;
     RECT  199.92 108.323 199.944 111.779 ;
     RECT  5.808 99.251 5.832 131.603 ;
     RECT  4.032 99.971 4.056 133.235 ;
     RECT  196.8 105.061 197.736 141.299 ;
     RECT  2.4 99.827 2.712 174.969 ;
     RECT  7.8 98.675 8.112 174.969 ;
     RECT  13.2 55.715 13.512 174.969 ;
     RECT  18.6 79.475 18.912 174.969 ;
     RECT  24 53.651 24.312 174.969 ;
     RECT  29.4 52.019 29.712 174.969 ;
     RECT  34.8 49.091 35.112 174.969 ;
     RECT  40.2 53.171 40.512 174.969 ;
     RECT  45.6 52.211 45.912 174.969 ;
     RECT  51 53.363 51.312 174.969 ;
     RECT  56.4 51.683 56.712 174.969 ;
     RECT  61.8 53.315 62.112 174.969 ;
     RECT  67.2 53.171 67.512 174.969 ;
     RECT  72.6 51.395 72.912 174.969 ;
     RECT  78 53.219 78.312 174.969 ;
     RECT  83.4 51.971 83.712 174.969 ;
     RECT  88.8 51.683 89.112 174.969 ;
     RECT  94.2 52.115 94.512 174.969 ;
     RECT  99.6 51.779 99.912 174.969 ;
     RECT  105 52.547 105.312 174.969 ;
     RECT  110.4 2.151 110.712 174.969 ;
     RECT  115.8 53.315 116.112 174.969 ;
     RECT  121.2 51.155 121.512 174.969 ;
     RECT  126.6 2.151 126.912 174.969 ;
     RECT  132 51.779 132.312 174.969 ;
     RECT  137.4 51.491 137.712 174.969 ;
     RECT  142.8 51.347 143.112 174.969 ;
     RECT  148.2 51.491 148.512 174.969 ;
     RECT  153.6 51.491 153.912 174.969 ;
     RECT  159 2.151 159.312 174.969 ;
     RECT  164.4 53.891 164.712 174.969 ;
     RECT  169.8 51.971 170.112 174.969 ;
     RECT  175.2 2.151 175.512 174.969 ;
     RECT  180.6 2.151 180.912 174.969 ;
     RECT  186 2.151 186.312 174.969 ;
     RECT  191.4 2.151 191.712 174.969 ;
     RECT  196.8 141.299 197.112 174.969 ;
     RECT  202.2 74.387 202.512 174.969 ;
     RECT  207.6 67.859 207.912 174.969 ;
     RECT  213 77.075 213.312 174.969 ;
     RECT  2.4 174.969 2.52 174.983 ;
     RECT  7.8 174.969 7.92 174.983 ;
     RECT  13.2 174.969 13.32 174.983 ;
     RECT  18.6 174.969 18.72 174.983 ;
     RECT  24 174.969 24.12 174.983 ;
     RECT  29.4 174.969 29.52 174.983 ;
     RECT  34.8 174.969 34.92 174.983 ;
     RECT  40.2 174.969 40.32 174.983 ;
     RECT  45.6 174.969 45.72 174.983 ;
     RECT  51 174.969 51.12 174.983 ;
     RECT  56.4 174.969 56.52 174.983 ;
     RECT  61.8 174.969 61.92 174.983 ;
     RECT  67.2 174.969 67.32 174.983 ;
     RECT  72.6 174.969 72.72 174.983 ;
     RECT  78 174.969 78.12 174.983 ;
     RECT  83.4 174.969 83.52 174.983 ;
     RECT  88.8 174.969 88.92 174.983 ;
     RECT  94.2 174.969 94.32 174.983 ;
     RECT  99.6 174.969 99.72 174.983 ;
     RECT  105 174.969 105.12 174.983 ;
     RECT  110.4 174.969 110.52 174.983 ;
     RECT  115.8 174.969 115.92 174.983 ;
     RECT  121.2 174.969 121.32 174.983 ;
     RECT  126.6 174.969 126.72 174.983 ;
     RECT  132 174.969 132.12 174.983 ;
     RECT  137.4 174.969 137.52 174.983 ;
     RECT  142.8 174.969 142.92 174.983 ;
     RECT  148.2 174.969 148.32 174.983 ;
     RECT  153.6 174.969 153.72 174.983 ;
     RECT  159 174.969 159.12 174.983 ;
     RECT  164.4 174.969 164.52 174.983 ;
     RECT  169.8 174.969 169.92 174.983 ;
     RECT  175.2 174.969 175.32 174.983 ;
     RECT  180.6 174.969 180.72 174.983 ;
     RECT  186 174.969 186.12 174.983 ;
     RECT  191.4 174.969 191.52 174.983 ;
     RECT  196.8 174.969 196.92 174.983 ;
     RECT  202.2 174.969 202.32 174.983 ;
     RECT  207.6 174.969 207.72 174.983 ;
     RECT  213 174.969 213.12 174.983 ;
     RECT  12.576 5.075 12.624 6.133 ;
     RECT  18.912 5.365 19.968 5.557 ;
     RECT  13.512 5.653 14.784 6.275 ;
     RECT  17.544 6.133 18.6 6.229 ;
     RECT  11.448 7.381 12.576 8.003 ;
     RECT  12 8.003 12.576 8.723 ;
     RECT  13.512 8.533 14.64 8.867 ;
     RECT  12 8.723 13.008 9.061 ;
     RECT  14.664 8.821 16.032 8.867 ;
     RECT  12.024 9.061 13.008 9.923 ;
     RECT  17.256 9.155 18.432 10.403 ;
     RECT  16.944 10.355 16.992 10.451 ;
     RECT  17.208 10.403 18.432 11.459 ;
     RECT  16.944 10.451 17.088 11.701 ;
     RECT  17.112 11.459 18.6 39.301 ;
     RECT  15.912 11.701 17.088 12.083 ;
     RECT  114.6 38.485 115.8 38.723 ;
     RECT  19.56 38.725 20.736 39.301 ;
     RECT  60.6 39.205 61.8 39.733 ;
     RECT  17.16 39.301 18.6 40.933 ;
     RECT  20.76 39.493 21.936 40.885 ;
     RECT  21.96 39.589 23.184 39.781 ;
     RECT  197.112 40.309 198.144 42.709 ;
     RECT  20.76 40.885 21.84 41.893 ;
     RECT  17.16 40.933 18.144 41.461 ;
     RECT  130.92 41.509 132 42.997 ;
     RECT  13.512 42.517 14.736 46.645 ;
     RECT  197.112 42.709 198.096 44.053 ;
     RECT  130.92 42.997 131.904 43.045 ;
     RECT  4.968 43.045 6.192 44.149 ;
     RECT  82.056 43.861 83.28 45.781 ;
     RECT  71.592 44.293 72.6 50.965 ;
     RECT  204.36 45.205 205.488 49.045 ;
     RECT  6.216 45.493 7.68 45.541 ;
     RECT  6.36 45.541 7.68 46.501 ;
     RECT  6.36 46.501 7.536 47.269 ;
     RECT  121.704 47.557 122.832 48.085 ;
     RECT  122.856 47.557 124.176 50.771 ;
     RECT  114.6 47.893 115.8 48.133 ;
     RECT  13.656 47.987 14.736 52.405 ;
     RECT  38.808 48.037 40.2 48.419 ;
     RECT  121.8 48.085 122.832 50.771 ;
     RECT  29.712 48.133 30.864 48.419 ;
     RECT  114.696 48.133 115.8 48.419 ;
     RECT  29.712 48.419 29.976 48.901 ;
     RECT  84.456 48.469 85.488 49.093 ;
     RECT  63.768 49.045 64.992 50.339 ;
     RECT  204.408 49.045 205.488 54.083 ;
     RECT  40.728 49.235 40.824 50.341 ;
     RECT  84.456 49.283 85.488 50.771 ;
     RECT  62.232 49.285 63.744 51.013 ;
     RECT  80.952 49.381 82.032 49.909 ;
     RECT  2.712 49.811 2.856 51.253 ;
     RECT  59.256 49.813 60.576 51.443 ;
     RECT  81 49.909 82.032 51.971 ;
     RECT  100.344 49.909 101.52 50.771 ;
     RECT  108.936 50.197 110.4 50.339 ;
     RECT  25.128 50.387 25.272 50.677 ;
     RECT  58.848 50.627 59.232 51.443 ;
     RECT  25.128 50.677 26.16 51.395 ;
     RECT  44.976 50.771 45.6 51.829 ;
     RECT  82.056 50.771 83.184 51.733 ;
     RECT  100.344 50.771 100.44 50.965 ;
     RECT  72.912 50.867 73.224 51.013 ;
     RECT  89.544 50.867 90.624 51.683 ;
     RECT  22.776 51.011 24 52.069 ;
     RECT  72.912 51.013 74.064 53.411 ;
     RECT  131.328 51.347 132 51.397 ;
     RECT  143.112 51.347 144.192 51.683 ;
     RECT  71.592 51.395 72.6 51.443 ;
     RECT  114.6 51.397 115.8 51.829 ;
     RECT  130.008 51.397 132 52.549 ;
     RECT  58.848 51.443 58.872 51.733 ;
     RECT  10.632 51.541 11.808 51.875 ;
     RECT  105.48 51.637 106.656 51.923 ;
     RECT  89.112 51.683 90.624 51.827 ;
     RECT  11.832 51.731 13.2 51.875 ;
     RECT  60.6 51.731 61.8 52.643 ;
     RECT  92.712 51.733 94.2 51.875 ;
     RECT  44.472 51.829 45.6 52.451 ;
     RECT  114.6 51.829 115.68 52.019 ;
     RECT  82.392 51.971 83.4 52.115 ;
     RECT  114.6 52.019 115.8 52.595 ;
     RECT  82.056 52.115 83.4 52.403 ;
     RECT  51.48 52.211 51.72 52.261 ;
     RECT  51.48 52.261 52.464 52.547 ;
     RECT  74.088 52.405 75.264 52.547 ;
     RECT  130.536 52.549 132 53.267 ;
     RECT  13.656 53.603 14.736 53.651 ;
     RECT  13.512 53.651 14.736 62.051 ;
     RECT  22.824 53.651 24 54.131 ;
     RECT  0.144 53.747 0.192 55.141 ;
     RECT  204.36 54.083 205.488 54.179 ;
     RECT  22.776 54.131 24 55.093 ;
     RECT  204.36 54.179 205.632 54.563 ;
     RECT  22.824 55.093 24 55.283 ;
     RECT  207.912 55.141 209.184 55.955 ;
     RECT  22.728 55.283 24 57.779 ;
     RECT  0.192 56.195 0.24 57.157 ;
     RECT  213.312 57.013 214.656 57.541 ;
     RECT  3.912 57.155 4.992 59.173 ;
     RECT  210.144 57.299 210.672 58.645 ;
     RECT  22.68 57.779 24 63.925 ;
     RECT  0.36 58.163 0.408 59.653 ;
     RECT  213.312 58.643 214.32 59.603 ;
     RECT  3.96 59.173 4.992 59.605 ;
     RECT  213.312 59.603 214.704 59.747 ;
     RECT  13.512 62.051 14.784 64.933 ;
     RECT  6.264 62.195 7.392 62.771 ;
     RECT  210.312 62.677 211.392 63.107 ;
     RECT  5.688 62.771 7.392 63.781 ;
     RECT  197.112 63.155 198.384 63.731 ;
     RECT  197.112 63.731 198.48 64.019 ;
     RECT  6.264 63.781 7.392 64.597 ;
     RECT  22.824 63.925 24 64.115 ;
     RECT  22.68 64.115 24 66.995 ;
     RECT  207.504 64.595 207.6 66.085 ;
     RECT  13.512 64.933 14.736 65.939 ;
     RECT  5.4 65.027 6.864 66.131 ;
     RECT  13.512 65.939 14.784 70.979 ;
     RECT  22.632 66.995 24 67.475 ;
     RECT  207.912 67.187 209.136 68.341 ;
     RECT  20.76 67.283 21.792 70.067 ;
     RECT  200.328 67.283 201.36 68.435 ;
     RECT  22.584 67.475 24 71.891 ;
     RECT  207.912 68.341 209.088 69.587 ;
     RECT  200.328 68.435 201.552 72.755 ;
     RECT  15.72 68.483 16.848 69.347 ;
     RECT  219.144 69.205 220.128 69.395 ;
     RECT  219.144 69.395 220.104 69.445 ;
     RECT  207.912 69.587 209.136 74.725 ;
     RECT  213.312 69.925 214.32 70.163 ;
     RECT  19.752 70.163 20.736 71.843 ;
     RECT  16.872 72.419 18 72.851 ;
     RECT  200.04 72.755 201.552 73.331 ;
     RECT  207.912 74.725 208.992 75.251 ;
     RECT  207.912 75.251 209.136 76.403 ;
     RECT  0.936 78.613 2.4 78.949 ;
     RECT  0.936 78.949 2.304 80.149 ;
     RECT  5.016 79.621 6.048 80.293 ;
     RECT  6.072 79.621 7.392 80.149 ;
     RECT  1.08 80.149 2.304 81.109 ;
     RECT  1.08 81.109 2.256 82.691 ;
     RECT  1.032 82.691 2.256 84.275 ;
     RECT  0.144 84.515 0.192 85.861 ;
     RECT  22.824 85.477 24 85.763 ;
     RECT  6.264 88.979 7.392 90.325 ;
     RECT  0.504 89.219 0.552 90.277 ;
     RECT  1.128 90.277 2.304 91.427 ;
     RECT  4.536 90.659 5.568 91.621 ;
     RECT  0.84 91.427 2.304 93.011 ;
     RECT  0.84 93.011 2.4 94.021 ;
     RECT  0.84 94.021 2.304 94.453 ;
     RECT  0.888 94.453 2.304 95.365 ;
     RECT  1.128 95.365 2.304 97.619 ;
     RECT  4.776 99.251 5.808 99.347 ;
     RECT  4.488 99.347 5.808 99.395 ;
     RECT  4.296 99.395 5.808 99.971 ;
     RECT  2.712 99.827 3.744 99.875 ;
     RECT  2.712 99.875 4.032 133.235 ;
  END
END hfd_hgi_vm_calendar_NW
END LIBRARY
